VERSION 5.7 ;
  NOWIREEXTENSIONATPIN ON ;
  DIVIDERCHAR "/" ;
  BUSBITCHARS "[]" ;
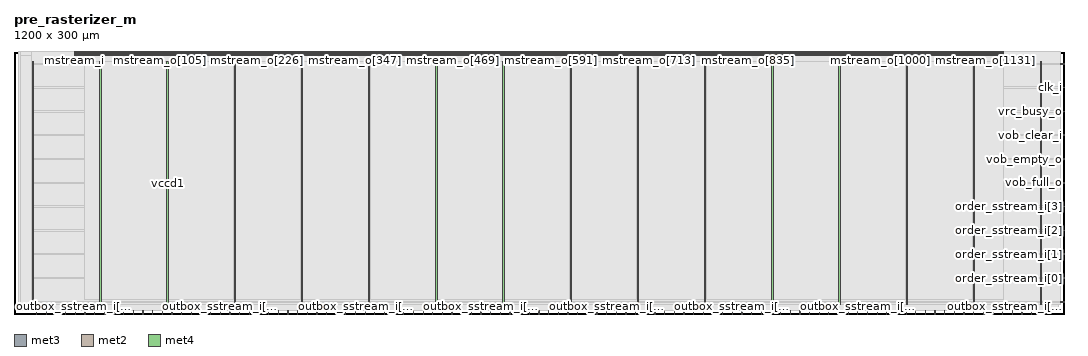
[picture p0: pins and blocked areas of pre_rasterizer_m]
MACRO pre_rasterizer_m
  CLASS BLOCK ;
  FOREIGN pre_rasterizer_m ;
  ORIGIN 0.000 0.000 ;
  SIZE 1200.000 BY 300.000 ;
  PIN clk_i
    DIRECTION INPUT ;
    USE SIGNAL ;
    ANTENNAGATEAREA 0.852000 ;
    ANTENNADIFFAREA 0.434700 ;
    PORT
      LAYER met3 ;
        RECT 1196.000 258.440 1200.000 259.040 ;
    END
  END clk_i
  PIN mstream_i
    DIRECTION INPUT ;
    USE SIGNAL ;
    ANTENNAGATEAREA 0.426000 ;
    PORT
      LAYER met2 ;
        RECT 69.090 296.000 69.370 300.000 ;
    END
  END mstream_i
  PIN mstream_o[0]
    DIRECTION OUTPUT TRISTATE ;
    USE SIGNAL ;
    ANTENNADIFFAREA 0.795200 ;
    PORT
      LAYER met2 ;
        RECT 70.010 296.000 70.290 300.000 ;
    END
  END mstream_o[0]
  PIN mstream_o[1000]
    DIRECTION OUTPUT TRISTATE ;
    USE SIGNAL ;
    ANTENNADIFFAREA 0.795200 ;
    PORT
      LAYER met2 ;
        RECT 990.010 296.000 990.290 300.000 ;
    END
  END mstream_o[1000]
  PIN mstream_o[1001]
    DIRECTION OUTPUT TRISTATE ;
    USE SIGNAL ;
    ANTENNADIFFAREA 0.795200 ;
    PORT
      LAYER met2 ;
        RECT 990.930 296.000 991.210 300.000 ;
    END
  END mstream_o[1001]
  PIN mstream_o[1002]
    DIRECTION OUTPUT TRISTATE ;
    USE SIGNAL ;
    ANTENNADIFFAREA 0.795200 ;
    PORT
      LAYER met2 ;
        RECT 991.850 296.000 992.130 300.000 ;
    END
  END mstream_o[1002]
  PIN mstream_o[1003]
    DIRECTION OUTPUT TRISTATE ;
    USE SIGNAL ;
    ANTENNADIFFAREA 0.795200 ;
    PORT
      LAYER met2 ;
        RECT 992.770 296.000 993.050 300.000 ;
    END
  END mstream_o[1003]
  PIN mstream_o[1004]
    DIRECTION OUTPUT TRISTATE ;
    USE SIGNAL ;
    ANTENNADIFFAREA 0.795200 ;
    PORT
      LAYER met2 ;
        RECT 993.690 296.000 993.970 300.000 ;
    END
  END mstream_o[1004]
  PIN mstream_o[1005]
    DIRECTION OUTPUT TRISTATE ;
    USE SIGNAL ;
    ANTENNADIFFAREA 0.795200 ;
    PORT
      LAYER met2 ;
        RECT 994.610 296.000 994.890 300.000 ;
    END
  END mstream_o[1005]
  PIN mstream_o[1006]
    DIRECTION OUTPUT TRISTATE ;
    USE SIGNAL ;
    ANTENNADIFFAREA 0.795200 ;
    PORT
      LAYER met2 ;
        RECT 995.530 296.000 995.810 300.000 ;
    END
  END mstream_o[1006]
  PIN mstream_o[1007]
    DIRECTION OUTPUT TRISTATE ;
    USE SIGNAL ;
    ANTENNADIFFAREA 0.795200 ;
    PORT
      LAYER met2 ;
        RECT 996.450 296.000 996.730 300.000 ;
    END
  END mstream_o[1007]
  PIN mstream_o[1008]
    DIRECTION OUTPUT TRISTATE ;
    USE SIGNAL ;
    ANTENNADIFFAREA 0.795200 ;
    PORT
      LAYER met2 ;
        RECT 997.370 296.000 997.650 300.000 ;
    END
  END mstream_o[1008]
  PIN mstream_o[1009]
    DIRECTION OUTPUT TRISTATE ;
    USE SIGNAL ;
    ANTENNADIFFAREA 0.795200 ;
    PORT
      LAYER met2 ;
        RECT 998.290 296.000 998.570 300.000 ;
    END
  END mstream_o[1009]
  PIN mstream_o[100]
    DIRECTION OUTPUT TRISTATE ;
    USE SIGNAL ;
    ANTENNADIFFAREA 0.795200 ;
    PORT
      LAYER met2 ;
        RECT 162.010 296.000 162.290 300.000 ;
    END
  END mstream_o[100]
  PIN mstream_o[1010]
    DIRECTION OUTPUT TRISTATE ;
    USE SIGNAL ;
    ANTENNADIFFAREA 0.795200 ;
    PORT
      LAYER met2 ;
        RECT 999.210 296.000 999.490 300.000 ;
    END
  END mstream_o[1010]
  PIN mstream_o[1011]
    DIRECTION OUTPUT TRISTATE ;
    USE SIGNAL ;
    ANTENNADIFFAREA 0.795200 ;
    PORT
      LAYER met2 ;
        RECT 1000.130 296.000 1000.410 300.000 ;
    END
  END mstream_o[1011]
  PIN mstream_o[1012]
    DIRECTION OUTPUT TRISTATE ;
    USE SIGNAL ;
    ANTENNADIFFAREA 0.795200 ;
    PORT
      LAYER met2 ;
        RECT 1001.050 296.000 1001.330 300.000 ;
    END
  END mstream_o[1012]
  PIN mstream_o[1013]
    DIRECTION OUTPUT TRISTATE ;
    USE SIGNAL ;
    ANTENNADIFFAREA 0.795200 ;
    PORT
      LAYER met2 ;
        RECT 1001.970 296.000 1002.250 300.000 ;
    END
  END mstream_o[1013]
  PIN mstream_o[1014]
    DIRECTION OUTPUT TRISTATE ;
    USE SIGNAL ;
    ANTENNADIFFAREA 0.795200 ;
    PORT
      LAYER met2 ;
        RECT 1002.890 296.000 1003.170 300.000 ;
    END
  END mstream_o[1014]
  PIN mstream_o[1015]
    DIRECTION OUTPUT TRISTATE ;
    USE SIGNAL ;
    ANTENNADIFFAREA 0.795200 ;
    PORT
      LAYER met2 ;
        RECT 1003.810 296.000 1004.090 300.000 ;
    END
  END mstream_o[1015]
  PIN mstream_o[1016]
    DIRECTION OUTPUT TRISTATE ;
    USE SIGNAL ;
    ANTENNADIFFAREA 0.795200 ;
    PORT
      LAYER met2 ;
        RECT 1004.730 296.000 1005.010 300.000 ;
    END
  END mstream_o[1016]
  PIN mstream_o[1017]
    DIRECTION OUTPUT TRISTATE ;
    USE SIGNAL ;
    ANTENNADIFFAREA 0.795200 ;
    PORT
      LAYER met2 ;
        RECT 1005.650 296.000 1005.930 300.000 ;
    END
  END mstream_o[1017]
  PIN mstream_o[1018]
    DIRECTION OUTPUT TRISTATE ;
    USE SIGNAL ;
    ANTENNADIFFAREA 0.795200 ;
    PORT
      LAYER met2 ;
        RECT 1006.570 296.000 1006.850 300.000 ;
    END
  END mstream_o[1018]
  PIN mstream_o[1019]
    DIRECTION OUTPUT TRISTATE ;
    USE SIGNAL ;
    ANTENNADIFFAREA 0.795200 ;
    PORT
      LAYER met2 ;
        RECT 1007.490 296.000 1007.770 300.000 ;
    END
  END mstream_o[1019]
  PIN mstream_o[101]
    DIRECTION OUTPUT TRISTATE ;
    USE SIGNAL ;
    ANTENNADIFFAREA 0.795200 ;
    PORT
      LAYER met2 ;
        RECT 162.930 296.000 163.210 300.000 ;
    END
  END mstream_o[101]
  PIN mstream_o[1020]
    DIRECTION OUTPUT TRISTATE ;
    USE SIGNAL ;
    ANTENNADIFFAREA 0.795200 ;
    PORT
      LAYER met2 ;
        RECT 1008.410 296.000 1008.690 300.000 ;
    END
  END mstream_o[1020]
  PIN mstream_o[1021]
    DIRECTION OUTPUT TRISTATE ;
    USE SIGNAL ;
    ANTENNADIFFAREA 0.795200 ;
    PORT
      LAYER met2 ;
        RECT 1009.330 296.000 1009.610 300.000 ;
    END
  END mstream_o[1021]
  PIN mstream_o[1022]
    DIRECTION OUTPUT TRISTATE ;
    USE SIGNAL ;
    ANTENNADIFFAREA 0.795200 ;
    PORT
      LAYER met2 ;
        RECT 1010.250 296.000 1010.530 300.000 ;
    END
  END mstream_o[1022]
  PIN mstream_o[1023]
    DIRECTION OUTPUT TRISTATE ;
    USE SIGNAL ;
    ANTENNADIFFAREA 0.795200 ;
    PORT
      LAYER met2 ;
        RECT 1011.170 296.000 1011.450 300.000 ;
    END
  END mstream_o[1023]
  PIN mstream_o[1024]
    DIRECTION OUTPUT TRISTATE ;
    USE SIGNAL ;
    ANTENNADIFFAREA 0.795200 ;
    PORT
      LAYER met2 ;
        RECT 1012.090 296.000 1012.370 300.000 ;
    END
  END mstream_o[1024]
  PIN mstream_o[1025]
    DIRECTION OUTPUT TRISTATE ;
    USE SIGNAL ;
    ANTENNADIFFAREA 0.795200 ;
    PORT
      LAYER met2 ;
        RECT 1013.010 296.000 1013.290 300.000 ;
    END
  END mstream_o[1025]
  PIN mstream_o[1026]
    DIRECTION OUTPUT TRISTATE ;
    USE SIGNAL ;
    ANTENNADIFFAREA 0.795200 ;
    PORT
      LAYER met2 ;
        RECT 1013.930 296.000 1014.210 300.000 ;
    END
  END mstream_o[1026]
  PIN mstream_o[1027]
    DIRECTION OUTPUT TRISTATE ;
    USE SIGNAL ;
    ANTENNADIFFAREA 0.795200 ;
    PORT
      LAYER met2 ;
        RECT 1014.850 296.000 1015.130 300.000 ;
    END
  END mstream_o[1027]
  PIN mstream_o[1028]
    DIRECTION OUTPUT TRISTATE ;
    USE SIGNAL ;
    ANTENNADIFFAREA 0.795200 ;
    PORT
      LAYER met2 ;
        RECT 1015.770 296.000 1016.050 300.000 ;
    END
  END mstream_o[1028]
  PIN mstream_o[1029]
    DIRECTION OUTPUT TRISTATE ;
    USE SIGNAL ;
    ANTENNADIFFAREA 0.795200 ;
    PORT
      LAYER met2 ;
        RECT 1016.690 296.000 1016.970 300.000 ;
    END
  END mstream_o[1029]
  PIN mstream_o[102]
    DIRECTION OUTPUT TRISTATE ;
    USE SIGNAL ;
    ANTENNADIFFAREA 0.795200 ;
    PORT
      LAYER met2 ;
        RECT 163.850 296.000 164.130 300.000 ;
    END
  END mstream_o[102]
  PIN mstream_o[1030]
    DIRECTION OUTPUT TRISTATE ;
    USE SIGNAL ;
    ANTENNADIFFAREA 0.795200 ;
    PORT
      LAYER met2 ;
        RECT 1017.610 296.000 1017.890 300.000 ;
    END
  END mstream_o[1030]
  PIN mstream_o[1031]
    DIRECTION OUTPUT TRISTATE ;
    USE SIGNAL ;
    ANTENNADIFFAREA 0.795200 ;
    PORT
      LAYER met2 ;
        RECT 1018.530 296.000 1018.810 300.000 ;
    END
  END mstream_o[1031]
  PIN mstream_o[1032]
    DIRECTION OUTPUT TRISTATE ;
    USE SIGNAL ;
    ANTENNADIFFAREA 0.795200 ;
    PORT
      LAYER met2 ;
        RECT 1019.450 296.000 1019.730 300.000 ;
    END
  END mstream_o[1032]
  PIN mstream_o[1033]
    DIRECTION OUTPUT TRISTATE ;
    USE SIGNAL ;
    ANTENNADIFFAREA 0.795200 ;
    PORT
      LAYER met2 ;
        RECT 1020.370 296.000 1020.650 300.000 ;
    END
  END mstream_o[1033]
  PIN mstream_o[1034]
    DIRECTION OUTPUT TRISTATE ;
    USE SIGNAL ;
    ANTENNADIFFAREA 0.795200 ;
    PORT
      LAYER met2 ;
        RECT 1021.290 296.000 1021.570 300.000 ;
    END
  END mstream_o[1034]
  PIN mstream_o[1035]
    DIRECTION OUTPUT TRISTATE ;
    USE SIGNAL ;
    ANTENNADIFFAREA 0.795200 ;
    PORT
      LAYER met2 ;
        RECT 1022.210 296.000 1022.490 300.000 ;
    END
  END mstream_o[1035]
  PIN mstream_o[1036]
    DIRECTION OUTPUT TRISTATE ;
    USE SIGNAL ;
    ANTENNADIFFAREA 0.795200 ;
    PORT
      LAYER met2 ;
        RECT 1023.130 296.000 1023.410 300.000 ;
    END
  END mstream_o[1036]
  PIN mstream_o[1037]
    DIRECTION OUTPUT TRISTATE ;
    USE SIGNAL ;
    ANTENNADIFFAREA 0.795200 ;
    PORT
      LAYER met2 ;
        RECT 1024.050 296.000 1024.330 300.000 ;
    END
  END mstream_o[1037]
  PIN mstream_o[1038]
    DIRECTION OUTPUT TRISTATE ;
    USE SIGNAL ;
    ANTENNADIFFAREA 0.795200 ;
    PORT
      LAYER met2 ;
        RECT 1024.970 296.000 1025.250 300.000 ;
    END
  END mstream_o[1038]
  PIN mstream_o[1039]
    DIRECTION OUTPUT TRISTATE ;
    USE SIGNAL ;
    ANTENNADIFFAREA 0.795200 ;
    PORT
      LAYER met2 ;
        RECT 1025.890 296.000 1026.170 300.000 ;
    END
  END mstream_o[1039]
  PIN mstream_o[103]
    DIRECTION OUTPUT TRISTATE ;
    USE SIGNAL ;
    ANTENNADIFFAREA 0.795200 ;
    PORT
      LAYER met2 ;
        RECT 164.770 296.000 165.050 300.000 ;
    END
  END mstream_o[103]
  PIN mstream_o[1040]
    DIRECTION OUTPUT TRISTATE ;
    USE SIGNAL ;
    ANTENNADIFFAREA 0.795200 ;
    PORT
      LAYER met2 ;
        RECT 1026.810 296.000 1027.090 300.000 ;
    END
  END mstream_o[1040]
  PIN mstream_o[1041]
    DIRECTION OUTPUT TRISTATE ;
    USE SIGNAL ;
    ANTENNADIFFAREA 0.795200 ;
    PORT
      LAYER met2 ;
        RECT 1027.730 296.000 1028.010 300.000 ;
    END
  END mstream_o[1041]
  PIN mstream_o[1042]
    DIRECTION OUTPUT TRISTATE ;
    USE SIGNAL ;
    ANTENNADIFFAREA 0.795200 ;
    PORT
      LAYER met2 ;
        RECT 1028.650 296.000 1028.930 300.000 ;
    END
  END mstream_o[1042]
  PIN mstream_o[1043]
    DIRECTION OUTPUT TRISTATE ;
    USE SIGNAL ;
    ANTENNADIFFAREA 0.795200 ;
    PORT
      LAYER met2 ;
        RECT 1029.570 296.000 1029.850 300.000 ;
    END
  END mstream_o[1043]
  PIN mstream_o[1044]
    DIRECTION OUTPUT TRISTATE ;
    USE SIGNAL ;
    ANTENNADIFFAREA 0.795200 ;
    PORT
      LAYER met2 ;
        RECT 1030.490 296.000 1030.770 300.000 ;
    END
  END mstream_o[1044]
  PIN mstream_o[1045]
    DIRECTION OUTPUT TRISTATE ;
    USE SIGNAL ;
    ANTENNADIFFAREA 0.795200 ;
    PORT
      LAYER met2 ;
        RECT 1031.410 296.000 1031.690 300.000 ;
    END
  END mstream_o[1045]
  PIN mstream_o[1046]
    DIRECTION OUTPUT TRISTATE ;
    USE SIGNAL ;
    ANTENNADIFFAREA 0.795200 ;
    PORT
      LAYER met2 ;
        RECT 1032.330 296.000 1032.610 300.000 ;
    END
  END mstream_o[1046]
  PIN mstream_o[1047]
    DIRECTION OUTPUT TRISTATE ;
    USE SIGNAL ;
    ANTENNADIFFAREA 0.795200 ;
    PORT
      LAYER met2 ;
        RECT 1033.250 296.000 1033.530 300.000 ;
    END
  END mstream_o[1047]
  PIN mstream_o[1048]
    DIRECTION OUTPUT TRISTATE ;
    USE SIGNAL ;
    ANTENNADIFFAREA 0.795200 ;
    PORT
      LAYER met2 ;
        RECT 1034.170 296.000 1034.450 300.000 ;
    END
  END mstream_o[1048]
  PIN mstream_o[1049]
    DIRECTION OUTPUT TRISTATE ;
    USE SIGNAL ;
    ANTENNADIFFAREA 0.795200 ;
    PORT
      LAYER met2 ;
        RECT 1035.090 296.000 1035.370 300.000 ;
    END
  END mstream_o[1049]
  PIN mstream_o[104]
    DIRECTION OUTPUT TRISTATE ;
    USE SIGNAL ;
    ANTENNADIFFAREA 0.795200 ;
    PORT
      LAYER met2 ;
        RECT 165.690 296.000 165.970 300.000 ;
    END
  END mstream_o[104]
  PIN mstream_o[1050]
    DIRECTION OUTPUT TRISTATE ;
    USE SIGNAL ;
    ANTENNADIFFAREA 0.795200 ;
    PORT
      LAYER met2 ;
        RECT 1036.010 296.000 1036.290 300.000 ;
    END
  END mstream_o[1050]
  PIN mstream_o[1051]
    DIRECTION OUTPUT TRISTATE ;
    USE SIGNAL ;
    ANTENNADIFFAREA 0.795200 ;
    PORT
      LAYER met2 ;
        RECT 1036.930 296.000 1037.210 300.000 ;
    END
  END mstream_o[1051]
  PIN mstream_o[1052]
    DIRECTION OUTPUT TRISTATE ;
    USE SIGNAL ;
    ANTENNADIFFAREA 0.795200 ;
    PORT
      LAYER met2 ;
        RECT 1037.850 296.000 1038.130 300.000 ;
    END
  END mstream_o[1052]
  PIN mstream_o[1053]
    DIRECTION OUTPUT TRISTATE ;
    USE SIGNAL ;
    ANTENNADIFFAREA 0.795200 ;
    PORT
      LAYER met2 ;
        RECT 1038.770 296.000 1039.050 300.000 ;
    END
  END mstream_o[1053]
  PIN mstream_o[1054]
    DIRECTION OUTPUT TRISTATE ;
    USE SIGNAL ;
    ANTENNADIFFAREA 0.795200 ;
    PORT
      LAYER met2 ;
        RECT 1039.690 296.000 1039.970 300.000 ;
    END
  END mstream_o[1054]
  PIN mstream_o[1055]
    DIRECTION OUTPUT TRISTATE ;
    USE SIGNAL ;
    ANTENNADIFFAREA 0.795200 ;
    PORT
      LAYER met2 ;
        RECT 1040.610 296.000 1040.890 300.000 ;
    END
  END mstream_o[1055]
  PIN mstream_o[1056]
    DIRECTION OUTPUT TRISTATE ;
    USE SIGNAL ;
    ANTENNADIFFAREA 0.795200 ;
    PORT
      LAYER met2 ;
        RECT 1041.530 296.000 1041.810 300.000 ;
    END
  END mstream_o[1056]
  PIN mstream_o[1057]
    DIRECTION OUTPUT TRISTATE ;
    USE SIGNAL ;
    ANTENNADIFFAREA 0.795200 ;
    PORT
      LAYER met2 ;
        RECT 1042.450 296.000 1042.730 300.000 ;
    END
  END mstream_o[1057]
  PIN mstream_o[1058]
    DIRECTION OUTPUT TRISTATE ;
    USE SIGNAL ;
    ANTENNADIFFAREA 0.795200 ;
    PORT
      LAYER met2 ;
        RECT 1043.370 296.000 1043.650 300.000 ;
    END
  END mstream_o[1058]
  PIN mstream_o[1059]
    DIRECTION OUTPUT TRISTATE ;
    USE SIGNAL ;
    ANTENNADIFFAREA 0.795200 ;
    PORT
      LAYER met2 ;
        RECT 1044.290 296.000 1044.570 300.000 ;
    END
  END mstream_o[1059]
  PIN mstream_o[105]
    DIRECTION OUTPUT TRISTATE ;
    USE SIGNAL ;
    ANTENNADIFFAREA 0.795200 ;
    PORT
      LAYER met2 ;
        RECT 166.610 296.000 166.890 300.000 ;
    END
  END mstream_o[105]
  PIN mstream_o[1060]
    DIRECTION OUTPUT TRISTATE ;
    USE SIGNAL ;
    ANTENNADIFFAREA 0.795200 ;
    PORT
      LAYER met2 ;
        RECT 1045.210 296.000 1045.490 300.000 ;
    END
  END mstream_o[1060]
  PIN mstream_o[1061]
    DIRECTION OUTPUT TRISTATE ;
    USE SIGNAL ;
    ANTENNADIFFAREA 0.795200 ;
    PORT
      LAYER met2 ;
        RECT 1046.130 296.000 1046.410 300.000 ;
    END
  END mstream_o[1061]
  PIN mstream_o[1062]
    DIRECTION OUTPUT TRISTATE ;
    USE SIGNAL ;
    ANTENNADIFFAREA 0.795200 ;
    PORT
      LAYER met2 ;
        RECT 1047.050 296.000 1047.330 300.000 ;
    END
  END mstream_o[1062]
  PIN mstream_o[1063]
    DIRECTION OUTPUT TRISTATE ;
    USE SIGNAL ;
    ANTENNADIFFAREA 0.795200 ;
    PORT
      LAYER met2 ;
        RECT 1047.970 296.000 1048.250 300.000 ;
    END
  END mstream_o[1063]
  PIN mstream_o[1064]
    DIRECTION OUTPUT TRISTATE ;
    USE SIGNAL ;
    ANTENNADIFFAREA 0.795200 ;
    PORT
      LAYER met2 ;
        RECT 1048.890 296.000 1049.170 300.000 ;
    END
  END mstream_o[1064]
  PIN mstream_o[1065]
    DIRECTION OUTPUT TRISTATE ;
    USE SIGNAL ;
    ANTENNADIFFAREA 0.795200 ;
    PORT
      LAYER met2 ;
        RECT 1049.810 296.000 1050.090 300.000 ;
    END
  END mstream_o[1065]
  PIN mstream_o[1066]
    DIRECTION OUTPUT TRISTATE ;
    USE SIGNAL ;
    ANTENNADIFFAREA 0.795200 ;
    PORT
      LAYER met2 ;
        RECT 1050.730 296.000 1051.010 300.000 ;
    END
  END mstream_o[1066]
  PIN mstream_o[1067]
    DIRECTION OUTPUT TRISTATE ;
    USE SIGNAL ;
    ANTENNADIFFAREA 0.795200 ;
    PORT
      LAYER met2 ;
        RECT 1051.650 296.000 1051.930 300.000 ;
    END
  END mstream_o[1067]
  PIN mstream_o[1068]
    DIRECTION OUTPUT TRISTATE ;
    USE SIGNAL ;
    ANTENNADIFFAREA 0.795200 ;
    PORT
      LAYER met2 ;
        RECT 1052.570 296.000 1052.850 300.000 ;
    END
  END mstream_o[1068]
  PIN mstream_o[1069]
    DIRECTION OUTPUT TRISTATE ;
    USE SIGNAL ;
    ANTENNADIFFAREA 0.795200 ;
    PORT
      LAYER met2 ;
        RECT 1053.490 296.000 1053.770 300.000 ;
    END
  END mstream_o[1069]
  PIN mstream_o[106]
    DIRECTION OUTPUT TRISTATE ;
    USE SIGNAL ;
    ANTENNADIFFAREA 0.795200 ;
    PORT
      LAYER met2 ;
        RECT 167.530 296.000 167.810 300.000 ;
    END
  END mstream_o[106]
  PIN mstream_o[1070]
    DIRECTION OUTPUT TRISTATE ;
    USE SIGNAL ;
    ANTENNADIFFAREA 0.795200 ;
    PORT
      LAYER met2 ;
        RECT 1054.410 296.000 1054.690 300.000 ;
    END
  END mstream_o[1070]
  PIN mstream_o[1071]
    DIRECTION OUTPUT TRISTATE ;
    USE SIGNAL ;
    ANTENNADIFFAREA 0.795200 ;
    PORT
      LAYER met2 ;
        RECT 1055.330 296.000 1055.610 300.000 ;
    END
  END mstream_o[1071]
  PIN mstream_o[1072]
    DIRECTION OUTPUT TRISTATE ;
    USE SIGNAL ;
    ANTENNADIFFAREA 0.795200 ;
    PORT
      LAYER met2 ;
        RECT 1056.250 296.000 1056.530 300.000 ;
    END
  END mstream_o[1072]
  PIN mstream_o[1073]
    DIRECTION OUTPUT TRISTATE ;
    USE SIGNAL ;
    ANTENNADIFFAREA 0.795200 ;
    PORT
      LAYER met2 ;
        RECT 1057.170 296.000 1057.450 300.000 ;
    END
  END mstream_o[1073]
  PIN mstream_o[1074]
    DIRECTION OUTPUT TRISTATE ;
    USE SIGNAL ;
    ANTENNADIFFAREA 0.795200 ;
    PORT
      LAYER met2 ;
        RECT 1058.090 296.000 1058.370 300.000 ;
    END
  END mstream_o[1074]
  PIN mstream_o[1075]
    DIRECTION OUTPUT TRISTATE ;
    USE SIGNAL ;
    ANTENNADIFFAREA 0.795200 ;
    PORT
      LAYER met2 ;
        RECT 1059.010 296.000 1059.290 300.000 ;
    END
  END mstream_o[1075]
  PIN mstream_o[1076]
    DIRECTION OUTPUT TRISTATE ;
    USE SIGNAL ;
    ANTENNADIFFAREA 0.795200 ;
    PORT
      LAYER met2 ;
        RECT 1059.930 296.000 1060.210 300.000 ;
    END
  END mstream_o[1076]
  PIN mstream_o[1077]
    DIRECTION OUTPUT TRISTATE ;
    USE SIGNAL ;
    ANTENNADIFFAREA 0.795200 ;
    PORT
      LAYER met2 ;
        RECT 1060.850 296.000 1061.130 300.000 ;
    END
  END mstream_o[1077]
  PIN mstream_o[1078]
    DIRECTION OUTPUT TRISTATE ;
    USE SIGNAL ;
    ANTENNADIFFAREA 0.795200 ;
    PORT
      LAYER met2 ;
        RECT 1061.770 296.000 1062.050 300.000 ;
    END
  END mstream_o[1078]
  PIN mstream_o[1079]
    DIRECTION OUTPUT TRISTATE ;
    USE SIGNAL ;
    ANTENNADIFFAREA 0.795200 ;
    PORT
      LAYER met2 ;
        RECT 1062.690 296.000 1062.970 300.000 ;
    END
  END mstream_o[1079]
  PIN mstream_o[107]
    DIRECTION OUTPUT TRISTATE ;
    USE SIGNAL ;
    ANTENNADIFFAREA 0.795200 ;
    PORT
      LAYER met2 ;
        RECT 168.450 296.000 168.730 300.000 ;
    END
  END mstream_o[107]
  PIN mstream_o[1080]
    DIRECTION OUTPUT TRISTATE ;
    USE SIGNAL ;
    ANTENNADIFFAREA 0.795200 ;
    PORT
      LAYER met2 ;
        RECT 1063.610 296.000 1063.890 300.000 ;
    END
  END mstream_o[1080]
  PIN mstream_o[1081]
    DIRECTION OUTPUT TRISTATE ;
    USE SIGNAL ;
    ANTENNADIFFAREA 0.795200 ;
    PORT
      LAYER met2 ;
        RECT 1064.530 296.000 1064.810 300.000 ;
    END
  END mstream_o[1081]
  PIN mstream_o[1082]
    DIRECTION OUTPUT TRISTATE ;
    USE SIGNAL ;
    ANTENNADIFFAREA 0.795200 ;
    PORT
      LAYER met2 ;
        RECT 1065.450 296.000 1065.730 300.000 ;
    END
  END mstream_o[1082]
  PIN mstream_o[1083]
    DIRECTION OUTPUT TRISTATE ;
    USE SIGNAL ;
    ANTENNADIFFAREA 0.795200 ;
    PORT
      LAYER met2 ;
        RECT 1066.370 296.000 1066.650 300.000 ;
    END
  END mstream_o[1083]
  PIN mstream_o[1084]
    DIRECTION OUTPUT TRISTATE ;
    USE SIGNAL ;
    ANTENNADIFFAREA 0.795200 ;
    PORT
      LAYER met2 ;
        RECT 1067.290 296.000 1067.570 300.000 ;
    END
  END mstream_o[1084]
  PIN mstream_o[1085]
    DIRECTION OUTPUT TRISTATE ;
    USE SIGNAL ;
    ANTENNADIFFAREA 0.795200 ;
    PORT
      LAYER met2 ;
        RECT 1068.210 296.000 1068.490 300.000 ;
    END
  END mstream_o[1085]
  PIN mstream_o[1086]
    DIRECTION OUTPUT TRISTATE ;
    USE SIGNAL ;
    ANTENNADIFFAREA 0.795200 ;
    PORT
      LAYER met2 ;
        RECT 1069.130 296.000 1069.410 300.000 ;
    END
  END mstream_o[1086]
  PIN mstream_o[1087]
    DIRECTION OUTPUT TRISTATE ;
    USE SIGNAL ;
    ANTENNADIFFAREA 0.795200 ;
    PORT
      LAYER met2 ;
        RECT 1070.050 296.000 1070.330 300.000 ;
    END
  END mstream_o[1087]
  PIN mstream_o[1088]
    DIRECTION OUTPUT TRISTATE ;
    USE SIGNAL ;
    ANTENNADIFFAREA 0.795200 ;
    PORT
      LAYER met2 ;
        RECT 1070.970 296.000 1071.250 300.000 ;
    END
  END mstream_o[1088]
  PIN mstream_o[1089]
    DIRECTION OUTPUT TRISTATE ;
    USE SIGNAL ;
    ANTENNADIFFAREA 0.795200 ;
    PORT
      LAYER met2 ;
        RECT 1071.890 296.000 1072.170 300.000 ;
    END
  END mstream_o[1089]
  PIN mstream_o[108]
    DIRECTION OUTPUT TRISTATE ;
    USE SIGNAL ;
    ANTENNADIFFAREA 0.795200 ;
    PORT
      LAYER met2 ;
        RECT 169.370 296.000 169.650 300.000 ;
    END
  END mstream_o[108]
  PIN mstream_o[1090]
    DIRECTION OUTPUT TRISTATE ;
    USE SIGNAL ;
    ANTENNADIFFAREA 0.795200 ;
    PORT
      LAYER met2 ;
        RECT 1072.810 296.000 1073.090 300.000 ;
    END
  END mstream_o[1090]
  PIN mstream_o[1091]
    DIRECTION OUTPUT TRISTATE ;
    USE SIGNAL ;
    ANTENNADIFFAREA 0.795200 ;
    PORT
      LAYER met2 ;
        RECT 1073.730 296.000 1074.010 300.000 ;
    END
  END mstream_o[1091]
  PIN mstream_o[1092]
    DIRECTION OUTPUT TRISTATE ;
    USE SIGNAL ;
    ANTENNADIFFAREA 0.795200 ;
    PORT
      LAYER met2 ;
        RECT 1074.650 296.000 1074.930 300.000 ;
    END
  END mstream_o[1092]
  PIN mstream_o[1093]
    DIRECTION OUTPUT TRISTATE ;
    USE SIGNAL ;
    ANTENNADIFFAREA 0.795200 ;
    PORT
      LAYER met2 ;
        RECT 1075.570 296.000 1075.850 300.000 ;
    END
  END mstream_o[1093]
  PIN mstream_o[1094]
    DIRECTION OUTPUT TRISTATE ;
    USE SIGNAL ;
    ANTENNADIFFAREA 0.795200 ;
    PORT
      LAYER met2 ;
        RECT 1076.490 296.000 1076.770 300.000 ;
    END
  END mstream_o[1094]
  PIN mstream_o[1095]
    DIRECTION OUTPUT TRISTATE ;
    USE SIGNAL ;
    ANTENNADIFFAREA 0.795200 ;
    PORT
      LAYER met2 ;
        RECT 1077.410 296.000 1077.690 300.000 ;
    END
  END mstream_o[1095]
  PIN mstream_o[1096]
    DIRECTION OUTPUT TRISTATE ;
    USE SIGNAL ;
    ANTENNADIFFAREA 0.795200 ;
    PORT
      LAYER met2 ;
        RECT 1078.330 296.000 1078.610 300.000 ;
    END
  END mstream_o[1096]
  PIN mstream_o[1097]
    DIRECTION OUTPUT TRISTATE ;
    USE SIGNAL ;
    ANTENNADIFFAREA 0.795200 ;
    PORT
      LAYER met2 ;
        RECT 1079.250 296.000 1079.530 300.000 ;
    END
  END mstream_o[1097]
  PIN mstream_o[1098]
    DIRECTION OUTPUT TRISTATE ;
    USE SIGNAL ;
    ANTENNADIFFAREA 0.795200 ;
    PORT
      LAYER met2 ;
        RECT 1080.170 296.000 1080.450 300.000 ;
    END
  END mstream_o[1098]
  PIN mstream_o[1099]
    DIRECTION OUTPUT TRISTATE ;
    USE SIGNAL ;
    ANTENNADIFFAREA 0.795200 ;
    PORT
      LAYER met2 ;
        RECT 1081.090 296.000 1081.370 300.000 ;
    END
  END mstream_o[1099]
  PIN mstream_o[109]
    DIRECTION OUTPUT TRISTATE ;
    USE SIGNAL ;
    ANTENNADIFFAREA 0.795200 ;
    PORT
      LAYER met2 ;
        RECT 170.290 296.000 170.570 300.000 ;
    END
  END mstream_o[109]
  PIN mstream_o[10]
    DIRECTION OUTPUT TRISTATE ;
    USE SIGNAL ;
    ANTENNADIFFAREA 0.795200 ;
    PORT
      LAYER met2 ;
        RECT 79.210 296.000 79.490 300.000 ;
    END
  END mstream_o[10]
  PIN mstream_o[1100]
    DIRECTION OUTPUT TRISTATE ;
    USE SIGNAL ;
    ANTENNADIFFAREA 0.795200 ;
    PORT
      LAYER met2 ;
        RECT 1082.010 296.000 1082.290 300.000 ;
    END
  END mstream_o[1100]
  PIN mstream_o[1101]
    DIRECTION OUTPUT TRISTATE ;
    USE SIGNAL ;
    ANTENNADIFFAREA 0.795200 ;
    PORT
      LAYER met2 ;
        RECT 1082.930 296.000 1083.210 300.000 ;
    END
  END mstream_o[1101]
  PIN mstream_o[1102]
    DIRECTION OUTPUT TRISTATE ;
    USE SIGNAL ;
    ANTENNADIFFAREA 0.795200 ;
    PORT
      LAYER met2 ;
        RECT 1083.850 296.000 1084.130 300.000 ;
    END
  END mstream_o[1102]
  PIN mstream_o[1103]
    DIRECTION OUTPUT TRISTATE ;
    USE SIGNAL ;
    ANTENNADIFFAREA 0.795200 ;
    PORT
      LAYER met2 ;
        RECT 1084.770 296.000 1085.050 300.000 ;
    END
  END mstream_o[1103]
  PIN mstream_o[1104]
    DIRECTION OUTPUT TRISTATE ;
    USE SIGNAL ;
    ANTENNADIFFAREA 0.795200 ;
    PORT
      LAYER met2 ;
        RECT 1085.690 296.000 1085.970 300.000 ;
    END
  END mstream_o[1104]
  PIN mstream_o[1105]
    DIRECTION OUTPUT TRISTATE ;
    USE SIGNAL ;
    ANTENNADIFFAREA 0.795200 ;
    PORT
      LAYER met2 ;
        RECT 1086.610 296.000 1086.890 300.000 ;
    END
  END mstream_o[1105]
  PIN mstream_o[1106]
    DIRECTION OUTPUT TRISTATE ;
    USE SIGNAL ;
    ANTENNADIFFAREA 0.795200 ;
    PORT
      LAYER met2 ;
        RECT 1087.530 296.000 1087.810 300.000 ;
    END
  END mstream_o[1106]
  PIN mstream_o[1107]
    DIRECTION OUTPUT TRISTATE ;
    USE SIGNAL ;
    ANTENNADIFFAREA 0.795200 ;
    PORT
      LAYER met2 ;
        RECT 1088.450 296.000 1088.730 300.000 ;
    END
  END mstream_o[1107]
  PIN mstream_o[1108]
    DIRECTION OUTPUT TRISTATE ;
    USE SIGNAL ;
    ANTENNADIFFAREA 0.795200 ;
    PORT
      LAYER met2 ;
        RECT 1089.370 296.000 1089.650 300.000 ;
    END
  END mstream_o[1108]
  PIN mstream_o[1109]
    DIRECTION OUTPUT TRISTATE ;
    USE SIGNAL ;
    ANTENNADIFFAREA 0.795200 ;
    PORT
      LAYER met2 ;
        RECT 1090.290 296.000 1090.570 300.000 ;
    END
  END mstream_o[1109]
  PIN mstream_o[110]
    DIRECTION OUTPUT TRISTATE ;
    USE SIGNAL ;
    ANTENNADIFFAREA 0.795200 ;
    PORT
      LAYER met2 ;
        RECT 171.210 296.000 171.490 300.000 ;
    END
  END mstream_o[110]
  PIN mstream_o[1110]
    DIRECTION OUTPUT TRISTATE ;
    USE SIGNAL ;
    ANTENNADIFFAREA 0.795200 ;
    PORT
      LAYER met2 ;
        RECT 1091.210 296.000 1091.490 300.000 ;
    END
  END mstream_o[1110]
  PIN mstream_o[1111]
    DIRECTION OUTPUT TRISTATE ;
    USE SIGNAL ;
    ANTENNADIFFAREA 0.795200 ;
    PORT
      LAYER met2 ;
        RECT 1092.130 296.000 1092.410 300.000 ;
    END
  END mstream_o[1111]
  PIN mstream_o[1112]
    DIRECTION OUTPUT TRISTATE ;
    USE SIGNAL ;
    ANTENNADIFFAREA 0.795200 ;
    PORT
      LAYER met2 ;
        RECT 1093.050 296.000 1093.330 300.000 ;
    END
  END mstream_o[1112]
  PIN mstream_o[1113]
    DIRECTION OUTPUT TRISTATE ;
    USE SIGNAL ;
    ANTENNADIFFAREA 0.795200 ;
    PORT
      LAYER met2 ;
        RECT 1093.970 296.000 1094.250 300.000 ;
    END
  END mstream_o[1113]
  PIN mstream_o[1114]
    DIRECTION OUTPUT TRISTATE ;
    USE SIGNAL ;
    ANTENNADIFFAREA 0.795200 ;
    PORT
      LAYER met2 ;
        RECT 1094.890 296.000 1095.170 300.000 ;
    END
  END mstream_o[1114]
  PIN mstream_o[1115]
    DIRECTION OUTPUT TRISTATE ;
    USE SIGNAL ;
    ANTENNADIFFAREA 0.795200 ;
    PORT
      LAYER met2 ;
        RECT 1095.810 296.000 1096.090 300.000 ;
    END
  END mstream_o[1115]
  PIN mstream_o[1116]
    DIRECTION OUTPUT TRISTATE ;
    USE SIGNAL ;
    ANTENNADIFFAREA 0.795200 ;
    PORT
      LAYER met2 ;
        RECT 1096.730 296.000 1097.010 300.000 ;
    END
  END mstream_o[1116]
  PIN mstream_o[1117]
    DIRECTION OUTPUT TRISTATE ;
    USE SIGNAL ;
    ANTENNADIFFAREA 0.795200 ;
    PORT
      LAYER met2 ;
        RECT 1097.650 296.000 1097.930 300.000 ;
    END
  END mstream_o[1117]
  PIN mstream_o[1118]
    DIRECTION OUTPUT TRISTATE ;
    USE SIGNAL ;
    ANTENNADIFFAREA 0.795200 ;
    PORT
      LAYER met2 ;
        RECT 1098.570 296.000 1098.850 300.000 ;
    END
  END mstream_o[1118]
  PIN mstream_o[1119]
    DIRECTION OUTPUT TRISTATE ;
    USE SIGNAL ;
    ANTENNADIFFAREA 0.795200 ;
    PORT
      LAYER met2 ;
        RECT 1099.490 296.000 1099.770 300.000 ;
    END
  END mstream_o[1119]
  PIN mstream_o[111]
    DIRECTION OUTPUT TRISTATE ;
    USE SIGNAL ;
    ANTENNADIFFAREA 0.795200 ;
    PORT
      LAYER met2 ;
        RECT 172.130 296.000 172.410 300.000 ;
    END
  END mstream_o[111]
  PIN mstream_o[1120]
    DIRECTION OUTPUT TRISTATE ;
    USE SIGNAL ;
    ANTENNADIFFAREA 0.795200 ;
    PORT
      LAYER met2 ;
        RECT 1100.410 296.000 1100.690 300.000 ;
    END
  END mstream_o[1120]
  PIN mstream_o[1121]
    DIRECTION OUTPUT TRISTATE ;
    USE SIGNAL ;
    ANTENNADIFFAREA 0.795200 ;
    PORT
      LAYER met2 ;
        RECT 1101.330 296.000 1101.610 300.000 ;
    END
  END mstream_o[1121]
  PIN mstream_o[1122]
    DIRECTION OUTPUT TRISTATE ;
    USE SIGNAL ;
    ANTENNADIFFAREA 0.795200 ;
    PORT
      LAYER met2 ;
        RECT 1102.250 296.000 1102.530 300.000 ;
    END
  END mstream_o[1122]
  PIN mstream_o[1123]
    DIRECTION OUTPUT TRISTATE ;
    USE SIGNAL ;
    ANTENNADIFFAREA 0.795200 ;
    PORT
      LAYER met2 ;
        RECT 1103.170 296.000 1103.450 300.000 ;
    END
  END mstream_o[1123]
  PIN mstream_o[1124]
    DIRECTION OUTPUT TRISTATE ;
    USE SIGNAL ;
    ANTENNADIFFAREA 0.795200 ;
    PORT
      LAYER met2 ;
        RECT 1104.090 296.000 1104.370 300.000 ;
    END
  END mstream_o[1124]
  PIN mstream_o[1125]
    DIRECTION OUTPUT TRISTATE ;
    USE SIGNAL ;
    ANTENNADIFFAREA 0.795200 ;
    PORT
      LAYER met2 ;
        RECT 1105.010 296.000 1105.290 300.000 ;
    END
  END mstream_o[1125]
  PIN mstream_o[1126]
    DIRECTION OUTPUT TRISTATE ;
    USE SIGNAL ;
    ANTENNADIFFAREA 0.795200 ;
    PORT
      LAYER met2 ;
        RECT 1105.930 296.000 1106.210 300.000 ;
    END
  END mstream_o[1126]
  PIN mstream_o[1127]
    DIRECTION OUTPUT TRISTATE ;
    USE SIGNAL ;
    ANTENNADIFFAREA 0.795200 ;
    PORT
      LAYER met2 ;
        RECT 1106.850 296.000 1107.130 300.000 ;
    END
  END mstream_o[1127]
  PIN mstream_o[1128]
    DIRECTION OUTPUT TRISTATE ;
    USE SIGNAL ;
    ANTENNADIFFAREA 0.795200 ;
    PORT
      LAYER met2 ;
        RECT 1107.770 296.000 1108.050 300.000 ;
    END
  END mstream_o[1128]
  PIN mstream_o[1129]
    DIRECTION OUTPUT TRISTATE ;
    USE SIGNAL ;
    ANTENNADIFFAREA 0.795200 ;
    PORT
      LAYER met2 ;
        RECT 1108.690 296.000 1108.970 300.000 ;
    END
  END mstream_o[1129]
  PIN mstream_o[112]
    DIRECTION OUTPUT TRISTATE ;
    USE SIGNAL ;
    ANTENNADIFFAREA 0.795200 ;
    PORT
      LAYER met2 ;
        RECT 173.050 296.000 173.330 300.000 ;
    END
  END mstream_o[112]
  PIN mstream_o[1130]
    DIRECTION OUTPUT TRISTATE ;
    USE SIGNAL ;
    ANTENNADIFFAREA 0.795200 ;
    PORT
      LAYER met2 ;
        RECT 1109.610 296.000 1109.890 300.000 ;
    END
  END mstream_o[1130]
  PIN mstream_o[1131]
    DIRECTION OUTPUT TRISTATE ;
    USE SIGNAL ;
    ANTENNADIFFAREA 0.795200 ;
    PORT
      LAYER met2 ;
        RECT 1110.530 296.000 1110.810 300.000 ;
    END
  END mstream_o[1131]
  PIN mstream_o[1132]
    DIRECTION OUTPUT TRISTATE ;
    USE SIGNAL ;
    ANTENNADIFFAREA 0.795200 ;
    PORT
      LAYER met2 ;
        RECT 1111.450 296.000 1111.730 300.000 ;
    END
  END mstream_o[1132]
  PIN mstream_o[1133]
    DIRECTION OUTPUT TRISTATE ;
    USE SIGNAL ;
    ANTENNADIFFAREA 0.795200 ;
    PORT
      LAYER met2 ;
        RECT 1112.370 296.000 1112.650 300.000 ;
    END
  END mstream_o[1133]
  PIN mstream_o[1134]
    DIRECTION OUTPUT TRISTATE ;
    USE SIGNAL ;
    ANTENNADIFFAREA 0.795200 ;
    PORT
      LAYER met2 ;
        RECT 1113.290 296.000 1113.570 300.000 ;
    END
  END mstream_o[1134]
  PIN mstream_o[1135]
    DIRECTION OUTPUT TRISTATE ;
    USE SIGNAL ;
    ANTENNADIFFAREA 0.795200 ;
    PORT
      LAYER met2 ;
        RECT 1114.210 296.000 1114.490 300.000 ;
    END
  END mstream_o[1135]
  PIN mstream_o[1136]
    DIRECTION OUTPUT TRISTATE ;
    USE SIGNAL ;
    ANTENNADIFFAREA 0.795200 ;
    PORT
      LAYER met2 ;
        RECT 1115.130 296.000 1115.410 300.000 ;
    END
  END mstream_o[1136]
  PIN mstream_o[1137]
    DIRECTION OUTPUT TRISTATE ;
    USE SIGNAL ;
    ANTENNADIFFAREA 0.795200 ;
    PORT
      LAYER met2 ;
        RECT 1116.050 296.000 1116.330 300.000 ;
    END
  END mstream_o[1137]
  PIN mstream_o[1138]
    DIRECTION OUTPUT TRISTATE ;
    USE SIGNAL ;
    ANTENNADIFFAREA 0.795200 ;
    PORT
      LAYER met2 ;
        RECT 1116.970 296.000 1117.250 300.000 ;
    END
  END mstream_o[1138]
  PIN mstream_o[1139]
    DIRECTION OUTPUT TRISTATE ;
    USE SIGNAL ;
    ANTENNADIFFAREA 0.795200 ;
    PORT
      LAYER met2 ;
        RECT 1117.890 296.000 1118.170 300.000 ;
    END
  END mstream_o[1139]
  PIN mstream_o[113]
    DIRECTION OUTPUT TRISTATE ;
    USE SIGNAL ;
    ANTENNADIFFAREA 0.795200 ;
    PORT
      LAYER met2 ;
        RECT 173.970 296.000 174.250 300.000 ;
    END
  END mstream_o[113]
  PIN mstream_o[1140]
    DIRECTION OUTPUT TRISTATE ;
    USE SIGNAL ;
    ANTENNADIFFAREA 0.795200 ;
    PORT
      LAYER met2 ;
        RECT 1118.810 296.000 1119.090 300.000 ;
    END
  END mstream_o[1140]
  PIN mstream_o[1141]
    DIRECTION OUTPUT TRISTATE ;
    USE SIGNAL ;
    ANTENNADIFFAREA 0.795200 ;
    PORT
      LAYER met2 ;
        RECT 1119.730 296.000 1120.010 300.000 ;
    END
  END mstream_o[1141]
  PIN mstream_o[1142]
    DIRECTION OUTPUT TRISTATE ;
    USE SIGNAL ;
    ANTENNADIFFAREA 0.795200 ;
    PORT
      LAYER met2 ;
        RECT 1120.650 296.000 1120.930 300.000 ;
    END
  END mstream_o[1142]
  PIN mstream_o[1143]
    DIRECTION OUTPUT TRISTATE ;
    USE SIGNAL ;
    ANTENNADIFFAREA 0.795200 ;
    PORT
      LAYER met2 ;
        RECT 1121.570 296.000 1121.850 300.000 ;
    END
  END mstream_o[1143]
  PIN mstream_o[1144]
    DIRECTION OUTPUT TRISTATE ;
    USE SIGNAL ;
    ANTENNADIFFAREA 0.795200 ;
    PORT
      LAYER met2 ;
        RECT 1122.490 296.000 1122.770 300.000 ;
    END
  END mstream_o[1144]
  PIN mstream_o[1145]
    DIRECTION OUTPUT TRISTATE ;
    USE SIGNAL ;
    ANTENNADIFFAREA 0.795200 ;
    PORT
      LAYER met2 ;
        RECT 1123.410 296.000 1123.690 300.000 ;
    END
  END mstream_o[1145]
  PIN mstream_o[1146]
    DIRECTION OUTPUT TRISTATE ;
    USE SIGNAL ;
    ANTENNADIFFAREA 0.795200 ;
    PORT
      LAYER met2 ;
        RECT 1124.330 296.000 1124.610 300.000 ;
    END
  END mstream_o[1146]
  PIN mstream_o[1147]
    DIRECTION OUTPUT TRISTATE ;
    USE SIGNAL ;
    ANTENNADIFFAREA 0.795200 ;
    PORT
      LAYER met2 ;
        RECT 1125.250 296.000 1125.530 300.000 ;
    END
  END mstream_o[1147]
  PIN mstream_o[1148]
    DIRECTION OUTPUT TRISTATE ;
    USE SIGNAL ;
    ANTENNADIFFAREA 0.795200 ;
    PORT
      LAYER met2 ;
        RECT 1126.170 296.000 1126.450 300.000 ;
    END
  END mstream_o[1148]
  PIN mstream_o[1149]
    DIRECTION OUTPUT TRISTATE ;
    USE SIGNAL ;
    ANTENNADIFFAREA 0.795200 ;
    PORT
      LAYER met2 ;
        RECT 1127.090 296.000 1127.370 300.000 ;
    END
  END mstream_o[1149]
  PIN mstream_o[114]
    DIRECTION OUTPUT TRISTATE ;
    USE SIGNAL ;
    ANTENNADIFFAREA 0.795200 ;
    PORT
      LAYER met2 ;
        RECT 174.890 296.000 175.170 300.000 ;
    END
  END mstream_o[114]
  PIN mstream_o[1150]
    DIRECTION OUTPUT TRISTATE ;
    USE SIGNAL ;
    ANTENNADIFFAREA 0.795200 ;
    PORT
      LAYER met2 ;
        RECT 1128.010 296.000 1128.290 300.000 ;
    END
  END mstream_o[1150]
  PIN mstream_o[1151]
    DIRECTION OUTPUT TRISTATE ;
    USE SIGNAL ;
    ANTENNADIFFAREA 0.795200 ;
    PORT
      LAYER met2 ;
        RECT 1128.930 296.000 1129.210 300.000 ;
    END
  END mstream_o[1151]
  PIN mstream_o[1152]
    DIRECTION OUTPUT TRISTATE ;
    USE SIGNAL ;
    ANTENNADIFFAREA 0.795200 ;
    PORT
      LAYER met2 ;
        RECT 1129.850 296.000 1130.130 300.000 ;
    END
  END mstream_o[1152]
  PIN mstream_o[1153]
    DIRECTION OUTPUT TRISTATE ;
    USE SIGNAL ;
    PORT
      LAYER met2 ;
        RECT 1130.770 296.000 1131.050 300.000 ;
    END
  END mstream_o[1153]
  PIN mstream_o[115]
    DIRECTION OUTPUT TRISTATE ;
    USE SIGNAL ;
    ANTENNADIFFAREA 0.795200 ;
    PORT
      LAYER met2 ;
        RECT 175.810 296.000 176.090 300.000 ;
    END
  END mstream_o[115]
  PIN mstream_o[116]
    DIRECTION OUTPUT TRISTATE ;
    USE SIGNAL ;
    ANTENNADIFFAREA 0.795200 ;
    PORT
      LAYER met2 ;
        RECT 176.730 296.000 177.010 300.000 ;
    END
  END mstream_o[116]
  PIN mstream_o[117]
    DIRECTION OUTPUT TRISTATE ;
    USE SIGNAL ;
    ANTENNADIFFAREA 0.795200 ;
    PORT
      LAYER met2 ;
        RECT 177.650 296.000 177.930 300.000 ;
    END
  END mstream_o[117]
  PIN mstream_o[118]
    DIRECTION OUTPUT TRISTATE ;
    USE SIGNAL ;
    ANTENNADIFFAREA 0.795200 ;
    PORT
      LAYER met2 ;
        RECT 178.570 296.000 178.850 300.000 ;
    END
  END mstream_o[118]
  PIN mstream_o[119]
    DIRECTION OUTPUT TRISTATE ;
    USE SIGNAL ;
    ANTENNADIFFAREA 0.795200 ;
    PORT
      LAYER met2 ;
        RECT 179.490 296.000 179.770 300.000 ;
    END
  END mstream_o[119]
  PIN mstream_o[11]
    DIRECTION OUTPUT TRISTATE ;
    USE SIGNAL ;
    ANTENNADIFFAREA 0.795200 ;
    PORT
      LAYER met2 ;
        RECT 80.130 296.000 80.410 300.000 ;
    END
  END mstream_o[11]
  PIN mstream_o[120]
    DIRECTION OUTPUT TRISTATE ;
    USE SIGNAL ;
    ANTENNADIFFAREA 0.795200 ;
    PORT
      LAYER met2 ;
        RECT 180.410 296.000 180.690 300.000 ;
    END
  END mstream_o[120]
  PIN mstream_o[121]
    DIRECTION OUTPUT TRISTATE ;
    USE SIGNAL ;
    ANTENNADIFFAREA 0.795200 ;
    PORT
      LAYER met2 ;
        RECT 181.330 296.000 181.610 300.000 ;
    END
  END mstream_o[121]
  PIN mstream_o[122]
    DIRECTION OUTPUT TRISTATE ;
    USE SIGNAL ;
    ANTENNADIFFAREA 0.795200 ;
    PORT
      LAYER met2 ;
        RECT 182.250 296.000 182.530 300.000 ;
    END
  END mstream_o[122]
  PIN mstream_o[123]
    DIRECTION OUTPUT TRISTATE ;
    USE SIGNAL ;
    ANTENNADIFFAREA 0.795200 ;
    PORT
      LAYER met2 ;
        RECT 183.170 296.000 183.450 300.000 ;
    END
  END mstream_o[123]
  PIN mstream_o[124]
    DIRECTION OUTPUT TRISTATE ;
    USE SIGNAL ;
    ANTENNADIFFAREA 0.795200 ;
    PORT
      LAYER met2 ;
        RECT 184.090 296.000 184.370 300.000 ;
    END
  END mstream_o[124]
  PIN mstream_o[125]
    DIRECTION OUTPUT TRISTATE ;
    USE SIGNAL ;
    ANTENNADIFFAREA 0.795200 ;
    PORT
      LAYER met2 ;
        RECT 185.010 296.000 185.290 300.000 ;
    END
  END mstream_o[125]
  PIN mstream_o[126]
    DIRECTION OUTPUT TRISTATE ;
    USE SIGNAL ;
    ANTENNADIFFAREA 0.795200 ;
    PORT
      LAYER met2 ;
        RECT 185.930 296.000 186.210 300.000 ;
    END
  END mstream_o[126]
  PIN mstream_o[127]
    DIRECTION OUTPUT TRISTATE ;
    USE SIGNAL ;
    ANTENNADIFFAREA 0.795200 ;
    PORT
      LAYER met2 ;
        RECT 186.850 296.000 187.130 300.000 ;
    END
  END mstream_o[127]
  PIN mstream_o[128]
    DIRECTION OUTPUT TRISTATE ;
    USE SIGNAL ;
    ANTENNADIFFAREA 0.795200 ;
    PORT
      LAYER met2 ;
        RECT 187.770 296.000 188.050 300.000 ;
    END
  END mstream_o[128]
  PIN mstream_o[129]
    DIRECTION OUTPUT TRISTATE ;
    USE SIGNAL ;
    ANTENNADIFFAREA 0.795200 ;
    PORT
      LAYER met2 ;
        RECT 188.690 296.000 188.970 300.000 ;
    END
  END mstream_o[129]
  PIN mstream_o[12]
    DIRECTION OUTPUT TRISTATE ;
    USE SIGNAL ;
    ANTENNADIFFAREA 0.795200 ;
    PORT
      LAYER met2 ;
        RECT 81.050 296.000 81.330 300.000 ;
    END
  END mstream_o[12]
  PIN mstream_o[130]
    DIRECTION OUTPUT TRISTATE ;
    USE SIGNAL ;
    ANTENNADIFFAREA 0.795200 ;
    PORT
      LAYER met2 ;
        RECT 189.610 296.000 189.890 300.000 ;
    END
  END mstream_o[130]
  PIN mstream_o[131]
    DIRECTION OUTPUT TRISTATE ;
    USE SIGNAL ;
    ANTENNADIFFAREA 0.795200 ;
    PORT
      LAYER met2 ;
        RECT 190.530 296.000 190.810 300.000 ;
    END
  END mstream_o[131]
  PIN mstream_o[132]
    DIRECTION OUTPUT TRISTATE ;
    USE SIGNAL ;
    ANTENNADIFFAREA 0.795200 ;
    PORT
      LAYER met2 ;
        RECT 191.450 296.000 191.730 300.000 ;
    END
  END mstream_o[132]
  PIN mstream_o[133]
    DIRECTION OUTPUT TRISTATE ;
    USE SIGNAL ;
    ANTENNADIFFAREA 0.795200 ;
    PORT
      LAYER met2 ;
        RECT 192.370 296.000 192.650 300.000 ;
    END
  END mstream_o[133]
  PIN mstream_o[134]
    DIRECTION OUTPUT TRISTATE ;
    USE SIGNAL ;
    ANTENNADIFFAREA 0.795200 ;
    PORT
      LAYER met2 ;
        RECT 193.290 296.000 193.570 300.000 ;
    END
  END mstream_o[134]
  PIN mstream_o[135]
    DIRECTION OUTPUT TRISTATE ;
    USE SIGNAL ;
    ANTENNADIFFAREA 0.795200 ;
    PORT
      LAYER met2 ;
        RECT 194.210 296.000 194.490 300.000 ;
    END
  END mstream_o[135]
  PIN mstream_o[136]
    DIRECTION OUTPUT TRISTATE ;
    USE SIGNAL ;
    ANTENNADIFFAREA 0.795200 ;
    PORT
      LAYER met2 ;
        RECT 195.130 296.000 195.410 300.000 ;
    END
  END mstream_o[136]
  PIN mstream_o[137]
    DIRECTION OUTPUT TRISTATE ;
    USE SIGNAL ;
    ANTENNADIFFAREA 0.795200 ;
    PORT
      LAYER met2 ;
        RECT 196.050 296.000 196.330 300.000 ;
    END
  END mstream_o[137]
  PIN mstream_o[138]
    DIRECTION OUTPUT TRISTATE ;
    USE SIGNAL ;
    ANTENNADIFFAREA 0.795200 ;
    PORT
      LAYER met2 ;
        RECT 196.970 296.000 197.250 300.000 ;
    END
  END mstream_o[138]
  PIN mstream_o[139]
    DIRECTION OUTPUT TRISTATE ;
    USE SIGNAL ;
    ANTENNADIFFAREA 0.795200 ;
    PORT
      LAYER met2 ;
        RECT 197.890 296.000 198.170 300.000 ;
    END
  END mstream_o[139]
  PIN mstream_o[13]
    DIRECTION OUTPUT TRISTATE ;
    USE SIGNAL ;
    ANTENNADIFFAREA 0.795200 ;
    PORT
      LAYER met2 ;
        RECT 81.970 296.000 82.250 300.000 ;
    END
  END mstream_o[13]
  PIN mstream_o[140]
    DIRECTION OUTPUT TRISTATE ;
    USE SIGNAL ;
    ANTENNADIFFAREA 0.795200 ;
    PORT
      LAYER met2 ;
        RECT 198.810 296.000 199.090 300.000 ;
    END
  END mstream_o[140]
  PIN mstream_o[141]
    DIRECTION OUTPUT TRISTATE ;
    USE SIGNAL ;
    ANTENNADIFFAREA 0.795200 ;
    PORT
      LAYER met2 ;
        RECT 199.730 296.000 200.010 300.000 ;
    END
  END mstream_o[141]
  PIN mstream_o[142]
    DIRECTION OUTPUT TRISTATE ;
    USE SIGNAL ;
    ANTENNADIFFAREA 0.795200 ;
    PORT
      LAYER met2 ;
        RECT 200.650 296.000 200.930 300.000 ;
    END
  END mstream_o[142]
  PIN mstream_o[143]
    DIRECTION OUTPUT TRISTATE ;
    USE SIGNAL ;
    ANTENNADIFFAREA 0.795200 ;
    PORT
      LAYER met2 ;
        RECT 201.570 296.000 201.850 300.000 ;
    END
  END mstream_o[143]
  PIN mstream_o[144]
    DIRECTION OUTPUT TRISTATE ;
    USE SIGNAL ;
    ANTENNADIFFAREA 0.795200 ;
    PORT
      LAYER met2 ;
        RECT 202.490 296.000 202.770 300.000 ;
    END
  END mstream_o[144]
  PIN mstream_o[145]
    DIRECTION OUTPUT TRISTATE ;
    USE SIGNAL ;
    ANTENNADIFFAREA 0.795200 ;
    PORT
      LAYER met2 ;
        RECT 203.410 296.000 203.690 300.000 ;
    END
  END mstream_o[145]
  PIN mstream_o[146]
    DIRECTION OUTPUT TRISTATE ;
    USE SIGNAL ;
    ANTENNADIFFAREA 0.795200 ;
    PORT
      LAYER met2 ;
        RECT 204.330 296.000 204.610 300.000 ;
    END
  END mstream_o[146]
  PIN mstream_o[147]
    DIRECTION OUTPUT TRISTATE ;
    USE SIGNAL ;
    ANTENNADIFFAREA 0.795200 ;
    PORT
      LAYER met2 ;
        RECT 205.250 296.000 205.530 300.000 ;
    END
  END mstream_o[147]
  PIN mstream_o[148]
    DIRECTION OUTPUT TRISTATE ;
    USE SIGNAL ;
    ANTENNADIFFAREA 0.795200 ;
    PORT
      LAYER met2 ;
        RECT 206.170 296.000 206.450 300.000 ;
    END
  END mstream_o[148]
  PIN mstream_o[149]
    DIRECTION OUTPUT TRISTATE ;
    USE SIGNAL ;
    ANTENNADIFFAREA 0.795200 ;
    PORT
      LAYER met2 ;
        RECT 207.090 296.000 207.370 300.000 ;
    END
  END mstream_o[149]
  PIN mstream_o[14]
    DIRECTION OUTPUT TRISTATE ;
    USE SIGNAL ;
    ANTENNADIFFAREA 0.795200 ;
    PORT
      LAYER met2 ;
        RECT 82.890 296.000 83.170 300.000 ;
    END
  END mstream_o[14]
  PIN mstream_o[150]
    DIRECTION OUTPUT TRISTATE ;
    USE SIGNAL ;
    ANTENNADIFFAREA 0.795200 ;
    PORT
      LAYER met2 ;
        RECT 208.010 296.000 208.290 300.000 ;
    END
  END mstream_o[150]
  PIN mstream_o[151]
    DIRECTION OUTPUT TRISTATE ;
    USE SIGNAL ;
    ANTENNADIFFAREA 0.795200 ;
    PORT
      LAYER met2 ;
        RECT 208.930 296.000 209.210 300.000 ;
    END
  END mstream_o[151]
  PIN mstream_o[152]
    DIRECTION OUTPUT TRISTATE ;
    USE SIGNAL ;
    ANTENNADIFFAREA 0.795200 ;
    PORT
      LAYER met2 ;
        RECT 209.850 296.000 210.130 300.000 ;
    END
  END mstream_o[152]
  PIN mstream_o[153]
    DIRECTION OUTPUT TRISTATE ;
    USE SIGNAL ;
    ANTENNADIFFAREA 0.795200 ;
    PORT
      LAYER met2 ;
        RECT 210.770 296.000 211.050 300.000 ;
    END
  END mstream_o[153]
  PIN mstream_o[154]
    DIRECTION OUTPUT TRISTATE ;
    USE SIGNAL ;
    ANTENNADIFFAREA 0.795200 ;
    PORT
      LAYER met2 ;
        RECT 211.690 296.000 211.970 300.000 ;
    END
  END mstream_o[154]
  PIN mstream_o[155]
    DIRECTION OUTPUT TRISTATE ;
    USE SIGNAL ;
    ANTENNADIFFAREA 0.795200 ;
    PORT
      LAYER met2 ;
        RECT 212.610 296.000 212.890 300.000 ;
    END
  END mstream_o[155]
  PIN mstream_o[156]
    DIRECTION OUTPUT TRISTATE ;
    USE SIGNAL ;
    ANTENNADIFFAREA 0.795200 ;
    PORT
      LAYER met2 ;
        RECT 213.530 296.000 213.810 300.000 ;
    END
  END mstream_o[156]
  PIN mstream_o[157]
    DIRECTION OUTPUT TRISTATE ;
    USE SIGNAL ;
    ANTENNADIFFAREA 0.795200 ;
    PORT
      LAYER met2 ;
        RECT 214.450 296.000 214.730 300.000 ;
    END
  END mstream_o[157]
  PIN mstream_o[158]
    DIRECTION OUTPUT TRISTATE ;
    USE SIGNAL ;
    ANTENNADIFFAREA 0.795200 ;
    PORT
      LAYER met2 ;
        RECT 215.370 296.000 215.650 300.000 ;
    END
  END mstream_o[158]
  PIN mstream_o[159]
    DIRECTION OUTPUT TRISTATE ;
    USE SIGNAL ;
    ANTENNADIFFAREA 0.795200 ;
    PORT
      LAYER met2 ;
        RECT 216.290 296.000 216.570 300.000 ;
    END
  END mstream_o[159]
  PIN mstream_o[15]
    DIRECTION OUTPUT TRISTATE ;
    USE SIGNAL ;
    ANTENNADIFFAREA 0.795200 ;
    PORT
      LAYER met2 ;
        RECT 83.810 296.000 84.090 300.000 ;
    END
  END mstream_o[15]
  PIN mstream_o[160]
    DIRECTION OUTPUT TRISTATE ;
    USE SIGNAL ;
    ANTENNADIFFAREA 0.795200 ;
    PORT
      LAYER met2 ;
        RECT 217.210 296.000 217.490 300.000 ;
    END
  END mstream_o[160]
  PIN mstream_o[161]
    DIRECTION OUTPUT TRISTATE ;
    USE SIGNAL ;
    ANTENNADIFFAREA 0.795200 ;
    PORT
      LAYER met2 ;
        RECT 218.130 296.000 218.410 300.000 ;
    END
  END mstream_o[161]
  PIN mstream_o[162]
    DIRECTION OUTPUT TRISTATE ;
    USE SIGNAL ;
    ANTENNADIFFAREA 0.795200 ;
    PORT
      LAYER met2 ;
        RECT 219.050 296.000 219.330 300.000 ;
    END
  END mstream_o[162]
  PIN mstream_o[163]
    DIRECTION OUTPUT TRISTATE ;
    USE SIGNAL ;
    ANTENNADIFFAREA 0.795200 ;
    PORT
      LAYER met2 ;
        RECT 219.970 296.000 220.250 300.000 ;
    END
  END mstream_o[163]
  PIN mstream_o[164]
    DIRECTION OUTPUT TRISTATE ;
    USE SIGNAL ;
    ANTENNADIFFAREA 0.795200 ;
    PORT
      LAYER met2 ;
        RECT 220.890 296.000 221.170 300.000 ;
    END
  END mstream_o[164]
  PIN mstream_o[165]
    DIRECTION OUTPUT TRISTATE ;
    USE SIGNAL ;
    ANTENNADIFFAREA 0.795200 ;
    PORT
      LAYER met2 ;
        RECT 221.810 296.000 222.090 300.000 ;
    END
  END mstream_o[165]
  PIN mstream_o[166]
    DIRECTION OUTPUT TRISTATE ;
    USE SIGNAL ;
    ANTENNADIFFAREA 0.795200 ;
    PORT
      LAYER met2 ;
        RECT 222.730 296.000 223.010 300.000 ;
    END
  END mstream_o[166]
  PIN mstream_o[167]
    DIRECTION OUTPUT TRISTATE ;
    USE SIGNAL ;
    ANTENNADIFFAREA 0.795200 ;
    PORT
      LAYER met2 ;
        RECT 223.650 296.000 223.930 300.000 ;
    END
  END mstream_o[167]
  PIN mstream_o[168]
    DIRECTION OUTPUT TRISTATE ;
    USE SIGNAL ;
    ANTENNADIFFAREA 0.795200 ;
    PORT
      LAYER met2 ;
        RECT 224.570 296.000 224.850 300.000 ;
    END
  END mstream_o[168]
  PIN mstream_o[169]
    DIRECTION OUTPUT TRISTATE ;
    USE SIGNAL ;
    ANTENNADIFFAREA 0.795200 ;
    PORT
      LAYER met2 ;
        RECT 225.490 296.000 225.770 300.000 ;
    END
  END mstream_o[169]
  PIN mstream_o[16]
    DIRECTION OUTPUT TRISTATE ;
    USE SIGNAL ;
    ANTENNADIFFAREA 0.795200 ;
    PORT
      LAYER met2 ;
        RECT 84.730 296.000 85.010 300.000 ;
    END
  END mstream_o[16]
  PIN mstream_o[170]
    DIRECTION OUTPUT TRISTATE ;
    USE SIGNAL ;
    ANTENNADIFFAREA 0.795200 ;
    PORT
      LAYER met2 ;
        RECT 226.410 296.000 226.690 300.000 ;
    END
  END mstream_o[170]
  PIN mstream_o[171]
    DIRECTION OUTPUT TRISTATE ;
    USE SIGNAL ;
    ANTENNADIFFAREA 0.795200 ;
    PORT
      LAYER met2 ;
        RECT 227.330 296.000 227.610 300.000 ;
    END
  END mstream_o[171]
  PIN mstream_o[172]
    DIRECTION OUTPUT TRISTATE ;
    USE SIGNAL ;
    ANTENNADIFFAREA 0.795200 ;
    PORT
      LAYER met2 ;
        RECT 228.250 296.000 228.530 300.000 ;
    END
  END mstream_o[172]
  PIN mstream_o[173]
    DIRECTION OUTPUT TRISTATE ;
    USE SIGNAL ;
    ANTENNADIFFAREA 0.795200 ;
    PORT
      LAYER met2 ;
        RECT 229.170 296.000 229.450 300.000 ;
    END
  END mstream_o[173]
  PIN mstream_o[174]
    DIRECTION OUTPUT TRISTATE ;
    USE SIGNAL ;
    ANTENNADIFFAREA 0.795200 ;
    PORT
      LAYER met2 ;
        RECT 230.090 296.000 230.370 300.000 ;
    END
  END mstream_o[174]
  PIN mstream_o[175]
    DIRECTION OUTPUT TRISTATE ;
    USE SIGNAL ;
    ANTENNADIFFAREA 0.795200 ;
    PORT
      LAYER met2 ;
        RECT 231.010 296.000 231.290 300.000 ;
    END
  END mstream_o[175]
  PIN mstream_o[176]
    DIRECTION OUTPUT TRISTATE ;
    USE SIGNAL ;
    ANTENNADIFFAREA 0.795200 ;
    PORT
      LAYER met2 ;
        RECT 231.930 296.000 232.210 300.000 ;
    END
  END mstream_o[176]
  PIN mstream_o[177]
    DIRECTION OUTPUT TRISTATE ;
    USE SIGNAL ;
    ANTENNADIFFAREA 0.795200 ;
    PORT
      LAYER met2 ;
        RECT 232.850 296.000 233.130 300.000 ;
    END
  END mstream_o[177]
  PIN mstream_o[178]
    DIRECTION OUTPUT TRISTATE ;
    USE SIGNAL ;
    ANTENNADIFFAREA 0.795200 ;
    PORT
      LAYER met2 ;
        RECT 233.770 296.000 234.050 300.000 ;
    END
  END mstream_o[178]
  PIN mstream_o[179]
    DIRECTION OUTPUT TRISTATE ;
    USE SIGNAL ;
    ANTENNADIFFAREA 0.795200 ;
    PORT
      LAYER met2 ;
        RECT 234.690 296.000 234.970 300.000 ;
    END
  END mstream_o[179]
  PIN mstream_o[17]
    DIRECTION OUTPUT TRISTATE ;
    USE SIGNAL ;
    ANTENNADIFFAREA 0.795200 ;
    PORT
      LAYER met2 ;
        RECT 85.650 296.000 85.930 300.000 ;
    END
  END mstream_o[17]
  PIN mstream_o[180]
    DIRECTION OUTPUT TRISTATE ;
    USE SIGNAL ;
    ANTENNADIFFAREA 0.795200 ;
    PORT
      LAYER met2 ;
        RECT 235.610 296.000 235.890 300.000 ;
    END
  END mstream_o[180]
  PIN mstream_o[181]
    DIRECTION OUTPUT TRISTATE ;
    USE SIGNAL ;
    ANTENNADIFFAREA 0.795200 ;
    PORT
      LAYER met2 ;
        RECT 236.530 296.000 236.810 300.000 ;
    END
  END mstream_o[181]
  PIN mstream_o[182]
    DIRECTION OUTPUT TRISTATE ;
    USE SIGNAL ;
    ANTENNADIFFAREA 0.795200 ;
    PORT
      LAYER met2 ;
        RECT 237.450 296.000 237.730 300.000 ;
    END
  END mstream_o[182]
  PIN mstream_o[183]
    DIRECTION OUTPUT TRISTATE ;
    USE SIGNAL ;
    ANTENNADIFFAREA 0.795200 ;
    PORT
      LAYER met2 ;
        RECT 238.370 296.000 238.650 300.000 ;
    END
  END mstream_o[183]
  PIN mstream_o[184]
    DIRECTION OUTPUT TRISTATE ;
    USE SIGNAL ;
    ANTENNADIFFAREA 0.795200 ;
    PORT
      LAYER met2 ;
        RECT 239.290 296.000 239.570 300.000 ;
    END
  END mstream_o[184]
  PIN mstream_o[185]
    DIRECTION OUTPUT TRISTATE ;
    USE SIGNAL ;
    ANTENNADIFFAREA 0.795200 ;
    PORT
      LAYER met2 ;
        RECT 240.210 296.000 240.490 300.000 ;
    END
  END mstream_o[185]
  PIN mstream_o[186]
    DIRECTION OUTPUT TRISTATE ;
    USE SIGNAL ;
    ANTENNADIFFAREA 0.795200 ;
    PORT
      LAYER met2 ;
        RECT 241.130 296.000 241.410 300.000 ;
    END
  END mstream_o[186]
  PIN mstream_o[187]
    DIRECTION OUTPUT TRISTATE ;
    USE SIGNAL ;
    ANTENNADIFFAREA 0.795200 ;
    PORT
      LAYER met2 ;
        RECT 242.050 296.000 242.330 300.000 ;
    END
  END mstream_o[187]
  PIN mstream_o[188]
    DIRECTION OUTPUT TRISTATE ;
    USE SIGNAL ;
    ANTENNADIFFAREA 0.795200 ;
    PORT
      LAYER met2 ;
        RECT 242.970 296.000 243.250 300.000 ;
    END
  END mstream_o[188]
  PIN mstream_o[189]
    DIRECTION OUTPUT TRISTATE ;
    USE SIGNAL ;
    ANTENNADIFFAREA 0.795200 ;
    PORT
      LAYER met2 ;
        RECT 243.890 296.000 244.170 300.000 ;
    END
  END mstream_o[189]
  PIN mstream_o[18]
    DIRECTION OUTPUT TRISTATE ;
    USE SIGNAL ;
    ANTENNADIFFAREA 0.795200 ;
    PORT
      LAYER met2 ;
        RECT 86.570 296.000 86.850 300.000 ;
    END
  END mstream_o[18]
  PIN mstream_o[190]
    DIRECTION OUTPUT TRISTATE ;
    USE SIGNAL ;
    ANTENNADIFFAREA 0.795200 ;
    PORT
      LAYER met2 ;
        RECT 244.810 296.000 245.090 300.000 ;
    END
  END mstream_o[190]
  PIN mstream_o[191]
    DIRECTION OUTPUT TRISTATE ;
    USE SIGNAL ;
    ANTENNADIFFAREA 0.795200 ;
    PORT
      LAYER met2 ;
        RECT 245.730 296.000 246.010 300.000 ;
    END
  END mstream_o[191]
  PIN mstream_o[192]
    DIRECTION OUTPUT TRISTATE ;
    USE SIGNAL ;
    ANTENNADIFFAREA 0.795200 ;
    PORT
      LAYER met2 ;
        RECT 246.650 296.000 246.930 300.000 ;
    END
  END mstream_o[192]
  PIN mstream_o[193]
    DIRECTION OUTPUT TRISTATE ;
    USE SIGNAL ;
    ANTENNADIFFAREA 0.795200 ;
    PORT
      LAYER met2 ;
        RECT 247.570 296.000 247.850 300.000 ;
    END
  END mstream_o[193]
  PIN mstream_o[194]
    DIRECTION OUTPUT TRISTATE ;
    USE SIGNAL ;
    ANTENNADIFFAREA 0.795200 ;
    PORT
      LAYER met2 ;
        RECT 248.490 296.000 248.770 300.000 ;
    END
  END mstream_o[194]
  PIN mstream_o[195]
    DIRECTION OUTPUT TRISTATE ;
    USE SIGNAL ;
    ANTENNADIFFAREA 0.795200 ;
    PORT
      LAYER met2 ;
        RECT 249.410 296.000 249.690 300.000 ;
    END
  END mstream_o[195]
  PIN mstream_o[196]
    DIRECTION OUTPUT TRISTATE ;
    USE SIGNAL ;
    ANTENNADIFFAREA 0.795200 ;
    PORT
      LAYER met2 ;
        RECT 250.330 296.000 250.610 300.000 ;
    END
  END mstream_o[196]
  PIN mstream_o[197]
    DIRECTION OUTPUT TRISTATE ;
    USE SIGNAL ;
    ANTENNADIFFAREA 0.795200 ;
    PORT
      LAYER met2 ;
        RECT 251.250 296.000 251.530 300.000 ;
    END
  END mstream_o[197]
  PIN mstream_o[198]
    DIRECTION OUTPUT TRISTATE ;
    USE SIGNAL ;
    ANTENNADIFFAREA 0.795200 ;
    PORT
      LAYER met2 ;
        RECT 252.170 296.000 252.450 300.000 ;
    END
  END mstream_o[198]
  PIN mstream_o[199]
    DIRECTION OUTPUT TRISTATE ;
    USE SIGNAL ;
    ANTENNADIFFAREA 0.795200 ;
    PORT
      LAYER met2 ;
        RECT 253.090 296.000 253.370 300.000 ;
    END
  END mstream_o[199]
  PIN mstream_o[19]
    DIRECTION OUTPUT TRISTATE ;
    USE SIGNAL ;
    ANTENNADIFFAREA 0.795200 ;
    PORT
      LAYER met2 ;
        RECT 87.490 296.000 87.770 300.000 ;
    END
  END mstream_o[19]
  PIN mstream_o[1]
    DIRECTION OUTPUT TRISTATE ;
    USE SIGNAL ;
    ANTENNADIFFAREA 0.795200 ;
    PORT
      LAYER met2 ;
        RECT 70.930 296.000 71.210 300.000 ;
    END
  END mstream_o[1]
  PIN mstream_o[200]
    DIRECTION OUTPUT TRISTATE ;
    USE SIGNAL ;
    ANTENNADIFFAREA 0.795200 ;
    PORT
      LAYER met2 ;
        RECT 254.010 296.000 254.290 300.000 ;
    END
  END mstream_o[200]
  PIN mstream_o[201]
    DIRECTION OUTPUT TRISTATE ;
    USE SIGNAL ;
    ANTENNADIFFAREA 0.795200 ;
    PORT
      LAYER met2 ;
        RECT 254.930 296.000 255.210 300.000 ;
    END
  END mstream_o[201]
  PIN mstream_o[202]
    DIRECTION OUTPUT TRISTATE ;
    USE SIGNAL ;
    ANTENNADIFFAREA 0.795200 ;
    PORT
      LAYER met2 ;
        RECT 255.850 296.000 256.130 300.000 ;
    END
  END mstream_o[202]
  PIN mstream_o[203]
    DIRECTION OUTPUT TRISTATE ;
    USE SIGNAL ;
    ANTENNADIFFAREA 0.795200 ;
    PORT
      LAYER met2 ;
        RECT 256.770 296.000 257.050 300.000 ;
    END
  END mstream_o[203]
  PIN mstream_o[204]
    DIRECTION OUTPUT TRISTATE ;
    USE SIGNAL ;
    ANTENNADIFFAREA 0.795200 ;
    PORT
      LAYER met2 ;
        RECT 257.690 296.000 257.970 300.000 ;
    END
  END mstream_o[204]
  PIN mstream_o[205]
    DIRECTION OUTPUT TRISTATE ;
    USE SIGNAL ;
    ANTENNADIFFAREA 0.795200 ;
    PORT
      LAYER met2 ;
        RECT 258.610 296.000 258.890 300.000 ;
    END
  END mstream_o[205]
  PIN mstream_o[206]
    DIRECTION OUTPUT TRISTATE ;
    USE SIGNAL ;
    ANTENNADIFFAREA 0.795200 ;
    PORT
      LAYER met2 ;
        RECT 259.530 296.000 259.810 300.000 ;
    END
  END mstream_o[206]
  PIN mstream_o[207]
    DIRECTION OUTPUT TRISTATE ;
    USE SIGNAL ;
    ANTENNADIFFAREA 0.795200 ;
    PORT
      LAYER met2 ;
        RECT 260.450 296.000 260.730 300.000 ;
    END
  END mstream_o[207]
  PIN mstream_o[208]
    DIRECTION OUTPUT TRISTATE ;
    USE SIGNAL ;
    ANTENNADIFFAREA 0.795200 ;
    PORT
      LAYER met2 ;
        RECT 261.370 296.000 261.650 300.000 ;
    END
  END mstream_o[208]
  PIN mstream_o[209]
    DIRECTION OUTPUT TRISTATE ;
    USE SIGNAL ;
    ANTENNADIFFAREA 0.795200 ;
    PORT
      LAYER met2 ;
        RECT 262.290 296.000 262.570 300.000 ;
    END
  END mstream_o[209]
  PIN mstream_o[20]
    DIRECTION OUTPUT TRISTATE ;
    USE SIGNAL ;
    ANTENNADIFFAREA 0.795200 ;
    PORT
      LAYER met2 ;
        RECT 88.410 296.000 88.690 300.000 ;
    END
  END mstream_o[20]
  PIN mstream_o[210]
    DIRECTION OUTPUT TRISTATE ;
    USE SIGNAL ;
    ANTENNADIFFAREA 0.795200 ;
    PORT
      LAYER met2 ;
        RECT 263.210 296.000 263.490 300.000 ;
    END
  END mstream_o[210]
  PIN mstream_o[211]
    DIRECTION OUTPUT TRISTATE ;
    USE SIGNAL ;
    ANTENNADIFFAREA 0.795200 ;
    PORT
      LAYER met2 ;
        RECT 264.130 296.000 264.410 300.000 ;
    END
  END mstream_o[211]
  PIN mstream_o[212]
    DIRECTION OUTPUT TRISTATE ;
    USE SIGNAL ;
    ANTENNADIFFAREA 0.795200 ;
    PORT
      LAYER met2 ;
        RECT 265.050 296.000 265.330 300.000 ;
    END
  END mstream_o[212]
  PIN mstream_o[213]
    DIRECTION OUTPUT TRISTATE ;
    USE SIGNAL ;
    ANTENNADIFFAREA 0.795200 ;
    PORT
      LAYER met2 ;
        RECT 265.970 296.000 266.250 300.000 ;
    END
  END mstream_o[213]
  PIN mstream_o[214]
    DIRECTION OUTPUT TRISTATE ;
    USE SIGNAL ;
    ANTENNADIFFAREA 0.795200 ;
    PORT
      LAYER met2 ;
        RECT 266.890 296.000 267.170 300.000 ;
    END
  END mstream_o[214]
  PIN mstream_o[215]
    DIRECTION OUTPUT TRISTATE ;
    USE SIGNAL ;
    ANTENNADIFFAREA 0.795200 ;
    PORT
      LAYER met2 ;
        RECT 267.810 296.000 268.090 300.000 ;
    END
  END mstream_o[215]
  PIN mstream_o[216]
    DIRECTION OUTPUT TRISTATE ;
    USE SIGNAL ;
    ANTENNADIFFAREA 0.795200 ;
    PORT
      LAYER met2 ;
        RECT 268.730 296.000 269.010 300.000 ;
    END
  END mstream_o[216]
  PIN mstream_o[217]
    DIRECTION OUTPUT TRISTATE ;
    USE SIGNAL ;
    ANTENNADIFFAREA 0.795200 ;
    PORT
      LAYER met2 ;
        RECT 269.650 296.000 269.930 300.000 ;
    END
  END mstream_o[217]
  PIN mstream_o[218]
    DIRECTION OUTPUT TRISTATE ;
    USE SIGNAL ;
    ANTENNADIFFAREA 0.795200 ;
    PORT
      LAYER met2 ;
        RECT 270.570 296.000 270.850 300.000 ;
    END
  END mstream_o[218]
  PIN mstream_o[219]
    DIRECTION OUTPUT TRISTATE ;
    USE SIGNAL ;
    ANTENNADIFFAREA 0.795200 ;
    PORT
      LAYER met2 ;
        RECT 271.490 296.000 271.770 300.000 ;
    END
  END mstream_o[219]
  PIN mstream_o[21]
    DIRECTION OUTPUT TRISTATE ;
    USE SIGNAL ;
    ANTENNADIFFAREA 0.795200 ;
    PORT
      LAYER met2 ;
        RECT 89.330 296.000 89.610 300.000 ;
    END
  END mstream_o[21]
  PIN mstream_o[220]
    DIRECTION OUTPUT TRISTATE ;
    USE SIGNAL ;
    ANTENNADIFFAREA 0.795200 ;
    PORT
      LAYER met2 ;
        RECT 272.410 296.000 272.690 300.000 ;
    END
  END mstream_o[220]
  PIN mstream_o[221]
    DIRECTION OUTPUT TRISTATE ;
    USE SIGNAL ;
    ANTENNADIFFAREA 0.795200 ;
    PORT
      LAYER met2 ;
        RECT 273.330 296.000 273.610 300.000 ;
    END
  END mstream_o[221]
  PIN mstream_o[222]
    DIRECTION OUTPUT TRISTATE ;
    USE SIGNAL ;
    ANTENNADIFFAREA 0.795200 ;
    PORT
      LAYER met2 ;
        RECT 274.250 296.000 274.530 300.000 ;
    END
  END mstream_o[222]
  PIN mstream_o[223]
    DIRECTION OUTPUT TRISTATE ;
    USE SIGNAL ;
    ANTENNADIFFAREA 0.795200 ;
    PORT
      LAYER met2 ;
        RECT 275.170 296.000 275.450 300.000 ;
    END
  END mstream_o[223]
  PIN mstream_o[224]
    DIRECTION OUTPUT TRISTATE ;
    USE SIGNAL ;
    ANTENNADIFFAREA 0.795200 ;
    PORT
      LAYER met2 ;
        RECT 276.090 296.000 276.370 300.000 ;
    END
  END mstream_o[224]
  PIN mstream_o[225]
    DIRECTION OUTPUT TRISTATE ;
    USE SIGNAL ;
    ANTENNADIFFAREA 0.795200 ;
    PORT
      LAYER met2 ;
        RECT 277.010 296.000 277.290 300.000 ;
    END
  END mstream_o[225]
  PIN mstream_o[226]
    DIRECTION OUTPUT TRISTATE ;
    USE SIGNAL ;
    ANTENNADIFFAREA 0.795200 ;
    PORT
      LAYER met2 ;
        RECT 277.930 296.000 278.210 300.000 ;
    END
  END mstream_o[226]
  PIN mstream_o[227]
    DIRECTION OUTPUT TRISTATE ;
    USE SIGNAL ;
    ANTENNADIFFAREA 0.795200 ;
    PORT
      LAYER met2 ;
        RECT 278.850 296.000 279.130 300.000 ;
    END
  END mstream_o[227]
  PIN mstream_o[228]
    DIRECTION OUTPUT TRISTATE ;
    USE SIGNAL ;
    ANTENNADIFFAREA 0.795200 ;
    PORT
      LAYER met2 ;
        RECT 279.770 296.000 280.050 300.000 ;
    END
  END mstream_o[228]
  PIN mstream_o[229]
    DIRECTION OUTPUT TRISTATE ;
    USE SIGNAL ;
    ANTENNADIFFAREA 0.795200 ;
    PORT
      LAYER met2 ;
        RECT 280.690 296.000 280.970 300.000 ;
    END
  END mstream_o[229]
  PIN mstream_o[22]
    DIRECTION OUTPUT TRISTATE ;
    USE SIGNAL ;
    ANTENNADIFFAREA 0.795200 ;
    PORT
      LAYER met2 ;
        RECT 90.250 296.000 90.530 300.000 ;
    END
  END mstream_o[22]
  PIN mstream_o[230]
    DIRECTION OUTPUT TRISTATE ;
    USE SIGNAL ;
    ANTENNADIFFAREA 0.795200 ;
    PORT
      LAYER met2 ;
        RECT 281.610 296.000 281.890 300.000 ;
    END
  END mstream_o[230]
  PIN mstream_o[231]
    DIRECTION OUTPUT TRISTATE ;
    USE SIGNAL ;
    ANTENNADIFFAREA 0.795200 ;
    PORT
      LAYER met2 ;
        RECT 282.530 296.000 282.810 300.000 ;
    END
  END mstream_o[231]
  PIN mstream_o[232]
    DIRECTION OUTPUT TRISTATE ;
    USE SIGNAL ;
    ANTENNADIFFAREA 0.795200 ;
    PORT
      LAYER met2 ;
        RECT 283.450 296.000 283.730 300.000 ;
    END
  END mstream_o[232]
  PIN mstream_o[233]
    DIRECTION OUTPUT TRISTATE ;
    USE SIGNAL ;
    ANTENNADIFFAREA 0.795200 ;
    PORT
      LAYER met2 ;
        RECT 284.370 296.000 284.650 300.000 ;
    END
  END mstream_o[233]
  PIN mstream_o[234]
    DIRECTION OUTPUT TRISTATE ;
    USE SIGNAL ;
    ANTENNADIFFAREA 0.795200 ;
    PORT
      LAYER met2 ;
        RECT 285.290 296.000 285.570 300.000 ;
    END
  END mstream_o[234]
  PIN mstream_o[235]
    DIRECTION OUTPUT TRISTATE ;
    USE SIGNAL ;
    ANTENNADIFFAREA 0.795200 ;
    PORT
      LAYER met2 ;
        RECT 286.210 296.000 286.490 300.000 ;
    END
  END mstream_o[235]
  PIN mstream_o[236]
    DIRECTION OUTPUT TRISTATE ;
    USE SIGNAL ;
    ANTENNADIFFAREA 0.795200 ;
    PORT
      LAYER met2 ;
        RECT 287.130 296.000 287.410 300.000 ;
    END
  END mstream_o[236]
  PIN mstream_o[237]
    DIRECTION OUTPUT TRISTATE ;
    USE SIGNAL ;
    ANTENNADIFFAREA 0.795200 ;
    PORT
      LAYER met2 ;
        RECT 288.050 296.000 288.330 300.000 ;
    END
  END mstream_o[237]
  PIN mstream_o[238]
    DIRECTION OUTPUT TRISTATE ;
    USE SIGNAL ;
    ANTENNADIFFAREA 0.795200 ;
    PORT
      LAYER met2 ;
        RECT 288.970 296.000 289.250 300.000 ;
    END
  END mstream_o[238]
  PIN mstream_o[239]
    DIRECTION OUTPUT TRISTATE ;
    USE SIGNAL ;
    ANTENNADIFFAREA 0.795200 ;
    PORT
      LAYER met2 ;
        RECT 289.890 296.000 290.170 300.000 ;
    END
  END mstream_o[239]
  PIN mstream_o[23]
    DIRECTION OUTPUT TRISTATE ;
    USE SIGNAL ;
    ANTENNADIFFAREA 0.795200 ;
    PORT
      LAYER met2 ;
        RECT 91.170 296.000 91.450 300.000 ;
    END
  END mstream_o[23]
  PIN mstream_o[240]
    DIRECTION OUTPUT TRISTATE ;
    USE SIGNAL ;
    ANTENNADIFFAREA 0.795200 ;
    PORT
      LAYER met2 ;
        RECT 290.810 296.000 291.090 300.000 ;
    END
  END mstream_o[240]
  PIN mstream_o[241]
    DIRECTION OUTPUT TRISTATE ;
    USE SIGNAL ;
    ANTENNADIFFAREA 0.795200 ;
    PORT
      LAYER met2 ;
        RECT 291.730 296.000 292.010 300.000 ;
    END
  END mstream_o[241]
  PIN mstream_o[242]
    DIRECTION OUTPUT TRISTATE ;
    USE SIGNAL ;
    ANTENNADIFFAREA 0.795200 ;
    PORT
      LAYER met2 ;
        RECT 292.650 296.000 292.930 300.000 ;
    END
  END mstream_o[242]
  PIN mstream_o[243]
    DIRECTION OUTPUT TRISTATE ;
    USE SIGNAL ;
    ANTENNADIFFAREA 0.795200 ;
    PORT
      LAYER met2 ;
        RECT 293.570 296.000 293.850 300.000 ;
    END
  END mstream_o[243]
  PIN mstream_o[244]
    DIRECTION OUTPUT TRISTATE ;
    USE SIGNAL ;
    ANTENNADIFFAREA 0.795200 ;
    PORT
      LAYER met2 ;
        RECT 294.490 296.000 294.770 300.000 ;
    END
  END mstream_o[244]
  PIN mstream_o[245]
    DIRECTION OUTPUT TRISTATE ;
    USE SIGNAL ;
    ANTENNADIFFAREA 0.795200 ;
    PORT
      LAYER met2 ;
        RECT 295.410 296.000 295.690 300.000 ;
    END
  END mstream_o[245]
  PIN mstream_o[246]
    DIRECTION OUTPUT TRISTATE ;
    USE SIGNAL ;
    ANTENNADIFFAREA 0.795200 ;
    PORT
      LAYER met2 ;
        RECT 296.330 296.000 296.610 300.000 ;
    END
  END mstream_o[246]
  PIN mstream_o[247]
    DIRECTION OUTPUT TRISTATE ;
    USE SIGNAL ;
    ANTENNADIFFAREA 0.795200 ;
    PORT
      LAYER met2 ;
        RECT 297.250 296.000 297.530 300.000 ;
    END
  END mstream_o[247]
  PIN mstream_o[248]
    DIRECTION OUTPUT TRISTATE ;
    USE SIGNAL ;
    ANTENNADIFFAREA 0.795200 ;
    PORT
      LAYER met2 ;
        RECT 298.170 296.000 298.450 300.000 ;
    END
  END mstream_o[248]
  PIN mstream_o[249]
    DIRECTION OUTPUT TRISTATE ;
    USE SIGNAL ;
    ANTENNADIFFAREA 0.795200 ;
    PORT
      LAYER met2 ;
        RECT 299.090 296.000 299.370 300.000 ;
    END
  END mstream_o[249]
  PIN mstream_o[24]
    DIRECTION OUTPUT TRISTATE ;
    USE SIGNAL ;
    ANTENNADIFFAREA 0.795200 ;
    PORT
      LAYER met2 ;
        RECT 92.090 296.000 92.370 300.000 ;
    END
  END mstream_o[24]
  PIN mstream_o[250]
    DIRECTION OUTPUT TRISTATE ;
    USE SIGNAL ;
    ANTENNADIFFAREA 0.795200 ;
    PORT
      LAYER met2 ;
        RECT 300.010 296.000 300.290 300.000 ;
    END
  END mstream_o[250]
  PIN mstream_o[251]
    DIRECTION OUTPUT TRISTATE ;
    USE SIGNAL ;
    ANTENNADIFFAREA 0.795200 ;
    PORT
      LAYER met2 ;
        RECT 300.930 296.000 301.210 300.000 ;
    END
  END mstream_o[251]
  PIN mstream_o[252]
    DIRECTION OUTPUT TRISTATE ;
    USE SIGNAL ;
    ANTENNADIFFAREA 0.795200 ;
    PORT
      LAYER met2 ;
        RECT 301.850 296.000 302.130 300.000 ;
    END
  END mstream_o[252]
  PIN mstream_o[253]
    DIRECTION OUTPUT TRISTATE ;
    USE SIGNAL ;
    ANTENNADIFFAREA 0.795200 ;
    PORT
      LAYER met2 ;
        RECT 302.770 296.000 303.050 300.000 ;
    END
  END mstream_o[253]
  PIN mstream_o[254]
    DIRECTION OUTPUT TRISTATE ;
    USE SIGNAL ;
    ANTENNADIFFAREA 0.795200 ;
    PORT
      LAYER met2 ;
        RECT 303.690 296.000 303.970 300.000 ;
    END
  END mstream_o[254]
  PIN mstream_o[255]
    DIRECTION OUTPUT TRISTATE ;
    USE SIGNAL ;
    ANTENNADIFFAREA 0.795200 ;
    PORT
      LAYER met2 ;
        RECT 304.610 296.000 304.890 300.000 ;
    END
  END mstream_o[255]
  PIN mstream_o[256]
    DIRECTION OUTPUT TRISTATE ;
    USE SIGNAL ;
    ANTENNADIFFAREA 0.795200 ;
    PORT
      LAYER met2 ;
        RECT 305.530 296.000 305.810 300.000 ;
    END
  END mstream_o[256]
  PIN mstream_o[257]
    DIRECTION OUTPUT TRISTATE ;
    USE SIGNAL ;
    ANTENNADIFFAREA 0.795200 ;
    PORT
      LAYER met2 ;
        RECT 306.450 296.000 306.730 300.000 ;
    END
  END mstream_o[257]
  PIN mstream_o[258]
    DIRECTION OUTPUT TRISTATE ;
    USE SIGNAL ;
    ANTENNADIFFAREA 0.795200 ;
    PORT
      LAYER met2 ;
        RECT 307.370 296.000 307.650 300.000 ;
    END
  END mstream_o[258]
  PIN mstream_o[259]
    DIRECTION OUTPUT TRISTATE ;
    USE SIGNAL ;
    ANTENNADIFFAREA 0.795200 ;
    PORT
      LAYER met2 ;
        RECT 308.290 296.000 308.570 300.000 ;
    END
  END mstream_o[259]
  PIN mstream_o[25]
    DIRECTION OUTPUT TRISTATE ;
    USE SIGNAL ;
    ANTENNADIFFAREA 0.795200 ;
    PORT
      LAYER met2 ;
        RECT 93.010 296.000 93.290 300.000 ;
    END
  END mstream_o[25]
  PIN mstream_o[260]
    DIRECTION OUTPUT TRISTATE ;
    USE SIGNAL ;
    ANTENNADIFFAREA 0.795200 ;
    PORT
      LAYER met2 ;
        RECT 309.210 296.000 309.490 300.000 ;
    END
  END mstream_o[260]
  PIN mstream_o[261]
    DIRECTION OUTPUT TRISTATE ;
    USE SIGNAL ;
    ANTENNADIFFAREA 0.795200 ;
    PORT
      LAYER met2 ;
        RECT 310.130 296.000 310.410 300.000 ;
    END
  END mstream_o[261]
  PIN mstream_o[262]
    DIRECTION OUTPUT TRISTATE ;
    USE SIGNAL ;
    ANTENNADIFFAREA 0.795200 ;
    PORT
      LAYER met2 ;
        RECT 311.050 296.000 311.330 300.000 ;
    END
  END mstream_o[262]
  PIN mstream_o[263]
    DIRECTION OUTPUT TRISTATE ;
    USE SIGNAL ;
    ANTENNADIFFAREA 0.795200 ;
    PORT
      LAYER met2 ;
        RECT 311.970 296.000 312.250 300.000 ;
    END
  END mstream_o[263]
  PIN mstream_o[264]
    DIRECTION OUTPUT TRISTATE ;
    USE SIGNAL ;
    ANTENNADIFFAREA 0.795200 ;
    PORT
      LAYER met2 ;
        RECT 312.890 296.000 313.170 300.000 ;
    END
  END mstream_o[264]
  PIN mstream_o[265]
    DIRECTION OUTPUT TRISTATE ;
    USE SIGNAL ;
    ANTENNADIFFAREA 0.795200 ;
    PORT
      LAYER met2 ;
        RECT 313.810 296.000 314.090 300.000 ;
    END
  END mstream_o[265]
  PIN mstream_o[266]
    DIRECTION OUTPUT TRISTATE ;
    USE SIGNAL ;
    ANTENNADIFFAREA 0.795200 ;
    PORT
      LAYER met2 ;
        RECT 314.730 296.000 315.010 300.000 ;
    END
  END mstream_o[266]
  PIN mstream_o[267]
    DIRECTION OUTPUT TRISTATE ;
    USE SIGNAL ;
    ANTENNADIFFAREA 0.795200 ;
    PORT
      LAYER met2 ;
        RECT 315.650 296.000 315.930 300.000 ;
    END
  END mstream_o[267]
  PIN mstream_o[268]
    DIRECTION OUTPUT TRISTATE ;
    USE SIGNAL ;
    ANTENNADIFFAREA 0.795200 ;
    PORT
      LAYER met2 ;
        RECT 316.570 296.000 316.850 300.000 ;
    END
  END mstream_o[268]
  PIN mstream_o[269]
    DIRECTION OUTPUT TRISTATE ;
    USE SIGNAL ;
    ANTENNADIFFAREA 0.795200 ;
    PORT
      LAYER met2 ;
        RECT 317.490 296.000 317.770 300.000 ;
    END
  END mstream_o[269]
  PIN mstream_o[26]
    DIRECTION OUTPUT TRISTATE ;
    USE SIGNAL ;
    ANTENNADIFFAREA 0.795200 ;
    PORT
      LAYER met2 ;
        RECT 93.930 296.000 94.210 300.000 ;
    END
  END mstream_o[26]
  PIN mstream_o[270]
    DIRECTION OUTPUT TRISTATE ;
    USE SIGNAL ;
    ANTENNADIFFAREA 0.795200 ;
    PORT
      LAYER met2 ;
        RECT 318.410 296.000 318.690 300.000 ;
    END
  END mstream_o[270]
  PIN mstream_o[271]
    DIRECTION OUTPUT TRISTATE ;
    USE SIGNAL ;
    ANTENNADIFFAREA 0.795200 ;
    PORT
      LAYER met2 ;
        RECT 319.330 296.000 319.610 300.000 ;
    END
  END mstream_o[271]
  PIN mstream_o[272]
    DIRECTION OUTPUT TRISTATE ;
    USE SIGNAL ;
    ANTENNADIFFAREA 0.795200 ;
    PORT
      LAYER met2 ;
        RECT 320.250 296.000 320.530 300.000 ;
    END
  END mstream_o[272]
  PIN mstream_o[273]
    DIRECTION OUTPUT TRISTATE ;
    USE SIGNAL ;
    ANTENNADIFFAREA 0.795200 ;
    PORT
      LAYER met2 ;
        RECT 321.170 296.000 321.450 300.000 ;
    END
  END mstream_o[273]
  PIN mstream_o[274]
    DIRECTION OUTPUT TRISTATE ;
    USE SIGNAL ;
    ANTENNADIFFAREA 0.795200 ;
    PORT
      LAYER met2 ;
        RECT 322.090 296.000 322.370 300.000 ;
    END
  END mstream_o[274]
  PIN mstream_o[275]
    DIRECTION OUTPUT TRISTATE ;
    USE SIGNAL ;
    ANTENNADIFFAREA 0.795200 ;
    PORT
      LAYER met2 ;
        RECT 323.010 296.000 323.290 300.000 ;
    END
  END mstream_o[275]
  PIN mstream_o[276]
    DIRECTION OUTPUT TRISTATE ;
    USE SIGNAL ;
    ANTENNADIFFAREA 0.795200 ;
    PORT
      LAYER met2 ;
        RECT 323.930 296.000 324.210 300.000 ;
    END
  END mstream_o[276]
  PIN mstream_o[277]
    DIRECTION OUTPUT TRISTATE ;
    USE SIGNAL ;
    ANTENNADIFFAREA 0.795200 ;
    PORT
      LAYER met2 ;
        RECT 324.850 296.000 325.130 300.000 ;
    END
  END mstream_o[277]
  PIN mstream_o[278]
    DIRECTION OUTPUT TRISTATE ;
    USE SIGNAL ;
    ANTENNADIFFAREA 0.795200 ;
    PORT
      LAYER met2 ;
        RECT 325.770 296.000 326.050 300.000 ;
    END
  END mstream_o[278]
  PIN mstream_o[279]
    DIRECTION OUTPUT TRISTATE ;
    USE SIGNAL ;
    ANTENNADIFFAREA 0.795200 ;
    PORT
      LAYER met2 ;
        RECT 326.690 296.000 326.970 300.000 ;
    END
  END mstream_o[279]
  PIN mstream_o[27]
    DIRECTION OUTPUT TRISTATE ;
    USE SIGNAL ;
    ANTENNADIFFAREA 0.795200 ;
    PORT
      LAYER met2 ;
        RECT 94.850 296.000 95.130 300.000 ;
    END
  END mstream_o[27]
  PIN mstream_o[280]
    DIRECTION OUTPUT TRISTATE ;
    USE SIGNAL ;
    ANTENNADIFFAREA 0.795200 ;
    PORT
      LAYER met2 ;
        RECT 327.610 296.000 327.890 300.000 ;
    END
  END mstream_o[280]
  PIN mstream_o[281]
    DIRECTION OUTPUT TRISTATE ;
    USE SIGNAL ;
    ANTENNADIFFAREA 0.795200 ;
    PORT
      LAYER met2 ;
        RECT 328.530 296.000 328.810 300.000 ;
    END
  END mstream_o[281]
  PIN mstream_o[282]
    DIRECTION OUTPUT TRISTATE ;
    USE SIGNAL ;
    ANTENNADIFFAREA 0.795200 ;
    PORT
      LAYER met2 ;
        RECT 329.450 296.000 329.730 300.000 ;
    END
  END mstream_o[282]
  PIN mstream_o[283]
    DIRECTION OUTPUT TRISTATE ;
    USE SIGNAL ;
    ANTENNADIFFAREA 0.795200 ;
    PORT
      LAYER met2 ;
        RECT 330.370 296.000 330.650 300.000 ;
    END
  END mstream_o[283]
  PIN mstream_o[284]
    DIRECTION OUTPUT TRISTATE ;
    USE SIGNAL ;
    ANTENNADIFFAREA 0.795200 ;
    PORT
      LAYER met2 ;
        RECT 331.290 296.000 331.570 300.000 ;
    END
  END mstream_o[284]
  PIN mstream_o[285]
    DIRECTION OUTPUT TRISTATE ;
    USE SIGNAL ;
    ANTENNADIFFAREA 0.795200 ;
    PORT
      LAYER met2 ;
        RECT 332.210 296.000 332.490 300.000 ;
    END
  END mstream_o[285]
  PIN mstream_o[286]
    DIRECTION OUTPUT TRISTATE ;
    USE SIGNAL ;
    ANTENNADIFFAREA 0.795200 ;
    PORT
      LAYER met2 ;
        RECT 333.130 296.000 333.410 300.000 ;
    END
  END mstream_o[286]
  PIN mstream_o[287]
    DIRECTION OUTPUT TRISTATE ;
    USE SIGNAL ;
    ANTENNADIFFAREA 0.795200 ;
    PORT
      LAYER met2 ;
        RECT 334.050 296.000 334.330 300.000 ;
    END
  END mstream_o[287]
  PIN mstream_o[288]
    DIRECTION OUTPUT TRISTATE ;
    USE SIGNAL ;
    ANTENNADIFFAREA 0.795200 ;
    PORT
      LAYER met2 ;
        RECT 334.970 296.000 335.250 300.000 ;
    END
  END mstream_o[288]
  PIN mstream_o[289]
    DIRECTION OUTPUT TRISTATE ;
    USE SIGNAL ;
    ANTENNADIFFAREA 0.795200 ;
    PORT
      LAYER met2 ;
        RECT 335.890 296.000 336.170 300.000 ;
    END
  END mstream_o[289]
  PIN mstream_o[28]
    DIRECTION OUTPUT TRISTATE ;
    USE SIGNAL ;
    ANTENNADIFFAREA 0.795200 ;
    PORT
      LAYER met2 ;
        RECT 95.770 296.000 96.050 300.000 ;
    END
  END mstream_o[28]
  PIN mstream_o[290]
    DIRECTION OUTPUT TRISTATE ;
    USE SIGNAL ;
    ANTENNADIFFAREA 0.795200 ;
    PORT
      LAYER met2 ;
        RECT 336.810 296.000 337.090 300.000 ;
    END
  END mstream_o[290]
  PIN mstream_o[291]
    DIRECTION OUTPUT TRISTATE ;
    USE SIGNAL ;
    ANTENNADIFFAREA 0.795200 ;
    PORT
      LAYER met2 ;
        RECT 337.730 296.000 338.010 300.000 ;
    END
  END mstream_o[291]
  PIN mstream_o[292]
    DIRECTION OUTPUT TRISTATE ;
    USE SIGNAL ;
    ANTENNADIFFAREA 0.795200 ;
    PORT
      LAYER met2 ;
        RECT 338.650 296.000 338.930 300.000 ;
    END
  END mstream_o[292]
  PIN mstream_o[293]
    DIRECTION OUTPUT TRISTATE ;
    USE SIGNAL ;
    ANTENNADIFFAREA 0.795200 ;
    PORT
      LAYER met2 ;
        RECT 339.570 296.000 339.850 300.000 ;
    END
  END mstream_o[293]
  PIN mstream_o[294]
    DIRECTION OUTPUT TRISTATE ;
    USE SIGNAL ;
    ANTENNADIFFAREA 0.795200 ;
    PORT
      LAYER met2 ;
        RECT 340.490 296.000 340.770 300.000 ;
    END
  END mstream_o[294]
  PIN mstream_o[295]
    DIRECTION OUTPUT TRISTATE ;
    USE SIGNAL ;
    ANTENNADIFFAREA 0.795200 ;
    PORT
      LAYER met2 ;
        RECT 341.410 296.000 341.690 300.000 ;
    END
  END mstream_o[295]
  PIN mstream_o[296]
    DIRECTION OUTPUT TRISTATE ;
    USE SIGNAL ;
    ANTENNADIFFAREA 0.795200 ;
    PORT
      LAYER met2 ;
        RECT 342.330 296.000 342.610 300.000 ;
    END
  END mstream_o[296]
  PIN mstream_o[297]
    DIRECTION OUTPUT TRISTATE ;
    USE SIGNAL ;
    ANTENNADIFFAREA 0.795200 ;
    PORT
      LAYER met2 ;
        RECT 343.250 296.000 343.530 300.000 ;
    END
  END mstream_o[297]
  PIN mstream_o[298]
    DIRECTION OUTPUT TRISTATE ;
    USE SIGNAL ;
    ANTENNADIFFAREA 0.795200 ;
    PORT
      LAYER met2 ;
        RECT 344.170 296.000 344.450 300.000 ;
    END
  END mstream_o[298]
  PIN mstream_o[299]
    DIRECTION OUTPUT TRISTATE ;
    USE SIGNAL ;
    ANTENNADIFFAREA 0.795200 ;
    PORT
      LAYER met2 ;
        RECT 345.090 296.000 345.370 300.000 ;
    END
  END mstream_o[299]
  PIN mstream_o[29]
    DIRECTION OUTPUT TRISTATE ;
    USE SIGNAL ;
    ANTENNADIFFAREA 0.795200 ;
    PORT
      LAYER met2 ;
        RECT 96.690 296.000 96.970 300.000 ;
    END
  END mstream_o[29]
  PIN mstream_o[2]
    DIRECTION OUTPUT TRISTATE ;
    USE SIGNAL ;
    ANTENNADIFFAREA 0.795200 ;
    PORT
      LAYER met2 ;
        RECT 71.850 296.000 72.130 300.000 ;
    END
  END mstream_o[2]
  PIN mstream_o[300]
    DIRECTION OUTPUT TRISTATE ;
    USE SIGNAL ;
    ANTENNADIFFAREA 0.795200 ;
    PORT
      LAYER met2 ;
        RECT 346.010 296.000 346.290 300.000 ;
    END
  END mstream_o[300]
  PIN mstream_o[301]
    DIRECTION OUTPUT TRISTATE ;
    USE SIGNAL ;
    ANTENNADIFFAREA 0.795200 ;
    PORT
      LAYER met2 ;
        RECT 346.930 296.000 347.210 300.000 ;
    END
  END mstream_o[301]
  PIN mstream_o[302]
    DIRECTION OUTPUT TRISTATE ;
    USE SIGNAL ;
    ANTENNADIFFAREA 0.795200 ;
    PORT
      LAYER met2 ;
        RECT 347.850 296.000 348.130 300.000 ;
    END
  END mstream_o[302]
  PIN mstream_o[303]
    DIRECTION OUTPUT TRISTATE ;
    USE SIGNAL ;
    ANTENNADIFFAREA 0.795200 ;
    PORT
      LAYER met2 ;
        RECT 348.770 296.000 349.050 300.000 ;
    END
  END mstream_o[303]
  PIN mstream_o[304]
    DIRECTION OUTPUT TRISTATE ;
    USE SIGNAL ;
    ANTENNADIFFAREA 0.795200 ;
    PORT
      LAYER met2 ;
        RECT 349.690 296.000 349.970 300.000 ;
    END
  END mstream_o[304]
  PIN mstream_o[305]
    DIRECTION OUTPUT TRISTATE ;
    USE SIGNAL ;
    ANTENNADIFFAREA 0.795200 ;
    PORT
      LAYER met2 ;
        RECT 350.610 296.000 350.890 300.000 ;
    END
  END mstream_o[305]
  PIN mstream_o[306]
    DIRECTION OUTPUT TRISTATE ;
    USE SIGNAL ;
    ANTENNADIFFAREA 0.795200 ;
    PORT
      LAYER met2 ;
        RECT 351.530 296.000 351.810 300.000 ;
    END
  END mstream_o[306]
  PIN mstream_o[307]
    DIRECTION OUTPUT TRISTATE ;
    USE SIGNAL ;
    ANTENNADIFFAREA 0.795200 ;
    PORT
      LAYER met2 ;
        RECT 352.450 296.000 352.730 300.000 ;
    END
  END mstream_o[307]
  PIN mstream_o[308]
    DIRECTION OUTPUT TRISTATE ;
    USE SIGNAL ;
    ANTENNADIFFAREA 0.795200 ;
    PORT
      LAYER met2 ;
        RECT 353.370 296.000 353.650 300.000 ;
    END
  END mstream_o[308]
  PIN mstream_o[309]
    DIRECTION OUTPUT TRISTATE ;
    USE SIGNAL ;
    ANTENNADIFFAREA 0.795200 ;
    PORT
      LAYER met2 ;
        RECT 354.290 296.000 354.570 300.000 ;
    END
  END mstream_o[309]
  PIN mstream_o[30]
    DIRECTION OUTPUT TRISTATE ;
    USE SIGNAL ;
    ANTENNADIFFAREA 0.795200 ;
    PORT
      LAYER met2 ;
        RECT 97.610 296.000 97.890 300.000 ;
    END
  END mstream_o[30]
  PIN mstream_o[310]
    DIRECTION OUTPUT TRISTATE ;
    USE SIGNAL ;
    ANTENNADIFFAREA 0.795200 ;
    PORT
      LAYER met2 ;
        RECT 355.210 296.000 355.490 300.000 ;
    END
  END mstream_o[310]
  PIN mstream_o[311]
    DIRECTION OUTPUT TRISTATE ;
    USE SIGNAL ;
    ANTENNADIFFAREA 0.795200 ;
    PORT
      LAYER met2 ;
        RECT 356.130 296.000 356.410 300.000 ;
    END
  END mstream_o[311]
  PIN mstream_o[312]
    DIRECTION OUTPUT TRISTATE ;
    USE SIGNAL ;
    ANTENNADIFFAREA 0.795200 ;
    PORT
      LAYER met2 ;
        RECT 357.050 296.000 357.330 300.000 ;
    END
  END mstream_o[312]
  PIN mstream_o[313]
    DIRECTION OUTPUT TRISTATE ;
    USE SIGNAL ;
    ANTENNADIFFAREA 0.795200 ;
    PORT
      LAYER met2 ;
        RECT 357.970 296.000 358.250 300.000 ;
    END
  END mstream_o[313]
  PIN mstream_o[314]
    DIRECTION OUTPUT TRISTATE ;
    USE SIGNAL ;
    ANTENNADIFFAREA 0.795200 ;
    PORT
      LAYER met2 ;
        RECT 358.890 296.000 359.170 300.000 ;
    END
  END mstream_o[314]
  PIN mstream_o[315]
    DIRECTION OUTPUT TRISTATE ;
    USE SIGNAL ;
    ANTENNADIFFAREA 0.795200 ;
    PORT
      LAYER met2 ;
        RECT 359.810 296.000 360.090 300.000 ;
    END
  END mstream_o[315]
  PIN mstream_o[316]
    DIRECTION OUTPUT TRISTATE ;
    USE SIGNAL ;
    ANTENNADIFFAREA 0.795200 ;
    PORT
      LAYER met2 ;
        RECT 360.730 296.000 361.010 300.000 ;
    END
  END mstream_o[316]
  PIN mstream_o[317]
    DIRECTION OUTPUT TRISTATE ;
    USE SIGNAL ;
    ANTENNADIFFAREA 0.795200 ;
    PORT
      LAYER met2 ;
        RECT 361.650 296.000 361.930 300.000 ;
    END
  END mstream_o[317]
  PIN mstream_o[318]
    DIRECTION OUTPUT TRISTATE ;
    USE SIGNAL ;
    ANTENNADIFFAREA 0.795200 ;
    PORT
      LAYER met2 ;
        RECT 362.570 296.000 362.850 300.000 ;
    END
  END mstream_o[318]
  PIN mstream_o[319]
    DIRECTION OUTPUT TRISTATE ;
    USE SIGNAL ;
    ANTENNADIFFAREA 0.795200 ;
    PORT
      LAYER met2 ;
        RECT 363.490 296.000 363.770 300.000 ;
    END
  END mstream_o[319]
  PIN mstream_o[31]
    DIRECTION OUTPUT TRISTATE ;
    USE SIGNAL ;
    ANTENNADIFFAREA 0.795200 ;
    PORT
      LAYER met2 ;
        RECT 98.530 296.000 98.810 300.000 ;
    END
  END mstream_o[31]
  PIN mstream_o[320]
    DIRECTION OUTPUT TRISTATE ;
    USE SIGNAL ;
    ANTENNADIFFAREA 0.795200 ;
    PORT
      LAYER met2 ;
        RECT 364.410 296.000 364.690 300.000 ;
    END
  END mstream_o[320]
  PIN mstream_o[321]
    DIRECTION OUTPUT TRISTATE ;
    USE SIGNAL ;
    ANTENNADIFFAREA 0.795200 ;
    PORT
      LAYER met2 ;
        RECT 365.330 296.000 365.610 300.000 ;
    END
  END mstream_o[321]
  PIN mstream_o[322]
    DIRECTION OUTPUT TRISTATE ;
    USE SIGNAL ;
    ANTENNADIFFAREA 0.795200 ;
    PORT
      LAYER met2 ;
        RECT 366.250 296.000 366.530 300.000 ;
    END
  END mstream_o[322]
  PIN mstream_o[323]
    DIRECTION OUTPUT TRISTATE ;
    USE SIGNAL ;
    ANTENNADIFFAREA 0.795200 ;
    PORT
      LAYER met2 ;
        RECT 367.170 296.000 367.450 300.000 ;
    END
  END mstream_o[323]
  PIN mstream_o[324]
    DIRECTION OUTPUT TRISTATE ;
    USE SIGNAL ;
    ANTENNADIFFAREA 0.795200 ;
    PORT
      LAYER met2 ;
        RECT 368.090 296.000 368.370 300.000 ;
    END
  END mstream_o[324]
  PIN mstream_o[325]
    DIRECTION OUTPUT TRISTATE ;
    USE SIGNAL ;
    ANTENNADIFFAREA 0.795200 ;
    PORT
      LAYER met2 ;
        RECT 369.010 296.000 369.290 300.000 ;
    END
  END mstream_o[325]
  PIN mstream_o[326]
    DIRECTION OUTPUT TRISTATE ;
    USE SIGNAL ;
    ANTENNADIFFAREA 0.795200 ;
    PORT
      LAYER met2 ;
        RECT 369.930 296.000 370.210 300.000 ;
    END
  END mstream_o[326]
  PIN mstream_o[327]
    DIRECTION OUTPUT TRISTATE ;
    USE SIGNAL ;
    ANTENNADIFFAREA 0.795200 ;
    PORT
      LAYER met2 ;
        RECT 370.850 296.000 371.130 300.000 ;
    END
  END mstream_o[327]
  PIN mstream_o[328]
    DIRECTION OUTPUT TRISTATE ;
    USE SIGNAL ;
    ANTENNADIFFAREA 0.795200 ;
    PORT
      LAYER met2 ;
        RECT 371.770 296.000 372.050 300.000 ;
    END
  END mstream_o[328]
  PIN mstream_o[329]
    DIRECTION OUTPUT TRISTATE ;
    USE SIGNAL ;
    ANTENNADIFFAREA 0.795200 ;
    PORT
      LAYER met2 ;
        RECT 372.690 296.000 372.970 300.000 ;
    END
  END mstream_o[329]
  PIN mstream_o[32]
    DIRECTION OUTPUT TRISTATE ;
    USE SIGNAL ;
    ANTENNADIFFAREA 0.795200 ;
    PORT
      LAYER met2 ;
        RECT 99.450 296.000 99.730 300.000 ;
    END
  END mstream_o[32]
  PIN mstream_o[330]
    DIRECTION OUTPUT TRISTATE ;
    USE SIGNAL ;
    ANTENNADIFFAREA 0.795200 ;
    PORT
      LAYER met2 ;
        RECT 373.610 296.000 373.890 300.000 ;
    END
  END mstream_o[330]
  PIN mstream_o[331]
    DIRECTION OUTPUT TRISTATE ;
    USE SIGNAL ;
    ANTENNADIFFAREA 0.795200 ;
    PORT
      LAYER met2 ;
        RECT 374.530 296.000 374.810 300.000 ;
    END
  END mstream_o[331]
  PIN mstream_o[332]
    DIRECTION OUTPUT TRISTATE ;
    USE SIGNAL ;
    ANTENNADIFFAREA 0.795200 ;
    PORT
      LAYER met2 ;
        RECT 375.450 296.000 375.730 300.000 ;
    END
  END mstream_o[332]
  PIN mstream_o[333]
    DIRECTION OUTPUT TRISTATE ;
    USE SIGNAL ;
    ANTENNADIFFAREA 0.795200 ;
    PORT
      LAYER met2 ;
        RECT 376.370 296.000 376.650 300.000 ;
    END
  END mstream_o[333]
  PIN mstream_o[334]
    DIRECTION OUTPUT TRISTATE ;
    USE SIGNAL ;
    ANTENNADIFFAREA 0.795200 ;
    PORT
      LAYER met2 ;
        RECT 377.290 296.000 377.570 300.000 ;
    END
  END mstream_o[334]
  PIN mstream_o[335]
    DIRECTION OUTPUT TRISTATE ;
    USE SIGNAL ;
    ANTENNADIFFAREA 0.795200 ;
    PORT
      LAYER met2 ;
        RECT 378.210 296.000 378.490 300.000 ;
    END
  END mstream_o[335]
  PIN mstream_o[336]
    DIRECTION OUTPUT TRISTATE ;
    USE SIGNAL ;
    ANTENNADIFFAREA 0.795200 ;
    PORT
      LAYER met2 ;
        RECT 379.130 296.000 379.410 300.000 ;
    END
  END mstream_o[336]
  PIN mstream_o[337]
    DIRECTION OUTPUT TRISTATE ;
    USE SIGNAL ;
    ANTENNADIFFAREA 0.795200 ;
    PORT
      LAYER met2 ;
        RECT 380.050 296.000 380.330 300.000 ;
    END
  END mstream_o[337]
  PIN mstream_o[338]
    DIRECTION OUTPUT TRISTATE ;
    USE SIGNAL ;
    ANTENNADIFFAREA 0.795200 ;
    PORT
      LAYER met2 ;
        RECT 380.970 296.000 381.250 300.000 ;
    END
  END mstream_o[338]
  PIN mstream_o[339]
    DIRECTION OUTPUT TRISTATE ;
    USE SIGNAL ;
    ANTENNADIFFAREA 0.795200 ;
    PORT
      LAYER met2 ;
        RECT 381.890 296.000 382.170 300.000 ;
    END
  END mstream_o[339]
  PIN mstream_o[33]
    DIRECTION OUTPUT TRISTATE ;
    USE SIGNAL ;
    ANTENNADIFFAREA 0.795200 ;
    PORT
      LAYER met2 ;
        RECT 100.370 296.000 100.650 300.000 ;
    END
  END mstream_o[33]
  PIN mstream_o[340]
    DIRECTION OUTPUT TRISTATE ;
    USE SIGNAL ;
    ANTENNADIFFAREA 0.795200 ;
    PORT
      LAYER met2 ;
        RECT 382.810 296.000 383.090 300.000 ;
    END
  END mstream_o[340]
  PIN mstream_o[341]
    DIRECTION OUTPUT TRISTATE ;
    USE SIGNAL ;
    ANTENNADIFFAREA 0.795200 ;
    PORT
      LAYER met2 ;
        RECT 383.730 296.000 384.010 300.000 ;
    END
  END mstream_o[341]
  PIN mstream_o[342]
    DIRECTION OUTPUT TRISTATE ;
    USE SIGNAL ;
    ANTENNADIFFAREA 0.795200 ;
    PORT
      LAYER met2 ;
        RECT 384.650 296.000 384.930 300.000 ;
    END
  END mstream_o[342]
  PIN mstream_o[343]
    DIRECTION OUTPUT TRISTATE ;
    USE SIGNAL ;
    ANTENNADIFFAREA 0.795200 ;
    PORT
      LAYER met2 ;
        RECT 385.570 296.000 385.850 300.000 ;
    END
  END mstream_o[343]
  PIN mstream_o[344]
    DIRECTION OUTPUT TRISTATE ;
    USE SIGNAL ;
    ANTENNADIFFAREA 0.795200 ;
    PORT
      LAYER met2 ;
        RECT 386.490 296.000 386.770 300.000 ;
    END
  END mstream_o[344]
  PIN mstream_o[345]
    DIRECTION OUTPUT TRISTATE ;
    USE SIGNAL ;
    ANTENNADIFFAREA 0.795200 ;
    PORT
      LAYER met2 ;
        RECT 387.410 296.000 387.690 300.000 ;
    END
  END mstream_o[345]
  PIN mstream_o[346]
    DIRECTION OUTPUT TRISTATE ;
    USE SIGNAL ;
    ANTENNADIFFAREA 0.795200 ;
    PORT
      LAYER met2 ;
        RECT 388.330 296.000 388.610 300.000 ;
    END
  END mstream_o[346]
  PIN mstream_o[347]
    DIRECTION OUTPUT TRISTATE ;
    USE SIGNAL ;
    ANTENNADIFFAREA 0.795200 ;
    PORT
      LAYER met2 ;
        RECT 389.250 296.000 389.530 300.000 ;
    END
  END mstream_o[347]
  PIN mstream_o[348]
    DIRECTION OUTPUT TRISTATE ;
    USE SIGNAL ;
    ANTENNADIFFAREA 0.795200 ;
    PORT
      LAYER met2 ;
        RECT 390.170 296.000 390.450 300.000 ;
    END
  END mstream_o[348]
  PIN mstream_o[349]
    DIRECTION OUTPUT TRISTATE ;
    USE SIGNAL ;
    ANTENNADIFFAREA 0.795200 ;
    PORT
      LAYER met2 ;
        RECT 391.090 296.000 391.370 300.000 ;
    END
  END mstream_o[349]
  PIN mstream_o[34]
    DIRECTION OUTPUT TRISTATE ;
    USE SIGNAL ;
    ANTENNADIFFAREA 0.795200 ;
    PORT
      LAYER met2 ;
        RECT 101.290 296.000 101.570 300.000 ;
    END
  END mstream_o[34]
  PIN mstream_o[350]
    DIRECTION OUTPUT TRISTATE ;
    USE SIGNAL ;
    ANTENNADIFFAREA 0.795200 ;
    PORT
      LAYER met2 ;
        RECT 392.010 296.000 392.290 300.000 ;
    END
  END mstream_o[350]
  PIN mstream_o[351]
    DIRECTION OUTPUT TRISTATE ;
    USE SIGNAL ;
    ANTENNADIFFAREA 0.795200 ;
    PORT
      LAYER met2 ;
        RECT 392.930 296.000 393.210 300.000 ;
    END
  END mstream_o[351]
  PIN mstream_o[352]
    DIRECTION OUTPUT TRISTATE ;
    USE SIGNAL ;
    ANTENNADIFFAREA 0.795200 ;
    PORT
      LAYER met2 ;
        RECT 393.850 296.000 394.130 300.000 ;
    END
  END mstream_o[352]
  PIN mstream_o[353]
    DIRECTION OUTPUT TRISTATE ;
    USE SIGNAL ;
    ANTENNADIFFAREA 0.795200 ;
    PORT
      LAYER met2 ;
        RECT 394.770 296.000 395.050 300.000 ;
    END
  END mstream_o[353]
  PIN mstream_o[354]
    DIRECTION OUTPUT TRISTATE ;
    USE SIGNAL ;
    ANTENNADIFFAREA 0.795200 ;
    PORT
      LAYER met2 ;
        RECT 395.690 296.000 395.970 300.000 ;
    END
  END mstream_o[354]
  PIN mstream_o[355]
    DIRECTION OUTPUT TRISTATE ;
    USE SIGNAL ;
    ANTENNADIFFAREA 0.795200 ;
    PORT
      LAYER met2 ;
        RECT 396.610 296.000 396.890 300.000 ;
    END
  END mstream_o[355]
  PIN mstream_o[356]
    DIRECTION OUTPUT TRISTATE ;
    USE SIGNAL ;
    ANTENNADIFFAREA 0.795200 ;
    PORT
      LAYER met2 ;
        RECT 397.530 296.000 397.810 300.000 ;
    END
  END mstream_o[356]
  PIN mstream_o[357]
    DIRECTION OUTPUT TRISTATE ;
    USE SIGNAL ;
    ANTENNADIFFAREA 0.795200 ;
    PORT
      LAYER met2 ;
        RECT 398.450 296.000 398.730 300.000 ;
    END
  END mstream_o[357]
  PIN mstream_o[358]
    DIRECTION OUTPUT TRISTATE ;
    USE SIGNAL ;
    ANTENNADIFFAREA 0.795200 ;
    PORT
      LAYER met2 ;
        RECT 399.370 296.000 399.650 300.000 ;
    END
  END mstream_o[358]
  PIN mstream_o[359]
    DIRECTION OUTPUT TRISTATE ;
    USE SIGNAL ;
    ANTENNADIFFAREA 0.795200 ;
    PORT
      LAYER met2 ;
        RECT 400.290 296.000 400.570 300.000 ;
    END
  END mstream_o[359]
  PIN mstream_o[35]
    DIRECTION OUTPUT TRISTATE ;
    USE SIGNAL ;
    ANTENNADIFFAREA 0.795200 ;
    PORT
      LAYER met2 ;
        RECT 102.210 296.000 102.490 300.000 ;
    END
  END mstream_o[35]
  PIN mstream_o[360]
    DIRECTION OUTPUT TRISTATE ;
    USE SIGNAL ;
    ANTENNADIFFAREA 0.795200 ;
    PORT
      LAYER met2 ;
        RECT 401.210 296.000 401.490 300.000 ;
    END
  END mstream_o[360]
  PIN mstream_o[361]
    DIRECTION OUTPUT TRISTATE ;
    USE SIGNAL ;
    ANTENNADIFFAREA 0.795200 ;
    PORT
      LAYER met2 ;
        RECT 402.130 296.000 402.410 300.000 ;
    END
  END mstream_o[361]
  PIN mstream_o[362]
    DIRECTION OUTPUT TRISTATE ;
    USE SIGNAL ;
    ANTENNADIFFAREA 0.795200 ;
    PORT
      LAYER met2 ;
        RECT 403.050 296.000 403.330 300.000 ;
    END
  END mstream_o[362]
  PIN mstream_o[363]
    DIRECTION OUTPUT TRISTATE ;
    USE SIGNAL ;
    ANTENNADIFFAREA 0.795200 ;
    PORT
      LAYER met2 ;
        RECT 403.970 296.000 404.250 300.000 ;
    END
  END mstream_o[363]
  PIN mstream_o[364]
    DIRECTION OUTPUT TRISTATE ;
    USE SIGNAL ;
    ANTENNADIFFAREA 0.795200 ;
    PORT
      LAYER met2 ;
        RECT 404.890 296.000 405.170 300.000 ;
    END
  END mstream_o[364]
  PIN mstream_o[365]
    DIRECTION OUTPUT TRISTATE ;
    USE SIGNAL ;
    ANTENNADIFFAREA 0.795200 ;
    PORT
      LAYER met2 ;
        RECT 405.810 296.000 406.090 300.000 ;
    END
  END mstream_o[365]
  PIN mstream_o[366]
    DIRECTION OUTPUT TRISTATE ;
    USE SIGNAL ;
    ANTENNADIFFAREA 0.795200 ;
    PORT
      LAYER met2 ;
        RECT 406.730 296.000 407.010 300.000 ;
    END
  END mstream_o[366]
  PIN mstream_o[367]
    DIRECTION OUTPUT TRISTATE ;
    USE SIGNAL ;
    ANTENNADIFFAREA 0.795200 ;
    PORT
      LAYER met2 ;
        RECT 407.650 296.000 407.930 300.000 ;
    END
  END mstream_o[367]
  PIN mstream_o[368]
    DIRECTION OUTPUT TRISTATE ;
    USE SIGNAL ;
    ANTENNADIFFAREA 0.795200 ;
    PORT
      LAYER met2 ;
        RECT 408.570 296.000 408.850 300.000 ;
    END
  END mstream_o[368]
  PIN mstream_o[369]
    DIRECTION OUTPUT TRISTATE ;
    USE SIGNAL ;
    ANTENNADIFFAREA 0.795200 ;
    PORT
      LAYER met2 ;
        RECT 409.490 296.000 409.770 300.000 ;
    END
  END mstream_o[369]
  PIN mstream_o[36]
    DIRECTION OUTPUT TRISTATE ;
    USE SIGNAL ;
    ANTENNADIFFAREA 0.795200 ;
    PORT
      LAYER met2 ;
        RECT 103.130 296.000 103.410 300.000 ;
    END
  END mstream_o[36]
  PIN mstream_o[370]
    DIRECTION OUTPUT TRISTATE ;
    USE SIGNAL ;
    ANTENNADIFFAREA 0.795200 ;
    PORT
      LAYER met2 ;
        RECT 410.410 296.000 410.690 300.000 ;
    END
  END mstream_o[370]
  PIN mstream_o[371]
    DIRECTION OUTPUT TRISTATE ;
    USE SIGNAL ;
    ANTENNADIFFAREA 0.795200 ;
    PORT
      LAYER met2 ;
        RECT 411.330 296.000 411.610 300.000 ;
    END
  END mstream_o[371]
  PIN mstream_o[372]
    DIRECTION OUTPUT TRISTATE ;
    USE SIGNAL ;
    ANTENNADIFFAREA 0.795200 ;
    PORT
      LAYER met2 ;
        RECT 412.250 296.000 412.530 300.000 ;
    END
  END mstream_o[372]
  PIN mstream_o[373]
    DIRECTION OUTPUT TRISTATE ;
    USE SIGNAL ;
    ANTENNADIFFAREA 0.795200 ;
    PORT
      LAYER met2 ;
        RECT 413.170 296.000 413.450 300.000 ;
    END
  END mstream_o[373]
  PIN mstream_o[374]
    DIRECTION OUTPUT TRISTATE ;
    USE SIGNAL ;
    ANTENNADIFFAREA 0.795200 ;
    PORT
      LAYER met2 ;
        RECT 414.090 296.000 414.370 300.000 ;
    END
  END mstream_o[374]
  PIN mstream_o[375]
    DIRECTION OUTPUT TRISTATE ;
    USE SIGNAL ;
    ANTENNADIFFAREA 0.795200 ;
    PORT
      LAYER met2 ;
        RECT 415.010 296.000 415.290 300.000 ;
    END
  END mstream_o[375]
  PIN mstream_o[376]
    DIRECTION OUTPUT TRISTATE ;
    USE SIGNAL ;
    ANTENNADIFFAREA 0.795200 ;
    PORT
      LAYER met2 ;
        RECT 415.930 296.000 416.210 300.000 ;
    END
  END mstream_o[376]
  PIN mstream_o[377]
    DIRECTION OUTPUT TRISTATE ;
    USE SIGNAL ;
    ANTENNADIFFAREA 0.795200 ;
    PORT
      LAYER met2 ;
        RECT 416.850 296.000 417.130 300.000 ;
    END
  END mstream_o[377]
  PIN mstream_o[378]
    DIRECTION OUTPUT TRISTATE ;
    USE SIGNAL ;
    ANTENNADIFFAREA 0.795200 ;
    PORT
      LAYER met2 ;
        RECT 417.770 296.000 418.050 300.000 ;
    END
  END mstream_o[378]
  PIN mstream_o[379]
    DIRECTION OUTPUT TRISTATE ;
    USE SIGNAL ;
    ANTENNADIFFAREA 0.795200 ;
    PORT
      LAYER met2 ;
        RECT 418.690 296.000 418.970 300.000 ;
    END
  END mstream_o[379]
  PIN mstream_o[37]
    DIRECTION OUTPUT TRISTATE ;
    USE SIGNAL ;
    ANTENNADIFFAREA 0.795200 ;
    PORT
      LAYER met2 ;
        RECT 104.050 296.000 104.330 300.000 ;
    END
  END mstream_o[37]
  PIN mstream_o[380]
    DIRECTION OUTPUT TRISTATE ;
    USE SIGNAL ;
    ANTENNADIFFAREA 0.795200 ;
    PORT
      LAYER met2 ;
        RECT 419.610 296.000 419.890 300.000 ;
    END
  END mstream_o[380]
  PIN mstream_o[381]
    DIRECTION OUTPUT TRISTATE ;
    USE SIGNAL ;
    ANTENNADIFFAREA 0.795200 ;
    PORT
      LAYER met2 ;
        RECT 420.530 296.000 420.810 300.000 ;
    END
  END mstream_o[381]
  PIN mstream_o[382]
    DIRECTION OUTPUT TRISTATE ;
    USE SIGNAL ;
    ANTENNADIFFAREA 0.795200 ;
    PORT
      LAYER met2 ;
        RECT 421.450 296.000 421.730 300.000 ;
    END
  END mstream_o[382]
  PIN mstream_o[383]
    DIRECTION OUTPUT TRISTATE ;
    USE SIGNAL ;
    ANTENNADIFFAREA 0.795200 ;
    PORT
      LAYER met2 ;
        RECT 422.370 296.000 422.650 300.000 ;
    END
  END mstream_o[383]
  PIN mstream_o[384]
    DIRECTION OUTPUT TRISTATE ;
    USE SIGNAL ;
    ANTENNADIFFAREA 0.795200 ;
    PORT
      LAYER met2 ;
        RECT 423.290 296.000 423.570 300.000 ;
    END
  END mstream_o[384]
  PIN mstream_o[385]
    DIRECTION OUTPUT TRISTATE ;
    USE SIGNAL ;
    ANTENNADIFFAREA 0.795200 ;
    PORT
      LAYER met2 ;
        RECT 424.210 296.000 424.490 300.000 ;
    END
  END mstream_o[385]
  PIN mstream_o[386]
    DIRECTION OUTPUT TRISTATE ;
    USE SIGNAL ;
    ANTENNADIFFAREA 0.795200 ;
    PORT
      LAYER met2 ;
        RECT 425.130 296.000 425.410 300.000 ;
    END
  END mstream_o[386]
  PIN mstream_o[387]
    DIRECTION OUTPUT TRISTATE ;
    USE SIGNAL ;
    ANTENNADIFFAREA 0.795200 ;
    PORT
      LAYER met2 ;
        RECT 426.050 296.000 426.330 300.000 ;
    END
  END mstream_o[387]
  PIN mstream_o[388]
    DIRECTION OUTPUT TRISTATE ;
    USE SIGNAL ;
    ANTENNADIFFAREA 0.795200 ;
    PORT
      LAYER met2 ;
        RECT 426.970 296.000 427.250 300.000 ;
    END
  END mstream_o[388]
  PIN mstream_o[389]
    DIRECTION OUTPUT TRISTATE ;
    USE SIGNAL ;
    ANTENNADIFFAREA 0.795200 ;
    PORT
      LAYER met2 ;
        RECT 427.890 296.000 428.170 300.000 ;
    END
  END mstream_o[389]
  PIN mstream_o[38]
    DIRECTION OUTPUT TRISTATE ;
    USE SIGNAL ;
    ANTENNADIFFAREA 0.795200 ;
    PORT
      LAYER met2 ;
        RECT 104.970 296.000 105.250 300.000 ;
    END
  END mstream_o[38]
  PIN mstream_o[390]
    DIRECTION OUTPUT TRISTATE ;
    USE SIGNAL ;
    ANTENNADIFFAREA 0.795200 ;
    PORT
      LAYER met2 ;
        RECT 428.810 296.000 429.090 300.000 ;
    END
  END mstream_o[390]
  PIN mstream_o[391]
    DIRECTION OUTPUT TRISTATE ;
    USE SIGNAL ;
    ANTENNADIFFAREA 0.795200 ;
    PORT
      LAYER met2 ;
        RECT 429.730 296.000 430.010 300.000 ;
    END
  END mstream_o[391]
  PIN mstream_o[392]
    DIRECTION OUTPUT TRISTATE ;
    USE SIGNAL ;
    ANTENNADIFFAREA 0.795200 ;
    PORT
      LAYER met2 ;
        RECT 430.650 296.000 430.930 300.000 ;
    END
  END mstream_o[392]
  PIN mstream_o[393]
    DIRECTION OUTPUT TRISTATE ;
    USE SIGNAL ;
    ANTENNADIFFAREA 0.795200 ;
    PORT
      LAYER met2 ;
        RECT 431.570 296.000 431.850 300.000 ;
    END
  END mstream_o[393]
  PIN mstream_o[394]
    DIRECTION OUTPUT TRISTATE ;
    USE SIGNAL ;
    ANTENNADIFFAREA 0.795200 ;
    PORT
      LAYER met2 ;
        RECT 432.490 296.000 432.770 300.000 ;
    END
  END mstream_o[394]
  PIN mstream_o[395]
    DIRECTION OUTPUT TRISTATE ;
    USE SIGNAL ;
    ANTENNADIFFAREA 0.795200 ;
    PORT
      LAYER met2 ;
        RECT 433.410 296.000 433.690 300.000 ;
    END
  END mstream_o[395]
  PIN mstream_o[396]
    DIRECTION OUTPUT TRISTATE ;
    USE SIGNAL ;
    ANTENNADIFFAREA 0.795200 ;
    PORT
      LAYER met2 ;
        RECT 434.330 296.000 434.610 300.000 ;
    END
  END mstream_o[396]
  PIN mstream_o[397]
    DIRECTION OUTPUT TRISTATE ;
    USE SIGNAL ;
    ANTENNADIFFAREA 0.795200 ;
    PORT
      LAYER met2 ;
        RECT 435.250 296.000 435.530 300.000 ;
    END
  END mstream_o[397]
  PIN mstream_o[398]
    DIRECTION OUTPUT TRISTATE ;
    USE SIGNAL ;
    ANTENNADIFFAREA 0.795200 ;
    PORT
      LAYER met2 ;
        RECT 436.170 296.000 436.450 300.000 ;
    END
  END mstream_o[398]
  PIN mstream_o[399]
    DIRECTION OUTPUT TRISTATE ;
    USE SIGNAL ;
    ANTENNADIFFAREA 0.795200 ;
    PORT
      LAYER met2 ;
        RECT 437.090 296.000 437.370 300.000 ;
    END
  END mstream_o[399]
  PIN mstream_o[39]
    DIRECTION OUTPUT TRISTATE ;
    USE SIGNAL ;
    ANTENNADIFFAREA 0.795200 ;
    PORT
      LAYER met2 ;
        RECT 105.890 296.000 106.170 300.000 ;
    END
  END mstream_o[39]
  PIN mstream_o[3]
    DIRECTION OUTPUT TRISTATE ;
    USE SIGNAL ;
    ANTENNADIFFAREA 0.795200 ;
    PORT
      LAYER met2 ;
        RECT 72.770 296.000 73.050 300.000 ;
    END
  END mstream_o[3]
  PIN mstream_o[400]
    DIRECTION OUTPUT TRISTATE ;
    USE SIGNAL ;
    ANTENNADIFFAREA 0.795200 ;
    PORT
      LAYER met2 ;
        RECT 438.010 296.000 438.290 300.000 ;
    END
  END mstream_o[400]
  PIN mstream_o[401]
    DIRECTION OUTPUT TRISTATE ;
    USE SIGNAL ;
    ANTENNADIFFAREA 0.795200 ;
    PORT
      LAYER met2 ;
        RECT 438.930 296.000 439.210 300.000 ;
    END
  END mstream_o[401]
  PIN mstream_o[402]
    DIRECTION OUTPUT TRISTATE ;
    USE SIGNAL ;
    ANTENNADIFFAREA 0.795200 ;
    PORT
      LAYER met2 ;
        RECT 439.850 296.000 440.130 300.000 ;
    END
  END mstream_o[402]
  PIN mstream_o[403]
    DIRECTION OUTPUT TRISTATE ;
    USE SIGNAL ;
    ANTENNADIFFAREA 0.795200 ;
    PORT
      LAYER met2 ;
        RECT 440.770 296.000 441.050 300.000 ;
    END
  END mstream_o[403]
  PIN mstream_o[404]
    DIRECTION OUTPUT TRISTATE ;
    USE SIGNAL ;
    ANTENNADIFFAREA 0.795200 ;
    PORT
      LAYER met2 ;
        RECT 441.690 296.000 441.970 300.000 ;
    END
  END mstream_o[404]
  PIN mstream_o[405]
    DIRECTION OUTPUT TRISTATE ;
    USE SIGNAL ;
    ANTENNADIFFAREA 0.795200 ;
    PORT
      LAYER met2 ;
        RECT 442.610 296.000 442.890 300.000 ;
    END
  END mstream_o[405]
  PIN mstream_o[406]
    DIRECTION OUTPUT TRISTATE ;
    USE SIGNAL ;
    ANTENNADIFFAREA 0.795200 ;
    PORT
      LAYER met2 ;
        RECT 443.530 296.000 443.810 300.000 ;
    END
  END mstream_o[406]
  PIN mstream_o[407]
    DIRECTION OUTPUT TRISTATE ;
    USE SIGNAL ;
    ANTENNADIFFAREA 0.795200 ;
    PORT
      LAYER met2 ;
        RECT 444.450 296.000 444.730 300.000 ;
    END
  END mstream_o[407]
  PIN mstream_o[408]
    DIRECTION OUTPUT TRISTATE ;
    USE SIGNAL ;
    ANTENNADIFFAREA 0.795200 ;
    PORT
      LAYER met2 ;
        RECT 445.370 296.000 445.650 300.000 ;
    END
  END mstream_o[408]
  PIN mstream_o[409]
    DIRECTION OUTPUT TRISTATE ;
    USE SIGNAL ;
    ANTENNADIFFAREA 0.795200 ;
    PORT
      LAYER met2 ;
        RECT 446.290 296.000 446.570 300.000 ;
    END
  END mstream_o[409]
  PIN mstream_o[40]
    DIRECTION OUTPUT TRISTATE ;
    USE SIGNAL ;
    ANTENNADIFFAREA 0.795200 ;
    PORT
      LAYER met2 ;
        RECT 106.810 296.000 107.090 300.000 ;
    END
  END mstream_o[40]
  PIN mstream_o[410]
    DIRECTION OUTPUT TRISTATE ;
    USE SIGNAL ;
    ANTENNADIFFAREA 0.795200 ;
    PORT
      LAYER met2 ;
        RECT 447.210 296.000 447.490 300.000 ;
    END
  END mstream_o[410]
  PIN mstream_o[411]
    DIRECTION OUTPUT TRISTATE ;
    USE SIGNAL ;
    ANTENNADIFFAREA 0.795200 ;
    PORT
      LAYER met2 ;
        RECT 448.130 296.000 448.410 300.000 ;
    END
  END mstream_o[411]
  PIN mstream_o[412]
    DIRECTION OUTPUT TRISTATE ;
    USE SIGNAL ;
    ANTENNADIFFAREA 0.795200 ;
    PORT
      LAYER met2 ;
        RECT 449.050 296.000 449.330 300.000 ;
    END
  END mstream_o[412]
  PIN mstream_o[413]
    DIRECTION OUTPUT TRISTATE ;
    USE SIGNAL ;
    ANTENNADIFFAREA 0.795200 ;
    PORT
      LAYER met2 ;
        RECT 449.970 296.000 450.250 300.000 ;
    END
  END mstream_o[413]
  PIN mstream_o[414]
    DIRECTION OUTPUT TRISTATE ;
    USE SIGNAL ;
    ANTENNADIFFAREA 0.795200 ;
    PORT
      LAYER met2 ;
        RECT 450.890 296.000 451.170 300.000 ;
    END
  END mstream_o[414]
  PIN mstream_o[415]
    DIRECTION OUTPUT TRISTATE ;
    USE SIGNAL ;
    ANTENNADIFFAREA 0.795200 ;
    PORT
      LAYER met2 ;
        RECT 451.810 296.000 452.090 300.000 ;
    END
  END mstream_o[415]
  PIN mstream_o[416]
    DIRECTION OUTPUT TRISTATE ;
    USE SIGNAL ;
    ANTENNADIFFAREA 0.795200 ;
    PORT
      LAYER met2 ;
        RECT 452.730 296.000 453.010 300.000 ;
    END
  END mstream_o[416]
  PIN mstream_o[417]
    DIRECTION OUTPUT TRISTATE ;
    USE SIGNAL ;
    ANTENNADIFFAREA 0.795200 ;
    PORT
      LAYER met2 ;
        RECT 453.650 296.000 453.930 300.000 ;
    END
  END mstream_o[417]
  PIN mstream_o[418]
    DIRECTION OUTPUT TRISTATE ;
    USE SIGNAL ;
    ANTENNADIFFAREA 0.795200 ;
    PORT
      LAYER met2 ;
        RECT 454.570 296.000 454.850 300.000 ;
    END
  END mstream_o[418]
  PIN mstream_o[419]
    DIRECTION OUTPUT TRISTATE ;
    USE SIGNAL ;
    ANTENNADIFFAREA 0.795200 ;
    PORT
      LAYER met2 ;
        RECT 455.490 296.000 455.770 300.000 ;
    END
  END mstream_o[419]
  PIN mstream_o[41]
    DIRECTION OUTPUT TRISTATE ;
    USE SIGNAL ;
    ANTENNADIFFAREA 0.795200 ;
    PORT
      LAYER met2 ;
        RECT 107.730 296.000 108.010 300.000 ;
    END
  END mstream_o[41]
  PIN mstream_o[420]
    DIRECTION OUTPUT TRISTATE ;
    USE SIGNAL ;
    ANTENNADIFFAREA 0.795200 ;
    PORT
      LAYER met2 ;
        RECT 456.410 296.000 456.690 300.000 ;
    END
  END mstream_o[420]
  PIN mstream_o[421]
    DIRECTION OUTPUT TRISTATE ;
    USE SIGNAL ;
    ANTENNADIFFAREA 0.795200 ;
    PORT
      LAYER met2 ;
        RECT 457.330 296.000 457.610 300.000 ;
    END
  END mstream_o[421]
  PIN mstream_o[422]
    DIRECTION OUTPUT TRISTATE ;
    USE SIGNAL ;
    ANTENNADIFFAREA 0.795200 ;
    PORT
      LAYER met2 ;
        RECT 458.250 296.000 458.530 300.000 ;
    END
  END mstream_o[422]
  PIN mstream_o[423]
    DIRECTION OUTPUT TRISTATE ;
    USE SIGNAL ;
    ANTENNADIFFAREA 0.795200 ;
    PORT
      LAYER met2 ;
        RECT 459.170 296.000 459.450 300.000 ;
    END
  END mstream_o[423]
  PIN mstream_o[424]
    DIRECTION OUTPUT TRISTATE ;
    USE SIGNAL ;
    ANTENNADIFFAREA 0.795200 ;
    PORT
      LAYER met2 ;
        RECT 460.090 296.000 460.370 300.000 ;
    END
  END mstream_o[424]
  PIN mstream_o[425]
    DIRECTION OUTPUT TRISTATE ;
    USE SIGNAL ;
    ANTENNADIFFAREA 0.795200 ;
    PORT
      LAYER met2 ;
        RECT 461.010 296.000 461.290 300.000 ;
    END
  END mstream_o[425]
  PIN mstream_o[426]
    DIRECTION OUTPUT TRISTATE ;
    USE SIGNAL ;
    ANTENNADIFFAREA 0.795200 ;
    PORT
      LAYER met2 ;
        RECT 461.930 296.000 462.210 300.000 ;
    END
  END mstream_o[426]
  PIN mstream_o[427]
    DIRECTION OUTPUT TRISTATE ;
    USE SIGNAL ;
    ANTENNADIFFAREA 0.795200 ;
    PORT
      LAYER met2 ;
        RECT 462.850 296.000 463.130 300.000 ;
    END
  END mstream_o[427]
  PIN mstream_o[428]
    DIRECTION OUTPUT TRISTATE ;
    USE SIGNAL ;
    ANTENNADIFFAREA 0.795200 ;
    PORT
      LAYER met2 ;
        RECT 463.770 296.000 464.050 300.000 ;
    END
  END mstream_o[428]
  PIN mstream_o[429]
    DIRECTION OUTPUT TRISTATE ;
    USE SIGNAL ;
    ANTENNADIFFAREA 0.795200 ;
    PORT
      LAYER met2 ;
        RECT 464.690 296.000 464.970 300.000 ;
    END
  END mstream_o[429]
  PIN mstream_o[42]
    DIRECTION OUTPUT TRISTATE ;
    USE SIGNAL ;
    ANTENNADIFFAREA 0.795200 ;
    PORT
      LAYER met2 ;
        RECT 108.650 296.000 108.930 300.000 ;
    END
  END mstream_o[42]
  PIN mstream_o[430]
    DIRECTION OUTPUT TRISTATE ;
    USE SIGNAL ;
    ANTENNADIFFAREA 0.795200 ;
    PORT
      LAYER met2 ;
        RECT 465.610 296.000 465.890 300.000 ;
    END
  END mstream_o[430]
  PIN mstream_o[431]
    DIRECTION OUTPUT TRISTATE ;
    USE SIGNAL ;
    ANTENNADIFFAREA 0.795200 ;
    PORT
      LAYER met2 ;
        RECT 466.530 296.000 466.810 300.000 ;
    END
  END mstream_o[431]
  PIN mstream_o[432]
    DIRECTION OUTPUT TRISTATE ;
    USE SIGNAL ;
    ANTENNADIFFAREA 0.795200 ;
    PORT
      LAYER met2 ;
        RECT 467.450 296.000 467.730 300.000 ;
    END
  END mstream_o[432]
  PIN mstream_o[433]
    DIRECTION OUTPUT TRISTATE ;
    USE SIGNAL ;
    ANTENNADIFFAREA 0.795200 ;
    PORT
      LAYER met2 ;
        RECT 468.370 296.000 468.650 300.000 ;
    END
  END mstream_o[433]
  PIN mstream_o[434]
    DIRECTION OUTPUT TRISTATE ;
    USE SIGNAL ;
    ANTENNADIFFAREA 0.795200 ;
    PORT
      LAYER met2 ;
        RECT 469.290 296.000 469.570 300.000 ;
    END
  END mstream_o[434]
  PIN mstream_o[435]
    DIRECTION OUTPUT TRISTATE ;
    USE SIGNAL ;
    ANTENNADIFFAREA 0.795200 ;
    PORT
      LAYER met2 ;
        RECT 470.210 296.000 470.490 300.000 ;
    END
  END mstream_o[435]
  PIN mstream_o[436]
    DIRECTION OUTPUT TRISTATE ;
    USE SIGNAL ;
    ANTENNADIFFAREA 0.795200 ;
    PORT
      LAYER met2 ;
        RECT 471.130 296.000 471.410 300.000 ;
    END
  END mstream_o[436]
  PIN mstream_o[437]
    DIRECTION OUTPUT TRISTATE ;
    USE SIGNAL ;
    ANTENNADIFFAREA 0.795200 ;
    PORT
      LAYER met2 ;
        RECT 472.050 296.000 472.330 300.000 ;
    END
  END mstream_o[437]
  PIN mstream_o[438]
    DIRECTION OUTPUT TRISTATE ;
    USE SIGNAL ;
    ANTENNADIFFAREA 0.795200 ;
    PORT
      LAYER met2 ;
        RECT 472.970 296.000 473.250 300.000 ;
    END
  END mstream_o[438]
  PIN mstream_o[439]
    DIRECTION OUTPUT TRISTATE ;
    USE SIGNAL ;
    ANTENNADIFFAREA 0.795200 ;
    PORT
      LAYER met2 ;
        RECT 473.890 296.000 474.170 300.000 ;
    END
  END mstream_o[439]
  PIN mstream_o[43]
    DIRECTION OUTPUT TRISTATE ;
    USE SIGNAL ;
    ANTENNADIFFAREA 0.795200 ;
    PORT
      LAYER met2 ;
        RECT 109.570 296.000 109.850 300.000 ;
    END
  END mstream_o[43]
  PIN mstream_o[440]
    DIRECTION OUTPUT TRISTATE ;
    USE SIGNAL ;
    ANTENNADIFFAREA 0.795200 ;
    PORT
      LAYER met2 ;
        RECT 474.810 296.000 475.090 300.000 ;
    END
  END mstream_o[440]
  PIN mstream_o[441]
    DIRECTION OUTPUT TRISTATE ;
    USE SIGNAL ;
    ANTENNADIFFAREA 0.795200 ;
    PORT
      LAYER met2 ;
        RECT 475.730 296.000 476.010 300.000 ;
    END
  END mstream_o[441]
  PIN mstream_o[442]
    DIRECTION OUTPUT TRISTATE ;
    USE SIGNAL ;
    ANTENNADIFFAREA 0.795200 ;
    PORT
      LAYER met2 ;
        RECT 476.650 296.000 476.930 300.000 ;
    END
  END mstream_o[442]
  PIN mstream_o[443]
    DIRECTION OUTPUT TRISTATE ;
    USE SIGNAL ;
    ANTENNADIFFAREA 0.795200 ;
    PORT
      LAYER met2 ;
        RECT 477.570 296.000 477.850 300.000 ;
    END
  END mstream_o[443]
  PIN mstream_o[444]
    DIRECTION OUTPUT TRISTATE ;
    USE SIGNAL ;
    ANTENNADIFFAREA 0.795200 ;
    PORT
      LAYER met2 ;
        RECT 478.490 296.000 478.770 300.000 ;
    END
  END mstream_o[444]
  PIN mstream_o[445]
    DIRECTION OUTPUT TRISTATE ;
    USE SIGNAL ;
    ANTENNADIFFAREA 0.795200 ;
    PORT
      LAYER met2 ;
        RECT 479.410 296.000 479.690 300.000 ;
    END
  END mstream_o[445]
  PIN mstream_o[446]
    DIRECTION OUTPUT TRISTATE ;
    USE SIGNAL ;
    ANTENNADIFFAREA 0.795200 ;
    PORT
      LAYER met2 ;
        RECT 480.330 296.000 480.610 300.000 ;
    END
  END mstream_o[446]
  PIN mstream_o[447]
    DIRECTION OUTPUT TRISTATE ;
    USE SIGNAL ;
    ANTENNADIFFAREA 0.795200 ;
    PORT
      LAYER met2 ;
        RECT 481.250 296.000 481.530 300.000 ;
    END
  END mstream_o[447]
  PIN mstream_o[448]
    DIRECTION OUTPUT TRISTATE ;
    USE SIGNAL ;
    ANTENNADIFFAREA 0.795200 ;
    PORT
      LAYER met2 ;
        RECT 482.170 296.000 482.450 300.000 ;
    END
  END mstream_o[448]
  PIN mstream_o[449]
    DIRECTION OUTPUT TRISTATE ;
    USE SIGNAL ;
    ANTENNADIFFAREA 0.795200 ;
    PORT
      LAYER met2 ;
        RECT 483.090 296.000 483.370 300.000 ;
    END
  END mstream_o[449]
  PIN mstream_o[44]
    DIRECTION OUTPUT TRISTATE ;
    USE SIGNAL ;
    ANTENNADIFFAREA 0.795200 ;
    PORT
      LAYER met2 ;
        RECT 110.490 296.000 110.770 300.000 ;
    END
  END mstream_o[44]
  PIN mstream_o[450]
    DIRECTION OUTPUT TRISTATE ;
    USE SIGNAL ;
    ANTENNADIFFAREA 0.795200 ;
    PORT
      LAYER met2 ;
        RECT 484.010 296.000 484.290 300.000 ;
    END
  END mstream_o[450]
  PIN mstream_o[451]
    DIRECTION OUTPUT TRISTATE ;
    USE SIGNAL ;
    ANTENNADIFFAREA 0.795200 ;
    PORT
      LAYER met2 ;
        RECT 484.930 296.000 485.210 300.000 ;
    END
  END mstream_o[451]
  PIN mstream_o[452]
    DIRECTION OUTPUT TRISTATE ;
    USE SIGNAL ;
    ANTENNADIFFAREA 0.795200 ;
    PORT
      LAYER met2 ;
        RECT 485.850 296.000 486.130 300.000 ;
    END
  END mstream_o[452]
  PIN mstream_o[453]
    DIRECTION OUTPUT TRISTATE ;
    USE SIGNAL ;
    ANTENNADIFFAREA 0.795200 ;
    PORT
      LAYER met2 ;
        RECT 486.770 296.000 487.050 300.000 ;
    END
  END mstream_o[453]
  PIN mstream_o[454]
    DIRECTION OUTPUT TRISTATE ;
    USE SIGNAL ;
    ANTENNADIFFAREA 0.795200 ;
    PORT
      LAYER met2 ;
        RECT 487.690 296.000 487.970 300.000 ;
    END
  END mstream_o[454]
  PIN mstream_o[455]
    DIRECTION OUTPUT TRISTATE ;
    USE SIGNAL ;
    ANTENNADIFFAREA 0.795200 ;
    PORT
      LAYER met2 ;
        RECT 488.610 296.000 488.890 300.000 ;
    END
  END mstream_o[455]
  PIN mstream_o[456]
    DIRECTION OUTPUT TRISTATE ;
    USE SIGNAL ;
    ANTENNADIFFAREA 0.795200 ;
    PORT
      LAYER met2 ;
        RECT 489.530 296.000 489.810 300.000 ;
    END
  END mstream_o[456]
  PIN mstream_o[457]
    DIRECTION OUTPUT TRISTATE ;
    USE SIGNAL ;
    ANTENNADIFFAREA 0.795200 ;
    PORT
      LAYER met2 ;
        RECT 490.450 296.000 490.730 300.000 ;
    END
  END mstream_o[457]
  PIN mstream_o[458]
    DIRECTION OUTPUT TRISTATE ;
    USE SIGNAL ;
    ANTENNADIFFAREA 0.795200 ;
    PORT
      LAYER met2 ;
        RECT 491.370 296.000 491.650 300.000 ;
    END
  END mstream_o[458]
  PIN mstream_o[459]
    DIRECTION OUTPUT TRISTATE ;
    USE SIGNAL ;
    ANTENNADIFFAREA 0.795200 ;
    PORT
      LAYER met2 ;
        RECT 492.290 296.000 492.570 300.000 ;
    END
  END mstream_o[459]
  PIN mstream_o[45]
    DIRECTION OUTPUT TRISTATE ;
    USE SIGNAL ;
    ANTENNADIFFAREA 0.795200 ;
    PORT
      LAYER met2 ;
        RECT 111.410 296.000 111.690 300.000 ;
    END
  END mstream_o[45]
  PIN mstream_o[460]
    DIRECTION OUTPUT TRISTATE ;
    USE SIGNAL ;
    ANTENNADIFFAREA 0.795200 ;
    PORT
      LAYER met2 ;
        RECT 493.210 296.000 493.490 300.000 ;
    END
  END mstream_o[460]
  PIN mstream_o[461]
    DIRECTION OUTPUT TRISTATE ;
    USE SIGNAL ;
    ANTENNADIFFAREA 0.795200 ;
    PORT
      LAYER met2 ;
        RECT 494.130 296.000 494.410 300.000 ;
    END
  END mstream_o[461]
  PIN mstream_o[462]
    DIRECTION OUTPUT TRISTATE ;
    USE SIGNAL ;
    ANTENNADIFFAREA 0.795200 ;
    PORT
      LAYER met2 ;
        RECT 495.050 296.000 495.330 300.000 ;
    END
  END mstream_o[462]
  PIN mstream_o[463]
    DIRECTION OUTPUT TRISTATE ;
    USE SIGNAL ;
    ANTENNADIFFAREA 0.795200 ;
    PORT
      LAYER met2 ;
        RECT 495.970 296.000 496.250 300.000 ;
    END
  END mstream_o[463]
  PIN mstream_o[464]
    DIRECTION OUTPUT TRISTATE ;
    USE SIGNAL ;
    ANTENNADIFFAREA 0.795200 ;
    PORT
      LAYER met2 ;
        RECT 496.890 296.000 497.170 300.000 ;
    END
  END mstream_o[464]
  PIN mstream_o[465]
    DIRECTION OUTPUT TRISTATE ;
    USE SIGNAL ;
    ANTENNADIFFAREA 0.795200 ;
    PORT
      LAYER met2 ;
        RECT 497.810 296.000 498.090 300.000 ;
    END
  END mstream_o[465]
  PIN mstream_o[466]
    DIRECTION OUTPUT TRISTATE ;
    USE SIGNAL ;
    ANTENNADIFFAREA 0.795200 ;
    PORT
      LAYER met2 ;
        RECT 498.730 296.000 499.010 300.000 ;
    END
  END mstream_o[466]
  PIN mstream_o[467]
    DIRECTION OUTPUT TRISTATE ;
    USE SIGNAL ;
    ANTENNADIFFAREA 0.795200 ;
    PORT
      LAYER met2 ;
        RECT 499.650 296.000 499.930 300.000 ;
    END
  END mstream_o[467]
  PIN mstream_o[468]
    DIRECTION OUTPUT TRISTATE ;
    USE SIGNAL ;
    ANTENNADIFFAREA 0.795200 ;
    PORT
      LAYER met2 ;
        RECT 500.570 296.000 500.850 300.000 ;
    END
  END mstream_o[468]
  PIN mstream_o[469]
    DIRECTION OUTPUT TRISTATE ;
    USE SIGNAL ;
    ANTENNADIFFAREA 0.795200 ;
    PORT
      LAYER met2 ;
        RECT 501.490 296.000 501.770 300.000 ;
    END
  END mstream_o[469]
  PIN mstream_o[46]
    DIRECTION OUTPUT TRISTATE ;
    USE SIGNAL ;
    ANTENNADIFFAREA 0.795200 ;
    PORT
      LAYER met2 ;
        RECT 112.330 296.000 112.610 300.000 ;
    END
  END mstream_o[46]
  PIN mstream_o[470]
    DIRECTION OUTPUT TRISTATE ;
    USE SIGNAL ;
    ANTENNADIFFAREA 0.795200 ;
    PORT
      LAYER met2 ;
        RECT 502.410 296.000 502.690 300.000 ;
    END
  END mstream_o[470]
  PIN mstream_o[471]
    DIRECTION OUTPUT TRISTATE ;
    USE SIGNAL ;
    ANTENNADIFFAREA 0.795200 ;
    PORT
      LAYER met2 ;
        RECT 503.330 296.000 503.610 300.000 ;
    END
  END mstream_o[471]
  PIN mstream_o[472]
    DIRECTION OUTPUT TRISTATE ;
    USE SIGNAL ;
    ANTENNADIFFAREA 0.795200 ;
    PORT
      LAYER met2 ;
        RECT 504.250 296.000 504.530 300.000 ;
    END
  END mstream_o[472]
  PIN mstream_o[473]
    DIRECTION OUTPUT TRISTATE ;
    USE SIGNAL ;
    ANTENNADIFFAREA 0.795200 ;
    PORT
      LAYER met2 ;
        RECT 505.170 296.000 505.450 300.000 ;
    END
  END mstream_o[473]
  PIN mstream_o[474]
    DIRECTION OUTPUT TRISTATE ;
    USE SIGNAL ;
    ANTENNADIFFAREA 0.795200 ;
    PORT
      LAYER met2 ;
        RECT 506.090 296.000 506.370 300.000 ;
    END
  END mstream_o[474]
  PIN mstream_o[475]
    DIRECTION OUTPUT TRISTATE ;
    USE SIGNAL ;
    ANTENNADIFFAREA 0.795200 ;
    PORT
      LAYER met2 ;
        RECT 507.010 296.000 507.290 300.000 ;
    END
  END mstream_o[475]
  PIN mstream_o[476]
    DIRECTION OUTPUT TRISTATE ;
    USE SIGNAL ;
    ANTENNADIFFAREA 0.795200 ;
    PORT
      LAYER met2 ;
        RECT 507.930 296.000 508.210 300.000 ;
    END
  END mstream_o[476]
  PIN mstream_o[477]
    DIRECTION OUTPUT TRISTATE ;
    USE SIGNAL ;
    ANTENNADIFFAREA 0.795200 ;
    PORT
      LAYER met2 ;
        RECT 508.850 296.000 509.130 300.000 ;
    END
  END mstream_o[477]
  PIN mstream_o[478]
    DIRECTION OUTPUT TRISTATE ;
    USE SIGNAL ;
    ANTENNADIFFAREA 0.795200 ;
    PORT
      LAYER met2 ;
        RECT 509.770 296.000 510.050 300.000 ;
    END
  END mstream_o[478]
  PIN mstream_o[479]
    DIRECTION OUTPUT TRISTATE ;
    USE SIGNAL ;
    ANTENNADIFFAREA 0.795200 ;
    PORT
      LAYER met2 ;
        RECT 510.690 296.000 510.970 300.000 ;
    END
  END mstream_o[479]
  PIN mstream_o[47]
    DIRECTION OUTPUT TRISTATE ;
    USE SIGNAL ;
    ANTENNADIFFAREA 0.795200 ;
    PORT
      LAYER met2 ;
        RECT 113.250 296.000 113.530 300.000 ;
    END
  END mstream_o[47]
  PIN mstream_o[480]
    DIRECTION OUTPUT TRISTATE ;
    USE SIGNAL ;
    ANTENNADIFFAREA 0.795200 ;
    PORT
      LAYER met2 ;
        RECT 511.610 296.000 511.890 300.000 ;
    END
  END mstream_o[480]
  PIN mstream_o[481]
    DIRECTION OUTPUT TRISTATE ;
    USE SIGNAL ;
    ANTENNADIFFAREA 0.795200 ;
    PORT
      LAYER met2 ;
        RECT 512.530 296.000 512.810 300.000 ;
    END
  END mstream_o[481]
  PIN mstream_o[482]
    DIRECTION OUTPUT TRISTATE ;
    USE SIGNAL ;
    ANTENNADIFFAREA 0.795200 ;
    PORT
      LAYER met2 ;
        RECT 513.450 296.000 513.730 300.000 ;
    END
  END mstream_o[482]
  PIN mstream_o[483]
    DIRECTION OUTPUT TRISTATE ;
    USE SIGNAL ;
    ANTENNADIFFAREA 0.795200 ;
    PORT
      LAYER met2 ;
        RECT 514.370 296.000 514.650 300.000 ;
    END
  END mstream_o[483]
  PIN mstream_o[484]
    DIRECTION OUTPUT TRISTATE ;
    USE SIGNAL ;
    ANTENNADIFFAREA 0.795200 ;
    PORT
      LAYER met2 ;
        RECT 515.290 296.000 515.570 300.000 ;
    END
  END mstream_o[484]
  PIN mstream_o[485]
    DIRECTION OUTPUT TRISTATE ;
    USE SIGNAL ;
    ANTENNADIFFAREA 0.795200 ;
    PORT
      LAYER met2 ;
        RECT 516.210 296.000 516.490 300.000 ;
    END
  END mstream_o[485]
  PIN mstream_o[486]
    DIRECTION OUTPUT TRISTATE ;
    USE SIGNAL ;
    ANTENNADIFFAREA 0.795200 ;
    PORT
      LAYER met2 ;
        RECT 517.130 296.000 517.410 300.000 ;
    END
  END mstream_o[486]
  PIN mstream_o[487]
    DIRECTION OUTPUT TRISTATE ;
    USE SIGNAL ;
    ANTENNADIFFAREA 0.795200 ;
    PORT
      LAYER met2 ;
        RECT 518.050 296.000 518.330 300.000 ;
    END
  END mstream_o[487]
  PIN mstream_o[488]
    DIRECTION OUTPUT TRISTATE ;
    USE SIGNAL ;
    ANTENNADIFFAREA 0.795200 ;
    PORT
      LAYER met2 ;
        RECT 518.970 296.000 519.250 300.000 ;
    END
  END mstream_o[488]
  PIN mstream_o[489]
    DIRECTION OUTPUT TRISTATE ;
    USE SIGNAL ;
    ANTENNADIFFAREA 0.795200 ;
    PORT
      LAYER met2 ;
        RECT 519.890 296.000 520.170 300.000 ;
    END
  END mstream_o[489]
  PIN mstream_o[48]
    DIRECTION OUTPUT TRISTATE ;
    USE SIGNAL ;
    ANTENNADIFFAREA 0.795200 ;
    PORT
      LAYER met2 ;
        RECT 114.170 296.000 114.450 300.000 ;
    END
  END mstream_o[48]
  PIN mstream_o[490]
    DIRECTION OUTPUT TRISTATE ;
    USE SIGNAL ;
    ANTENNADIFFAREA 0.795200 ;
    PORT
      LAYER met2 ;
        RECT 520.810 296.000 521.090 300.000 ;
    END
  END mstream_o[490]
  PIN mstream_o[491]
    DIRECTION OUTPUT TRISTATE ;
    USE SIGNAL ;
    ANTENNADIFFAREA 0.795200 ;
    PORT
      LAYER met2 ;
        RECT 521.730 296.000 522.010 300.000 ;
    END
  END mstream_o[491]
  PIN mstream_o[492]
    DIRECTION OUTPUT TRISTATE ;
    USE SIGNAL ;
    ANTENNADIFFAREA 0.795200 ;
    PORT
      LAYER met2 ;
        RECT 522.650 296.000 522.930 300.000 ;
    END
  END mstream_o[492]
  PIN mstream_o[493]
    DIRECTION OUTPUT TRISTATE ;
    USE SIGNAL ;
    ANTENNADIFFAREA 0.795200 ;
    PORT
      LAYER met2 ;
        RECT 523.570 296.000 523.850 300.000 ;
    END
  END mstream_o[493]
  PIN mstream_o[494]
    DIRECTION OUTPUT TRISTATE ;
    USE SIGNAL ;
    ANTENNADIFFAREA 0.795200 ;
    PORT
      LAYER met2 ;
        RECT 524.490 296.000 524.770 300.000 ;
    END
  END mstream_o[494]
  PIN mstream_o[495]
    DIRECTION OUTPUT TRISTATE ;
    USE SIGNAL ;
    ANTENNADIFFAREA 0.795200 ;
    PORT
      LAYER met2 ;
        RECT 525.410 296.000 525.690 300.000 ;
    END
  END mstream_o[495]
  PIN mstream_o[496]
    DIRECTION OUTPUT TRISTATE ;
    USE SIGNAL ;
    ANTENNADIFFAREA 0.795200 ;
    PORT
      LAYER met2 ;
        RECT 526.330 296.000 526.610 300.000 ;
    END
  END mstream_o[496]
  PIN mstream_o[497]
    DIRECTION OUTPUT TRISTATE ;
    USE SIGNAL ;
    ANTENNADIFFAREA 0.795200 ;
    PORT
      LAYER met2 ;
        RECT 527.250 296.000 527.530 300.000 ;
    END
  END mstream_o[497]
  PIN mstream_o[498]
    DIRECTION OUTPUT TRISTATE ;
    USE SIGNAL ;
    ANTENNADIFFAREA 0.795200 ;
    PORT
      LAYER met2 ;
        RECT 528.170 296.000 528.450 300.000 ;
    END
  END mstream_o[498]
  PIN mstream_o[499]
    DIRECTION OUTPUT TRISTATE ;
    USE SIGNAL ;
    ANTENNADIFFAREA 0.795200 ;
    PORT
      LAYER met2 ;
        RECT 529.090 296.000 529.370 300.000 ;
    END
  END mstream_o[499]
  PIN mstream_o[49]
    DIRECTION OUTPUT TRISTATE ;
    USE SIGNAL ;
    ANTENNADIFFAREA 0.795200 ;
    PORT
      LAYER met2 ;
        RECT 115.090 296.000 115.370 300.000 ;
    END
  END mstream_o[49]
  PIN mstream_o[4]
    DIRECTION OUTPUT TRISTATE ;
    USE SIGNAL ;
    ANTENNADIFFAREA 0.795200 ;
    PORT
      LAYER met2 ;
        RECT 73.690 296.000 73.970 300.000 ;
    END
  END mstream_o[4]
  PIN mstream_o[500]
    DIRECTION OUTPUT TRISTATE ;
    USE SIGNAL ;
    ANTENNADIFFAREA 0.795200 ;
    PORT
      LAYER met2 ;
        RECT 530.010 296.000 530.290 300.000 ;
    END
  END mstream_o[500]
  PIN mstream_o[501]
    DIRECTION OUTPUT TRISTATE ;
    USE SIGNAL ;
    ANTENNADIFFAREA 0.795200 ;
    PORT
      LAYER met2 ;
        RECT 530.930 296.000 531.210 300.000 ;
    END
  END mstream_o[501]
  PIN mstream_o[502]
    DIRECTION OUTPUT TRISTATE ;
    USE SIGNAL ;
    ANTENNADIFFAREA 0.795200 ;
    PORT
      LAYER met2 ;
        RECT 531.850 296.000 532.130 300.000 ;
    END
  END mstream_o[502]
  PIN mstream_o[503]
    DIRECTION OUTPUT TRISTATE ;
    USE SIGNAL ;
    ANTENNADIFFAREA 0.795200 ;
    PORT
      LAYER met2 ;
        RECT 532.770 296.000 533.050 300.000 ;
    END
  END mstream_o[503]
  PIN mstream_o[504]
    DIRECTION OUTPUT TRISTATE ;
    USE SIGNAL ;
    ANTENNADIFFAREA 0.795200 ;
    PORT
      LAYER met2 ;
        RECT 533.690 296.000 533.970 300.000 ;
    END
  END mstream_o[504]
  PIN mstream_o[505]
    DIRECTION OUTPUT TRISTATE ;
    USE SIGNAL ;
    ANTENNADIFFAREA 0.795200 ;
    PORT
      LAYER met2 ;
        RECT 534.610 296.000 534.890 300.000 ;
    END
  END mstream_o[505]
  PIN mstream_o[506]
    DIRECTION OUTPUT TRISTATE ;
    USE SIGNAL ;
    ANTENNADIFFAREA 0.795200 ;
    PORT
      LAYER met2 ;
        RECT 535.530 296.000 535.810 300.000 ;
    END
  END mstream_o[506]
  PIN mstream_o[507]
    DIRECTION OUTPUT TRISTATE ;
    USE SIGNAL ;
    ANTENNADIFFAREA 0.795200 ;
    PORT
      LAYER met2 ;
        RECT 536.450 296.000 536.730 300.000 ;
    END
  END mstream_o[507]
  PIN mstream_o[508]
    DIRECTION OUTPUT TRISTATE ;
    USE SIGNAL ;
    ANTENNADIFFAREA 0.795200 ;
    PORT
      LAYER met2 ;
        RECT 537.370 296.000 537.650 300.000 ;
    END
  END mstream_o[508]
  PIN mstream_o[509]
    DIRECTION OUTPUT TRISTATE ;
    USE SIGNAL ;
    ANTENNADIFFAREA 0.795200 ;
    PORT
      LAYER met2 ;
        RECT 538.290 296.000 538.570 300.000 ;
    END
  END mstream_o[509]
  PIN mstream_o[50]
    DIRECTION OUTPUT TRISTATE ;
    USE SIGNAL ;
    ANTENNADIFFAREA 0.795200 ;
    PORT
      LAYER met2 ;
        RECT 116.010 296.000 116.290 300.000 ;
    END
  END mstream_o[50]
  PIN mstream_o[510]
    DIRECTION OUTPUT TRISTATE ;
    USE SIGNAL ;
    ANTENNADIFFAREA 0.795200 ;
    PORT
      LAYER met2 ;
        RECT 539.210 296.000 539.490 300.000 ;
    END
  END mstream_o[510]
  PIN mstream_o[511]
    DIRECTION OUTPUT TRISTATE ;
    USE SIGNAL ;
    ANTENNADIFFAREA 0.795200 ;
    PORT
      LAYER met2 ;
        RECT 540.130 296.000 540.410 300.000 ;
    END
  END mstream_o[511]
  PIN mstream_o[512]
    DIRECTION OUTPUT TRISTATE ;
    USE SIGNAL ;
    ANTENNADIFFAREA 0.795200 ;
    PORT
      LAYER met2 ;
        RECT 541.050 296.000 541.330 300.000 ;
    END
  END mstream_o[512]
  PIN mstream_o[513]
    DIRECTION OUTPUT TRISTATE ;
    USE SIGNAL ;
    ANTENNADIFFAREA 0.795200 ;
    PORT
      LAYER met2 ;
        RECT 541.970 296.000 542.250 300.000 ;
    END
  END mstream_o[513]
  PIN mstream_o[514]
    DIRECTION OUTPUT TRISTATE ;
    USE SIGNAL ;
    ANTENNADIFFAREA 0.795200 ;
    PORT
      LAYER met2 ;
        RECT 542.890 296.000 543.170 300.000 ;
    END
  END mstream_o[514]
  PIN mstream_o[515]
    DIRECTION OUTPUT TRISTATE ;
    USE SIGNAL ;
    ANTENNADIFFAREA 0.795200 ;
    PORT
      LAYER met2 ;
        RECT 543.810 296.000 544.090 300.000 ;
    END
  END mstream_o[515]
  PIN mstream_o[516]
    DIRECTION OUTPUT TRISTATE ;
    USE SIGNAL ;
    ANTENNADIFFAREA 0.795200 ;
    PORT
      LAYER met2 ;
        RECT 544.730 296.000 545.010 300.000 ;
    END
  END mstream_o[516]
  PIN mstream_o[517]
    DIRECTION OUTPUT TRISTATE ;
    USE SIGNAL ;
    ANTENNADIFFAREA 0.795200 ;
    PORT
      LAYER met2 ;
        RECT 545.650 296.000 545.930 300.000 ;
    END
  END mstream_o[517]
  PIN mstream_o[518]
    DIRECTION OUTPUT TRISTATE ;
    USE SIGNAL ;
    ANTENNADIFFAREA 0.795200 ;
    PORT
      LAYER met2 ;
        RECT 546.570 296.000 546.850 300.000 ;
    END
  END mstream_o[518]
  PIN mstream_o[519]
    DIRECTION OUTPUT TRISTATE ;
    USE SIGNAL ;
    ANTENNADIFFAREA 0.795200 ;
    PORT
      LAYER met2 ;
        RECT 547.490 296.000 547.770 300.000 ;
    END
  END mstream_o[519]
  PIN mstream_o[51]
    DIRECTION OUTPUT TRISTATE ;
    USE SIGNAL ;
    ANTENNADIFFAREA 0.795200 ;
    PORT
      LAYER met2 ;
        RECT 116.930 296.000 117.210 300.000 ;
    END
  END mstream_o[51]
  PIN mstream_o[520]
    DIRECTION OUTPUT TRISTATE ;
    USE SIGNAL ;
    ANTENNADIFFAREA 0.795200 ;
    PORT
      LAYER met2 ;
        RECT 548.410 296.000 548.690 300.000 ;
    END
  END mstream_o[520]
  PIN mstream_o[521]
    DIRECTION OUTPUT TRISTATE ;
    USE SIGNAL ;
    ANTENNADIFFAREA 0.795200 ;
    PORT
      LAYER met2 ;
        RECT 549.330 296.000 549.610 300.000 ;
    END
  END mstream_o[521]
  PIN mstream_o[522]
    DIRECTION OUTPUT TRISTATE ;
    USE SIGNAL ;
    ANTENNADIFFAREA 0.795200 ;
    PORT
      LAYER met2 ;
        RECT 550.250 296.000 550.530 300.000 ;
    END
  END mstream_o[522]
  PIN mstream_o[523]
    DIRECTION OUTPUT TRISTATE ;
    USE SIGNAL ;
    ANTENNADIFFAREA 0.795200 ;
    PORT
      LAYER met2 ;
        RECT 551.170 296.000 551.450 300.000 ;
    END
  END mstream_o[523]
  PIN mstream_o[524]
    DIRECTION OUTPUT TRISTATE ;
    USE SIGNAL ;
    ANTENNADIFFAREA 0.795200 ;
    PORT
      LAYER met2 ;
        RECT 552.090 296.000 552.370 300.000 ;
    END
  END mstream_o[524]
  PIN mstream_o[525]
    DIRECTION OUTPUT TRISTATE ;
    USE SIGNAL ;
    ANTENNADIFFAREA 0.795200 ;
    PORT
      LAYER met2 ;
        RECT 553.010 296.000 553.290 300.000 ;
    END
  END mstream_o[525]
  PIN mstream_o[526]
    DIRECTION OUTPUT TRISTATE ;
    USE SIGNAL ;
    ANTENNADIFFAREA 0.795200 ;
    PORT
      LAYER met2 ;
        RECT 553.930 296.000 554.210 300.000 ;
    END
  END mstream_o[526]
  PIN mstream_o[527]
    DIRECTION OUTPUT TRISTATE ;
    USE SIGNAL ;
    ANTENNADIFFAREA 0.795200 ;
    PORT
      LAYER met2 ;
        RECT 554.850 296.000 555.130 300.000 ;
    END
  END mstream_o[527]
  PIN mstream_o[528]
    DIRECTION OUTPUT TRISTATE ;
    USE SIGNAL ;
    ANTENNADIFFAREA 0.795200 ;
    PORT
      LAYER met2 ;
        RECT 555.770 296.000 556.050 300.000 ;
    END
  END mstream_o[528]
  PIN mstream_o[529]
    DIRECTION OUTPUT TRISTATE ;
    USE SIGNAL ;
    ANTENNADIFFAREA 0.795200 ;
    PORT
      LAYER met2 ;
        RECT 556.690 296.000 556.970 300.000 ;
    END
  END mstream_o[529]
  PIN mstream_o[52]
    DIRECTION OUTPUT TRISTATE ;
    USE SIGNAL ;
    ANTENNADIFFAREA 0.795200 ;
    PORT
      LAYER met2 ;
        RECT 117.850 296.000 118.130 300.000 ;
    END
  END mstream_o[52]
  PIN mstream_o[530]
    DIRECTION OUTPUT TRISTATE ;
    USE SIGNAL ;
    ANTENNADIFFAREA 0.795200 ;
    PORT
      LAYER met2 ;
        RECT 557.610 296.000 557.890 300.000 ;
    END
  END mstream_o[530]
  PIN mstream_o[531]
    DIRECTION OUTPUT TRISTATE ;
    USE SIGNAL ;
    ANTENNADIFFAREA 0.795200 ;
    PORT
      LAYER met2 ;
        RECT 558.530 296.000 558.810 300.000 ;
    END
  END mstream_o[531]
  PIN mstream_o[532]
    DIRECTION OUTPUT TRISTATE ;
    USE SIGNAL ;
    ANTENNADIFFAREA 0.795200 ;
    PORT
      LAYER met2 ;
        RECT 559.450 296.000 559.730 300.000 ;
    END
  END mstream_o[532]
  PIN mstream_o[533]
    DIRECTION OUTPUT TRISTATE ;
    USE SIGNAL ;
    ANTENNADIFFAREA 0.795200 ;
    PORT
      LAYER met2 ;
        RECT 560.370 296.000 560.650 300.000 ;
    END
  END mstream_o[533]
  PIN mstream_o[534]
    DIRECTION OUTPUT TRISTATE ;
    USE SIGNAL ;
    ANTENNADIFFAREA 0.795200 ;
    PORT
      LAYER met2 ;
        RECT 561.290 296.000 561.570 300.000 ;
    END
  END mstream_o[534]
  PIN mstream_o[535]
    DIRECTION OUTPUT TRISTATE ;
    USE SIGNAL ;
    ANTENNADIFFAREA 0.795200 ;
    PORT
      LAYER met2 ;
        RECT 562.210 296.000 562.490 300.000 ;
    END
  END mstream_o[535]
  PIN mstream_o[536]
    DIRECTION OUTPUT TRISTATE ;
    USE SIGNAL ;
    ANTENNADIFFAREA 0.795200 ;
    PORT
      LAYER met2 ;
        RECT 563.130 296.000 563.410 300.000 ;
    END
  END mstream_o[536]
  PIN mstream_o[537]
    DIRECTION OUTPUT TRISTATE ;
    USE SIGNAL ;
    ANTENNADIFFAREA 0.795200 ;
    PORT
      LAYER met2 ;
        RECT 564.050 296.000 564.330 300.000 ;
    END
  END mstream_o[537]
  PIN mstream_o[538]
    DIRECTION OUTPUT TRISTATE ;
    USE SIGNAL ;
    ANTENNADIFFAREA 0.795200 ;
    PORT
      LAYER met2 ;
        RECT 564.970 296.000 565.250 300.000 ;
    END
  END mstream_o[538]
  PIN mstream_o[539]
    DIRECTION OUTPUT TRISTATE ;
    USE SIGNAL ;
    ANTENNADIFFAREA 0.795200 ;
    PORT
      LAYER met2 ;
        RECT 565.890 296.000 566.170 300.000 ;
    END
  END mstream_o[539]
  PIN mstream_o[53]
    DIRECTION OUTPUT TRISTATE ;
    USE SIGNAL ;
    ANTENNADIFFAREA 0.795200 ;
    PORT
      LAYER met2 ;
        RECT 118.770 296.000 119.050 300.000 ;
    END
  END mstream_o[53]
  PIN mstream_o[540]
    DIRECTION OUTPUT TRISTATE ;
    USE SIGNAL ;
    ANTENNADIFFAREA 0.795200 ;
    PORT
      LAYER met2 ;
        RECT 566.810 296.000 567.090 300.000 ;
    END
  END mstream_o[540]
  PIN mstream_o[541]
    DIRECTION OUTPUT TRISTATE ;
    USE SIGNAL ;
    ANTENNADIFFAREA 0.795200 ;
    PORT
      LAYER met2 ;
        RECT 567.730 296.000 568.010 300.000 ;
    END
  END mstream_o[541]
  PIN mstream_o[542]
    DIRECTION OUTPUT TRISTATE ;
    USE SIGNAL ;
    ANTENNADIFFAREA 0.795200 ;
    PORT
      LAYER met2 ;
        RECT 568.650 296.000 568.930 300.000 ;
    END
  END mstream_o[542]
  PIN mstream_o[543]
    DIRECTION OUTPUT TRISTATE ;
    USE SIGNAL ;
    ANTENNADIFFAREA 0.795200 ;
    PORT
      LAYER met2 ;
        RECT 569.570 296.000 569.850 300.000 ;
    END
  END mstream_o[543]
  PIN mstream_o[544]
    DIRECTION OUTPUT TRISTATE ;
    USE SIGNAL ;
    ANTENNADIFFAREA 0.795200 ;
    PORT
      LAYER met2 ;
        RECT 570.490 296.000 570.770 300.000 ;
    END
  END mstream_o[544]
  PIN mstream_o[545]
    DIRECTION OUTPUT TRISTATE ;
    USE SIGNAL ;
    ANTENNADIFFAREA 0.795200 ;
    PORT
      LAYER met2 ;
        RECT 571.410 296.000 571.690 300.000 ;
    END
  END mstream_o[545]
  PIN mstream_o[546]
    DIRECTION OUTPUT TRISTATE ;
    USE SIGNAL ;
    ANTENNADIFFAREA 0.795200 ;
    PORT
      LAYER met2 ;
        RECT 572.330 296.000 572.610 300.000 ;
    END
  END mstream_o[546]
  PIN mstream_o[547]
    DIRECTION OUTPUT TRISTATE ;
    USE SIGNAL ;
    ANTENNADIFFAREA 0.795200 ;
    PORT
      LAYER met2 ;
        RECT 573.250 296.000 573.530 300.000 ;
    END
  END mstream_o[547]
  PIN mstream_o[548]
    DIRECTION OUTPUT TRISTATE ;
    USE SIGNAL ;
    ANTENNADIFFAREA 0.795200 ;
    PORT
      LAYER met2 ;
        RECT 574.170 296.000 574.450 300.000 ;
    END
  END mstream_o[548]
  PIN mstream_o[549]
    DIRECTION OUTPUT TRISTATE ;
    USE SIGNAL ;
    ANTENNADIFFAREA 0.795200 ;
    PORT
      LAYER met2 ;
        RECT 575.090 296.000 575.370 300.000 ;
    END
  END mstream_o[549]
  PIN mstream_o[54]
    DIRECTION OUTPUT TRISTATE ;
    USE SIGNAL ;
    ANTENNADIFFAREA 0.795200 ;
    PORT
      LAYER met2 ;
        RECT 119.690 296.000 119.970 300.000 ;
    END
  END mstream_o[54]
  PIN mstream_o[550]
    DIRECTION OUTPUT TRISTATE ;
    USE SIGNAL ;
    ANTENNADIFFAREA 0.795200 ;
    PORT
      LAYER met2 ;
        RECT 576.010 296.000 576.290 300.000 ;
    END
  END mstream_o[550]
  PIN mstream_o[551]
    DIRECTION OUTPUT TRISTATE ;
    USE SIGNAL ;
    ANTENNADIFFAREA 0.795200 ;
    PORT
      LAYER met2 ;
        RECT 576.930 296.000 577.210 300.000 ;
    END
  END mstream_o[551]
  PIN mstream_o[552]
    DIRECTION OUTPUT TRISTATE ;
    USE SIGNAL ;
    ANTENNADIFFAREA 0.795200 ;
    PORT
      LAYER met2 ;
        RECT 577.850 296.000 578.130 300.000 ;
    END
  END mstream_o[552]
  PIN mstream_o[553]
    DIRECTION OUTPUT TRISTATE ;
    USE SIGNAL ;
    ANTENNADIFFAREA 0.795200 ;
    PORT
      LAYER met2 ;
        RECT 578.770 296.000 579.050 300.000 ;
    END
  END mstream_o[553]
  PIN mstream_o[554]
    DIRECTION OUTPUT TRISTATE ;
    USE SIGNAL ;
    ANTENNADIFFAREA 0.795200 ;
    PORT
      LAYER met2 ;
        RECT 579.690 296.000 579.970 300.000 ;
    END
  END mstream_o[554]
  PIN mstream_o[555]
    DIRECTION OUTPUT TRISTATE ;
    USE SIGNAL ;
    ANTENNADIFFAREA 0.795200 ;
    PORT
      LAYER met2 ;
        RECT 580.610 296.000 580.890 300.000 ;
    END
  END mstream_o[555]
  PIN mstream_o[556]
    DIRECTION OUTPUT TRISTATE ;
    USE SIGNAL ;
    ANTENNADIFFAREA 0.795200 ;
    PORT
      LAYER met2 ;
        RECT 581.530 296.000 581.810 300.000 ;
    END
  END mstream_o[556]
  PIN mstream_o[557]
    DIRECTION OUTPUT TRISTATE ;
    USE SIGNAL ;
    ANTENNADIFFAREA 0.795200 ;
    PORT
      LAYER met2 ;
        RECT 582.450 296.000 582.730 300.000 ;
    END
  END mstream_o[557]
  PIN mstream_o[558]
    DIRECTION OUTPUT TRISTATE ;
    USE SIGNAL ;
    ANTENNADIFFAREA 0.795200 ;
    PORT
      LAYER met2 ;
        RECT 583.370 296.000 583.650 300.000 ;
    END
  END mstream_o[558]
  PIN mstream_o[559]
    DIRECTION OUTPUT TRISTATE ;
    USE SIGNAL ;
    ANTENNADIFFAREA 0.795200 ;
    PORT
      LAYER met2 ;
        RECT 584.290 296.000 584.570 300.000 ;
    END
  END mstream_o[559]
  PIN mstream_o[55]
    DIRECTION OUTPUT TRISTATE ;
    USE SIGNAL ;
    ANTENNADIFFAREA 0.795200 ;
    PORT
      LAYER met2 ;
        RECT 120.610 296.000 120.890 300.000 ;
    END
  END mstream_o[55]
  PIN mstream_o[560]
    DIRECTION OUTPUT TRISTATE ;
    USE SIGNAL ;
    ANTENNADIFFAREA 0.795200 ;
    PORT
      LAYER met2 ;
        RECT 585.210 296.000 585.490 300.000 ;
    END
  END mstream_o[560]
  PIN mstream_o[561]
    DIRECTION OUTPUT TRISTATE ;
    USE SIGNAL ;
    ANTENNADIFFAREA 0.795200 ;
    PORT
      LAYER met2 ;
        RECT 586.130 296.000 586.410 300.000 ;
    END
  END mstream_o[561]
  PIN mstream_o[562]
    DIRECTION OUTPUT TRISTATE ;
    USE SIGNAL ;
    ANTENNADIFFAREA 0.795200 ;
    PORT
      LAYER met2 ;
        RECT 587.050 296.000 587.330 300.000 ;
    END
  END mstream_o[562]
  PIN mstream_o[563]
    DIRECTION OUTPUT TRISTATE ;
    USE SIGNAL ;
    ANTENNADIFFAREA 0.795200 ;
    PORT
      LAYER met2 ;
        RECT 587.970 296.000 588.250 300.000 ;
    END
  END mstream_o[563]
  PIN mstream_o[564]
    DIRECTION OUTPUT TRISTATE ;
    USE SIGNAL ;
    ANTENNADIFFAREA 0.795200 ;
    PORT
      LAYER met2 ;
        RECT 588.890 296.000 589.170 300.000 ;
    END
  END mstream_o[564]
  PIN mstream_o[565]
    DIRECTION OUTPUT TRISTATE ;
    USE SIGNAL ;
    ANTENNADIFFAREA 0.795200 ;
    PORT
      LAYER met2 ;
        RECT 589.810 296.000 590.090 300.000 ;
    END
  END mstream_o[565]
  PIN mstream_o[566]
    DIRECTION OUTPUT TRISTATE ;
    USE SIGNAL ;
    ANTENNADIFFAREA 0.795200 ;
    PORT
      LAYER met2 ;
        RECT 590.730 296.000 591.010 300.000 ;
    END
  END mstream_o[566]
  PIN mstream_o[567]
    DIRECTION OUTPUT TRISTATE ;
    USE SIGNAL ;
    ANTENNADIFFAREA 0.795200 ;
    PORT
      LAYER met2 ;
        RECT 591.650 296.000 591.930 300.000 ;
    END
  END mstream_o[567]
  PIN mstream_o[568]
    DIRECTION OUTPUT TRISTATE ;
    USE SIGNAL ;
    ANTENNADIFFAREA 0.795200 ;
    PORT
      LAYER met2 ;
        RECT 592.570 296.000 592.850 300.000 ;
    END
  END mstream_o[568]
  PIN mstream_o[569]
    DIRECTION OUTPUT TRISTATE ;
    USE SIGNAL ;
    ANTENNADIFFAREA 0.795200 ;
    PORT
      LAYER met2 ;
        RECT 593.490 296.000 593.770 300.000 ;
    END
  END mstream_o[569]
  PIN mstream_o[56]
    DIRECTION OUTPUT TRISTATE ;
    USE SIGNAL ;
    ANTENNADIFFAREA 0.795200 ;
    PORT
      LAYER met2 ;
        RECT 121.530 296.000 121.810 300.000 ;
    END
  END mstream_o[56]
  PIN mstream_o[570]
    DIRECTION OUTPUT TRISTATE ;
    USE SIGNAL ;
    ANTENNADIFFAREA 0.795200 ;
    PORT
      LAYER met2 ;
        RECT 594.410 296.000 594.690 300.000 ;
    END
  END mstream_o[570]
  PIN mstream_o[571]
    DIRECTION OUTPUT TRISTATE ;
    USE SIGNAL ;
    ANTENNADIFFAREA 0.795200 ;
    PORT
      LAYER met2 ;
        RECT 595.330 296.000 595.610 300.000 ;
    END
  END mstream_o[571]
  PIN mstream_o[572]
    DIRECTION OUTPUT TRISTATE ;
    USE SIGNAL ;
    ANTENNADIFFAREA 0.795200 ;
    PORT
      LAYER met2 ;
        RECT 596.250 296.000 596.530 300.000 ;
    END
  END mstream_o[572]
  PIN mstream_o[573]
    DIRECTION OUTPUT TRISTATE ;
    USE SIGNAL ;
    ANTENNADIFFAREA 0.795200 ;
    PORT
      LAYER met2 ;
        RECT 597.170 296.000 597.450 300.000 ;
    END
  END mstream_o[573]
  PIN mstream_o[574]
    DIRECTION OUTPUT TRISTATE ;
    USE SIGNAL ;
    ANTENNADIFFAREA 0.795200 ;
    PORT
      LAYER met2 ;
        RECT 598.090 296.000 598.370 300.000 ;
    END
  END mstream_o[574]
  PIN mstream_o[575]
    DIRECTION OUTPUT TRISTATE ;
    USE SIGNAL ;
    ANTENNADIFFAREA 0.795200 ;
    PORT
      LAYER met2 ;
        RECT 599.010 296.000 599.290 300.000 ;
    END
  END mstream_o[575]
  PIN mstream_o[576]
    DIRECTION OUTPUT TRISTATE ;
    USE SIGNAL ;
    ANTENNADIFFAREA 0.795200 ;
    PORT
      LAYER met2 ;
        RECT 599.930 296.000 600.210 300.000 ;
    END
  END mstream_o[576]
  PIN mstream_o[577]
    DIRECTION OUTPUT TRISTATE ;
    USE SIGNAL ;
    ANTENNADIFFAREA 0.795200 ;
    PORT
      LAYER met2 ;
        RECT 600.850 296.000 601.130 300.000 ;
    END
  END mstream_o[577]
  PIN mstream_o[578]
    DIRECTION OUTPUT TRISTATE ;
    USE SIGNAL ;
    ANTENNADIFFAREA 0.795200 ;
    PORT
      LAYER met2 ;
        RECT 601.770 296.000 602.050 300.000 ;
    END
  END mstream_o[578]
  PIN mstream_o[579]
    DIRECTION OUTPUT TRISTATE ;
    USE SIGNAL ;
    ANTENNADIFFAREA 0.795200 ;
    PORT
      LAYER met2 ;
        RECT 602.690 296.000 602.970 300.000 ;
    END
  END mstream_o[579]
  PIN mstream_o[57]
    DIRECTION OUTPUT TRISTATE ;
    USE SIGNAL ;
    ANTENNADIFFAREA 0.795200 ;
    PORT
      LAYER met2 ;
        RECT 122.450 296.000 122.730 300.000 ;
    END
  END mstream_o[57]
  PIN mstream_o[580]
    DIRECTION OUTPUT TRISTATE ;
    USE SIGNAL ;
    ANTENNADIFFAREA 0.795200 ;
    PORT
      LAYER met2 ;
        RECT 603.610 296.000 603.890 300.000 ;
    END
  END mstream_o[580]
  PIN mstream_o[581]
    DIRECTION OUTPUT TRISTATE ;
    USE SIGNAL ;
    ANTENNADIFFAREA 0.795200 ;
    PORT
      LAYER met2 ;
        RECT 604.530 296.000 604.810 300.000 ;
    END
  END mstream_o[581]
  PIN mstream_o[582]
    DIRECTION OUTPUT TRISTATE ;
    USE SIGNAL ;
    ANTENNADIFFAREA 0.795200 ;
    PORT
      LAYER met2 ;
        RECT 605.450 296.000 605.730 300.000 ;
    END
  END mstream_o[582]
  PIN mstream_o[583]
    DIRECTION OUTPUT TRISTATE ;
    USE SIGNAL ;
    ANTENNADIFFAREA 0.795200 ;
    PORT
      LAYER met2 ;
        RECT 606.370 296.000 606.650 300.000 ;
    END
  END mstream_o[583]
  PIN mstream_o[584]
    DIRECTION OUTPUT TRISTATE ;
    USE SIGNAL ;
    ANTENNADIFFAREA 0.795200 ;
    PORT
      LAYER met2 ;
        RECT 607.290 296.000 607.570 300.000 ;
    END
  END mstream_o[584]
  PIN mstream_o[585]
    DIRECTION OUTPUT TRISTATE ;
    USE SIGNAL ;
    ANTENNADIFFAREA 0.795200 ;
    PORT
      LAYER met2 ;
        RECT 608.210 296.000 608.490 300.000 ;
    END
  END mstream_o[585]
  PIN mstream_o[586]
    DIRECTION OUTPUT TRISTATE ;
    USE SIGNAL ;
    ANTENNADIFFAREA 0.795200 ;
    PORT
      LAYER met2 ;
        RECT 609.130 296.000 609.410 300.000 ;
    END
  END mstream_o[586]
  PIN mstream_o[587]
    DIRECTION OUTPUT TRISTATE ;
    USE SIGNAL ;
    ANTENNADIFFAREA 0.795200 ;
    PORT
      LAYER met2 ;
        RECT 610.050 296.000 610.330 300.000 ;
    END
  END mstream_o[587]
  PIN mstream_o[588]
    DIRECTION OUTPUT TRISTATE ;
    USE SIGNAL ;
    ANTENNADIFFAREA 0.795200 ;
    PORT
      LAYER met2 ;
        RECT 610.970 296.000 611.250 300.000 ;
    END
  END mstream_o[588]
  PIN mstream_o[589]
    DIRECTION OUTPUT TRISTATE ;
    USE SIGNAL ;
    ANTENNADIFFAREA 0.795200 ;
    PORT
      LAYER met2 ;
        RECT 611.890 296.000 612.170 300.000 ;
    END
  END mstream_o[589]
  PIN mstream_o[58]
    DIRECTION OUTPUT TRISTATE ;
    USE SIGNAL ;
    ANTENNADIFFAREA 0.795200 ;
    PORT
      LAYER met2 ;
        RECT 123.370 296.000 123.650 300.000 ;
    END
  END mstream_o[58]
  PIN mstream_o[590]
    DIRECTION OUTPUT TRISTATE ;
    USE SIGNAL ;
    ANTENNADIFFAREA 0.795200 ;
    PORT
      LAYER met2 ;
        RECT 612.810 296.000 613.090 300.000 ;
    END
  END mstream_o[590]
  PIN mstream_o[591]
    DIRECTION OUTPUT TRISTATE ;
    USE SIGNAL ;
    ANTENNADIFFAREA 0.795200 ;
    PORT
      LAYER met2 ;
        RECT 613.730 296.000 614.010 300.000 ;
    END
  END mstream_o[591]
  PIN mstream_o[592]
    DIRECTION OUTPUT TRISTATE ;
    USE SIGNAL ;
    ANTENNADIFFAREA 0.795200 ;
    PORT
      LAYER met2 ;
        RECT 614.650 296.000 614.930 300.000 ;
    END
  END mstream_o[592]
  PIN mstream_o[593]
    DIRECTION OUTPUT TRISTATE ;
    USE SIGNAL ;
    ANTENNADIFFAREA 0.795200 ;
    PORT
      LAYER met2 ;
        RECT 615.570 296.000 615.850 300.000 ;
    END
  END mstream_o[593]
  PIN mstream_o[594]
    DIRECTION OUTPUT TRISTATE ;
    USE SIGNAL ;
    ANTENNADIFFAREA 0.795200 ;
    PORT
      LAYER met2 ;
        RECT 616.490 296.000 616.770 300.000 ;
    END
  END mstream_o[594]
  PIN mstream_o[595]
    DIRECTION OUTPUT TRISTATE ;
    USE SIGNAL ;
    ANTENNADIFFAREA 0.795200 ;
    PORT
      LAYER met2 ;
        RECT 617.410 296.000 617.690 300.000 ;
    END
  END mstream_o[595]
  PIN mstream_o[596]
    DIRECTION OUTPUT TRISTATE ;
    USE SIGNAL ;
    ANTENNADIFFAREA 0.795200 ;
    PORT
      LAYER met2 ;
        RECT 618.330 296.000 618.610 300.000 ;
    END
  END mstream_o[596]
  PIN mstream_o[597]
    DIRECTION OUTPUT TRISTATE ;
    USE SIGNAL ;
    ANTENNADIFFAREA 0.795200 ;
    PORT
      LAYER met2 ;
        RECT 619.250 296.000 619.530 300.000 ;
    END
  END mstream_o[597]
  PIN mstream_o[598]
    DIRECTION OUTPUT TRISTATE ;
    USE SIGNAL ;
    ANTENNADIFFAREA 0.795200 ;
    PORT
      LAYER met2 ;
        RECT 620.170 296.000 620.450 300.000 ;
    END
  END mstream_o[598]
  PIN mstream_o[599]
    DIRECTION OUTPUT TRISTATE ;
    USE SIGNAL ;
    ANTENNADIFFAREA 0.795200 ;
    PORT
      LAYER met2 ;
        RECT 621.090 296.000 621.370 300.000 ;
    END
  END mstream_o[599]
  PIN mstream_o[59]
    DIRECTION OUTPUT TRISTATE ;
    USE SIGNAL ;
    ANTENNADIFFAREA 0.795200 ;
    PORT
      LAYER met2 ;
        RECT 124.290 296.000 124.570 300.000 ;
    END
  END mstream_o[59]
  PIN mstream_o[5]
    DIRECTION OUTPUT TRISTATE ;
    USE SIGNAL ;
    ANTENNADIFFAREA 0.795200 ;
    PORT
      LAYER met2 ;
        RECT 74.610 296.000 74.890 300.000 ;
    END
  END mstream_o[5]
  PIN mstream_o[600]
    DIRECTION OUTPUT TRISTATE ;
    USE SIGNAL ;
    ANTENNADIFFAREA 0.795200 ;
    PORT
      LAYER met2 ;
        RECT 622.010 296.000 622.290 300.000 ;
    END
  END mstream_o[600]
  PIN mstream_o[601]
    DIRECTION OUTPUT TRISTATE ;
    USE SIGNAL ;
    ANTENNADIFFAREA 0.795200 ;
    PORT
      LAYER met2 ;
        RECT 622.930 296.000 623.210 300.000 ;
    END
  END mstream_o[601]
  PIN mstream_o[602]
    DIRECTION OUTPUT TRISTATE ;
    USE SIGNAL ;
    ANTENNADIFFAREA 0.795200 ;
    PORT
      LAYER met2 ;
        RECT 623.850 296.000 624.130 300.000 ;
    END
  END mstream_o[602]
  PIN mstream_o[603]
    DIRECTION OUTPUT TRISTATE ;
    USE SIGNAL ;
    ANTENNADIFFAREA 0.795200 ;
    PORT
      LAYER met2 ;
        RECT 624.770 296.000 625.050 300.000 ;
    END
  END mstream_o[603]
  PIN mstream_o[604]
    DIRECTION OUTPUT TRISTATE ;
    USE SIGNAL ;
    ANTENNADIFFAREA 0.795200 ;
    PORT
      LAYER met2 ;
        RECT 625.690 296.000 625.970 300.000 ;
    END
  END mstream_o[604]
  PIN mstream_o[605]
    DIRECTION OUTPUT TRISTATE ;
    USE SIGNAL ;
    ANTENNADIFFAREA 0.795200 ;
    PORT
      LAYER met2 ;
        RECT 626.610 296.000 626.890 300.000 ;
    END
  END mstream_o[605]
  PIN mstream_o[606]
    DIRECTION OUTPUT TRISTATE ;
    USE SIGNAL ;
    ANTENNADIFFAREA 0.795200 ;
    PORT
      LAYER met2 ;
        RECT 627.530 296.000 627.810 300.000 ;
    END
  END mstream_o[606]
  PIN mstream_o[607]
    DIRECTION OUTPUT TRISTATE ;
    USE SIGNAL ;
    ANTENNADIFFAREA 0.795200 ;
    PORT
      LAYER met2 ;
        RECT 628.450 296.000 628.730 300.000 ;
    END
  END mstream_o[607]
  PIN mstream_o[608]
    DIRECTION OUTPUT TRISTATE ;
    USE SIGNAL ;
    ANTENNADIFFAREA 0.795200 ;
    PORT
      LAYER met2 ;
        RECT 629.370 296.000 629.650 300.000 ;
    END
  END mstream_o[608]
  PIN mstream_o[609]
    DIRECTION OUTPUT TRISTATE ;
    USE SIGNAL ;
    ANTENNADIFFAREA 0.795200 ;
    PORT
      LAYER met2 ;
        RECT 630.290 296.000 630.570 300.000 ;
    END
  END mstream_o[609]
  PIN mstream_o[60]
    DIRECTION OUTPUT TRISTATE ;
    USE SIGNAL ;
    ANTENNADIFFAREA 0.795200 ;
    PORT
      LAYER met2 ;
        RECT 125.210 296.000 125.490 300.000 ;
    END
  END mstream_o[60]
  PIN mstream_o[610]
    DIRECTION OUTPUT TRISTATE ;
    USE SIGNAL ;
    ANTENNADIFFAREA 0.795200 ;
    PORT
      LAYER met2 ;
        RECT 631.210 296.000 631.490 300.000 ;
    END
  END mstream_o[610]
  PIN mstream_o[611]
    DIRECTION OUTPUT TRISTATE ;
    USE SIGNAL ;
    ANTENNADIFFAREA 0.795200 ;
    PORT
      LAYER met2 ;
        RECT 632.130 296.000 632.410 300.000 ;
    END
  END mstream_o[611]
  PIN mstream_o[612]
    DIRECTION OUTPUT TRISTATE ;
    USE SIGNAL ;
    ANTENNADIFFAREA 0.795200 ;
    PORT
      LAYER met2 ;
        RECT 633.050 296.000 633.330 300.000 ;
    END
  END mstream_o[612]
  PIN mstream_o[613]
    DIRECTION OUTPUT TRISTATE ;
    USE SIGNAL ;
    ANTENNADIFFAREA 0.795200 ;
    PORT
      LAYER met2 ;
        RECT 633.970 296.000 634.250 300.000 ;
    END
  END mstream_o[613]
  PIN mstream_o[614]
    DIRECTION OUTPUT TRISTATE ;
    USE SIGNAL ;
    ANTENNADIFFAREA 0.795200 ;
    PORT
      LAYER met2 ;
        RECT 634.890 296.000 635.170 300.000 ;
    END
  END mstream_o[614]
  PIN mstream_o[615]
    DIRECTION OUTPUT TRISTATE ;
    USE SIGNAL ;
    ANTENNADIFFAREA 0.795200 ;
    PORT
      LAYER met2 ;
        RECT 635.810 296.000 636.090 300.000 ;
    END
  END mstream_o[615]
  PIN mstream_o[616]
    DIRECTION OUTPUT TRISTATE ;
    USE SIGNAL ;
    ANTENNADIFFAREA 0.795200 ;
    PORT
      LAYER met2 ;
        RECT 636.730 296.000 637.010 300.000 ;
    END
  END mstream_o[616]
  PIN mstream_o[617]
    DIRECTION OUTPUT TRISTATE ;
    USE SIGNAL ;
    ANTENNADIFFAREA 0.795200 ;
    PORT
      LAYER met2 ;
        RECT 637.650 296.000 637.930 300.000 ;
    END
  END mstream_o[617]
  PIN mstream_o[618]
    DIRECTION OUTPUT TRISTATE ;
    USE SIGNAL ;
    ANTENNADIFFAREA 0.795200 ;
    PORT
      LAYER met2 ;
        RECT 638.570 296.000 638.850 300.000 ;
    END
  END mstream_o[618]
  PIN mstream_o[619]
    DIRECTION OUTPUT TRISTATE ;
    USE SIGNAL ;
    ANTENNADIFFAREA 0.795200 ;
    PORT
      LAYER met2 ;
        RECT 639.490 296.000 639.770 300.000 ;
    END
  END mstream_o[619]
  PIN mstream_o[61]
    DIRECTION OUTPUT TRISTATE ;
    USE SIGNAL ;
    ANTENNADIFFAREA 0.795200 ;
    PORT
      LAYER met2 ;
        RECT 126.130 296.000 126.410 300.000 ;
    END
  END mstream_o[61]
  PIN mstream_o[620]
    DIRECTION OUTPUT TRISTATE ;
    USE SIGNAL ;
    ANTENNADIFFAREA 0.795200 ;
    PORT
      LAYER met2 ;
        RECT 640.410 296.000 640.690 300.000 ;
    END
  END mstream_o[620]
  PIN mstream_o[621]
    DIRECTION OUTPUT TRISTATE ;
    USE SIGNAL ;
    ANTENNADIFFAREA 0.795200 ;
    PORT
      LAYER met2 ;
        RECT 641.330 296.000 641.610 300.000 ;
    END
  END mstream_o[621]
  PIN mstream_o[622]
    DIRECTION OUTPUT TRISTATE ;
    USE SIGNAL ;
    ANTENNADIFFAREA 0.795200 ;
    PORT
      LAYER met2 ;
        RECT 642.250 296.000 642.530 300.000 ;
    END
  END mstream_o[622]
  PIN mstream_o[623]
    DIRECTION OUTPUT TRISTATE ;
    USE SIGNAL ;
    ANTENNADIFFAREA 0.795200 ;
    PORT
      LAYER met2 ;
        RECT 643.170 296.000 643.450 300.000 ;
    END
  END mstream_o[623]
  PIN mstream_o[624]
    DIRECTION OUTPUT TRISTATE ;
    USE SIGNAL ;
    ANTENNADIFFAREA 0.795200 ;
    PORT
      LAYER met2 ;
        RECT 644.090 296.000 644.370 300.000 ;
    END
  END mstream_o[624]
  PIN mstream_o[625]
    DIRECTION OUTPUT TRISTATE ;
    USE SIGNAL ;
    ANTENNADIFFAREA 0.795200 ;
    PORT
      LAYER met2 ;
        RECT 645.010 296.000 645.290 300.000 ;
    END
  END mstream_o[625]
  PIN mstream_o[626]
    DIRECTION OUTPUT TRISTATE ;
    USE SIGNAL ;
    ANTENNADIFFAREA 0.795200 ;
    PORT
      LAYER met2 ;
        RECT 645.930 296.000 646.210 300.000 ;
    END
  END mstream_o[626]
  PIN mstream_o[627]
    DIRECTION OUTPUT TRISTATE ;
    USE SIGNAL ;
    ANTENNADIFFAREA 0.795200 ;
    PORT
      LAYER met2 ;
        RECT 646.850 296.000 647.130 300.000 ;
    END
  END mstream_o[627]
  PIN mstream_o[628]
    DIRECTION OUTPUT TRISTATE ;
    USE SIGNAL ;
    ANTENNADIFFAREA 0.795200 ;
    PORT
      LAYER met2 ;
        RECT 647.770 296.000 648.050 300.000 ;
    END
  END mstream_o[628]
  PIN mstream_o[629]
    DIRECTION OUTPUT TRISTATE ;
    USE SIGNAL ;
    ANTENNADIFFAREA 0.795200 ;
    PORT
      LAYER met2 ;
        RECT 648.690 296.000 648.970 300.000 ;
    END
  END mstream_o[629]
  PIN mstream_o[62]
    DIRECTION OUTPUT TRISTATE ;
    USE SIGNAL ;
    ANTENNADIFFAREA 0.795200 ;
    PORT
      LAYER met2 ;
        RECT 127.050 296.000 127.330 300.000 ;
    END
  END mstream_o[62]
  PIN mstream_o[630]
    DIRECTION OUTPUT TRISTATE ;
    USE SIGNAL ;
    ANTENNADIFFAREA 0.795200 ;
    PORT
      LAYER met2 ;
        RECT 649.610 296.000 649.890 300.000 ;
    END
  END mstream_o[630]
  PIN mstream_o[631]
    DIRECTION OUTPUT TRISTATE ;
    USE SIGNAL ;
    ANTENNADIFFAREA 0.795200 ;
    PORT
      LAYER met2 ;
        RECT 650.530 296.000 650.810 300.000 ;
    END
  END mstream_o[631]
  PIN mstream_o[632]
    DIRECTION OUTPUT TRISTATE ;
    USE SIGNAL ;
    ANTENNADIFFAREA 0.795200 ;
    PORT
      LAYER met2 ;
        RECT 651.450 296.000 651.730 300.000 ;
    END
  END mstream_o[632]
  PIN mstream_o[633]
    DIRECTION OUTPUT TRISTATE ;
    USE SIGNAL ;
    ANTENNADIFFAREA 0.795200 ;
    PORT
      LAYER met2 ;
        RECT 652.370 296.000 652.650 300.000 ;
    END
  END mstream_o[633]
  PIN mstream_o[634]
    DIRECTION OUTPUT TRISTATE ;
    USE SIGNAL ;
    ANTENNADIFFAREA 0.795200 ;
    PORT
      LAYER met2 ;
        RECT 653.290 296.000 653.570 300.000 ;
    END
  END mstream_o[634]
  PIN mstream_o[635]
    DIRECTION OUTPUT TRISTATE ;
    USE SIGNAL ;
    ANTENNADIFFAREA 0.795200 ;
    PORT
      LAYER met2 ;
        RECT 654.210 296.000 654.490 300.000 ;
    END
  END mstream_o[635]
  PIN mstream_o[636]
    DIRECTION OUTPUT TRISTATE ;
    USE SIGNAL ;
    ANTENNADIFFAREA 0.795200 ;
    PORT
      LAYER met2 ;
        RECT 655.130 296.000 655.410 300.000 ;
    END
  END mstream_o[636]
  PIN mstream_o[637]
    DIRECTION OUTPUT TRISTATE ;
    USE SIGNAL ;
    ANTENNADIFFAREA 0.795200 ;
    PORT
      LAYER met2 ;
        RECT 656.050 296.000 656.330 300.000 ;
    END
  END mstream_o[637]
  PIN mstream_o[638]
    DIRECTION OUTPUT TRISTATE ;
    USE SIGNAL ;
    ANTENNADIFFAREA 0.795200 ;
    PORT
      LAYER met2 ;
        RECT 656.970 296.000 657.250 300.000 ;
    END
  END mstream_o[638]
  PIN mstream_o[639]
    DIRECTION OUTPUT TRISTATE ;
    USE SIGNAL ;
    ANTENNADIFFAREA 0.795200 ;
    PORT
      LAYER met2 ;
        RECT 657.890 296.000 658.170 300.000 ;
    END
  END mstream_o[639]
  PIN mstream_o[63]
    DIRECTION OUTPUT TRISTATE ;
    USE SIGNAL ;
    ANTENNADIFFAREA 0.795200 ;
    PORT
      LAYER met2 ;
        RECT 127.970 296.000 128.250 300.000 ;
    END
  END mstream_o[63]
  PIN mstream_o[640]
    DIRECTION OUTPUT TRISTATE ;
    USE SIGNAL ;
    ANTENNADIFFAREA 0.795200 ;
    PORT
      LAYER met2 ;
        RECT 658.810 296.000 659.090 300.000 ;
    END
  END mstream_o[640]
  PIN mstream_o[641]
    DIRECTION OUTPUT TRISTATE ;
    USE SIGNAL ;
    ANTENNADIFFAREA 0.795200 ;
    PORT
      LAYER met2 ;
        RECT 659.730 296.000 660.010 300.000 ;
    END
  END mstream_o[641]
  PIN mstream_o[642]
    DIRECTION OUTPUT TRISTATE ;
    USE SIGNAL ;
    ANTENNADIFFAREA 0.795200 ;
    PORT
      LAYER met2 ;
        RECT 660.650 296.000 660.930 300.000 ;
    END
  END mstream_o[642]
  PIN mstream_o[643]
    DIRECTION OUTPUT TRISTATE ;
    USE SIGNAL ;
    ANTENNADIFFAREA 0.795200 ;
    PORT
      LAYER met2 ;
        RECT 661.570 296.000 661.850 300.000 ;
    END
  END mstream_o[643]
  PIN mstream_o[644]
    DIRECTION OUTPUT TRISTATE ;
    USE SIGNAL ;
    ANTENNADIFFAREA 0.795200 ;
    PORT
      LAYER met2 ;
        RECT 662.490 296.000 662.770 300.000 ;
    END
  END mstream_o[644]
  PIN mstream_o[645]
    DIRECTION OUTPUT TRISTATE ;
    USE SIGNAL ;
    ANTENNADIFFAREA 0.795200 ;
    PORT
      LAYER met2 ;
        RECT 663.410 296.000 663.690 300.000 ;
    END
  END mstream_o[645]
  PIN mstream_o[646]
    DIRECTION OUTPUT TRISTATE ;
    USE SIGNAL ;
    ANTENNADIFFAREA 0.795200 ;
    PORT
      LAYER met2 ;
        RECT 664.330 296.000 664.610 300.000 ;
    END
  END mstream_o[646]
  PIN mstream_o[647]
    DIRECTION OUTPUT TRISTATE ;
    USE SIGNAL ;
    ANTENNADIFFAREA 0.795200 ;
    PORT
      LAYER met2 ;
        RECT 665.250 296.000 665.530 300.000 ;
    END
  END mstream_o[647]
  PIN mstream_o[648]
    DIRECTION OUTPUT TRISTATE ;
    USE SIGNAL ;
    ANTENNADIFFAREA 0.795200 ;
    PORT
      LAYER met2 ;
        RECT 666.170 296.000 666.450 300.000 ;
    END
  END mstream_o[648]
  PIN mstream_o[649]
    DIRECTION OUTPUT TRISTATE ;
    USE SIGNAL ;
    ANTENNADIFFAREA 0.795200 ;
    PORT
      LAYER met2 ;
        RECT 667.090 296.000 667.370 300.000 ;
    END
  END mstream_o[649]
  PIN mstream_o[64]
    DIRECTION OUTPUT TRISTATE ;
    USE SIGNAL ;
    ANTENNADIFFAREA 0.795200 ;
    PORT
      LAYER met2 ;
        RECT 128.890 296.000 129.170 300.000 ;
    END
  END mstream_o[64]
  PIN mstream_o[650]
    DIRECTION OUTPUT TRISTATE ;
    USE SIGNAL ;
    ANTENNADIFFAREA 0.795200 ;
    PORT
      LAYER met2 ;
        RECT 668.010 296.000 668.290 300.000 ;
    END
  END mstream_o[650]
  PIN mstream_o[651]
    DIRECTION OUTPUT TRISTATE ;
    USE SIGNAL ;
    ANTENNADIFFAREA 0.795200 ;
    PORT
      LAYER met2 ;
        RECT 668.930 296.000 669.210 300.000 ;
    END
  END mstream_o[651]
  PIN mstream_o[652]
    DIRECTION OUTPUT TRISTATE ;
    USE SIGNAL ;
    ANTENNADIFFAREA 0.795200 ;
    PORT
      LAYER met2 ;
        RECT 669.850 296.000 670.130 300.000 ;
    END
  END mstream_o[652]
  PIN mstream_o[653]
    DIRECTION OUTPUT TRISTATE ;
    USE SIGNAL ;
    ANTENNADIFFAREA 0.795200 ;
    PORT
      LAYER met2 ;
        RECT 670.770 296.000 671.050 300.000 ;
    END
  END mstream_o[653]
  PIN mstream_o[654]
    DIRECTION OUTPUT TRISTATE ;
    USE SIGNAL ;
    ANTENNADIFFAREA 0.795200 ;
    PORT
      LAYER met2 ;
        RECT 671.690 296.000 671.970 300.000 ;
    END
  END mstream_o[654]
  PIN mstream_o[655]
    DIRECTION OUTPUT TRISTATE ;
    USE SIGNAL ;
    ANTENNADIFFAREA 0.795200 ;
    PORT
      LAYER met2 ;
        RECT 672.610 296.000 672.890 300.000 ;
    END
  END mstream_o[655]
  PIN mstream_o[656]
    DIRECTION OUTPUT TRISTATE ;
    USE SIGNAL ;
    ANTENNADIFFAREA 0.795200 ;
    PORT
      LAYER met2 ;
        RECT 673.530 296.000 673.810 300.000 ;
    END
  END mstream_o[656]
  PIN mstream_o[657]
    DIRECTION OUTPUT TRISTATE ;
    USE SIGNAL ;
    ANTENNADIFFAREA 0.795200 ;
    PORT
      LAYER met2 ;
        RECT 674.450 296.000 674.730 300.000 ;
    END
  END mstream_o[657]
  PIN mstream_o[658]
    DIRECTION OUTPUT TRISTATE ;
    USE SIGNAL ;
    ANTENNADIFFAREA 0.795200 ;
    PORT
      LAYER met2 ;
        RECT 675.370 296.000 675.650 300.000 ;
    END
  END mstream_o[658]
  PIN mstream_o[659]
    DIRECTION OUTPUT TRISTATE ;
    USE SIGNAL ;
    ANTENNADIFFAREA 0.795200 ;
    PORT
      LAYER met2 ;
        RECT 676.290 296.000 676.570 300.000 ;
    END
  END mstream_o[659]
  PIN mstream_o[65]
    DIRECTION OUTPUT TRISTATE ;
    USE SIGNAL ;
    ANTENNADIFFAREA 0.795200 ;
    PORT
      LAYER met2 ;
        RECT 129.810 296.000 130.090 300.000 ;
    END
  END mstream_o[65]
  PIN mstream_o[660]
    DIRECTION OUTPUT TRISTATE ;
    USE SIGNAL ;
    ANTENNADIFFAREA 0.795200 ;
    PORT
      LAYER met2 ;
        RECT 677.210 296.000 677.490 300.000 ;
    END
  END mstream_o[660]
  PIN mstream_o[661]
    DIRECTION OUTPUT TRISTATE ;
    USE SIGNAL ;
    ANTENNADIFFAREA 0.795200 ;
    PORT
      LAYER met2 ;
        RECT 678.130 296.000 678.410 300.000 ;
    END
  END mstream_o[661]
  PIN mstream_o[662]
    DIRECTION OUTPUT TRISTATE ;
    USE SIGNAL ;
    ANTENNADIFFAREA 0.795200 ;
    PORT
      LAYER met2 ;
        RECT 679.050 296.000 679.330 300.000 ;
    END
  END mstream_o[662]
  PIN mstream_o[663]
    DIRECTION OUTPUT TRISTATE ;
    USE SIGNAL ;
    ANTENNADIFFAREA 0.795200 ;
    PORT
      LAYER met2 ;
        RECT 679.970 296.000 680.250 300.000 ;
    END
  END mstream_o[663]
  PIN mstream_o[664]
    DIRECTION OUTPUT TRISTATE ;
    USE SIGNAL ;
    ANTENNADIFFAREA 0.795200 ;
    PORT
      LAYER met2 ;
        RECT 680.890 296.000 681.170 300.000 ;
    END
  END mstream_o[664]
  PIN mstream_o[665]
    DIRECTION OUTPUT TRISTATE ;
    USE SIGNAL ;
    ANTENNADIFFAREA 0.795200 ;
    PORT
      LAYER met2 ;
        RECT 681.810 296.000 682.090 300.000 ;
    END
  END mstream_o[665]
  PIN mstream_o[666]
    DIRECTION OUTPUT TRISTATE ;
    USE SIGNAL ;
    ANTENNADIFFAREA 0.795200 ;
    PORT
      LAYER met2 ;
        RECT 682.730 296.000 683.010 300.000 ;
    END
  END mstream_o[666]
  PIN mstream_o[667]
    DIRECTION OUTPUT TRISTATE ;
    USE SIGNAL ;
    ANTENNADIFFAREA 0.795200 ;
    PORT
      LAYER met2 ;
        RECT 683.650 296.000 683.930 300.000 ;
    END
  END mstream_o[667]
  PIN mstream_o[668]
    DIRECTION OUTPUT TRISTATE ;
    USE SIGNAL ;
    ANTENNADIFFAREA 0.795200 ;
    PORT
      LAYER met2 ;
        RECT 684.570 296.000 684.850 300.000 ;
    END
  END mstream_o[668]
  PIN mstream_o[669]
    DIRECTION OUTPUT TRISTATE ;
    USE SIGNAL ;
    ANTENNADIFFAREA 0.795200 ;
    PORT
      LAYER met2 ;
        RECT 685.490 296.000 685.770 300.000 ;
    END
  END mstream_o[669]
  PIN mstream_o[66]
    DIRECTION OUTPUT TRISTATE ;
    USE SIGNAL ;
    ANTENNADIFFAREA 0.795200 ;
    PORT
      LAYER met2 ;
        RECT 130.730 296.000 131.010 300.000 ;
    END
  END mstream_o[66]
  PIN mstream_o[670]
    DIRECTION OUTPUT TRISTATE ;
    USE SIGNAL ;
    ANTENNADIFFAREA 0.795200 ;
    PORT
      LAYER met2 ;
        RECT 686.410 296.000 686.690 300.000 ;
    END
  END mstream_o[670]
  PIN mstream_o[671]
    DIRECTION OUTPUT TRISTATE ;
    USE SIGNAL ;
    ANTENNADIFFAREA 0.795200 ;
    PORT
      LAYER met2 ;
        RECT 687.330 296.000 687.610 300.000 ;
    END
  END mstream_o[671]
  PIN mstream_o[672]
    DIRECTION OUTPUT TRISTATE ;
    USE SIGNAL ;
    ANTENNADIFFAREA 0.795200 ;
    PORT
      LAYER met2 ;
        RECT 688.250 296.000 688.530 300.000 ;
    END
  END mstream_o[672]
  PIN mstream_o[673]
    DIRECTION OUTPUT TRISTATE ;
    USE SIGNAL ;
    ANTENNADIFFAREA 0.795200 ;
    PORT
      LAYER met2 ;
        RECT 689.170 296.000 689.450 300.000 ;
    END
  END mstream_o[673]
  PIN mstream_o[674]
    DIRECTION OUTPUT TRISTATE ;
    USE SIGNAL ;
    ANTENNADIFFAREA 0.795200 ;
    PORT
      LAYER met2 ;
        RECT 690.090 296.000 690.370 300.000 ;
    END
  END mstream_o[674]
  PIN mstream_o[675]
    DIRECTION OUTPUT TRISTATE ;
    USE SIGNAL ;
    ANTENNADIFFAREA 0.795200 ;
    PORT
      LAYER met2 ;
        RECT 691.010 296.000 691.290 300.000 ;
    END
  END mstream_o[675]
  PIN mstream_o[676]
    DIRECTION OUTPUT TRISTATE ;
    USE SIGNAL ;
    ANTENNADIFFAREA 0.795200 ;
    PORT
      LAYER met2 ;
        RECT 691.930 296.000 692.210 300.000 ;
    END
  END mstream_o[676]
  PIN mstream_o[677]
    DIRECTION OUTPUT TRISTATE ;
    USE SIGNAL ;
    ANTENNADIFFAREA 0.795200 ;
    PORT
      LAYER met2 ;
        RECT 692.850 296.000 693.130 300.000 ;
    END
  END mstream_o[677]
  PIN mstream_o[678]
    DIRECTION OUTPUT TRISTATE ;
    USE SIGNAL ;
    ANTENNADIFFAREA 0.795200 ;
    PORT
      LAYER met2 ;
        RECT 693.770 296.000 694.050 300.000 ;
    END
  END mstream_o[678]
  PIN mstream_o[679]
    DIRECTION OUTPUT TRISTATE ;
    USE SIGNAL ;
    ANTENNADIFFAREA 0.795200 ;
    PORT
      LAYER met2 ;
        RECT 694.690 296.000 694.970 300.000 ;
    END
  END mstream_o[679]
  PIN mstream_o[67]
    DIRECTION OUTPUT TRISTATE ;
    USE SIGNAL ;
    ANTENNADIFFAREA 0.795200 ;
    PORT
      LAYER met2 ;
        RECT 131.650 296.000 131.930 300.000 ;
    END
  END mstream_o[67]
  PIN mstream_o[680]
    DIRECTION OUTPUT TRISTATE ;
    USE SIGNAL ;
    ANTENNADIFFAREA 0.795200 ;
    PORT
      LAYER met2 ;
        RECT 695.610 296.000 695.890 300.000 ;
    END
  END mstream_o[680]
  PIN mstream_o[681]
    DIRECTION OUTPUT TRISTATE ;
    USE SIGNAL ;
    ANTENNADIFFAREA 0.795200 ;
    PORT
      LAYER met2 ;
        RECT 696.530 296.000 696.810 300.000 ;
    END
  END mstream_o[681]
  PIN mstream_o[682]
    DIRECTION OUTPUT TRISTATE ;
    USE SIGNAL ;
    ANTENNADIFFAREA 0.795200 ;
    PORT
      LAYER met2 ;
        RECT 697.450 296.000 697.730 300.000 ;
    END
  END mstream_o[682]
  PIN mstream_o[683]
    DIRECTION OUTPUT TRISTATE ;
    USE SIGNAL ;
    ANTENNADIFFAREA 0.795200 ;
    PORT
      LAYER met2 ;
        RECT 698.370 296.000 698.650 300.000 ;
    END
  END mstream_o[683]
  PIN mstream_o[684]
    DIRECTION OUTPUT TRISTATE ;
    USE SIGNAL ;
    ANTENNADIFFAREA 0.795200 ;
    PORT
      LAYER met2 ;
        RECT 699.290 296.000 699.570 300.000 ;
    END
  END mstream_o[684]
  PIN mstream_o[685]
    DIRECTION OUTPUT TRISTATE ;
    USE SIGNAL ;
    ANTENNADIFFAREA 0.795200 ;
    PORT
      LAYER met2 ;
        RECT 700.210 296.000 700.490 300.000 ;
    END
  END mstream_o[685]
  PIN mstream_o[686]
    DIRECTION OUTPUT TRISTATE ;
    USE SIGNAL ;
    ANTENNADIFFAREA 0.795200 ;
    PORT
      LAYER met2 ;
        RECT 701.130 296.000 701.410 300.000 ;
    END
  END mstream_o[686]
  PIN mstream_o[687]
    DIRECTION OUTPUT TRISTATE ;
    USE SIGNAL ;
    ANTENNADIFFAREA 0.795200 ;
    PORT
      LAYER met2 ;
        RECT 702.050 296.000 702.330 300.000 ;
    END
  END mstream_o[687]
  PIN mstream_o[688]
    DIRECTION OUTPUT TRISTATE ;
    USE SIGNAL ;
    ANTENNADIFFAREA 0.795200 ;
    PORT
      LAYER met2 ;
        RECT 702.970 296.000 703.250 300.000 ;
    END
  END mstream_o[688]
  PIN mstream_o[689]
    DIRECTION OUTPUT TRISTATE ;
    USE SIGNAL ;
    ANTENNADIFFAREA 0.795200 ;
    PORT
      LAYER met2 ;
        RECT 703.890 296.000 704.170 300.000 ;
    END
  END mstream_o[689]
  PIN mstream_o[68]
    DIRECTION OUTPUT TRISTATE ;
    USE SIGNAL ;
    ANTENNADIFFAREA 0.795200 ;
    PORT
      LAYER met2 ;
        RECT 132.570 296.000 132.850 300.000 ;
    END
  END mstream_o[68]
  PIN mstream_o[690]
    DIRECTION OUTPUT TRISTATE ;
    USE SIGNAL ;
    ANTENNADIFFAREA 0.795200 ;
    PORT
      LAYER met2 ;
        RECT 704.810 296.000 705.090 300.000 ;
    END
  END mstream_o[690]
  PIN mstream_o[691]
    DIRECTION OUTPUT TRISTATE ;
    USE SIGNAL ;
    ANTENNADIFFAREA 0.795200 ;
    PORT
      LAYER met2 ;
        RECT 705.730 296.000 706.010 300.000 ;
    END
  END mstream_o[691]
  PIN mstream_o[692]
    DIRECTION OUTPUT TRISTATE ;
    USE SIGNAL ;
    ANTENNADIFFAREA 0.795200 ;
    PORT
      LAYER met2 ;
        RECT 706.650 296.000 706.930 300.000 ;
    END
  END mstream_o[692]
  PIN mstream_o[693]
    DIRECTION OUTPUT TRISTATE ;
    USE SIGNAL ;
    ANTENNADIFFAREA 0.795200 ;
    PORT
      LAYER met2 ;
        RECT 707.570 296.000 707.850 300.000 ;
    END
  END mstream_o[693]
  PIN mstream_o[694]
    DIRECTION OUTPUT TRISTATE ;
    USE SIGNAL ;
    ANTENNADIFFAREA 0.795200 ;
    PORT
      LAYER met2 ;
        RECT 708.490 296.000 708.770 300.000 ;
    END
  END mstream_o[694]
  PIN mstream_o[695]
    DIRECTION OUTPUT TRISTATE ;
    USE SIGNAL ;
    ANTENNADIFFAREA 0.795200 ;
    PORT
      LAYER met2 ;
        RECT 709.410 296.000 709.690 300.000 ;
    END
  END mstream_o[695]
  PIN mstream_o[696]
    DIRECTION OUTPUT TRISTATE ;
    USE SIGNAL ;
    ANTENNADIFFAREA 0.795200 ;
    PORT
      LAYER met2 ;
        RECT 710.330 296.000 710.610 300.000 ;
    END
  END mstream_o[696]
  PIN mstream_o[697]
    DIRECTION OUTPUT TRISTATE ;
    USE SIGNAL ;
    ANTENNADIFFAREA 0.795200 ;
    PORT
      LAYER met2 ;
        RECT 711.250 296.000 711.530 300.000 ;
    END
  END mstream_o[697]
  PIN mstream_o[698]
    DIRECTION OUTPUT TRISTATE ;
    USE SIGNAL ;
    ANTENNADIFFAREA 0.795200 ;
    PORT
      LAYER met2 ;
        RECT 712.170 296.000 712.450 300.000 ;
    END
  END mstream_o[698]
  PIN mstream_o[699]
    DIRECTION OUTPUT TRISTATE ;
    USE SIGNAL ;
    ANTENNADIFFAREA 0.795200 ;
    PORT
      LAYER met2 ;
        RECT 713.090 296.000 713.370 300.000 ;
    END
  END mstream_o[699]
  PIN mstream_o[69]
    DIRECTION OUTPUT TRISTATE ;
    USE SIGNAL ;
    ANTENNADIFFAREA 0.795200 ;
    PORT
      LAYER met2 ;
        RECT 133.490 296.000 133.770 300.000 ;
    END
  END mstream_o[69]
  PIN mstream_o[6]
    DIRECTION OUTPUT TRISTATE ;
    USE SIGNAL ;
    ANTENNADIFFAREA 0.795200 ;
    PORT
      LAYER met2 ;
        RECT 75.530 296.000 75.810 300.000 ;
    END
  END mstream_o[6]
  PIN mstream_o[700]
    DIRECTION OUTPUT TRISTATE ;
    USE SIGNAL ;
    ANTENNADIFFAREA 0.795200 ;
    PORT
      LAYER met2 ;
        RECT 714.010 296.000 714.290 300.000 ;
    END
  END mstream_o[700]
  PIN mstream_o[701]
    DIRECTION OUTPUT TRISTATE ;
    USE SIGNAL ;
    ANTENNADIFFAREA 0.795200 ;
    PORT
      LAYER met2 ;
        RECT 714.930 296.000 715.210 300.000 ;
    END
  END mstream_o[701]
  PIN mstream_o[702]
    DIRECTION OUTPUT TRISTATE ;
    USE SIGNAL ;
    ANTENNADIFFAREA 0.795200 ;
    PORT
      LAYER met2 ;
        RECT 715.850 296.000 716.130 300.000 ;
    END
  END mstream_o[702]
  PIN mstream_o[703]
    DIRECTION OUTPUT TRISTATE ;
    USE SIGNAL ;
    ANTENNADIFFAREA 0.795200 ;
    PORT
      LAYER met2 ;
        RECT 716.770 296.000 717.050 300.000 ;
    END
  END mstream_o[703]
  PIN mstream_o[704]
    DIRECTION OUTPUT TRISTATE ;
    USE SIGNAL ;
    ANTENNADIFFAREA 0.795200 ;
    PORT
      LAYER met2 ;
        RECT 717.690 296.000 717.970 300.000 ;
    END
  END mstream_o[704]
  PIN mstream_o[705]
    DIRECTION OUTPUT TRISTATE ;
    USE SIGNAL ;
    ANTENNADIFFAREA 0.795200 ;
    PORT
      LAYER met2 ;
        RECT 718.610 296.000 718.890 300.000 ;
    END
  END mstream_o[705]
  PIN mstream_o[706]
    DIRECTION OUTPUT TRISTATE ;
    USE SIGNAL ;
    ANTENNADIFFAREA 0.795200 ;
    PORT
      LAYER met2 ;
        RECT 719.530 296.000 719.810 300.000 ;
    END
  END mstream_o[706]
  PIN mstream_o[707]
    DIRECTION OUTPUT TRISTATE ;
    USE SIGNAL ;
    ANTENNADIFFAREA 0.795200 ;
    PORT
      LAYER met2 ;
        RECT 720.450 296.000 720.730 300.000 ;
    END
  END mstream_o[707]
  PIN mstream_o[708]
    DIRECTION OUTPUT TRISTATE ;
    USE SIGNAL ;
    ANTENNADIFFAREA 0.795200 ;
    PORT
      LAYER met2 ;
        RECT 721.370 296.000 721.650 300.000 ;
    END
  END mstream_o[708]
  PIN mstream_o[709]
    DIRECTION OUTPUT TRISTATE ;
    USE SIGNAL ;
    ANTENNADIFFAREA 0.795200 ;
    PORT
      LAYER met2 ;
        RECT 722.290 296.000 722.570 300.000 ;
    END
  END mstream_o[709]
  PIN mstream_o[70]
    DIRECTION OUTPUT TRISTATE ;
    USE SIGNAL ;
    ANTENNADIFFAREA 0.795200 ;
    PORT
      LAYER met2 ;
        RECT 134.410 296.000 134.690 300.000 ;
    END
  END mstream_o[70]
  PIN mstream_o[710]
    DIRECTION OUTPUT TRISTATE ;
    USE SIGNAL ;
    ANTENNADIFFAREA 0.795200 ;
    PORT
      LAYER met2 ;
        RECT 723.210 296.000 723.490 300.000 ;
    END
  END mstream_o[710]
  PIN mstream_o[711]
    DIRECTION OUTPUT TRISTATE ;
    USE SIGNAL ;
    ANTENNADIFFAREA 0.795200 ;
    PORT
      LAYER met2 ;
        RECT 724.130 296.000 724.410 300.000 ;
    END
  END mstream_o[711]
  PIN mstream_o[712]
    DIRECTION OUTPUT TRISTATE ;
    USE SIGNAL ;
    ANTENNADIFFAREA 0.795200 ;
    PORT
      LAYER met2 ;
        RECT 725.050 296.000 725.330 300.000 ;
    END
  END mstream_o[712]
  PIN mstream_o[713]
    DIRECTION OUTPUT TRISTATE ;
    USE SIGNAL ;
    ANTENNADIFFAREA 0.795200 ;
    PORT
      LAYER met2 ;
        RECT 725.970 296.000 726.250 300.000 ;
    END
  END mstream_o[713]
  PIN mstream_o[714]
    DIRECTION OUTPUT TRISTATE ;
    USE SIGNAL ;
    ANTENNADIFFAREA 0.795200 ;
    PORT
      LAYER met2 ;
        RECT 726.890 296.000 727.170 300.000 ;
    END
  END mstream_o[714]
  PIN mstream_o[715]
    DIRECTION OUTPUT TRISTATE ;
    USE SIGNAL ;
    ANTENNADIFFAREA 0.795200 ;
    PORT
      LAYER met2 ;
        RECT 727.810 296.000 728.090 300.000 ;
    END
  END mstream_o[715]
  PIN mstream_o[716]
    DIRECTION OUTPUT TRISTATE ;
    USE SIGNAL ;
    ANTENNADIFFAREA 0.795200 ;
    PORT
      LAYER met2 ;
        RECT 728.730 296.000 729.010 300.000 ;
    END
  END mstream_o[716]
  PIN mstream_o[717]
    DIRECTION OUTPUT TRISTATE ;
    USE SIGNAL ;
    ANTENNADIFFAREA 0.795200 ;
    PORT
      LAYER met2 ;
        RECT 729.650 296.000 729.930 300.000 ;
    END
  END mstream_o[717]
  PIN mstream_o[718]
    DIRECTION OUTPUT TRISTATE ;
    USE SIGNAL ;
    ANTENNADIFFAREA 0.795200 ;
    PORT
      LAYER met2 ;
        RECT 730.570 296.000 730.850 300.000 ;
    END
  END mstream_o[718]
  PIN mstream_o[719]
    DIRECTION OUTPUT TRISTATE ;
    USE SIGNAL ;
    ANTENNADIFFAREA 0.795200 ;
    PORT
      LAYER met2 ;
        RECT 731.490 296.000 731.770 300.000 ;
    END
  END mstream_o[719]
  PIN mstream_o[71]
    DIRECTION OUTPUT TRISTATE ;
    USE SIGNAL ;
    ANTENNADIFFAREA 0.795200 ;
    PORT
      LAYER met2 ;
        RECT 135.330 296.000 135.610 300.000 ;
    END
  END mstream_o[71]
  PIN mstream_o[720]
    DIRECTION OUTPUT TRISTATE ;
    USE SIGNAL ;
    ANTENNADIFFAREA 0.795200 ;
    PORT
      LAYER met2 ;
        RECT 732.410 296.000 732.690 300.000 ;
    END
  END mstream_o[720]
  PIN mstream_o[721]
    DIRECTION OUTPUT TRISTATE ;
    USE SIGNAL ;
    ANTENNADIFFAREA 0.795200 ;
    PORT
      LAYER met2 ;
        RECT 733.330 296.000 733.610 300.000 ;
    END
  END mstream_o[721]
  PIN mstream_o[722]
    DIRECTION OUTPUT TRISTATE ;
    USE SIGNAL ;
    ANTENNADIFFAREA 0.795200 ;
    PORT
      LAYER met2 ;
        RECT 734.250 296.000 734.530 300.000 ;
    END
  END mstream_o[722]
  PIN mstream_o[723]
    DIRECTION OUTPUT TRISTATE ;
    USE SIGNAL ;
    ANTENNADIFFAREA 0.795200 ;
    PORT
      LAYER met2 ;
        RECT 735.170 296.000 735.450 300.000 ;
    END
  END mstream_o[723]
  PIN mstream_o[724]
    DIRECTION OUTPUT TRISTATE ;
    USE SIGNAL ;
    ANTENNADIFFAREA 0.795200 ;
    PORT
      LAYER met2 ;
        RECT 736.090 296.000 736.370 300.000 ;
    END
  END mstream_o[724]
  PIN mstream_o[725]
    DIRECTION OUTPUT TRISTATE ;
    USE SIGNAL ;
    ANTENNADIFFAREA 0.795200 ;
    PORT
      LAYER met2 ;
        RECT 737.010 296.000 737.290 300.000 ;
    END
  END mstream_o[725]
  PIN mstream_o[726]
    DIRECTION OUTPUT TRISTATE ;
    USE SIGNAL ;
    ANTENNADIFFAREA 0.795200 ;
    PORT
      LAYER met2 ;
        RECT 737.930 296.000 738.210 300.000 ;
    END
  END mstream_o[726]
  PIN mstream_o[727]
    DIRECTION OUTPUT TRISTATE ;
    USE SIGNAL ;
    ANTENNADIFFAREA 0.795200 ;
    PORT
      LAYER met2 ;
        RECT 738.850 296.000 739.130 300.000 ;
    END
  END mstream_o[727]
  PIN mstream_o[728]
    DIRECTION OUTPUT TRISTATE ;
    USE SIGNAL ;
    ANTENNADIFFAREA 0.795200 ;
    PORT
      LAYER met2 ;
        RECT 739.770 296.000 740.050 300.000 ;
    END
  END mstream_o[728]
  PIN mstream_o[729]
    DIRECTION OUTPUT TRISTATE ;
    USE SIGNAL ;
    ANTENNADIFFAREA 0.795200 ;
    PORT
      LAYER met2 ;
        RECT 740.690 296.000 740.970 300.000 ;
    END
  END mstream_o[729]
  PIN mstream_o[72]
    DIRECTION OUTPUT TRISTATE ;
    USE SIGNAL ;
    ANTENNADIFFAREA 0.795200 ;
    PORT
      LAYER met2 ;
        RECT 136.250 296.000 136.530 300.000 ;
    END
  END mstream_o[72]
  PIN mstream_o[730]
    DIRECTION OUTPUT TRISTATE ;
    USE SIGNAL ;
    ANTENNADIFFAREA 0.795200 ;
    PORT
      LAYER met2 ;
        RECT 741.610 296.000 741.890 300.000 ;
    END
  END mstream_o[730]
  PIN mstream_o[731]
    DIRECTION OUTPUT TRISTATE ;
    USE SIGNAL ;
    ANTENNADIFFAREA 0.795200 ;
    PORT
      LAYER met2 ;
        RECT 742.530 296.000 742.810 300.000 ;
    END
  END mstream_o[731]
  PIN mstream_o[732]
    DIRECTION OUTPUT TRISTATE ;
    USE SIGNAL ;
    ANTENNADIFFAREA 0.795200 ;
    PORT
      LAYER met2 ;
        RECT 743.450 296.000 743.730 300.000 ;
    END
  END mstream_o[732]
  PIN mstream_o[733]
    DIRECTION OUTPUT TRISTATE ;
    USE SIGNAL ;
    ANTENNADIFFAREA 0.795200 ;
    PORT
      LAYER met2 ;
        RECT 744.370 296.000 744.650 300.000 ;
    END
  END mstream_o[733]
  PIN mstream_o[734]
    DIRECTION OUTPUT TRISTATE ;
    USE SIGNAL ;
    ANTENNADIFFAREA 0.795200 ;
    PORT
      LAYER met2 ;
        RECT 745.290 296.000 745.570 300.000 ;
    END
  END mstream_o[734]
  PIN mstream_o[735]
    DIRECTION OUTPUT TRISTATE ;
    USE SIGNAL ;
    ANTENNADIFFAREA 0.795200 ;
    PORT
      LAYER met2 ;
        RECT 746.210 296.000 746.490 300.000 ;
    END
  END mstream_o[735]
  PIN mstream_o[736]
    DIRECTION OUTPUT TRISTATE ;
    USE SIGNAL ;
    ANTENNADIFFAREA 0.795200 ;
    PORT
      LAYER met2 ;
        RECT 747.130 296.000 747.410 300.000 ;
    END
  END mstream_o[736]
  PIN mstream_o[737]
    DIRECTION OUTPUT TRISTATE ;
    USE SIGNAL ;
    ANTENNADIFFAREA 0.795200 ;
    PORT
      LAYER met2 ;
        RECT 748.050 296.000 748.330 300.000 ;
    END
  END mstream_o[737]
  PIN mstream_o[738]
    DIRECTION OUTPUT TRISTATE ;
    USE SIGNAL ;
    ANTENNADIFFAREA 0.795200 ;
    PORT
      LAYER met2 ;
        RECT 748.970 296.000 749.250 300.000 ;
    END
  END mstream_o[738]
  PIN mstream_o[739]
    DIRECTION OUTPUT TRISTATE ;
    USE SIGNAL ;
    ANTENNADIFFAREA 0.795200 ;
    PORT
      LAYER met2 ;
        RECT 749.890 296.000 750.170 300.000 ;
    END
  END mstream_o[739]
  PIN mstream_o[73]
    DIRECTION OUTPUT TRISTATE ;
    USE SIGNAL ;
    ANTENNADIFFAREA 0.795200 ;
    PORT
      LAYER met2 ;
        RECT 137.170 296.000 137.450 300.000 ;
    END
  END mstream_o[73]
  PIN mstream_o[740]
    DIRECTION OUTPUT TRISTATE ;
    USE SIGNAL ;
    ANTENNADIFFAREA 0.795200 ;
    PORT
      LAYER met2 ;
        RECT 750.810 296.000 751.090 300.000 ;
    END
  END mstream_o[740]
  PIN mstream_o[741]
    DIRECTION OUTPUT TRISTATE ;
    USE SIGNAL ;
    ANTENNADIFFAREA 0.795200 ;
    PORT
      LAYER met2 ;
        RECT 751.730 296.000 752.010 300.000 ;
    END
  END mstream_o[741]
  PIN mstream_o[742]
    DIRECTION OUTPUT TRISTATE ;
    USE SIGNAL ;
    ANTENNADIFFAREA 0.795200 ;
    PORT
      LAYER met2 ;
        RECT 752.650 296.000 752.930 300.000 ;
    END
  END mstream_o[742]
  PIN mstream_o[743]
    DIRECTION OUTPUT TRISTATE ;
    USE SIGNAL ;
    ANTENNADIFFAREA 0.795200 ;
    PORT
      LAYER met2 ;
        RECT 753.570 296.000 753.850 300.000 ;
    END
  END mstream_o[743]
  PIN mstream_o[744]
    DIRECTION OUTPUT TRISTATE ;
    USE SIGNAL ;
    ANTENNADIFFAREA 0.795200 ;
    PORT
      LAYER met2 ;
        RECT 754.490 296.000 754.770 300.000 ;
    END
  END mstream_o[744]
  PIN mstream_o[745]
    DIRECTION OUTPUT TRISTATE ;
    USE SIGNAL ;
    ANTENNADIFFAREA 0.795200 ;
    PORT
      LAYER met2 ;
        RECT 755.410 296.000 755.690 300.000 ;
    END
  END mstream_o[745]
  PIN mstream_o[746]
    DIRECTION OUTPUT TRISTATE ;
    USE SIGNAL ;
    ANTENNADIFFAREA 0.795200 ;
    PORT
      LAYER met2 ;
        RECT 756.330 296.000 756.610 300.000 ;
    END
  END mstream_o[746]
  PIN mstream_o[747]
    DIRECTION OUTPUT TRISTATE ;
    USE SIGNAL ;
    ANTENNADIFFAREA 0.795200 ;
    PORT
      LAYER met2 ;
        RECT 757.250 296.000 757.530 300.000 ;
    END
  END mstream_o[747]
  PIN mstream_o[748]
    DIRECTION OUTPUT TRISTATE ;
    USE SIGNAL ;
    ANTENNADIFFAREA 0.795200 ;
    PORT
      LAYER met2 ;
        RECT 758.170 296.000 758.450 300.000 ;
    END
  END mstream_o[748]
  PIN mstream_o[749]
    DIRECTION OUTPUT TRISTATE ;
    USE SIGNAL ;
    ANTENNADIFFAREA 0.795200 ;
    PORT
      LAYER met2 ;
        RECT 759.090 296.000 759.370 300.000 ;
    END
  END mstream_o[749]
  PIN mstream_o[74]
    DIRECTION OUTPUT TRISTATE ;
    USE SIGNAL ;
    ANTENNADIFFAREA 0.795200 ;
    PORT
      LAYER met2 ;
        RECT 138.090 296.000 138.370 300.000 ;
    END
  END mstream_o[74]
  PIN mstream_o[750]
    DIRECTION OUTPUT TRISTATE ;
    USE SIGNAL ;
    ANTENNADIFFAREA 0.795200 ;
    PORT
      LAYER met2 ;
        RECT 760.010 296.000 760.290 300.000 ;
    END
  END mstream_o[750]
  PIN mstream_o[751]
    DIRECTION OUTPUT TRISTATE ;
    USE SIGNAL ;
    ANTENNADIFFAREA 0.795200 ;
    PORT
      LAYER met2 ;
        RECT 760.930 296.000 761.210 300.000 ;
    END
  END mstream_o[751]
  PIN mstream_o[752]
    DIRECTION OUTPUT TRISTATE ;
    USE SIGNAL ;
    ANTENNADIFFAREA 0.795200 ;
    PORT
      LAYER met2 ;
        RECT 761.850 296.000 762.130 300.000 ;
    END
  END mstream_o[752]
  PIN mstream_o[753]
    DIRECTION OUTPUT TRISTATE ;
    USE SIGNAL ;
    ANTENNADIFFAREA 0.795200 ;
    PORT
      LAYER met2 ;
        RECT 762.770 296.000 763.050 300.000 ;
    END
  END mstream_o[753]
  PIN mstream_o[754]
    DIRECTION OUTPUT TRISTATE ;
    USE SIGNAL ;
    ANTENNADIFFAREA 0.795200 ;
    PORT
      LAYER met2 ;
        RECT 763.690 296.000 763.970 300.000 ;
    END
  END mstream_o[754]
  PIN mstream_o[755]
    DIRECTION OUTPUT TRISTATE ;
    USE SIGNAL ;
    ANTENNADIFFAREA 0.795200 ;
    PORT
      LAYER met2 ;
        RECT 764.610 296.000 764.890 300.000 ;
    END
  END mstream_o[755]
  PIN mstream_o[756]
    DIRECTION OUTPUT TRISTATE ;
    USE SIGNAL ;
    ANTENNADIFFAREA 0.795200 ;
    PORT
      LAYER met2 ;
        RECT 765.530 296.000 765.810 300.000 ;
    END
  END mstream_o[756]
  PIN mstream_o[757]
    DIRECTION OUTPUT TRISTATE ;
    USE SIGNAL ;
    ANTENNADIFFAREA 0.795200 ;
    PORT
      LAYER met2 ;
        RECT 766.450 296.000 766.730 300.000 ;
    END
  END mstream_o[757]
  PIN mstream_o[758]
    DIRECTION OUTPUT TRISTATE ;
    USE SIGNAL ;
    ANTENNADIFFAREA 0.795200 ;
    PORT
      LAYER met2 ;
        RECT 767.370 296.000 767.650 300.000 ;
    END
  END mstream_o[758]
  PIN mstream_o[759]
    DIRECTION OUTPUT TRISTATE ;
    USE SIGNAL ;
    ANTENNADIFFAREA 0.795200 ;
    PORT
      LAYER met2 ;
        RECT 768.290 296.000 768.570 300.000 ;
    END
  END mstream_o[759]
  PIN mstream_o[75]
    DIRECTION OUTPUT TRISTATE ;
    USE SIGNAL ;
    ANTENNADIFFAREA 0.795200 ;
    PORT
      LAYER met2 ;
        RECT 139.010 296.000 139.290 300.000 ;
    END
  END mstream_o[75]
  PIN mstream_o[760]
    DIRECTION OUTPUT TRISTATE ;
    USE SIGNAL ;
    ANTENNADIFFAREA 0.795200 ;
    PORT
      LAYER met2 ;
        RECT 769.210 296.000 769.490 300.000 ;
    END
  END mstream_o[760]
  PIN mstream_o[761]
    DIRECTION OUTPUT TRISTATE ;
    USE SIGNAL ;
    ANTENNADIFFAREA 0.795200 ;
    PORT
      LAYER met2 ;
        RECT 770.130 296.000 770.410 300.000 ;
    END
  END mstream_o[761]
  PIN mstream_o[762]
    DIRECTION OUTPUT TRISTATE ;
    USE SIGNAL ;
    ANTENNADIFFAREA 0.795200 ;
    PORT
      LAYER met2 ;
        RECT 771.050 296.000 771.330 300.000 ;
    END
  END mstream_o[762]
  PIN mstream_o[763]
    DIRECTION OUTPUT TRISTATE ;
    USE SIGNAL ;
    ANTENNADIFFAREA 0.795200 ;
    PORT
      LAYER met2 ;
        RECT 771.970 296.000 772.250 300.000 ;
    END
  END mstream_o[763]
  PIN mstream_o[764]
    DIRECTION OUTPUT TRISTATE ;
    USE SIGNAL ;
    ANTENNADIFFAREA 0.795200 ;
    PORT
      LAYER met2 ;
        RECT 772.890 296.000 773.170 300.000 ;
    END
  END mstream_o[764]
  PIN mstream_o[765]
    DIRECTION OUTPUT TRISTATE ;
    USE SIGNAL ;
    ANTENNADIFFAREA 0.795200 ;
    PORT
      LAYER met2 ;
        RECT 773.810 296.000 774.090 300.000 ;
    END
  END mstream_o[765]
  PIN mstream_o[766]
    DIRECTION OUTPUT TRISTATE ;
    USE SIGNAL ;
    ANTENNADIFFAREA 0.795200 ;
    PORT
      LAYER met2 ;
        RECT 774.730 296.000 775.010 300.000 ;
    END
  END mstream_o[766]
  PIN mstream_o[767]
    DIRECTION OUTPUT TRISTATE ;
    USE SIGNAL ;
    ANTENNADIFFAREA 0.795200 ;
    PORT
      LAYER met2 ;
        RECT 775.650 296.000 775.930 300.000 ;
    END
  END mstream_o[767]
  PIN mstream_o[768]
    DIRECTION OUTPUT TRISTATE ;
    USE SIGNAL ;
    ANTENNADIFFAREA 0.795200 ;
    PORT
      LAYER met2 ;
        RECT 776.570 296.000 776.850 300.000 ;
    END
  END mstream_o[768]
  PIN mstream_o[769]
    DIRECTION OUTPUT TRISTATE ;
    USE SIGNAL ;
    ANTENNADIFFAREA 0.795200 ;
    PORT
      LAYER met2 ;
        RECT 777.490 296.000 777.770 300.000 ;
    END
  END mstream_o[769]
  PIN mstream_o[76]
    DIRECTION OUTPUT TRISTATE ;
    USE SIGNAL ;
    ANTENNADIFFAREA 0.795200 ;
    PORT
      LAYER met2 ;
        RECT 139.930 296.000 140.210 300.000 ;
    END
  END mstream_o[76]
  PIN mstream_o[770]
    DIRECTION OUTPUT TRISTATE ;
    USE SIGNAL ;
    ANTENNADIFFAREA 0.795200 ;
    PORT
      LAYER met2 ;
        RECT 778.410 296.000 778.690 300.000 ;
    END
  END mstream_o[770]
  PIN mstream_o[771]
    DIRECTION OUTPUT TRISTATE ;
    USE SIGNAL ;
    ANTENNADIFFAREA 0.795200 ;
    PORT
      LAYER met2 ;
        RECT 779.330 296.000 779.610 300.000 ;
    END
  END mstream_o[771]
  PIN mstream_o[772]
    DIRECTION OUTPUT TRISTATE ;
    USE SIGNAL ;
    ANTENNADIFFAREA 0.795200 ;
    PORT
      LAYER met2 ;
        RECT 780.250 296.000 780.530 300.000 ;
    END
  END mstream_o[772]
  PIN mstream_o[773]
    DIRECTION OUTPUT TRISTATE ;
    USE SIGNAL ;
    ANTENNADIFFAREA 0.795200 ;
    PORT
      LAYER met2 ;
        RECT 781.170 296.000 781.450 300.000 ;
    END
  END mstream_o[773]
  PIN mstream_o[774]
    DIRECTION OUTPUT TRISTATE ;
    USE SIGNAL ;
    ANTENNADIFFAREA 0.795200 ;
    PORT
      LAYER met2 ;
        RECT 782.090 296.000 782.370 300.000 ;
    END
  END mstream_o[774]
  PIN mstream_o[775]
    DIRECTION OUTPUT TRISTATE ;
    USE SIGNAL ;
    ANTENNADIFFAREA 0.795200 ;
    PORT
      LAYER met2 ;
        RECT 783.010 296.000 783.290 300.000 ;
    END
  END mstream_o[775]
  PIN mstream_o[776]
    DIRECTION OUTPUT TRISTATE ;
    USE SIGNAL ;
    ANTENNADIFFAREA 0.795200 ;
    PORT
      LAYER met2 ;
        RECT 783.930 296.000 784.210 300.000 ;
    END
  END mstream_o[776]
  PIN mstream_o[777]
    DIRECTION OUTPUT TRISTATE ;
    USE SIGNAL ;
    ANTENNADIFFAREA 0.795200 ;
    PORT
      LAYER met2 ;
        RECT 784.850 296.000 785.130 300.000 ;
    END
  END mstream_o[777]
  PIN mstream_o[778]
    DIRECTION OUTPUT TRISTATE ;
    USE SIGNAL ;
    ANTENNADIFFAREA 0.795200 ;
    PORT
      LAYER met2 ;
        RECT 785.770 296.000 786.050 300.000 ;
    END
  END mstream_o[778]
  PIN mstream_o[779]
    DIRECTION OUTPUT TRISTATE ;
    USE SIGNAL ;
    ANTENNADIFFAREA 0.795200 ;
    PORT
      LAYER met2 ;
        RECT 786.690 296.000 786.970 300.000 ;
    END
  END mstream_o[779]
  PIN mstream_o[77]
    DIRECTION OUTPUT TRISTATE ;
    USE SIGNAL ;
    ANTENNADIFFAREA 0.795200 ;
    PORT
      LAYER met2 ;
        RECT 140.850 296.000 141.130 300.000 ;
    END
  END mstream_o[77]
  PIN mstream_o[780]
    DIRECTION OUTPUT TRISTATE ;
    USE SIGNAL ;
    ANTENNADIFFAREA 0.795200 ;
    PORT
      LAYER met2 ;
        RECT 787.610 296.000 787.890 300.000 ;
    END
  END mstream_o[780]
  PIN mstream_o[781]
    DIRECTION OUTPUT TRISTATE ;
    USE SIGNAL ;
    ANTENNADIFFAREA 0.795200 ;
    PORT
      LAYER met2 ;
        RECT 788.530 296.000 788.810 300.000 ;
    END
  END mstream_o[781]
  PIN mstream_o[782]
    DIRECTION OUTPUT TRISTATE ;
    USE SIGNAL ;
    ANTENNADIFFAREA 0.795200 ;
    PORT
      LAYER met2 ;
        RECT 789.450 296.000 789.730 300.000 ;
    END
  END mstream_o[782]
  PIN mstream_o[783]
    DIRECTION OUTPUT TRISTATE ;
    USE SIGNAL ;
    ANTENNADIFFAREA 0.795200 ;
    PORT
      LAYER met2 ;
        RECT 790.370 296.000 790.650 300.000 ;
    END
  END mstream_o[783]
  PIN mstream_o[784]
    DIRECTION OUTPUT TRISTATE ;
    USE SIGNAL ;
    ANTENNADIFFAREA 0.795200 ;
    PORT
      LAYER met2 ;
        RECT 791.290 296.000 791.570 300.000 ;
    END
  END mstream_o[784]
  PIN mstream_o[785]
    DIRECTION OUTPUT TRISTATE ;
    USE SIGNAL ;
    ANTENNADIFFAREA 0.795200 ;
    PORT
      LAYER met2 ;
        RECT 792.210 296.000 792.490 300.000 ;
    END
  END mstream_o[785]
  PIN mstream_o[786]
    DIRECTION OUTPUT TRISTATE ;
    USE SIGNAL ;
    ANTENNADIFFAREA 0.795200 ;
    PORT
      LAYER met2 ;
        RECT 793.130 296.000 793.410 300.000 ;
    END
  END mstream_o[786]
  PIN mstream_o[787]
    DIRECTION OUTPUT TRISTATE ;
    USE SIGNAL ;
    ANTENNADIFFAREA 0.795200 ;
    PORT
      LAYER met2 ;
        RECT 794.050 296.000 794.330 300.000 ;
    END
  END mstream_o[787]
  PIN mstream_o[788]
    DIRECTION OUTPUT TRISTATE ;
    USE SIGNAL ;
    ANTENNADIFFAREA 0.795200 ;
    PORT
      LAYER met2 ;
        RECT 794.970 296.000 795.250 300.000 ;
    END
  END mstream_o[788]
  PIN mstream_o[789]
    DIRECTION OUTPUT TRISTATE ;
    USE SIGNAL ;
    ANTENNADIFFAREA 0.795200 ;
    PORT
      LAYER met2 ;
        RECT 795.890 296.000 796.170 300.000 ;
    END
  END mstream_o[789]
  PIN mstream_o[78]
    DIRECTION OUTPUT TRISTATE ;
    USE SIGNAL ;
    ANTENNADIFFAREA 0.795200 ;
    PORT
      LAYER met2 ;
        RECT 141.770 296.000 142.050 300.000 ;
    END
  END mstream_o[78]
  PIN mstream_o[790]
    DIRECTION OUTPUT TRISTATE ;
    USE SIGNAL ;
    ANTENNADIFFAREA 0.795200 ;
    PORT
      LAYER met2 ;
        RECT 796.810 296.000 797.090 300.000 ;
    END
  END mstream_o[790]
  PIN mstream_o[791]
    DIRECTION OUTPUT TRISTATE ;
    USE SIGNAL ;
    ANTENNADIFFAREA 0.795200 ;
    PORT
      LAYER met2 ;
        RECT 797.730 296.000 798.010 300.000 ;
    END
  END mstream_o[791]
  PIN mstream_o[792]
    DIRECTION OUTPUT TRISTATE ;
    USE SIGNAL ;
    ANTENNADIFFAREA 0.795200 ;
    PORT
      LAYER met2 ;
        RECT 798.650 296.000 798.930 300.000 ;
    END
  END mstream_o[792]
  PIN mstream_o[793]
    DIRECTION OUTPUT TRISTATE ;
    USE SIGNAL ;
    ANTENNADIFFAREA 0.795200 ;
    PORT
      LAYER met2 ;
        RECT 799.570 296.000 799.850 300.000 ;
    END
  END mstream_o[793]
  PIN mstream_o[794]
    DIRECTION OUTPUT TRISTATE ;
    USE SIGNAL ;
    ANTENNADIFFAREA 0.795200 ;
    PORT
      LAYER met2 ;
        RECT 800.490 296.000 800.770 300.000 ;
    END
  END mstream_o[794]
  PIN mstream_o[795]
    DIRECTION OUTPUT TRISTATE ;
    USE SIGNAL ;
    ANTENNADIFFAREA 0.795200 ;
    PORT
      LAYER met2 ;
        RECT 801.410 296.000 801.690 300.000 ;
    END
  END mstream_o[795]
  PIN mstream_o[796]
    DIRECTION OUTPUT TRISTATE ;
    USE SIGNAL ;
    ANTENNADIFFAREA 0.795200 ;
    PORT
      LAYER met2 ;
        RECT 802.330 296.000 802.610 300.000 ;
    END
  END mstream_o[796]
  PIN mstream_o[797]
    DIRECTION OUTPUT TRISTATE ;
    USE SIGNAL ;
    ANTENNADIFFAREA 0.795200 ;
    PORT
      LAYER met2 ;
        RECT 803.250 296.000 803.530 300.000 ;
    END
  END mstream_o[797]
  PIN mstream_o[798]
    DIRECTION OUTPUT TRISTATE ;
    USE SIGNAL ;
    ANTENNADIFFAREA 0.795200 ;
    PORT
      LAYER met2 ;
        RECT 804.170 296.000 804.450 300.000 ;
    END
  END mstream_o[798]
  PIN mstream_o[799]
    DIRECTION OUTPUT TRISTATE ;
    USE SIGNAL ;
    ANTENNADIFFAREA 0.795200 ;
    PORT
      LAYER met2 ;
        RECT 805.090 296.000 805.370 300.000 ;
    END
  END mstream_o[799]
  PIN mstream_o[79]
    DIRECTION OUTPUT TRISTATE ;
    USE SIGNAL ;
    ANTENNADIFFAREA 0.795200 ;
    PORT
      LAYER met2 ;
        RECT 142.690 296.000 142.970 300.000 ;
    END
  END mstream_o[79]
  PIN mstream_o[7]
    DIRECTION OUTPUT TRISTATE ;
    USE SIGNAL ;
    ANTENNADIFFAREA 0.795200 ;
    PORT
      LAYER met2 ;
        RECT 76.450 296.000 76.730 300.000 ;
    END
  END mstream_o[7]
  PIN mstream_o[800]
    DIRECTION OUTPUT TRISTATE ;
    USE SIGNAL ;
    ANTENNADIFFAREA 0.795200 ;
    PORT
      LAYER met2 ;
        RECT 806.010 296.000 806.290 300.000 ;
    END
  END mstream_o[800]
  PIN mstream_o[801]
    DIRECTION OUTPUT TRISTATE ;
    USE SIGNAL ;
    ANTENNADIFFAREA 0.795200 ;
    PORT
      LAYER met2 ;
        RECT 806.930 296.000 807.210 300.000 ;
    END
  END mstream_o[801]
  PIN mstream_o[802]
    DIRECTION OUTPUT TRISTATE ;
    USE SIGNAL ;
    ANTENNADIFFAREA 0.795200 ;
    PORT
      LAYER met2 ;
        RECT 807.850 296.000 808.130 300.000 ;
    END
  END mstream_o[802]
  PIN mstream_o[803]
    DIRECTION OUTPUT TRISTATE ;
    USE SIGNAL ;
    ANTENNADIFFAREA 0.795200 ;
    PORT
      LAYER met2 ;
        RECT 808.770 296.000 809.050 300.000 ;
    END
  END mstream_o[803]
  PIN mstream_o[804]
    DIRECTION OUTPUT TRISTATE ;
    USE SIGNAL ;
    ANTENNADIFFAREA 0.795200 ;
    PORT
      LAYER met2 ;
        RECT 809.690 296.000 809.970 300.000 ;
    END
  END mstream_o[804]
  PIN mstream_o[805]
    DIRECTION OUTPUT TRISTATE ;
    USE SIGNAL ;
    ANTENNADIFFAREA 0.795200 ;
    PORT
      LAYER met2 ;
        RECT 810.610 296.000 810.890 300.000 ;
    END
  END mstream_o[805]
  PIN mstream_o[806]
    DIRECTION OUTPUT TRISTATE ;
    USE SIGNAL ;
    ANTENNADIFFAREA 0.795200 ;
    PORT
      LAYER met2 ;
        RECT 811.530 296.000 811.810 300.000 ;
    END
  END mstream_o[806]
  PIN mstream_o[807]
    DIRECTION OUTPUT TRISTATE ;
    USE SIGNAL ;
    ANTENNADIFFAREA 0.795200 ;
    PORT
      LAYER met2 ;
        RECT 812.450 296.000 812.730 300.000 ;
    END
  END mstream_o[807]
  PIN mstream_o[808]
    DIRECTION OUTPUT TRISTATE ;
    USE SIGNAL ;
    ANTENNADIFFAREA 0.795200 ;
    PORT
      LAYER met2 ;
        RECT 813.370 296.000 813.650 300.000 ;
    END
  END mstream_o[808]
  PIN mstream_o[809]
    DIRECTION OUTPUT TRISTATE ;
    USE SIGNAL ;
    ANTENNADIFFAREA 0.795200 ;
    PORT
      LAYER met2 ;
        RECT 814.290 296.000 814.570 300.000 ;
    END
  END mstream_o[809]
  PIN mstream_o[80]
    DIRECTION OUTPUT TRISTATE ;
    USE SIGNAL ;
    ANTENNADIFFAREA 0.795200 ;
    PORT
      LAYER met2 ;
        RECT 143.610 296.000 143.890 300.000 ;
    END
  END mstream_o[80]
  PIN mstream_o[810]
    DIRECTION OUTPUT TRISTATE ;
    USE SIGNAL ;
    ANTENNADIFFAREA 0.795200 ;
    PORT
      LAYER met2 ;
        RECT 815.210 296.000 815.490 300.000 ;
    END
  END mstream_o[810]
  PIN mstream_o[811]
    DIRECTION OUTPUT TRISTATE ;
    USE SIGNAL ;
    ANTENNADIFFAREA 0.795200 ;
    PORT
      LAYER met2 ;
        RECT 816.130 296.000 816.410 300.000 ;
    END
  END mstream_o[811]
  PIN mstream_o[812]
    DIRECTION OUTPUT TRISTATE ;
    USE SIGNAL ;
    ANTENNADIFFAREA 0.795200 ;
    PORT
      LAYER met2 ;
        RECT 817.050 296.000 817.330 300.000 ;
    END
  END mstream_o[812]
  PIN mstream_o[813]
    DIRECTION OUTPUT TRISTATE ;
    USE SIGNAL ;
    ANTENNADIFFAREA 0.795200 ;
    PORT
      LAYER met2 ;
        RECT 817.970 296.000 818.250 300.000 ;
    END
  END mstream_o[813]
  PIN mstream_o[814]
    DIRECTION OUTPUT TRISTATE ;
    USE SIGNAL ;
    ANTENNADIFFAREA 0.795200 ;
    PORT
      LAYER met2 ;
        RECT 818.890 296.000 819.170 300.000 ;
    END
  END mstream_o[814]
  PIN mstream_o[815]
    DIRECTION OUTPUT TRISTATE ;
    USE SIGNAL ;
    ANTENNADIFFAREA 0.795200 ;
    PORT
      LAYER met2 ;
        RECT 819.810 296.000 820.090 300.000 ;
    END
  END mstream_o[815]
  PIN mstream_o[816]
    DIRECTION OUTPUT TRISTATE ;
    USE SIGNAL ;
    ANTENNADIFFAREA 0.795200 ;
    PORT
      LAYER met2 ;
        RECT 820.730 296.000 821.010 300.000 ;
    END
  END mstream_o[816]
  PIN mstream_o[817]
    DIRECTION OUTPUT TRISTATE ;
    USE SIGNAL ;
    ANTENNADIFFAREA 0.795200 ;
    PORT
      LAYER met2 ;
        RECT 821.650 296.000 821.930 300.000 ;
    END
  END mstream_o[817]
  PIN mstream_o[818]
    DIRECTION OUTPUT TRISTATE ;
    USE SIGNAL ;
    ANTENNADIFFAREA 0.795200 ;
    PORT
      LAYER met2 ;
        RECT 822.570 296.000 822.850 300.000 ;
    END
  END mstream_o[818]
  PIN mstream_o[819]
    DIRECTION OUTPUT TRISTATE ;
    USE SIGNAL ;
    ANTENNADIFFAREA 0.795200 ;
    PORT
      LAYER met2 ;
        RECT 823.490 296.000 823.770 300.000 ;
    END
  END mstream_o[819]
  PIN mstream_o[81]
    DIRECTION OUTPUT TRISTATE ;
    USE SIGNAL ;
    ANTENNADIFFAREA 0.795200 ;
    PORT
      LAYER met2 ;
        RECT 144.530 296.000 144.810 300.000 ;
    END
  END mstream_o[81]
  PIN mstream_o[820]
    DIRECTION OUTPUT TRISTATE ;
    USE SIGNAL ;
    ANTENNADIFFAREA 0.795200 ;
    PORT
      LAYER met2 ;
        RECT 824.410 296.000 824.690 300.000 ;
    END
  END mstream_o[820]
  PIN mstream_o[821]
    DIRECTION OUTPUT TRISTATE ;
    USE SIGNAL ;
    ANTENNADIFFAREA 0.795200 ;
    PORT
      LAYER met2 ;
        RECT 825.330 296.000 825.610 300.000 ;
    END
  END mstream_o[821]
  PIN mstream_o[822]
    DIRECTION OUTPUT TRISTATE ;
    USE SIGNAL ;
    ANTENNADIFFAREA 0.795200 ;
    PORT
      LAYER met2 ;
        RECT 826.250 296.000 826.530 300.000 ;
    END
  END mstream_o[822]
  PIN mstream_o[823]
    DIRECTION OUTPUT TRISTATE ;
    USE SIGNAL ;
    ANTENNADIFFAREA 0.795200 ;
    PORT
      LAYER met2 ;
        RECT 827.170 296.000 827.450 300.000 ;
    END
  END mstream_o[823]
  PIN mstream_o[824]
    DIRECTION OUTPUT TRISTATE ;
    USE SIGNAL ;
    ANTENNADIFFAREA 0.795200 ;
    PORT
      LAYER met2 ;
        RECT 828.090 296.000 828.370 300.000 ;
    END
  END mstream_o[824]
  PIN mstream_o[825]
    DIRECTION OUTPUT TRISTATE ;
    USE SIGNAL ;
    ANTENNADIFFAREA 0.795200 ;
    PORT
      LAYER met2 ;
        RECT 829.010 296.000 829.290 300.000 ;
    END
  END mstream_o[825]
  PIN mstream_o[826]
    DIRECTION OUTPUT TRISTATE ;
    USE SIGNAL ;
    ANTENNADIFFAREA 0.795200 ;
    PORT
      LAYER met2 ;
        RECT 829.930 296.000 830.210 300.000 ;
    END
  END mstream_o[826]
  PIN mstream_o[827]
    DIRECTION OUTPUT TRISTATE ;
    USE SIGNAL ;
    ANTENNADIFFAREA 0.795200 ;
    PORT
      LAYER met2 ;
        RECT 830.850 296.000 831.130 300.000 ;
    END
  END mstream_o[827]
  PIN mstream_o[828]
    DIRECTION OUTPUT TRISTATE ;
    USE SIGNAL ;
    ANTENNADIFFAREA 0.795200 ;
    PORT
      LAYER met2 ;
        RECT 831.770 296.000 832.050 300.000 ;
    END
  END mstream_o[828]
  PIN mstream_o[829]
    DIRECTION OUTPUT TRISTATE ;
    USE SIGNAL ;
    ANTENNADIFFAREA 0.795200 ;
    PORT
      LAYER met2 ;
        RECT 832.690 296.000 832.970 300.000 ;
    END
  END mstream_o[829]
  PIN mstream_o[82]
    DIRECTION OUTPUT TRISTATE ;
    USE SIGNAL ;
    ANTENNADIFFAREA 0.795200 ;
    PORT
      LAYER met2 ;
        RECT 145.450 296.000 145.730 300.000 ;
    END
  END mstream_o[82]
  PIN mstream_o[830]
    DIRECTION OUTPUT TRISTATE ;
    USE SIGNAL ;
    ANTENNADIFFAREA 0.795200 ;
    PORT
      LAYER met2 ;
        RECT 833.610 296.000 833.890 300.000 ;
    END
  END mstream_o[830]
  PIN mstream_o[831]
    DIRECTION OUTPUT TRISTATE ;
    USE SIGNAL ;
    ANTENNADIFFAREA 0.795200 ;
    PORT
      LAYER met2 ;
        RECT 834.530 296.000 834.810 300.000 ;
    END
  END mstream_o[831]
  PIN mstream_o[832]
    DIRECTION OUTPUT TRISTATE ;
    USE SIGNAL ;
    ANTENNADIFFAREA 0.795200 ;
    PORT
      LAYER met2 ;
        RECT 835.450 296.000 835.730 300.000 ;
    END
  END mstream_o[832]
  PIN mstream_o[833]
    DIRECTION OUTPUT TRISTATE ;
    USE SIGNAL ;
    ANTENNADIFFAREA 0.795200 ;
    PORT
      LAYER met2 ;
        RECT 836.370 296.000 836.650 300.000 ;
    END
  END mstream_o[833]
  PIN mstream_o[834]
    DIRECTION OUTPUT TRISTATE ;
    USE SIGNAL ;
    ANTENNADIFFAREA 0.795200 ;
    PORT
      LAYER met2 ;
        RECT 837.290 296.000 837.570 300.000 ;
    END
  END mstream_o[834]
  PIN mstream_o[835]
    DIRECTION OUTPUT TRISTATE ;
    USE SIGNAL ;
    ANTENNADIFFAREA 0.795200 ;
    PORT
      LAYER met2 ;
        RECT 838.210 296.000 838.490 300.000 ;
    END
  END mstream_o[835]
  PIN mstream_o[836]
    DIRECTION OUTPUT TRISTATE ;
    USE SIGNAL ;
    ANTENNADIFFAREA 0.795200 ;
    PORT
      LAYER met2 ;
        RECT 839.130 296.000 839.410 300.000 ;
    END
  END mstream_o[836]
  PIN mstream_o[837]
    DIRECTION OUTPUT TRISTATE ;
    USE SIGNAL ;
    ANTENNADIFFAREA 0.795200 ;
    PORT
      LAYER met2 ;
        RECT 840.050 296.000 840.330 300.000 ;
    END
  END mstream_o[837]
  PIN mstream_o[838]
    DIRECTION OUTPUT TRISTATE ;
    USE SIGNAL ;
    ANTENNADIFFAREA 0.795200 ;
    PORT
      LAYER met2 ;
        RECT 840.970 296.000 841.250 300.000 ;
    END
  END mstream_o[838]
  PIN mstream_o[839]
    DIRECTION OUTPUT TRISTATE ;
    USE SIGNAL ;
    ANTENNADIFFAREA 0.795200 ;
    PORT
      LAYER met2 ;
        RECT 841.890 296.000 842.170 300.000 ;
    END
  END mstream_o[839]
  PIN mstream_o[83]
    DIRECTION OUTPUT TRISTATE ;
    USE SIGNAL ;
    ANTENNADIFFAREA 0.795200 ;
    PORT
      LAYER met2 ;
        RECT 146.370 296.000 146.650 300.000 ;
    END
  END mstream_o[83]
  PIN mstream_o[840]
    DIRECTION OUTPUT TRISTATE ;
    USE SIGNAL ;
    ANTENNADIFFAREA 0.795200 ;
    PORT
      LAYER met2 ;
        RECT 842.810 296.000 843.090 300.000 ;
    END
  END mstream_o[840]
  PIN mstream_o[841]
    DIRECTION OUTPUT TRISTATE ;
    USE SIGNAL ;
    ANTENNADIFFAREA 0.795200 ;
    PORT
      LAYER met2 ;
        RECT 843.730 296.000 844.010 300.000 ;
    END
  END mstream_o[841]
  PIN mstream_o[842]
    DIRECTION OUTPUT TRISTATE ;
    USE SIGNAL ;
    ANTENNADIFFAREA 0.795200 ;
    PORT
      LAYER met2 ;
        RECT 844.650 296.000 844.930 300.000 ;
    END
  END mstream_o[842]
  PIN mstream_o[843]
    DIRECTION OUTPUT TRISTATE ;
    USE SIGNAL ;
    ANTENNADIFFAREA 0.795200 ;
    PORT
      LAYER met2 ;
        RECT 845.570 296.000 845.850 300.000 ;
    END
  END mstream_o[843]
  PIN mstream_o[844]
    DIRECTION OUTPUT TRISTATE ;
    USE SIGNAL ;
    ANTENNADIFFAREA 0.795200 ;
    PORT
      LAYER met2 ;
        RECT 846.490 296.000 846.770 300.000 ;
    END
  END mstream_o[844]
  PIN mstream_o[845]
    DIRECTION OUTPUT TRISTATE ;
    USE SIGNAL ;
    ANTENNADIFFAREA 0.795200 ;
    PORT
      LAYER met2 ;
        RECT 847.410 296.000 847.690 300.000 ;
    END
  END mstream_o[845]
  PIN mstream_o[846]
    DIRECTION OUTPUT TRISTATE ;
    USE SIGNAL ;
    ANTENNADIFFAREA 0.795200 ;
    PORT
      LAYER met2 ;
        RECT 848.330 296.000 848.610 300.000 ;
    END
  END mstream_o[846]
  PIN mstream_o[847]
    DIRECTION OUTPUT TRISTATE ;
    USE SIGNAL ;
    ANTENNADIFFAREA 0.795200 ;
    PORT
      LAYER met2 ;
        RECT 849.250 296.000 849.530 300.000 ;
    END
  END mstream_o[847]
  PIN mstream_o[848]
    DIRECTION OUTPUT TRISTATE ;
    USE SIGNAL ;
    ANTENNADIFFAREA 0.795200 ;
    PORT
      LAYER met2 ;
        RECT 850.170 296.000 850.450 300.000 ;
    END
  END mstream_o[848]
  PIN mstream_o[849]
    DIRECTION OUTPUT TRISTATE ;
    USE SIGNAL ;
    ANTENNADIFFAREA 0.795200 ;
    PORT
      LAYER met2 ;
        RECT 851.090 296.000 851.370 300.000 ;
    END
  END mstream_o[849]
  PIN mstream_o[84]
    DIRECTION OUTPUT TRISTATE ;
    USE SIGNAL ;
    ANTENNADIFFAREA 0.795200 ;
    PORT
      LAYER met2 ;
        RECT 147.290 296.000 147.570 300.000 ;
    END
  END mstream_o[84]
  PIN mstream_o[850]
    DIRECTION OUTPUT TRISTATE ;
    USE SIGNAL ;
    ANTENNADIFFAREA 0.795200 ;
    PORT
      LAYER met2 ;
        RECT 852.010 296.000 852.290 300.000 ;
    END
  END mstream_o[850]
  PIN mstream_o[851]
    DIRECTION OUTPUT TRISTATE ;
    USE SIGNAL ;
    ANTENNADIFFAREA 0.795200 ;
    PORT
      LAYER met2 ;
        RECT 852.930 296.000 853.210 300.000 ;
    END
  END mstream_o[851]
  PIN mstream_o[852]
    DIRECTION OUTPUT TRISTATE ;
    USE SIGNAL ;
    ANTENNADIFFAREA 0.795200 ;
    PORT
      LAYER met2 ;
        RECT 853.850 296.000 854.130 300.000 ;
    END
  END mstream_o[852]
  PIN mstream_o[853]
    DIRECTION OUTPUT TRISTATE ;
    USE SIGNAL ;
    ANTENNADIFFAREA 0.795200 ;
    PORT
      LAYER met2 ;
        RECT 854.770 296.000 855.050 300.000 ;
    END
  END mstream_o[853]
  PIN mstream_o[854]
    DIRECTION OUTPUT TRISTATE ;
    USE SIGNAL ;
    ANTENNADIFFAREA 0.795200 ;
    PORT
      LAYER met2 ;
        RECT 855.690 296.000 855.970 300.000 ;
    END
  END mstream_o[854]
  PIN mstream_o[855]
    DIRECTION OUTPUT TRISTATE ;
    USE SIGNAL ;
    ANTENNADIFFAREA 0.795200 ;
    PORT
      LAYER met2 ;
        RECT 856.610 296.000 856.890 300.000 ;
    END
  END mstream_o[855]
  PIN mstream_o[856]
    DIRECTION OUTPUT TRISTATE ;
    USE SIGNAL ;
    ANTENNADIFFAREA 0.795200 ;
    PORT
      LAYER met2 ;
        RECT 857.530 296.000 857.810 300.000 ;
    END
  END mstream_o[856]
  PIN mstream_o[857]
    DIRECTION OUTPUT TRISTATE ;
    USE SIGNAL ;
    ANTENNADIFFAREA 0.795200 ;
    PORT
      LAYER met2 ;
        RECT 858.450 296.000 858.730 300.000 ;
    END
  END mstream_o[857]
  PIN mstream_o[858]
    DIRECTION OUTPUT TRISTATE ;
    USE SIGNAL ;
    ANTENNADIFFAREA 0.795200 ;
    PORT
      LAYER met2 ;
        RECT 859.370 296.000 859.650 300.000 ;
    END
  END mstream_o[858]
  PIN mstream_o[859]
    DIRECTION OUTPUT TRISTATE ;
    USE SIGNAL ;
    ANTENNADIFFAREA 0.795200 ;
    PORT
      LAYER met2 ;
        RECT 860.290 296.000 860.570 300.000 ;
    END
  END mstream_o[859]
  PIN mstream_o[85]
    DIRECTION OUTPUT TRISTATE ;
    USE SIGNAL ;
    ANTENNADIFFAREA 0.795200 ;
    PORT
      LAYER met2 ;
        RECT 148.210 296.000 148.490 300.000 ;
    END
  END mstream_o[85]
  PIN mstream_o[860]
    DIRECTION OUTPUT TRISTATE ;
    USE SIGNAL ;
    ANTENNADIFFAREA 0.795200 ;
    PORT
      LAYER met2 ;
        RECT 861.210 296.000 861.490 300.000 ;
    END
  END mstream_o[860]
  PIN mstream_o[861]
    DIRECTION OUTPUT TRISTATE ;
    USE SIGNAL ;
    ANTENNADIFFAREA 0.795200 ;
    PORT
      LAYER met2 ;
        RECT 862.130 296.000 862.410 300.000 ;
    END
  END mstream_o[861]
  PIN mstream_o[862]
    DIRECTION OUTPUT TRISTATE ;
    USE SIGNAL ;
    ANTENNADIFFAREA 0.795200 ;
    PORT
      LAYER met2 ;
        RECT 863.050 296.000 863.330 300.000 ;
    END
  END mstream_o[862]
  PIN mstream_o[863]
    DIRECTION OUTPUT TRISTATE ;
    USE SIGNAL ;
    ANTENNADIFFAREA 0.795200 ;
    PORT
      LAYER met2 ;
        RECT 863.970 296.000 864.250 300.000 ;
    END
  END mstream_o[863]
  PIN mstream_o[864]
    DIRECTION OUTPUT TRISTATE ;
    USE SIGNAL ;
    ANTENNADIFFAREA 0.795200 ;
    PORT
      LAYER met2 ;
        RECT 864.890 296.000 865.170 300.000 ;
    END
  END mstream_o[864]
  PIN mstream_o[865]
    DIRECTION OUTPUT TRISTATE ;
    USE SIGNAL ;
    ANTENNADIFFAREA 0.795200 ;
    PORT
      LAYER met2 ;
        RECT 865.810 296.000 866.090 300.000 ;
    END
  END mstream_o[865]
  PIN mstream_o[866]
    DIRECTION OUTPUT TRISTATE ;
    USE SIGNAL ;
    ANTENNADIFFAREA 0.795200 ;
    PORT
      LAYER met2 ;
        RECT 866.730 296.000 867.010 300.000 ;
    END
  END mstream_o[866]
  PIN mstream_o[867]
    DIRECTION OUTPUT TRISTATE ;
    USE SIGNAL ;
    ANTENNADIFFAREA 0.795200 ;
    PORT
      LAYER met2 ;
        RECT 867.650 296.000 867.930 300.000 ;
    END
  END mstream_o[867]
  PIN mstream_o[868]
    DIRECTION OUTPUT TRISTATE ;
    USE SIGNAL ;
    ANTENNADIFFAREA 0.795200 ;
    PORT
      LAYER met2 ;
        RECT 868.570 296.000 868.850 300.000 ;
    END
  END mstream_o[868]
  PIN mstream_o[869]
    DIRECTION OUTPUT TRISTATE ;
    USE SIGNAL ;
    ANTENNADIFFAREA 0.795200 ;
    PORT
      LAYER met2 ;
        RECT 869.490 296.000 869.770 300.000 ;
    END
  END mstream_o[869]
  PIN mstream_o[86]
    DIRECTION OUTPUT TRISTATE ;
    USE SIGNAL ;
    ANTENNADIFFAREA 0.795200 ;
    PORT
      LAYER met2 ;
        RECT 149.130 296.000 149.410 300.000 ;
    END
  END mstream_o[86]
  PIN mstream_o[870]
    DIRECTION OUTPUT TRISTATE ;
    USE SIGNAL ;
    ANTENNADIFFAREA 0.795200 ;
    PORT
      LAYER met2 ;
        RECT 870.410 296.000 870.690 300.000 ;
    END
  END mstream_o[870]
  PIN mstream_o[871]
    DIRECTION OUTPUT TRISTATE ;
    USE SIGNAL ;
    ANTENNADIFFAREA 0.795200 ;
    PORT
      LAYER met2 ;
        RECT 871.330 296.000 871.610 300.000 ;
    END
  END mstream_o[871]
  PIN mstream_o[872]
    DIRECTION OUTPUT TRISTATE ;
    USE SIGNAL ;
    ANTENNADIFFAREA 0.795200 ;
    PORT
      LAYER met2 ;
        RECT 872.250 296.000 872.530 300.000 ;
    END
  END mstream_o[872]
  PIN mstream_o[873]
    DIRECTION OUTPUT TRISTATE ;
    USE SIGNAL ;
    ANTENNADIFFAREA 0.795200 ;
    PORT
      LAYER met2 ;
        RECT 873.170 296.000 873.450 300.000 ;
    END
  END mstream_o[873]
  PIN mstream_o[874]
    DIRECTION OUTPUT TRISTATE ;
    USE SIGNAL ;
    ANTENNADIFFAREA 0.795200 ;
    PORT
      LAYER met2 ;
        RECT 874.090 296.000 874.370 300.000 ;
    END
  END mstream_o[874]
  PIN mstream_o[875]
    DIRECTION OUTPUT TRISTATE ;
    USE SIGNAL ;
    ANTENNADIFFAREA 0.795200 ;
    PORT
      LAYER met2 ;
        RECT 875.010 296.000 875.290 300.000 ;
    END
  END mstream_o[875]
  PIN mstream_o[876]
    DIRECTION OUTPUT TRISTATE ;
    USE SIGNAL ;
    ANTENNADIFFAREA 0.795200 ;
    PORT
      LAYER met2 ;
        RECT 875.930 296.000 876.210 300.000 ;
    END
  END mstream_o[876]
  PIN mstream_o[877]
    DIRECTION OUTPUT TRISTATE ;
    USE SIGNAL ;
    ANTENNADIFFAREA 0.795200 ;
    PORT
      LAYER met2 ;
        RECT 876.850 296.000 877.130 300.000 ;
    END
  END mstream_o[877]
  PIN mstream_o[878]
    DIRECTION OUTPUT TRISTATE ;
    USE SIGNAL ;
    ANTENNADIFFAREA 0.795200 ;
    PORT
      LAYER met2 ;
        RECT 877.770 296.000 878.050 300.000 ;
    END
  END mstream_o[878]
  PIN mstream_o[879]
    DIRECTION OUTPUT TRISTATE ;
    USE SIGNAL ;
    ANTENNADIFFAREA 0.795200 ;
    PORT
      LAYER met2 ;
        RECT 878.690 296.000 878.970 300.000 ;
    END
  END mstream_o[879]
  PIN mstream_o[87]
    DIRECTION OUTPUT TRISTATE ;
    USE SIGNAL ;
    ANTENNADIFFAREA 0.795200 ;
    PORT
      LAYER met2 ;
        RECT 150.050 296.000 150.330 300.000 ;
    END
  END mstream_o[87]
  PIN mstream_o[880]
    DIRECTION OUTPUT TRISTATE ;
    USE SIGNAL ;
    ANTENNADIFFAREA 0.795200 ;
    PORT
      LAYER met2 ;
        RECT 879.610 296.000 879.890 300.000 ;
    END
  END mstream_o[880]
  PIN mstream_o[881]
    DIRECTION OUTPUT TRISTATE ;
    USE SIGNAL ;
    ANTENNADIFFAREA 0.795200 ;
    PORT
      LAYER met2 ;
        RECT 880.530 296.000 880.810 300.000 ;
    END
  END mstream_o[881]
  PIN mstream_o[882]
    DIRECTION OUTPUT TRISTATE ;
    USE SIGNAL ;
    ANTENNADIFFAREA 0.795200 ;
    PORT
      LAYER met2 ;
        RECT 881.450 296.000 881.730 300.000 ;
    END
  END mstream_o[882]
  PIN mstream_o[883]
    DIRECTION OUTPUT TRISTATE ;
    USE SIGNAL ;
    ANTENNADIFFAREA 0.795200 ;
    PORT
      LAYER met2 ;
        RECT 882.370 296.000 882.650 300.000 ;
    END
  END mstream_o[883]
  PIN mstream_o[884]
    DIRECTION OUTPUT TRISTATE ;
    USE SIGNAL ;
    ANTENNADIFFAREA 0.795200 ;
    PORT
      LAYER met2 ;
        RECT 883.290 296.000 883.570 300.000 ;
    END
  END mstream_o[884]
  PIN mstream_o[885]
    DIRECTION OUTPUT TRISTATE ;
    USE SIGNAL ;
    ANTENNADIFFAREA 0.795200 ;
    PORT
      LAYER met2 ;
        RECT 884.210 296.000 884.490 300.000 ;
    END
  END mstream_o[885]
  PIN mstream_o[886]
    DIRECTION OUTPUT TRISTATE ;
    USE SIGNAL ;
    ANTENNADIFFAREA 0.795200 ;
    PORT
      LAYER met2 ;
        RECT 885.130 296.000 885.410 300.000 ;
    END
  END mstream_o[886]
  PIN mstream_o[887]
    DIRECTION OUTPUT TRISTATE ;
    USE SIGNAL ;
    ANTENNADIFFAREA 0.795200 ;
    PORT
      LAYER met2 ;
        RECT 886.050 296.000 886.330 300.000 ;
    END
  END mstream_o[887]
  PIN mstream_o[888]
    DIRECTION OUTPUT TRISTATE ;
    USE SIGNAL ;
    ANTENNADIFFAREA 0.795200 ;
    PORT
      LAYER met2 ;
        RECT 886.970 296.000 887.250 300.000 ;
    END
  END mstream_o[888]
  PIN mstream_o[889]
    DIRECTION OUTPUT TRISTATE ;
    USE SIGNAL ;
    ANTENNADIFFAREA 0.795200 ;
    PORT
      LAYER met2 ;
        RECT 887.890 296.000 888.170 300.000 ;
    END
  END mstream_o[889]
  PIN mstream_o[88]
    DIRECTION OUTPUT TRISTATE ;
    USE SIGNAL ;
    ANTENNADIFFAREA 0.795200 ;
    PORT
      LAYER met2 ;
        RECT 150.970 296.000 151.250 300.000 ;
    END
  END mstream_o[88]
  PIN mstream_o[890]
    DIRECTION OUTPUT TRISTATE ;
    USE SIGNAL ;
    ANTENNADIFFAREA 0.795200 ;
    PORT
      LAYER met2 ;
        RECT 888.810 296.000 889.090 300.000 ;
    END
  END mstream_o[890]
  PIN mstream_o[891]
    DIRECTION OUTPUT TRISTATE ;
    USE SIGNAL ;
    ANTENNADIFFAREA 0.795200 ;
    PORT
      LAYER met2 ;
        RECT 889.730 296.000 890.010 300.000 ;
    END
  END mstream_o[891]
  PIN mstream_o[892]
    DIRECTION OUTPUT TRISTATE ;
    USE SIGNAL ;
    ANTENNADIFFAREA 0.795200 ;
    PORT
      LAYER met2 ;
        RECT 890.650 296.000 890.930 300.000 ;
    END
  END mstream_o[892]
  PIN mstream_o[893]
    DIRECTION OUTPUT TRISTATE ;
    USE SIGNAL ;
    ANTENNADIFFAREA 0.795200 ;
    PORT
      LAYER met2 ;
        RECT 891.570 296.000 891.850 300.000 ;
    END
  END mstream_o[893]
  PIN mstream_o[894]
    DIRECTION OUTPUT TRISTATE ;
    USE SIGNAL ;
    ANTENNADIFFAREA 0.795200 ;
    PORT
      LAYER met2 ;
        RECT 892.490 296.000 892.770 300.000 ;
    END
  END mstream_o[894]
  PIN mstream_o[895]
    DIRECTION OUTPUT TRISTATE ;
    USE SIGNAL ;
    ANTENNADIFFAREA 0.795200 ;
    PORT
      LAYER met2 ;
        RECT 893.410 296.000 893.690 300.000 ;
    END
  END mstream_o[895]
  PIN mstream_o[896]
    DIRECTION OUTPUT TRISTATE ;
    USE SIGNAL ;
    ANTENNADIFFAREA 0.795200 ;
    PORT
      LAYER met2 ;
        RECT 894.330 296.000 894.610 300.000 ;
    END
  END mstream_o[896]
  PIN mstream_o[897]
    DIRECTION OUTPUT TRISTATE ;
    USE SIGNAL ;
    ANTENNADIFFAREA 0.795200 ;
    PORT
      LAYER met2 ;
        RECT 895.250 296.000 895.530 300.000 ;
    END
  END mstream_o[897]
  PIN mstream_o[898]
    DIRECTION OUTPUT TRISTATE ;
    USE SIGNAL ;
    ANTENNADIFFAREA 0.795200 ;
    PORT
      LAYER met2 ;
        RECT 896.170 296.000 896.450 300.000 ;
    END
  END mstream_o[898]
  PIN mstream_o[899]
    DIRECTION OUTPUT TRISTATE ;
    USE SIGNAL ;
    ANTENNADIFFAREA 0.795200 ;
    PORT
      LAYER met2 ;
        RECT 897.090 296.000 897.370 300.000 ;
    END
  END mstream_o[899]
  PIN mstream_o[89]
    DIRECTION OUTPUT TRISTATE ;
    USE SIGNAL ;
    ANTENNADIFFAREA 0.795200 ;
    PORT
      LAYER met2 ;
        RECT 151.890 296.000 152.170 300.000 ;
    END
  END mstream_o[89]
  PIN mstream_o[8]
    DIRECTION OUTPUT TRISTATE ;
    USE SIGNAL ;
    ANTENNADIFFAREA 0.795200 ;
    PORT
      LAYER met2 ;
        RECT 77.370 296.000 77.650 300.000 ;
    END
  END mstream_o[8]
  PIN mstream_o[900]
    DIRECTION OUTPUT TRISTATE ;
    USE SIGNAL ;
    ANTENNADIFFAREA 0.795200 ;
    PORT
      LAYER met2 ;
        RECT 898.010 296.000 898.290 300.000 ;
    END
  END mstream_o[900]
  PIN mstream_o[901]
    DIRECTION OUTPUT TRISTATE ;
    USE SIGNAL ;
    ANTENNADIFFAREA 0.795200 ;
    PORT
      LAYER met2 ;
        RECT 898.930 296.000 899.210 300.000 ;
    END
  END mstream_o[901]
  PIN mstream_o[902]
    DIRECTION OUTPUT TRISTATE ;
    USE SIGNAL ;
    ANTENNADIFFAREA 0.795200 ;
    PORT
      LAYER met2 ;
        RECT 899.850 296.000 900.130 300.000 ;
    END
  END mstream_o[902]
  PIN mstream_o[903]
    DIRECTION OUTPUT TRISTATE ;
    USE SIGNAL ;
    ANTENNADIFFAREA 0.795200 ;
    PORT
      LAYER met2 ;
        RECT 900.770 296.000 901.050 300.000 ;
    END
  END mstream_o[903]
  PIN mstream_o[904]
    DIRECTION OUTPUT TRISTATE ;
    USE SIGNAL ;
    ANTENNADIFFAREA 0.795200 ;
    PORT
      LAYER met2 ;
        RECT 901.690 296.000 901.970 300.000 ;
    END
  END mstream_o[904]
  PIN mstream_o[905]
    DIRECTION OUTPUT TRISTATE ;
    USE SIGNAL ;
    ANTENNADIFFAREA 0.795200 ;
    PORT
      LAYER met2 ;
        RECT 902.610 296.000 902.890 300.000 ;
    END
  END mstream_o[905]
  PIN mstream_o[906]
    DIRECTION OUTPUT TRISTATE ;
    USE SIGNAL ;
    ANTENNADIFFAREA 0.795200 ;
    PORT
      LAYER met2 ;
        RECT 903.530 296.000 903.810 300.000 ;
    END
  END mstream_o[906]
  PIN mstream_o[907]
    DIRECTION OUTPUT TRISTATE ;
    USE SIGNAL ;
    ANTENNADIFFAREA 0.795200 ;
    PORT
      LAYER met2 ;
        RECT 904.450 296.000 904.730 300.000 ;
    END
  END mstream_o[907]
  PIN mstream_o[908]
    DIRECTION OUTPUT TRISTATE ;
    USE SIGNAL ;
    ANTENNADIFFAREA 0.795200 ;
    PORT
      LAYER met2 ;
        RECT 905.370 296.000 905.650 300.000 ;
    END
  END mstream_o[908]
  PIN mstream_o[909]
    DIRECTION OUTPUT TRISTATE ;
    USE SIGNAL ;
    ANTENNADIFFAREA 0.795200 ;
    PORT
      LAYER met2 ;
        RECT 906.290 296.000 906.570 300.000 ;
    END
  END mstream_o[909]
  PIN mstream_o[90]
    DIRECTION OUTPUT TRISTATE ;
    USE SIGNAL ;
    ANTENNADIFFAREA 0.795200 ;
    PORT
      LAYER met2 ;
        RECT 152.810 296.000 153.090 300.000 ;
    END
  END mstream_o[90]
  PIN mstream_o[910]
    DIRECTION OUTPUT TRISTATE ;
    USE SIGNAL ;
    ANTENNADIFFAREA 0.795200 ;
    PORT
      LAYER met2 ;
        RECT 907.210 296.000 907.490 300.000 ;
    END
  END mstream_o[910]
  PIN mstream_o[911]
    DIRECTION OUTPUT TRISTATE ;
    USE SIGNAL ;
    ANTENNADIFFAREA 0.795200 ;
    PORT
      LAYER met2 ;
        RECT 908.130 296.000 908.410 300.000 ;
    END
  END mstream_o[911]
  PIN mstream_o[912]
    DIRECTION OUTPUT TRISTATE ;
    USE SIGNAL ;
    ANTENNADIFFAREA 0.795200 ;
    PORT
      LAYER met2 ;
        RECT 909.050 296.000 909.330 300.000 ;
    END
  END mstream_o[912]
  PIN mstream_o[913]
    DIRECTION OUTPUT TRISTATE ;
    USE SIGNAL ;
    ANTENNADIFFAREA 0.795200 ;
    PORT
      LAYER met2 ;
        RECT 909.970 296.000 910.250 300.000 ;
    END
  END mstream_o[913]
  PIN mstream_o[914]
    DIRECTION OUTPUT TRISTATE ;
    USE SIGNAL ;
    ANTENNADIFFAREA 0.795200 ;
    PORT
      LAYER met2 ;
        RECT 910.890 296.000 911.170 300.000 ;
    END
  END mstream_o[914]
  PIN mstream_o[915]
    DIRECTION OUTPUT TRISTATE ;
    USE SIGNAL ;
    ANTENNADIFFAREA 0.795200 ;
    PORT
      LAYER met2 ;
        RECT 911.810 296.000 912.090 300.000 ;
    END
  END mstream_o[915]
  PIN mstream_o[916]
    DIRECTION OUTPUT TRISTATE ;
    USE SIGNAL ;
    ANTENNADIFFAREA 0.795200 ;
    PORT
      LAYER met2 ;
        RECT 912.730 296.000 913.010 300.000 ;
    END
  END mstream_o[916]
  PIN mstream_o[917]
    DIRECTION OUTPUT TRISTATE ;
    USE SIGNAL ;
    ANTENNADIFFAREA 0.795200 ;
    PORT
      LAYER met2 ;
        RECT 913.650 296.000 913.930 300.000 ;
    END
  END mstream_o[917]
  PIN mstream_o[918]
    DIRECTION OUTPUT TRISTATE ;
    USE SIGNAL ;
    ANTENNADIFFAREA 0.795200 ;
    PORT
      LAYER met2 ;
        RECT 914.570 296.000 914.850 300.000 ;
    END
  END mstream_o[918]
  PIN mstream_o[919]
    DIRECTION OUTPUT TRISTATE ;
    USE SIGNAL ;
    ANTENNADIFFAREA 0.795200 ;
    PORT
      LAYER met2 ;
        RECT 915.490 296.000 915.770 300.000 ;
    END
  END mstream_o[919]
  PIN mstream_o[91]
    DIRECTION OUTPUT TRISTATE ;
    USE SIGNAL ;
    ANTENNADIFFAREA 0.795200 ;
    PORT
      LAYER met2 ;
        RECT 153.730 296.000 154.010 300.000 ;
    END
  END mstream_o[91]
  PIN mstream_o[920]
    DIRECTION OUTPUT TRISTATE ;
    USE SIGNAL ;
    ANTENNADIFFAREA 0.795200 ;
    PORT
      LAYER met2 ;
        RECT 916.410 296.000 916.690 300.000 ;
    END
  END mstream_o[920]
  PIN mstream_o[921]
    DIRECTION OUTPUT TRISTATE ;
    USE SIGNAL ;
    ANTENNADIFFAREA 0.795200 ;
    PORT
      LAYER met2 ;
        RECT 917.330 296.000 917.610 300.000 ;
    END
  END mstream_o[921]
  PIN mstream_o[922]
    DIRECTION OUTPUT TRISTATE ;
    USE SIGNAL ;
    ANTENNADIFFAREA 0.795200 ;
    PORT
      LAYER met2 ;
        RECT 918.250 296.000 918.530 300.000 ;
    END
  END mstream_o[922]
  PIN mstream_o[923]
    DIRECTION OUTPUT TRISTATE ;
    USE SIGNAL ;
    ANTENNADIFFAREA 0.795200 ;
    PORT
      LAYER met2 ;
        RECT 919.170 296.000 919.450 300.000 ;
    END
  END mstream_o[923]
  PIN mstream_o[924]
    DIRECTION OUTPUT TRISTATE ;
    USE SIGNAL ;
    ANTENNADIFFAREA 0.795200 ;
    PORT
      LAYER met2 ;
        RECT 920.090 296.000 920.370 300.000 ;
    END
  END mstream_o[924]
  PIN mstream_o[925]
    DIRECTION OUTPUT TRISTATE ;
    USE SIGNAL ;
    ANTENNADIFFAREA 0.795200 ;
    PORT
      LAYER met2 ;
        RECT 921.010 296.000 921.290 300.000 ;
    END
  END mstream_o[925]
  PIN mstream_o[926]
    DIRECTION OUTPUT TRISTATE ;
    USE SIGNAL ;
    ANTENNADIFFAREA 0.795200 ;
    PORT
      LAYER met2 ;
        RECT 921.930 296.000 922.210 300.000 ;
    END
  END mstream_o[926]
  PIN mstream_o[927]
    DIRECTION OUTPUT TRISTATE ;
    USE SIGNAL ;
    ANTENNADIFFAREA 0.795200 ;
    PORT
      LAYER met2 ;
        RECT 922.850 296.000 923.130 300.000 ;
    END
  END mstream_o[927]
  PIN mstream_o[928]
    DIRECTION OUTPUT TRISTATE ;
    USE SIGNAL ;
    ANTENNADIFFAREA 0.795200 ;
    PORT
      LAYER met2 ;
        RECT 923.770 296.000 924.050 300.000 ;
    END
  END mstream_o[928]
  PIN mstream_o[929]
    DIRECTION OUTPUT TRISTATE ;
    USE SIGNAL ;
    ANTENNADIFFAREA 0.795200 ;
    PORT
      LAYER met2 ;
        RECT 924.690 296.000 924.970 300.000 ;
    END
  END mstream_o[929]
  PIN mstream_o[92]
    DIRECTION OUTPUT TRISTATE ;
    USE SIGNAL ;
    ANTENNADIFFAREA 0.795200 ;
    PORT
      LAYER met2 ;
        RECT 154.650 296.000 154.930 300.000 ;
    END
  END mstream_o[92]
  PIN mstream_o[930]
    DIRECTION OUTPUT TRISTATE ;
    USE SIGNAL ;
    ANTENNADIFFAREA 0.795200 ;
    PORT
      LAYER met2 ;
        RECT 925.610 296.000 925.890 300.000 ;
    END
  END mstream_o[930]
  PIN mstream_o[931]
    DIRECTION OUTPUT TRISTATE ;
    USE SIGNAL ;
    ANTENNADIFFAREA 0.795200 ;
    PORT
      LAYER met2 ;
        RECT 926.530 296.000 926.810 300.000 ;
    END
  END mstream_o[931]
  PIN mstream_o[932]
    DIRECTION OUTPUT TRISTATE ;
    USE SIGNAL ;
    ANTENNADIFFAREA 0.795200 ;
    PORT
      LAYER met2 ;
        RECT 927.450 296.000 927.730 300.000 ;
    END
  END mstream_o[932]
  PIN mstream_o[933]
    DIRECTION OUTPUT TRISTATE ;
    USE SIGNAL ;
    ANTENNADIFFAREA 0.795200 ;
    PORT
      LAYER met2 ;
        RECT 928.370 296.000 928.650 300.000 ;
    END
  END mstream_o[933]
  PIN mstream_o[934]
    DIRECTION OUTPUT TRISTATE ;
    USE SIGNAL ;
    ANTENNADIFFAREA 0.795200 ;
    PORT
      LAYER met2 ;
        RECT 929.290 296.000 929.570 300.000 ;
    END
  END mstream_o[934]
  PIN mstream_o[935]
    DIRECTION OUTPUT TRISTATE ;
    USE SIGNAL ;
    ANTENNADIFFAREA 0.795200 ;
    PORT
      LAYER met2 ;
        RECT 930.210 296.000 930.490 300.000 ;
    END
  END mstream_o[935]
  PIN mstream_o[936]
    DIRECTION OUTPUT TRISTATE ;
    USE SIGNAL ;
    ANTENNADIFFAREA 0.795200 ;
    PORT
      LAYER met2 ;
        RECT 931.130 296.000 931.410 300.000 ;
    END
  END mstream_o[936]
  PIN mstream_o[937]
    DIRECTION OUTPUT TRISTATE ;
    USE SIGNAL ;
    ANTENNADIFFAREA 0.795200 ;
    PORT
      LAYER met2 ;
        RECT 932.050 296.000 932.330 300.000 ;
    END
  END mstream_o[937]
  PIN mstream_o[938]
    DIRECTION OUTPUT TRISTATE ;
    USE SIGNAL ;
    ANTENNADIFFAREA 0.795200 ;
    PORT
      LAYER met2 ;
        RECT 932.970 296.000 933.250 300.000 ;
    END
  END mstream_o[938]
  PIN mstream_o[939]
    DIRECTION OUTPUT TRISTATE ;
    USE SIGNAL ;
    ANTENNADIFFAREA 0.795200 ;
    PORT
      LAYER met2 ;
        RECT 933.890 296.000 934.170 300.000 ;
    END
  END mstream_o[939]
  PIN mstream_o[93]
    DIRECTION OUTPUT TRISTATE ;
    USE SIGNAL ;
    ANTENNADIFFAREA 0.795200 ;
    PORT
      LAYER met2 ;
        RECT 155.570 296.000 155.850 300.000 ;
    END
  END mstream_o[93]
  PIN mstream_o[940]
    DIRECTION OUTPUT TRISTATE ;
    USE SIGNAL ;
    ANTENNADIFFAREA 0.795200 ;
    PORT
      LAYER met2 ;
        RECT 934.810 296.000 935.090 300.000 ;
    END
  END mstream_o[940]
  PIN mstream_o[941]
    DIRECTION OUTPUT TRISTATE ;
    USE SIGNAL ;
    ANTENNADIFFAREA 0.795200 ;
    PORT
      LAYER met2 ;
        RECT 935.730 296.000 936.010 300.000 ;
    END
  END mstream_o[941]
  PIN mstream_o[942]
    DIRECTION OUTPUT TRISTATE ;
    USE SIGNAL ;
    ANTENNADIFFAREA 0.795200 ;
    PORT
      LAYER met2 ;
        RECT 936.650 296.000 936.930 300.000 ;
    END
  END mstream_o[942]
  PIN mstream_o[943]
    DIRECTION OUTPUT TRISTATE ;
    USE SIGNAL ;
    ANTENNADIFFAREA 0.795200 ;
    PORT
      LAYER met2 ;
        RECT 937.570 296.000 937.850 300.000 ;
    END
  END mstream_o[943]
  PIN mstream_o[944]
    DIRECTION OUTPUT TRISTATE ;
    USE SIGNAL ;
    ANTENNADIFFAREA 0.795200 ;
    PORT
      LAYER met2 ;
        RECT 938.490 296.000 938.770 300.000 ;
    END
  END mstream_o[944]
  PIN mstream_o[945]
    DIRECTION OUTPUT TRISTATE ;
    USE SIGNAL ;
    ANTENNADIFFAREA 0.795200 ;
    PORT
      LAYER met2 ;
        RECT 939.410 296.000 939.690 300.000 ;
    END
  END mstream_o[945]
  PIN mstream_o[946]
    DIRECTION OUTPUT TRISTATE ;
    USE SIGNAL ;
    ANTENNADIFFAREA 0.795200 ;
    PORT
      LAYER met2 ;
        RECT 940.330 296.000 940.610 300.000 ;
    END
  END mstream_o[946]
  PIN mstream_o[947]
    DIRECTION OUTPUT TRISTATE ;
    USE SIGNAL ;
    ANTENNADIFFAREA 0.795200 ;
    PORT
      LAYER met2 ;
        RECT 941.250 296.000 941.530 300.000 ;
    END
  END mstream_o[947]
  PIN mstream_o[948]
    DIRECTION OUTPUT TRISTATE ;
    USE SIGNAL ;
    ANTENNADIFFAREA 0.795200 ;
    PORT
      LAYER met2 ;
        RECT 942.170 296.000 942.450 300.000 ;
    END
  END mstream_o[948]
  PIN mstream_o[949]
    DIRECTION OUTPUT TRISTATE ;
    USE SIGNAL ;
    ANTENNADIFFAREA 0.795200 ;
    PORT
      LAYER met2 ;
        RECT 943.090 296.000 943.370 300.000 ;
    END
  END mstream_o[949]
  PIN mstream_o[94]
    DIRECTION OUTPUT TRISTATE ;
    USE SIGNAL ;
    ANTENNADIFFAREA 0.795200 ;
    PORT
      LAYER met2 ;
        RECT 156.490 296.000 156.770 300.000 ;
    END
  END mstream_o[94]
  PIN mstream_o[950]
    DIRECTION OUTPUT TRISTATE ;
    USE SIGNAL ;
    ANTENNADIFFAREA 0.795200 ;
    PORT
      LAYER met2 ;
        RECT 944.010 296.000 944.290 300.000 ;
    END
  END mstream_o[950]
  PIN mstream_o[951]
    DIRECTION OUTPUT TRISTATE ;
    USE SIGNAL ;
    ANTENNADIFFAREA 0.795200 ;
    PORT
      LAYER met2 ;
        RECT 944.930 296.000 945.210 300.000 ;
    END
  END mstream_o[951]
  PIN mstream_o[952]
    DIRECTION OUTPUT TRISTATE ;
    USE SIGNAL ;
    ANTENNADIFFAREA 0.795200 ;
    PORT
      LAYER met2 ;
        RECT 945.850 296.000 946.130 300.000 ;
    END
  END mstream_o[952]
  PIN mstream_o[953]
    DIRECTION OUTPUT TRISTATE ;
    USE SIGNAL ;
    ANTENNADIFFAREA 0.795200 ;
    PORT
      LAYER met2 ;
        RECT 946.770 296.000 947.050 300.000 ;
    END
  END mstream_o[953]
  PIN mstream_o[954]
    DIRECTION OUTPUT TRISTATE ;
    USE SIGNAL ;
    ANTENNADIFFAREA 0.795200 ;
    PORT
      LAYER met2 ;
        RECT 947.690 296.000 947.970 300.000 ;
    END
  END mstream_o[954]
  PIN mstream_o[955]
    DIRECTION OUTPUT TRISTATE ;
    USE SIGNAL ;
    ANTENNADIFFAREA 0.795200 ;
    PORT
      LAYER met2 ;
        RECT 948.610 296.000 948.890 300.000 ;
    END
  END mstream_o[955]
  PIN mstream_o[956]
    DIRECTION OUTPUT TRISTATE ;
    USE SIGNAL ;
    ANTENNADIFFAREA 0.795200 ;
    PORT
      LAYER met2 ;
        RECT 949.530 296.000 949.810 300.000 ;
    END
  END mstream_o[956]
  PIN mstream_o[957]
    DIRECTION OUTPUT TRISTATE ;
    USE SIGNAL ;
    ANTENNADIFFAREA 0.795200 ;
    PORT
      LAYER met2 ;
        RECT 950.450 296.000 950.730 300.000 ;
    END
  END mstream_o[957]
  PIN mstream_o[958]
    DIRECTION OUTPUT TRISTATE ;
    USE SIGNAL ;
    ANTENNADIFFAREA 0.795200 ;
    PORT
      LAYER met2 ;
        RECT 951.370 296.000 951.650 300.000 ;
    END
  END mstream_o[958]
  PIN mstream_o[959]
    DIRECTION OUTPUT TRISTATE ;
    USE SIGNAL ;
    ANTENNADIFFAREA 0.795200 ;
    PORT
      LAYER met2 ;
        RECT 952.290 296.000 952.570 300.000 ;
    END
  END mstream_o[959]
  PIN mstream_o[95]
    DIRECTION OUTPUT TRISTATE ;
    USE SIGNAL ;
    ANTENNADIFFAREA 0.795200 ;
    PORT
      LAYER met2 ;
        RECT 157.410 296.000 157.690 300.000 ;
    END
  END mstream_o[95]
  PIN mstream_o[960]
    DIRECTION OUTPUT TRISTATE ;
    USE SIGNAL ;
    ANTENNADIFFAREA 0.795200 ;
    PORT
      LAYER met2 ;
        RECT 953.210 296.000 953.490 300.000 ;
    END
  END mstream_o[960]
  PIN mstream_o[961]
    DIRECTION OUTPUT TRISTATE ;
    USE SIGNAL ;
    ANTENNADIFFAREA 0.795200 ;
    PORT
      LAYER met2 ;
        RECT 954.130 296.000 954.410 300.000 ;
    END
  END mstream_o[961]
  PIN mstream_o[962]
    DIRECTION OUTPUT TRISTATE ;
    USE SIGNAL ;
    ANTENNADIFFAREA 0.795200 ;
    PORT
      LAYER met2 ;
        RECT 955.050 296.000 955.330 300.000 ;
    END
  END mstream_o[962]
  PIN mstream_o[963]
    DIRECTION OUTPUT TRISTATE ;
    USE SIGNAL ;
    ANTENNADIFFAREA 0.795200 ;
    PORT
      LAYER met2 ;
        RECT 955.970 296.000 956.250 300.000 ;
    END
  END mstream_o[963]
  PIN mstream_o[964]
    DIRECTION OUTPUT TRISTATE ;
    USE SIGNAL ;
    ANTENNADIFFAREA 0.795200 ;
    PORT
      LAYER met2 ;
        RECT 956.890 296.000 957.170 300.000 ;
    END
  END mstream_o[964]
  PIN mstream_o[965]
    DIRECTION OUTPUT TRISTATE ;
    USE SIGNAL ;
    ANTENNADIFFAREA 0.795200 ;
    PORT
      LAYER met2 ;
        RECT 957.810 296.000 958.090 300.000 ;
    END
  END mstream_o[965]
  PIN mstream_o[966]
    DIRECTION OUTPUT TRISTATE ;
    USE SIGNAL ;
    ANTENNADIFFAREA 0.795200 ;
    PORT
      LAYER met2 ;
        RECT 958.730 296.000 959.010 300.000 ;
    END
  END mstream_o[966]
  PIN mstream_o[967]
    DIRECTION OUTPUT TRISTATE ;
    USE SIGNAL ;
    ANTENNADIFFAREA 0.795200 ;
    PORT
      LAYER met2 ;
        RECT 959.650 296.000 959.930 300.000 ;
    END
  END mstream_o[967]
  PIN mstream_o[968]
    DIRECTION OUTPUT TRISTATE ;
    USE SIGNAL ;
    ANTENNADIFFAREA 0.795200 ;
    PORT
      LAYER met2 ;
        RECT 960.570 296.000 960.850 300.000 ;
    END
  END mstream_o[968]
  PIN mstream_o[969]
    DIRECTION OUTPUT TRISTATE ;
    USE SIGNAL ;
    ANTENNADIFFAREA 0.795200 ;
    PORT
      LAYER met2 ;
        RECT 961.490 296.000 961.770 300.000 ;
    END
  END mstream_o[969]
  PIN mstream_o[96]
    DIRECTION OUTPUT TRISTATE ;
    USE SIGNAL ;
    ANTENNADIFFAREA 0.795200 ;
    PORT
      LAYER met2 ;
        RECT 158.330 296.000 158.610 300.000 ;
    END
  END mstream_o[96]
  PIN mstream_o[970]
    DIRECTION OUTPUT TRISTATE ;
    USE SIGNAL ;
    ANTENNADIFFAREA 0.795200 ;
    PORT
      LAYER met2 ;
        RECT 962.410 296.000 962.690 300.000 ;
    END
  END mstream_o[970]
  PIN mstream_o[971]
    DIRECTION OUTPUT TRISTATE ;
    USE SIGNAL ;
    ANTENNADIFFAREA 0.795200 ;
    PORT
      LAYER met2 ;
        RECT 963.330 296.000 963.610 300.000 ;
    END
  END mstream_o[971]
  PIN mstream_o[972]
    DIRECTION OUTPUT TRISTATE ;
    USE SIGNAL ;
    ANTENNADIFFAREA 0.795200 ;
    PORT
      LAYER met2 ;
        RECT 964.250 296.000 964.530 300.000 ;
    END
  END mstream_o[972]
  PIN mstream_o[973]
    DIRECTION OUTPUT TRISTATE ;
    USE SIGNAL ;
    ANTENNADIFFAREA 0.795200 ;
    PORT
      LAYER met2 ;
        RECT 965.170 296.000 965.450 300.000 ;
    END
  END mstream_o[973]
  PIN mstream_o[974]
    DIRECTION OUTPUT TRISTATE ;
    USE SIGNAL ;
    ANTENNADIFFAREA 0.795200 ;
    PORT
      LAYER met2 ;
        RECT 966.090 296.000 966.370 300.000 ;
    END
  END mstream_o[974]
  PIN mstream_o[975]
    DIRECTION OUTPUT TRISTATE ;
    USE SIGNAL ;
    ANTENNADIFFAREA 0.795200 ;
    PORT
      LAYER met2 ;
        RECT 967.010 296.000 967.290 300.000 ;
    END
  END mstream_o[975]
  PIN mstream_o[976]
    DIRECTION OUTPUT TRISTATE ;
    USE SIGNAL ;
    ANTENNADIFFAREA 0.795200 ;
    PORT
      LAYER met2 ;
        RECT 967.930 296.000 968.210 300.000 ;
    END
  END mstream_o[976]
  PIN mstream_o[977]
    DIRECTION OUTPUT TRISTATE ;
    USE SIGNAL ;
    ANTENNADIFFAREA 0.795200 ;
    PORT
      LAYER met2 ;
        RECT 968.850 296.000 969.130 300.000 ;
    END
  END mstream_o[977]
  PIN mstream_o[978]
    DIRECTION OUTPUT TRISTATE ;
    USE SIGNAL ;
    ANTENNADIFFAREA 0.795200 ;
    PORT
      LAYER met2 ;
        RECT 969.770 296.000 970.050 300.000 ;
    END
  END mstream_o[978]
  PIN mstream_o[979]
    DIRECTION OUTPUT TRISTATE ;
    USE SIGNAL ;
    ANTENNADIFFAREA 0.795200 ;
    PORT
      LAYER met2 ;
        RECT 970.690 296.000 970.970 300.000 ;
    END
  END mstream_o[979]
  PIN mstream_o[97]
    DIRECTION OUTPUT TRISTATE ;
    USE SIGNAL ;
    ANTENNADIFFAREA 0.795200 ;
    PORT
      LAYER met2 ;
        RECT 159.250 296.000 159.530 300.000 ;
    END
  END mstream_o[97]
  PIN mstream_o[980]
    DIRECTION OUTPUT TRISTATE ;
    USE SIGNAL ;
    ANTENNADIFFAREA 0.795200 ;
    PORT
      LAYER met2 ;
        RECT 971.610 296.000 971.890 300.000 ;
    END
  END mstream_o[980]
  PIN mstream_o[981]
    DIRECTION OUTPUT TRISTATE ;
    USE SIGNAL ;
    ANTENNADIFFAREA 0.795200 ;
    PORT
      LAYER met2 ;
        RECT 972.530 296.000 972.810 300.000 ;
    END
  END mstream_o[981]
  PIN mstream_o[982]
    DIRECTION OUTPUT TRISTATE ;
    USE SIGNAL ;
    ANTENNADIFFAREA 0.795200 ;
    PORT
      LAYER met2 ;
        RECT 973.450 296.000 973.730 300.000 ;
    END
  END mstream_o[982]
  PIN mstream_o[983]
    DIRECTION OUTPUT TRISTATE ;
    USE SIGNAL ;
    ANTENNADIFFAREA 0.795200 ;
    PORT
      LAYER met2 ;
        RECT 974.370 296.000 974.650 300.000 ;
    END
  END mstream_o[983]
  PIN mstream_o[984]
    DIRECTION OUTPUT TRISTATE ;
    USE SIGNAL ;
    ANTENNADIFFAREA 0.795200 ;
    PORT
      LAYER met2 ;
        RECT 975.290 296.000 975.570 300.000 ;
    END
  END mstream_o[984]
  PIN mstream_o[985]
    DIRECTION OUTPUT TRISTATE ;
    USE SIGNAL ;
    ANTENNADIFFAREA 0.795200 ;
    PORT
      LAYER met2 ;
        RECT 976.210 296.000 976.490 300.000 ;
    END
  END mstream_o[985]
  PIN mstream_o[986]
    DIRECTION OUTPUT TRISTATE ;
    USE SIGNAL ;
    ANTENNADIFFAREA 0.795200 ;
    PORT
      LAYER met2 ;
        RECT 977.130 296.000 977.410 300.000 ;
    END
  END mstream_o[986]
  PIN mstream_o[987]
    DIRECTION OUTPUT TRISTATE ;
    USE SIGNAL ;
    ANTENNADIFFAREA 0.795200 ;
    PORT
      LAYER met2 ;
        RECT 978.050 296.000 978.330 300.000 ;
    END
  END mstream_o[987]
  PIN mstream_o[988]
    DIRECTION OUTPUT TRISTATE ;
    USE SIGNAL ;
    ANTENNADIFFAREA 0.795200 ;
    PORT
      LAYER met2 ;
        RECT 978.970 296.000 979.250 300.000 ;
    END
  END mstream_o[988]
  PIN mstream_o[989]
    DIRECTION OUTPUT TRISTATE ;
    USE SIGNAL ;
    ANTENNADIFFAREA 0.795200 ;
    PORT
      LAYER met2 ;
        RECT 979.890 296.000 980.170 300.000 ;
    END
  END mstream_o[989]
  PIN mstream_o[98]
    DIRECTION OUTPUT TRISTATE ;
    USE SIGNAL ;
    ANTENNADIFFAREA 0.795200 ;
    PORT
      LAYER met2 ;
        RECT 160.170 296.000 160.450 300.000 ;
    END
  END mstream_o[98]
  PIN mstream_o[990]
    DIRECTION OUTPUT TRISTATE ;
    USE SIGNAL ;
    ANTENNADIFFAREA 0.795200 ;
    PORT
      LAYER met2 ;
        RECT 980.810 296.000 981.090 300.000 ;
    END
  END mstream_o[990]
  PIN mstream_o[991]
    DIRECTION OUTPUT TRISTATE ;
    USE SIGNAL ;
    ANTENNADIFFAREA 0.795200 ;
    PORT
      LAYER met2 ;
        RECT 981.730 296.000 982.010 300.000 ;
    END
  END mstream_o[991]
  PIN mstream_o[992]
    DIRECTION OUTPUT TRISTATE ;
    USE SIGNAL ;
    ANTENNADIFFAREA 0.795200 ;
    PORT
      LAYER met2 ;
        RECT 982.650 296.000 982.930 300.000 ;
    END
  END mstream_o[992]
  PIN mstream_o[993]
    DIRECTION OUTPUT TRISTATE ;
    USE SIGNAL ;
    ANTENNADIFFAREA 0.795200 ;
    PORT
      LAYER met2 ;
        RECT 983.570 296.000 983.850 300.000 ;
    END
  END mstream_o[993]
  PIN mstream_o[994]
    DIRECTION OUTPUT TRISTATE ;
    USE SIGNAL ;
    ANTENNADIFFAREA 0.795200 ;
    PORT
      LAYER met2 ;
        RECT 984.490 296.000 984.770 300.000 ;
    END
  END mstream_o[994]
  PIN mstream_o[995]
    DIRECTION OUTPUT TRISTATE ;
    USE SIGNAL ;
    ANTENNADIFFAREA 0.795200 ;
    PORT
      LAYER met2 ;
        RECT 985.410 296.000 985.690 300.000 ;
    END
  END mstream_o[995]
  PIN mstream_o[996]
    DIRECTION OUTPUT TRISTATE ;
    USE SIGNAL ;
    ANTENNADIFFAREA 0.795200 ;
    PORT
      LAYER met2 ;
        RECT 986.330 296.000 986.610 300.000 ;
    END
  END mstream_o[996]
  PIN mstream_o[997]
    DIRECTION OUTPUT TRISTATE ;
    USE SIGNAL ;
    ANTENNADIFFAREA 0.795200 ;
    PORT
      LAYER met2 ;
        RECT 987.250 296.000 987.530 300.000 ;
    END
  END mstream_o[997]
  PIN mstream_o[998]
    DIRECTION OUTPUT TRISTATE ;
    USE SIGNAL ;
    ANTENNADIFFAREA 0.795200 ;
    PORT
      LAYER met2 ;
        RECT 988.170 296.000 988.450 300.000 ;
    END
  END mstream_o[998]
  PIN mstream_o[999]
    DIRECTION OUTPUT TRISTATE ;
    USE SIGNAL ;
    ANTENNADIFFAREA 0.795200 ;
    PORT
      LAYER met2 ;
        RECT 989.090 296.000 989.370 300.000 ;
    END
  END mstream_o[999]
  PIN mstream_o[99]
    DIRECTION OUTPUT TRISTATE ;
    USE SIGNAL ;
    ANTENNADIFFAREA 0.795200 ;
    PORT
      LAYER met2 ;
        RECT 161.090 296.000 161.370 300.000 ;
    END
  END mstream_o[99]
  PIN mstream_o[9]
    DIRECTION OUTPUT TRISTATE ;
    USE SIGNAL ;
    ANTENNADIFFAREA 0.795200 ;
    PORT
      LAYER met2 ;
        RECT 78.290 296.000 78.570 300.000 ;
    END
  END mstream_o[9]
  PIN nrst_i
    DIRECTION INPUT ;
    USE SIGNAL ;
    ANTENNAGATEAREA 0.196500 ;
    PORT
      LAYER met3 ;
        RECT 1196.000 285.640 1200.000 286.240 ;
    END
  END nrst_i
  PIN order_sstream_i[0]
    DIRECTION INPUT ;
    USE SIGNAL ;
    ANTENNAGATEAREA 0.159000 ;
    PORT
      LAYER met3 ;
        RECT 1196.000 40.840 1200.000 41.440 ;
    END
  END order_sstream_i[0]
  PIN order_sstream_i[1]
    DIRECTION INPUT ;
    USE SIGNAL ;
    ANTENNAGATEAREA 0.159000 ;
    PORT
      LAYER met3 ;
        RECT 1196.000 68.040 1200.000 68.640 ;
    END
  END order_sstream_i[1]
  PIN order_sstream_i[2]
    DIRECTION INPUT ;
    USE SIGNAL ;
    ANTENNAGATEAREA 0.213000 ;
    PORT
      LAYER met3 ;
        RECT 1196.000 95.240 1200.000 95.840 ;
    END
  END order_sstream_i[2]
  PIN order_sstream_i[3]
    DIRECTION INPUT ;
    USE SIGNAL ;
    PORT
      LAYER met3 ;
        RECT 1196.000 122.440 1200.000 123.040 ;
    END
  END order_sstream_i[3]
  PIN order_sstream_o
    DIRECTION OUTPUT TRISTATE ;
    USE SIGNAL ;
    ANTENNADIFFAREA 0.795200 ;
    PORT
      LAYER met3 ;
        RECT 1196.000 13.640 1200.000 14.240 ;
    END
  END order_sstream_o
  PIN outbox_sstream_i[0]
    DIRECTION INPUT ;
    USE SIGNAL ;
    ANTENNAGATEAREA 0.495000 ;
    PORT
      LAYER met2 ;
        RECT 25.850 0.000 26.130 4.000 ;
    END
  END outbox_sstream_i[0]
  PIN outbox_sstream_i[100]
    DIRECTION INPUT ;
    USE SIGNAL ;
    ANTENNAGATEAREA 0.247500 ;
    PORT
      LAYER met2 ;
        RECT 1162.970 0.000 1163.250 4.000 ;
    END
  END outbox_sstream_i[100]
  PIN outbox_sstream_i[101]
    DIRECTION INPUT ;
    USE SIGNAL ;
    PORT
      LAYER met2 ;
        RECT 1174.010 0.000 1174.290 4.000 ;
    END
  END outbox_sstream_i[101]
  PIN outbox_sstream_i[10]
    DIRECTION INPUT ;
    USE SIGNAL ;
    ANTENNAGATEAREA 0.742500 ;
    PORT
      LAYER met2 ;
        RECT 169.370 0.000 169.650 4.000 ;
    END
  END outbox_sstream_i[10]
  PIN outbox_sstream_i[11]
    DIRECTION INPUT ;
    USE SIGNAL ;
    ANTENNAGATEAREA 0.742500 ;
    PORT
      LAYER met2 ;
        RECT 180.410 0.000 180.690 4.000 ;
    END
  END outbox_sstream_i[11]
  PIN outbox_sstream_i[12]
    DIRECTION INPUT ;
    USE SIGNAL ;
    ANTENNAGATEAREA 0.495000 ;
    PORT
      LAYER met2 ;
        RECT 191.450 0.000 191.730 4.000 ;
    END
  END outbox_sstream_i[12]
  PIN outbox_sstream_i[13]
    DIRECTION INPUT ;
    USE SIGNAL ;
    ANTENNAGATEAREA 0.742500 ;
    PORT
      LAYER met2 ;
        RECT 202.490 0.000 202.770 4.000 ;
    END
  END outbox_sstream_i[13]
  PIN outbox_sstream_i[14]
    DIRECTION INPUT ;
    USE SIGNAL ;
    ANTENNAGATEAREA 0.742500 ;
    PORT
      LAYER met2 ;
        RECT 213.530 0.000 213.810 4.000 ;
    END
  END outbox_sstream_i[14]
  PIN outbox_sstream_i[15]
    DIRECTION INPUT ;
    USE SIGNAL ;
    ANTENNAGATEAREA 0.742500 ;
    PORT
      LAYER met2 ;
        RECT 224.570 0.000 224.850 4.000 ;
    END
  END outbox_sstream_i[15]
  PIN outbox_sstream_i[16]
    DIRECTION INPUT ;
    USE SIGNAL ;
    ANTENNAGATEAREA 0.742500 ;
    PORT
      LAYER met2 ;
        RECT 235.610 0.000 235.890 4.000 ;
    END
  END outbox_sstream_i[16]
  PIN outbox_sstream_i[17]
    DIRECTION INPUT ;
    USE SIGNAL ;
    ANTENNAGATEAREA 0.742500 ;
    PORT
      LAYER met2 ;
        RECT 246.650 0.000 246.930 4.000 ;
    END
  END outbox_sstream_i[17]
  PIN outbox_sstream_i[18]
    DIRECTION INPUT ;
    USE SIGNAL ;
    ANTENNAGATEAREA 0.742500 ;
    PORT
      LAYER met2 ;
        RECT 257.690 0.000 257.970 4.000 ;
    END
  END outbox_sstream_i[18]
  PIN outbox_sstream_i[19]
    DIRECTION INPUT ;
    USE SIGNAL ;
    ANTENNAGATEAREA 0.495000 ;
    PORT
      LAYER met2 ;
        RECT 268.730 0.000 269.010 4.000 ;
    END
  END outbox_sstream_i[19]
  PIN outbox_sstream_i[1]
    DIRECTION INPUT ;
    USE SIGNAL ;
    ANTENNAGATEAREA 0.742500 ;
    PORT
      LAYER met2 ;
        RECT 47.930 0.000 48.210 4.000 ;
    END
  END outbox_sstream_i[1]
  PIN outbox_sstream_i[20]
    DIRECTION INPUT ;
    USE SIGNAL ;
    ANTENNAGATEAREA 0.742500 ;
    PORT
      LAYER met2 ;
        RECT 279.770 0.000 280.050 4.000 ;
    END
  END outbox_sstream_i[20]
  PIN outbox_sstream_i[21]
    DIRECTION INPUT ;
    USE SIGNAL ;
    ANTENNAGATEAREA 0.495000 ;
    PORT
      LAYER met2 ;
        RECT 290.810 0.000 291.090 4.000 ;
    END
  END outbox_sstream_i[21]
  PIN outbox_sstream_i[22]
    DIRECTION INPUT ;
    USE SIGNAL ;
    ANTENNAGATEAREA 0.426000 ;
    PORT
      LAYER met2 ;
        RECT 301.850 0.000 302.130 4.000 ;
    END
  END outbox_sstream_i[22]
  PIN outbox_sstream_i[23]
    DIRECTION INPUT ;
    USE SIGNAL ;
    ANTENNAGATEAREA 0.495000 ;
    PORT
      LAYER met2 ;
        RECT 312.890 0.000 313.170 4.000 ;
    END
  END outbox_sstream_i[23]
  PIN outbox_sstream_i[24]
    DIRECTION INPUT ;
    USE SIGNAL ;
    ANTENNAGATEAREA 0.426000 ;
    PORT
      LAYER met2 ;
        RECT 323.930 0.000 324.210 4.000 ;
    END
  END outbox_sstream_i[24]
  PIN outbox_sstream_i[25]
    DIRECTION INPUT ;
    USE SIGNAL ;
    ANTENNAGATEAREA 0.426000 ;
    PORT
      LAYER met2 ;
        RECT 334.970 0.000 335.250 4.000 ;
    END
  END outbox_sstream_i[25]
  PIN outbox_sstream_i[26]
    DIRECTION INPUT ;
    USE SIGNAL ;
    ANTENNAGATEAREA 0.426000 ;
    PORT
      LAYER met2 ;
        RECT 346.010 0.000 346.290 4.000 ;
    END
  END outbox_sstream_i[26]
  PIN outbox_sstream_i[27]
    DIRECTION INPUT ;
    USE SIGNAL ;
    ANTENNAGATEAREA 0.426000 ;
    PORT
      LAYER met2 ;
        RECT 357.050 0.000 357.330 4.000 ;
    END
  END outbox_sstream_i[27]
  PIN outbox_sstream_i[28]
    DIRECTION INPUT ;
    USE SIGNAL ;
    ANTENNAGATEAREA 0.495000 ;
    PORT
      LAYER met2 ;
        RECT 368.090 0.000 368.370 4.000 ;
    END
  END outbox_sstream_i[28]
  PIN outbox_sstream_i[29]
    DIRECTION INPUT ;
    USE SIGNAL ;
    ANTENNAGATEAREA 0.495000 ;
    PORT
      LAYER met2 ;
        RECT 379.130 0.000 379.410 4.000 ;
    END
  END outbox_sstream_i[29]
  PIN outbox_sstream_i[2]
    DIRECTION INPUT ;
    USE SIGNAL ;
    ANTENNAGATEAREA 0.742500 ;
    PORT
      LAYER met2 ;
        RECT 70.010 0.000 70.290 4.000 ;
    END
  END outbox_sstream_i[2]
  PIN outbox_sstream_i[30]
    DIRECTION INPUT ;
    USE SIGNAL ;
    ANTENNAGATEAREA 0.247500 ;
    PORT
      LAYER met2 ;
        RECT 390.170 0.000 390.450 4.000 ;
    END
  END outbox_sstream_i[30]
  PIN outbox_sstream_i[31]
    DIRECTION INPUT ;
    USE SIGNAL ;
    ANTENNAGATEAREA 0.247500 ;
    PORT
      LAYER met2 ;
        RECT 401.210 0.000 401.490 4.000 ;
    END
  END outbox_sstream_i[31]
  PIN outbox_sstream_i[32]
    DIRECTION INPUT ;
    USE SIGNAL ;
    ANTENNAGATEAREA 0.213000 ;
    PORT
      LAYER met2 ;
        RECT 412.250 0.000 412.530 4.000 ;
    END
  END outbox_sstream_i[32]
  PIN outbox_sstream_i[33]
    DIRECTION INPUT ;
    USE SIGNAL ;
    PORT
      LAYER met2 ;
        RECT 423.290 0.000 423.570 4.000 ;
    END
  END outbox_sstream_i[33]
  PIN outbox_sstream_i[34]
    DIRECTION INPUT ;
    USE SIGNAL ;
    ANTENNAGATEAREA 0.495000 ;
    PORT
      LAYER met2 ;
        RECT 434.330 0.000 434.610 4.000 ;
    END
  END outbox_sstream_i[34]
  PIN outbox_sstream_i[35]
    DIRECTION INPUT ;
    USE SIGNAL ;
    ANTENNAGATEAREA 0.742500 ;
    PORT
      LAYER met2 ;
        RECT 445.370 0.000 445.650 4.000 ;
    END
  END outbox_sstream_i[35]
  PIN outbox_sstream_i[36]
    DIRECTION INPUT ;
    USE SIGNAL ;
    ANTENNAGATEAREA 0.495000 ;
    PORT
      LAYER met2 ;
        RECT 456.410 0.000 456.690 4.000 ;
    END
  END outbox_sstream_i[36]
  PIN outbox_sstream_i[37]
    DIRECTION INPUT ;
    USE SIGNAL ;
    ANTENNAGATEAREA 0.495000 ;
    PORT
      LAYER met2 ;
        RECT 467.450 0.000 467.730 4.000 ;
    END
  END outbox_sstream_i[37]
  PIN outbox_sstream_i[38]
    DIRECTION INPUT ;
    USE SIGNAL ;
    ANTENNAGATEAREA 0.742500 ;
    PORT
      LAYER met2 ;
        RECT 478.490 0.000 478.770 4.000 ;
    END
  END outbox_sstream_i[38]
  PIN outbox_sstream_i[39]
    DIRECTION INPUT ;
    USE SIGNAL ;
    ANTENNAGATEAREA 0.495000 ;
    PORT
      LAYER met2 ;
        RECT 489.530 0.000 489.810 4.000 ;
    END
  END outbox_sstream_i[39]
  PIN outbox_sstream_i[3]
    DIRECTION INPUT ;
    USE SIGNAL ;
    ANTENNAGATEAREA 0.742500 ;
    PORT
      LAYER met2 ;
        RECT 92.090 0.000 92.370 4.000 ;
    END
  END outbox_sstream_i[3]
  PIN outbox_sstream_i[40]
    DIRECTION INPUT ;
    USE SIGNAL ;
    ANTENNAGATEAREA 0.742500 ;
    PORT
      LAYER met2 ;
        RECT 500.570 0.000 500.850 4.000 ;
    END
  END outbox_sstream_i[40]
  PIN outbox_sstream_i[41]
    DIRECTION INPUT ;
    USE SIGNAL ;
    ANTENNAGATEAREA 0.742500 ;
    PORT
      LAYER met2 ;
        RECT 511.610 0.000 511.890 4.000 ;
    END
  END outbox_sstream_i[41]
  PIN outbox_sstream_i[42]
    DIRECTION INPUT ;
    USE SIGNAL ;
    ANTENNAGATEAREA 0.742500 ;
    PORT
      LAYER met2 ;
        RECT 522.650 0.000 522.930 4.000 ;
    END
  END outbox_sstream_i[42]
  PIN outbox_sstream_i[43]
    DIRECTION INPUT ;
    USE SIGNAL ;
    ANTENNAGATEAREA 0.742500 ;
    PORT
      LAYER met2 ;
        RECT 533.690 0.000 533.970 4.000 ;
    END
  END outbox_sstream_i[43]
  PIN outbox_sstream_i[44]
    DIRECTION INPUT ;
    USE SIGNAL ;
    ANTENNAGATEAREA 0.742500 ;
    PORT
      LAYER met2 ;
        RECT 544.730 0.000 545.010 4.000 ;
    END
  END outbox_sstream_i[44]
  PIN outbox_sstream_i[45]
    DIRECTION INPUT ;
    USE SIGNAL ;
    ANTENNAGATEAREA 0.742500 ;
    PORT
      LAYER met2 ;
        RECT 555.770 0.000 556.050 4.000 ;
    END
  END outbox_sstream_i[45]
  PIN outbox_sstream_i[46]
    DIRECTION INPUT ;
    USE SIGNAL ;
    ANTENNAGATEAREA 0.495000 ;
    PORT
      LAYER met2 ;
        RECT 566.810 0.000 567.090 4.000 ;
    END
  END outbox_sstream_i[46]
  PIN outbox_sstream_i[47]
    DIRECTION INPUT ;
    USE SIGNAL ;
    ANTENNAGATEAREA 0.495000 ;
    PORT
      LAYER met2 ;
        RECT 577.850 0.000 578.130 4.000 ;
    END
  END outbox_sstream_i[47]
  PIN outbox_sstream_i[48]
    DIRECTION INPUT ;
    USE SIGNAL ;
    ANTENNAGATEAREA 0.495000 ;
    PORT
      LAYER met2 ;
        RECT 588.890 0.000 589.170 4.000 ;
    END
  END outbox_sstream_i[48]
  PIN outbox_sstream_i[49]
    DIRECTION INPUT ;
    USE SIGNAL ;
    ANTENNAGATEAREA 0.742500 ;
    PORT
      LAYER met2 ;
        RECT 599.930 0.000 600.210 4.000 ;
    END
  END outbox_sstream_i[49]
  PIN outbox_sstream_i[4]
    DIRECTION INPUT ;
    USE SIGNAL ;
    ANTENNAGATEAREA 0.742500 ;
    PORT
      LAYER met2 ;
        RECT 103.130 0.000 103.410 4.000 ;
    END
  END outbox_sstream_i[4]
  PIN outbox_sstream_i[50]
    DIRECTION INPUT ;
    USE SIGNAL ;
    ANTENNAGATEAREA 0.742500 ;
    PORT
      LAYER met2 ;
        RECT 610.970 0.000 611.250 4.000 ;
    END
  END outbox_sstream_i[50]
  PIN outbox_sstream_i[51]
    DIRECTION INPUT ;
    USE SIGNAL ;
    ANTENNAGATEAREA 0.742500 ;
    PORT
      LAYER met2 ;
        RECT 622.010 0.000 622.290 4.000 ;
    END
  END outbox_sstream_i[51]
  PIN outbox_sstream_i[52]
    DIRECTION INPUT ;
    USE SIGNAL ;
    ANTENNAGATEAREA 0.742500 ;
    PORT
      LAYER met2 ;
        RECT 633.050 0.000 633.330 4.000 ;
    END
  END outbox_sstream_i[52]
  PIN outbox_sstream_i[53]
    DIRECTION INPUT ;
    USE SIGNAL ;
    ANTENNAGATEAREA 0.742500 ;
    PORT
      LAYER met2 ;
        RECT 644.090 0.000 644.370 4.000 ;
    END
  END outbox_sstream_i[53]
  PIN outbox_sstream_i[54]
    DIRECTION INPUT ;
    USE SIGNAL ;
    ANTENNAGATEAREA 0.742500 ;
    PORT
      LAYER met2 ;
        RECT 655.130 0.000 655.410 4.000 ;
    END
  END outbox_sstream_i[54]
  PIN outbox_sstream_i[55]
    DIRECTION INPUT ;
    USE SIGNAL ;
    ANTENNAGATEAREA 0.742500 ;
    PORT
      LAYER met2 ;
        RECT 666.170 0.000 666.450 4.000 ;
    END
  END outbox_sstream_i[55]
  PIN outbox_sstream_i[56]
    DIRECTION INPUT ;
    USE SIGNAL ;
    ANTENNAGATEAREA 0.495000 ;
    PORT
      LAYER met2 ;
        RECT 677.210 0.000 677.490 4.000 ;
    END
  END outbox_sstream_i[56]
  PIN outbox_sstream_i[57]
    DIRECTION INPUT ;
    USE SIGNAL ;
    ANTENNAGATEAREA 0.426000 ;
    PORT
      LAYER met2 ;
        RECT 688.250 0.000 688.530 4.000 ;
    END
  END outbox_sstream_i[57]
  PIN outbox_sstream_i[58]
    DIRECTION INPUT ;
    USE SIGNAL ;
    ANTENNAGATEAREA 0.426000 ;
    PORT
      LAYER met2 ;
        RECT 699.290 0.000 699.570 4.000 ;
    END
  END outbox_sstream_i[58]
  PIN outbox_sstream_i[59]
    DIRECTION INPUT ;
    USE SIGNAL ;
    ANTENNAGATEAREA 0.426000 ;
    PORT
      LAYER met2 ;
        RECT 710.330 0.000 710.610 4.000 ;
    END
  END outbox_sstream_i[59]
  PIN outbox_sstream_i[5]
    DIRECTION INPUT ;
    USE SIGNAL ;
    ANTENNAGATEAREA 0.742500 ;
    PORT
      LAYER met2 ;
        RECT 114.170 0.000 114.450 4.000 ;
    END
  END outbox_sstream_i[5]
  PIN outbox_sstream_i[60]
    DIRECTION INPUT ;
    USE SIGNAL ;
    ANTENNAGATEAREA 0.247500 ;
    PORT
      LAYER met2 ;
        RECT 721.370 0.000 721.650 4.000 ;
    END
  END outbox_sstream_i[60]
  PIN outbox_sstream_i[61]
    DIRECTION INPUT ;
    USE SIGNAL ;
    ANTENNAGATEAREA 0.247500 ;
    PORT
      LAYER met2 ;
        RECT 732.410 0.000 732.690 4.000 ;
    END
  END outbox_sstream_i[61]
  PIN outbox_sstream_i[62]
    DIRECTION INPUT ;
    USE SIGNAL ;
    ANTENNAGATEAREA 0.213000 ;
    PORT
      LAYER met2 ;
        RECT 743.450 0.000 743.730 4.000 ;
    END
  END outbox_sstream_i[62]
  PIN outbox_sstream_i[63]
    DIRECTION INPUT ;
    USE SIGNAL ;
    ANTENNAGATEAREA 0.426000 ;
    PORT
      LAYER met2 ;
        RECT 754.490 0.000 754.770 4.000 ;
    END
  END outbox_sstream_i[63]
  PIN outbox_sstream_i[64]
    DIRECTION INPUT ;
    USE SIGNAL ;
    ANTENNAGATEAREA 0.426000 ;
    PORT
      LAYER met2 ;
        RECT 765.530 0.000 765.810 4.000 ;
    END
  END outbox_sstream_i[64]
  PIN outbox_sstream_i[65]
    DIRECTION INPUT ;
    USE SIGNAL ;
    ANTENNAGATEAREA 0.426000 ;
    PORT
      LAYER met2 ;
        RECT 776.570 0.000 776.850 4.000 ;
    END
  END outbox_sstream_i[65]
  PIN outbox_sstream_i[66]
    DIRECTION INPUT ;
    USE SIGNAL ;
    ANTENNAGATEAREA 0.159000 ;
    PORT
      LAYER met2 ;
        RECT 787.610 0.000 787.890 4.000 ;
    END
  END outbox_sstream_i[66]
  PIN outbox_sstream_i[67]
    DIRECTION INPUT ;
    USE SIGNAL ;
    PORT
      LAYER met2 ;
        RECT 798.650 0.000 798.930 4.000 ;
    END
  END outbox_sstream_i[67]
  PIN outbox_sstream_i[68]
    DIRECTION INPUT ;
    USE SIGNAL ;
    ANTENNAGATEAREA 0.742500 ;
    PORT
      LAYER met2 ;
        RECT 809.690 0.000 809.970 4.000 ;
    END
  END outbox_sstream_i[68]
  PIN outbox_sstream_i[69]
    DIRECTION INPUT ;
    USE SIGNAL ;
    ANTENNAGATEAREA 0.742500 ;
    PORT
      LAYER met2 ;
        RECT 820.730 0.000 821.010 4.000 ;
    END
  END outbox_sstream_i[69]
  PIN outbox_sstream_i[6]
    DIRECTION INPUT ;
    USE SIGNAL ;
    ANTENNAGATEAREA 0.742500 ;
    PORT
      LAYER met2 ;
        RECT 125.210 0.000 125.490 4.000 ;
    END
  END outbox_sstream_i[6]
  PIN outbox_sstream_i[70]
    DIRECTION INPUT ;
    USE SIGNAL ;
    ANTENNAGATEAREA 0.742500 ;
    PORT
      LAYER met2 ;
        RECT 831.770 0.000 832.050 4.000 ;
    END
  END outbox_sstream_i[70]
  PIN outbox_sstream_i[71]
    DIRECTION INPUT ;
    USE SIGNAL ;
    ANTENNAGATEAREA 0.742500 ;
    PORT
      LAYER met2 ;
        RECT 842.810 0.000 843.090 4.000 ;
    END
  END outbox_sstream_i[71]
  PIN outbox_sstream_i[72]
    DIRECTION INPUT ;
    USE SIGNAL ;
    ANTENNAGATEAREA 0.742500 ;
    PORT
      LAYER met2 ;
        RECT 853.850 0.000 854.130 4.000 ;
    END
  END outbox_sstream_i[72]
  PIN outbox_sstream_i[73]
    DIRECTION INPUT ;
    USE SIGNAL ;
    ANTENNAGATEAREA 0.742500 ;
    PORT
      LAYER met2 ;
        RECT 864.890 0.000 865.170 4.000 ;
    END
  END outbox_sstream_i[73]
  PIN outbox_sstream_i[74]
    DIRECTION INPUT ;
    USE SIGNAL ;
    ANTENNAGATEAREA 0.742500 ;
    PORT
      LAYER met2 ;
        RECT 875.930 0.000 876.210 4.000 ;
    END
  END outbox_sstream_i[74]
  PIN outbox_sstream_i[75]
    DIRECTION INPUT ;
    USE SIGNAL ;
    ANTENNAGATEAREA 0.742500 ;
    PORT
      LAYER met2 ;
        RECT 886.970 0.000 887.250 4.000 ;
    END
  END outbox_sstream_i[75]
  PIN outbox_sstream_i[76]
    DIRECTION INPUT ;
    USE SIGNAL ;
    ANTENNAGATEAREA 0.742500 ;
    PORT
      LAYER met2 ;
        RECT 898.010 0.000 898.290 4.000 ;
    END
  END outbox_sstream_i[76]
  PIN outbox_sstream_i[77]
    DIRECTION INPUT ;
    USE SIGNAL ;
    ANTENNAGATEAREA 0.742500 ;
    PORT
      LAYER met2 ;
        RECT 909.050 0.000 909.330 4.000 ;
    END
  END outbox_sstream_i[77]
  PIN outbox_sstream_i[78]
    DIRECTION INPUT ;
    USE SIGNAL ;
    ANTENNAGATEAREA 0.742500 ;
    PORT
      LAYER met2 ;
        RECT 920.090 0.000 920.370 4.000 ;
    END
  END outbox_sstream_i[78]
  PIN outbox_sstream_i[79]
    DIRECTION INPUT ;
    USE SIGNAL ;
    ANTENNAGATEAREA 0.742500 ;
    PORT
      LAYER met2 ;
        RECT 931.130 0.000 931.410 4.000 ;
    END
  END outbox_sstream_i[79]
  PIN outbox_sstream_i[7]
    DIRECTION INPUT ;
    USE SIGNAL ;
    ANTENNAGATEAREA 0.742500 ;
    PORT
      LAYER met2 ;
        RECT 136.250 0.000 136.530 4.000 ;
    END
  END outbox_sstream_i[7]
  PIN outbox_sstream_i[80]
    DIRECTION INPUT ;
    USE SIGNAL ;
    ANTENNAGATEAREA 0.742500 ;
    PORT
      LAYER met2 ;
        RECT 942.170 0.000 942.450 4.000 ;
    END
  END outbox_sstream_i[80]
  PIN outbox_sstream_i[81]
    DIRECTION INPUT ;
    USE SIGNAL ;
    ANTENNAGATEAREA 0.742500 ;
    PORT
      LAYER met2 ;
        RECT 953.210 0.000 953.490 4.000 ;
    END
  END outbox_sstream_i[81]
  PIN outbox_sstream_i[82]
    DIRECTION INPUT ;
    USE SIGNAL ;
    ANTENNAGATEAREA 0.742500 ;
    PORT
      LAYER met2 ;
        RECT 964.250 0.000 964.530 4.000 ;
    END
  END outbox_sstream_i[82]
  PIN outbox_sstream_i[83]
    DIRECTION INPUT ;
    USE SIGNAL ;
    ANTENNAGATEAREA 0.742500 ;
    PORT
      LAYER met2 ;
        RECT 975.290 0.000 975.570 4.000 ;
    END
  END outbox_sstream_i[83]
  PIN outbox_sstream_i[84]
    DIRECTION INPUT ;
    USE SIGNAL ;
    ANTENNAGATEAREA 0.742500 ;
    PORT
      LAYER met2 ;
        RECT 986.330 0.000 986.610 4.000 ;
    END
  END outbox_sstream_i[84]
  PIN outbox_sstream_i[85]
    DIRECTION INPUT ;
    USE SIGNAL ;
    ANTENNAGATEAREA 0.852000 ;
    PORT
      LAYER met2 ;
        RECT 997.370 0.000 997.650 4.000 ;
    END
  END outbox_sstream_i[85]
  PIN outbox_sstream_i[86]
    DIRECTION INPUT ;
    USE SIGNAL ;
    ANTENNAGATEAREA 0.742500 ;
    PORT
      LAYER met2 ;
        RECT 1008.410 0.000 1008.690 4.000 ;
    END
  END outbox_sstream_i[86]
  PIN outbox_sstream_i[87]
    DIRECTION INPUT ;
    USE SIGNAL ;
    ANTENNAGATEAREA 0.742500 ;
    PORT
      LAYER met2 ;
        RECT 1019.450 0.000 1019.730 4.000 ;
    END
  END outbox_sstream_i[87]
  PIN outbox_sstream_i[88]
    DIRECTION INPUT ;
    USE SIGNAL ;
    ANTENNAGATEAREA 0.742500 ;
    PORT
      LAYER met2 ;
        RECT 1030.490 0.000 1030.770 4.000 ;
    END
  END outbox_sstream_i[88]
  PIN outbox_sstream_i[89]
    DIRECTION INPUT ;
    USE SIGNAL ;
    ANTENNAGATEAREA 0.742500 ;
    PORT
      LAYER met2 ;
        RECT 1041.530 0.000 1041.810 4.000 ;
    END
  END outbox_sstream_i[89]
  PIN outbox_sstream_i[8]
    DIRECTION INPUT ;
    USE SIGNAL ;
    ANTENNAGATEAREA 0.742500 ;
    PORT
      LAYER met2 ;
        RECT 147.290 0.000 147.570 4.000 ;
    END
  END outbox_sstream_i[8]
  PIN outbox_sstream_i[90]
    DIRECTION INPUT ;
    USE SIGNAL ;
    ANTENNAGATEAREA 0.742500 ;
    PORT
      LAYER met2 ;
        RECT 1052.570 0.000 1052.850 4.000 ;
    END
  END outbox_sstream_i[90]
  PIN outbox_sstream_i[91]
    DIRECTION INPUT ;
    USE SIGNAL ;
    ANTENNAGATEAREA 0.495000 ;
    PORT
      LAYER met2 ;
        RECT 1063.610 0.000 1063.890 4.000 ;
    END
  END outbox_sstream_i[91]
  PIN outbox_sstream_i[92]
    DIRECTION INPUT ;
    USE SIGNAL ;
    ANTENNAGATEAREA 0.495000 ;
    PORT
      LAYER met2 ;
        RECT 1074.650 0.000 1074.930 4.000 ;
    END
  END outbox_sstream_i[92]
  PIN outbox_sstream_i[93]
    DIRECTION INPUT ;
    USE SIGNAL ;
    ANTENNAGATEAREA 0.495000 ;
    PORT
      LAYER met2 ;
        RECT 1085.690 0.000 1085.970 4.000 ;
    END
  END outbox_sstream_i[93]
  PIN outbox_sstream_i[94]
    DIRECTION INPUT ;
    USE SIGNAL ;
    ANTENNAGATEAREA 0.426000 ;
    PORT
      LAYER met2 ;
        RECT 1096.730 0.000 1097.010 4.000 ;
    END
  END outbox_sstream_i[94]
  PIN outbox_sstream_i[95]
    DIRECTION INPUT ;
    USE SIGNAL ;
    ANTENNAGATEAREA 0.426000 ;
    PORT
      LAYER met2 ;
        RECT 1107.770 0.000 1108.050 4.000 ;
    END
  END outbox_sstream_i[95]
  PIN outbox_sstream_i[96]
    DIRECTION INPUT ;
    USE SIGNAL ;
    ANTENNAGATEAREA 0.426000 ;
    PORT
      LAYER met2 ;
        RECT 1118.810 0.000 1119.090 4.000 ;
    END
  END outbox_sstream_i[96]
  PIN outbox_sstream_i[97]
    DIRECTION INPUT ;
    USE SIGNAL ;
    ANTENNAGATEAREA 0.495000 ;
    PORT
      LAYER met2 ;
        RECT 1129.850 0.000 1130.130 4.000 ;
    END
  END outbox_sstream_i[97]
  PIN outbox_sstream_i[98]
    DIRECTION INPUT ;
    USE SIGNAL ;
    ANTENNAGATEAREA 0.495000 ;
    PORT
      LAYER met2 ;
        RECT 1140.890 0.000 1141.170 4.000 ;
    END
  END outbox_sstream_i[98]
  PIN outbox_sstream_i[99]
    DIRECTION INPUT ;
    USE SIGNAL ;
    ANTENNAGATEAREA 0.495000 ;
    PORT
      LAYER met2 ;
        RECT 1151.930 0.000 1152.210 4.000 ;
    END
  END outbox_sstream_i[99]
  PIN outbox_sstream_i[9]
    DIRECTION INPUT ;
    USE SIGNAL ;
    ANTENNAGATEAREA 0.742500 ;
    PORT
      LAYER met2 ;
        RECT 158.330 0.000 158.610 4.000 ;
    END
  END outbox_sstream_i[9]
  PIN outbox_sstream_o[0]
    DIRECTION OUTPUT TRISTATE ;
    USE SIGNAL ;
    ANTENNADIFFAREA 0.795200 ;
    PORT
      LAYER met2 ;
        RECT 36.890 0.000 37.170 4.000 ;
    END
  END outbox_sstream_o[0]
  PIN outbox_sstream_o[1]
    DIRECTION OUTPUT TRISTATE ;
    USE SIGNAL ;
    ANTENNADIFFAREA 0.795200 ;
    PORT
      LAYER met2 ;
        RECT 58.970 0.000 59.250 4.000 ;
    END
  END outbox_sstream_o[1]
  PIN outbox_sstream_o[2]
    DIRECTION OUTPUT TRISTATE ;
    USE SIGNAL ;
    ANTENNADIFFAREA 0.795200 ;
    PORT
      LAYER met2 ;
        RECT 81.050 0.000 81.330 4.000 ;
    END
  END outbox_sstream_o[2]
  PIN vccd1
    DIRECTION INOUT ;
    USE POWER ;
    PORT
      LAYER met4 ;
        RECT 21.040 10.640 22.640 288.560 ;
    END
    PORT
      LAYER met4 ;
        RECT 174.640 10.640 176.240 288.560 ;
    END
    PORT
      LAYER met4 ;
        RECT 328.240 10.640 329.840 288.560 ;
    END
    PORT
      LAYER met4 ;
        RECT 481.840 10.640 483.440 288.560 ;
    END
    PORT
      LAYER met4 ;
        RECT 635.440 10.640 637.040 288.560 ;
    END
    PORT
      LAYER met4 ;
        RECT 789.040 10.640 790.640 288.560 ;
    END
    PORT
      LAYER met4 ;
        RECT 942.640 10.640 944.240 288.560 ;
    END
    PORT
      LAYER met4 ;
        RECT 1096.240 10.640 1097.840 288.560 ;
    END
  END vccd1
  PIN vob_clear_i
    DIRECTION INPUT ;
    USE SIGNAL ;
    ANTENNAGATEAREA 0.213000 ;
    PORT
      LAYER met3 ;
        RECT 1196.000 204.040 1200.000 204.640 ;
    END
  END vob_clear_i
  PIN vob_empty_o
    DIRECTION OUTPUT TRISTATE ;
    USE SIGNAL ;
    ANTENNADIFFAREA 0.445500 ;
    PORT
      LAYER met3 ;
        RECT 1196.000 176.840 1200.000 177.440 ;
    END
  END vob_empty_o
  PIN vob_full_o
    DIRECTION OUTPUT TRISTATE ;
    USE SIGNAL ;
    ANTENNADIFFAREA 0.795200 ;
    PORT
      LAYER met3 ;
        RECT 1196.000 149.640 1200.000 150.240 ;
    END
  END vob_full_o
  PIN vrc_busy_o
    DIRECTION OUTPUT TRISTATE ;
    USE SIGNAL ;
    ANTENNADIFFAREA 0.445500 ;
    PORT
      LAYER met3 ;
        RECT 1196.000 231.240 1200.000 231.840 ;
    END
  END vrc_busy_o
  PIN vssd1
    DIRECTION INOUT ;
    USE GROUND ;
    PORT
      LAYER met4 ;
        RECT 97.840 10.640 99.440 288.560 ;
    END
    PORT
      LAYER met4 ;
        RECT 251.440 10.640 253.040 288.560 ;
    END
    PORT
      LAYER met4 ;
        RECT 405.040 10.640 406.640 288.560 ;
    END
    PORT
      LAYER met4 ;
        RECT 558.640 10.640 560.240 288.560 ;
    END
    PORT
      LAYER met4 ;
        RECT 712.240 10.640 713.840 288.560 ;
    END
    PORT
      LAYER met4 ;
        RECT 865.840 10.640 867.440 288.560 ;
    END
    PORT
      LAYER met4 ;
        RECT 1019.440 10.640 1021.040 288.560 ;
    END
    PORT
      LAYER met4 ;
        RECT 1173.040 10.640 1174.640 288.560 ;
    END
  END vssd1
  OBS
      LAYER nwell ;
        RECT 5.330 284.185 1194.350 287.015 ;
        RECT 5.330 278.745 1194.350 281.575 ;
        RECT 5.330 273.305 1194.350 276.135 ;
        RECT 5.330 267.865 1194.350 270.695 ;
        RECT 5.330 262.425 1194.350 265.255 ;
        RECT 5.330 256.985 1194.350 259.815 ;
        RECT 5.330 251.545 1194.350 254.375 ;
        RECT 5.330 246.105 1194.350 248.935 ;
        RECT 5.330 240.665 1194.350 243.495 ;
        RECT 5.330 235.225 1194.350 238.055 ;
        RECT 5.330 229.785 1194.350 232.615 ;
        RECT 5.330 224.345 1194.350 227.175 ;
        RECT 5.330 218.905 1194.350 221.735 ;
        RECT 5.330 213.465 1194.350 216.295 ;
        RECT 5.330 208.025 1194.350 210.855 ;
        RECT 5.330 202.585 1194.350 205.415 ;
        RECT 5.330 197.145 1194.350 199.975 ;
        RECT 5.330 191.705 1194.350 194.535 ;
        RECT 5.330 186.265 1194.350 189.095 ;
        RECT 5.330 180.825 1194.350 183.655 ;
        RECT 5.330 175.385 1194.350 178.215 ;
        RECT 5.330 169.945 1194.350 172.775 ;
        RECT 5.330 164.505 1194.350 167.335 ;
        RECT 5.330 159.065 1194.350 161.895 ;
        RECT 5.330 153.625 1194.350 156.455 ;
        RECT 5.330 148.185 1194.350 151.015 ;
        RECT 5.330 142.745 1194.350 145.575 ;
        RECT 5.330 137.305 1194.350 140.135 ;
        RECT 5.330 131.865 1194.350 134.695 ;
        RECT 5.330 126.425 1194.350 129.255 ;
        RECT 5.330 120.985 1194.350 123.815 ;
        RECT 5.330 115.545 1194.350 118.375 ;
        RECT 5.330 110.105 1194.350 112.935 ;
        RECT 5.330 104.665 1194.350 107.495 ;
        RECT 5.330 99.225 1194.350 102.055 ;
        RECT 5.330 93.785 1194.350 96.615 ;
        RECT 5.330 88.345 1194.350 91.175 ;
        RECT 5.330 82.905 1194.350 85.735 ;
        RECT 5.330 77.465 1194.350 80.295 ;
        RECT 5.330 72.025 1194.350 74.855 ;
        RECT 5.330 66.585 1194.350 69.415 ;
        RECT 5.330 61.145 1194.350 63.975 ;
        RECT 5.330 55.705 1194.350 58.535 ;
        RECT 5.330 50.265 1194.350 53.095 ;
        RECT 5.330 44.825 1194.350 47.655 ;
        RECT 5.330 39.385 1194.350 42.215 ;
        RECT 5.330 33.945 1194.350 36.775 ;
        RECT 5.330 28.505 1194.350 31.335 ;
        RECT 5.330 23.065 1194.350 25.895 ;
        RECT 5.330 17.625 1194.350 20.455 ;
        RECT 5.330 12.185 1194.350 15.015 ;
      LAYER li1 ;
        RECT 5.520 10.795 1194.160 288.405 ;
      LAYER met1 ;
        RECT 5.520 7.180 1194.160 299.840 ;
      LAYER met2 ;
        RECT 7.920 295.720 68.810 299.870 ;
        RECT 69.650 295.720 69.730 299.870 ;
        RECT 70.570 295.720 70.650 299.870 ;
        RECT 71.490 295.720 71.570 299.870 ;
        RECT 72.410 295.720 72.490 299.870 ;
        RECT 73.330 295.720 73.410 299.870 ;
        RECT 74.250 295.720 74.330 299.870 ;
        RECT 75.170 295.720 75.250 299.870 ;
        RECT 76.090 295.720 76.170 299.870 ;
        RECT 77.010 295.720 77.090 299.870 ;
        RECT 77.930 295.720 78.010 299.870 ;
        RECT 78.850 295.720 78.930 299.870 ;
        RECT 79.770 295.720 79.850 299.870 ;
        RECT 80.690 295.720 80.770 299.870 ;
        RECT 81.610 295.720 81.690 299.870 ;
        RECT 82.530 295.720 82.610 299.870 ;
        RECT 83.450 295.720 83.530 299.870 ;
        RECT 84.370 295.720 84.450 299.870 ;
        RECT 85.290 295.720 85.370 299.870 ;
        RECT 86.210 295.720 86.290 299.870 ;
        RECT 87.130 295.720 87.210 299.870 ;
        RECT 88.050 295.720 88.130 299.870 ;
        RECT 88.970 295.720 89.050 299.870 ;
        RECT 89.890 295.720 89.970 299.870 ;
        RECT 90.810 295.720 90.890 299.870 ;
        RECT 91.730 295.720 91.810 299.870 ;
        RECT 92.650 295.720 92.730 299.870 ;
        RECT 93.570 295.720 93.650 299.870 ;
        RECT 94.490 295.720 94.570 299.870 ;
        RECT 95.410 295.720 95.490 299.870 ;
        RECT 96.330 295.720 96.410 299.870 ;
        RECT 97.250 295.720 97.330 299.870 ;
        RECT 98.170 295.720 98.250 299.870 ;
        RECT 99.090 295.720 99.170 299.870 ;
        RECT 100.010 295.720 100.090 299.870 ;
        RECT 100.930 295.720 101.010 299.870 ;
        RECT 101.850 295.720 101.930 299.870 ;
        RECT 102.770 295.720 102.850 299.870 ;
        RECT 103.690 295.720 103.770 299.870 ;
        RECT 104.610 295.720 104.690 299.870 ;
        RECT 105.530 295.720 105.610 299.870 ;
        RECT 106.450 295.720 106.530 299.870 ;
        RECT 107.370 295.720 107.450 299.870 ;
        RECT 108.290 295.720 108.370 299.870 ;
        RECT 109.210 295.720 109.290 299.870 ;
        RECT 110.130 295.720 110.210 299.870 ;
        RECT 111.050 295.720 111.130 299.870 ;
        RECT 111.970 295.720 112.050 299.870 ;
        RECT 112.890 295.720 112.970 299.870 ;
        RECT 113.810 295.720 113.890 299.870 ;
        RECT 114.730 295.720 114.810 299.870 ;
        RECT 115.650 295.720 115.730 299.870 ;
        RECT 116.570 295.720 116.650 299.870 ;
        RECT 117.490 295.720 117.570 299.870 ;
        RECT 118.410 295.720 118.490 299.870 ;
        RECT 119.330 295.720 119.410 299.870 ;
        RECT 120.250 295.720 120.330 299.870 ;
        RECT 121.170 295.720 121.250 299.870 ;
        RECT 122.090 295.720 122.170 299.870 ;
        RECT 123.010 295.720 123.090 299.870 ;
        RECT 123.930 295.720 124.010 299.870 ;
        RECT 124.850 295.720 124.930 299.870 ;
        RECT 125.770 295.720 125.850 299.870 ;
        RECT 126.690 295.720 126.770 299.870 ;
        RECT 127.610 295.720 127.690 299.870 ;
        RECT 128.530 295.720 128.610 299.870 ;
        RECT 129.450 295.720 129.530 299.870 ;
        RECT 130.370 295.720 130.450 299.870 ;
        RECT 131.290 295.720 131.370 299.870 ;
        RECT 132.210 295.720 132.290 299.870 ;
        RECT 133.130 295.720 133.210 299.870 ;
        RECT 134.050 295.720 134.130 299.870 ;
        RECT 134.970 295.720 135.050 299.870 ;
        RECT 135.890 295.720 135.970 299.870 ;
        RECT 136.810 295.720 136.890 299.870 ;
        RECT 137.730 295.720 137.810 299.870 ;
        RECT 138.650 295.720 138.730 299.870 ;
        RECT 139.570 295.720 139.650 299.870 ;
        RECT 140.490 295.720 140.570 299.870 ;
        RECT 141.410 295.720 141.490 299.870 ;
        RECT 142.330 295.720 142.410 299.870 ;
        RECT 143.250 295.720 143.330 299.870 ;
        RECT 144.170 295.720 144.250 299.870 ;
        RECT 145.090 295.720 145.170 299.870 ;
        RECT 146.010 295.720 146.090 299.870 ;
        RECT 146.930 295.720 147.010 299.870 ;
        RECT 147.850 295.720 147.930 299.870 ;
        RECT 148.770 295.720 148.850 299.870 ;
        RECT 149.690 295.720 149.770 299.870 ;
        RECT 150.610 295.720 150.690 299.870 ;
        RECT 151.530 295.720 151.610 299.870 ;
        RECT 152.450 295.720 152.530 299.870 ;
        RECT 153.370 295.720 153.450 299.870 ;
        RECT 154.290 295.720 154.370 299.870 ;
        RECT 155.210 295.720 155.290 299.870 ;
        RECT 156.130 295.720 156.210 299.870 ;
        RECT 157.050 295.720 157.130 299.870 ;
        RECT 157.970 295.720 158.050 299.870 ;
        RECT 158.890 295.720 158.970 299.870 ;
        RECT 159.810 295.720 159.890 299.870 ;
        RECT 160.730 295.720 160.810 299.870 ;
        RECT 161.650 295.720 161.730 299.870 ;
        RECT 162.570 295.720 162.650 299.870 ;
        RECT 163.490 295.720 163.570 299.870 ;
        RECT 164.410 295.720 164.490 299.870 ;
        RECT 165.330 295.720 165.410 299.870 ;
        RECT 166.250 295.720 166.330 299.870 ;
        RECT 167.170 295.720 167.250 299.870 ;
        RECT 168.090 295.720 168.170 299.870 ;
        RECT 169.010 295.720 169.090 299.870 ;
        RECT 169.930 295.720 170.010 299.870 ;
        RECT 170.850 295.720 170.930 299.870 ;
        RECT 171.770 295.720 171.850 299.870 ;
        RECT 172.690 295.720 172.770 299.870 ;
        RECT 173.610 295.720 173.690 299.870 ;
        RECT 174.530 295.720 174.610 299.870 ;
        RECT 175.450 295.720 175.530 299.870 ;
        RECT 176.370 295.720 176.450 299.870 ;
        RECT 177.290 295.720 177.370 299.870 ;
        RECT 178.210 295.720 178.290 299.870 ;
        RECT 179.130 295.720 179.210 299.870 ;
        RECT 180.050 295.720 180.130 299.870 ;
        RECT 180.970 295.720 181.050 299.870 ;
        RECT 181.890 295.720 181.970 299.870 ;
        RECT 182.810 295.720 182.890 299.870 ;
        RECT 183.730 295.720 183.810 299.870 ;
        RECT 184.650 295.720 184.730 299.870 ;
        RECT 185.570 295.720 185.650 299.870 ;
        RECT 186.490 295.720 186.570 299.870 ;
        RECT 187.410 295.720 187.490 299.870 ;
        RECT 188.330 295.720 188.410 299.870 ;
        RECT 189.250 295.720 189.330 299.870 ;
        RECT 190.170 295.720 190.250 299.870 ;
        RECT 191.090 295.720 191.170 299.870 ;
        RECT 192.010 295.720 192.090 299.870 ;
        RECT 192.930 295.720 193.010 299.870 ;
        RECT 193.850 295.720 193.930 299.870 ;
        RECT 194.770 295.720 194.850 299.870 ;
        RECT 195.690 295.720 195.770 299.870 ;
        RECT 196.610 295.720 196.690 299.870 ;
        RECT 197.530 295.720 197.610 299.870 ;
        RECT 198.450 295.720 198.530 299.870 ;
        RECT 199.370 295.720 199.450 299.870 ;
        RECT 200.290 295.720 200.370 299.870 ;
        RECT 201.210 295.720 201.290 299.870 ;
        RECT 202.130 295.720 202.210 299.870 ;
        RECT 203.050 295.720 203.130 299.870 ;
        RECT 203.970 295.720 204.050 299.870 ;
        RECT 204.890 295.720 204.970 299.870 ;
        RECT 205.810 295.720 205.890 299.870 ;
        RECT 206.730 295.720 206.810 299.870 ;
        RECT 207.650 295.720 207.730 299.870 ;
        RECT 208.570 295.720 208.650 299.870 ;
        RECT 209.490 295.720 209.570 299.870 ;
        RECT 210.410 295.720 210.490 299.870 ;
        RECT 211.330 295.720 211.410 299.870 ;
        RECT 212.250 295.720 212.330 299.870 ;
        RECT 213.170 295.720 213.250 299.870 ;
        RECT 214.090 295.720 214.170 299.870 ;
        RECT 215.010 295.720 215.090 299.870 ;
        RECT 215.930 295.720 216.010 299.870 ;
        RECT 216.850 295.720 216.930 299.870 ;
        RECT 217.770 295.720 217.850 299.870 ;
        RECT 218.690 295.720 218.770 299.870 ;
        RECT 219.610 295.720 219.690 299.870 ;
        RECT 220.530 295.720 220.610 299.870 ;
        RECT 221.450 295.720 221.530 299.870 ;
        RECT 222.370 295.720 222.450 299.870 ;
        RECT 223.290 295.720 223.370 299.870 ;
        RECT 224.210 295.720 224.290 299.870 ;
        RECT 225.130 295.720 225.210 299.870 ;
        RECT 226.050 295.720 226.130 299.870 ;
        RECT 226.970 295.720 227.050 299.870 ;
        RECT 227.890 295.720 227.970 299.870 ;
        RECT 228.810 295.720 228.890 299.870 ;
        RECT 229.730 295.720 229.810 299.870 ;
        RECT 230.650 295.720 230.730 299.870 ;
        RECT 231.570 295.720 231.650 299.870 ;
        RECT 232.490 295.720 232.570 299.870 ;
        RECT 233.410 295.720 233.490 299.870 ;
        RECT 234.330 295.720 234.410 299.870 ;
        RECT 235.250 295.720 235.330 299.870 ;
        RECT 236.170 295.720 236.250 299.870 ;
        RECT 237.090 295.720 237.170 299.870 ;
        RECT 238.010 295.720 238.090 299.870 ;
        RECT 238.930 295.720 239.010 299.870 ;
        RECT 239.850 295.720 239.930 299.870 ;
        RECT 240.770 295.720 240.850 299.870 ;
        RECT 241.690 295.720 241.770 299.870 ;
        RECT 242.610 295.720 242.690 299.870 ;
        RECT 243.530 295.720 243.610 299.870 ;
        RECT 244.450 295.720 244.530 299.870 ;
        RECT 245.370 295.720 245.450 299.870 ;
        RECT 246.290 295.720 246.370 299.870 ;
        RECT 247.210 295.720 247.290 299.870 ;
        RECT 248.130 295.720 248.210 299.870 ;
        RECT 249.050 295.720 249.130 299.870 ;
        RECT 249.970 295.720 250.050 299.870 ;
        RECT 250.890 295.720 250.970 299.870 ;
        RECT 251.810 295.720 251.890 299.870 ;
        RECT 252.730 295.720 252.810 299.870 ;
        RECT 253.650 295.720 253.730 299.870 ;
        RECT 254.570 295.720 254.650 299.870 ;
        RECT 255.490 295.720 255.570 299.870 ;
        RECT 256.410 295.720 256.490 299.870 ;
        RECT 257.330 295.720 257.410 299.870 ;
        RECT 258.250 295.720 258.330 299.870 ;
        RECT 259.170 295.720 259.250 299.870 ;
        RECT 260.090 295.720 260.170 299.870 ;
        RECT 261.010 295.720 261.090 299.870 ;
        RECT 261.930 295.720 262.010 299.870 ;
        RECT 262.850 295.720 262.930 299.870 ;
        RECT 263.770 295.720 263.850 299.870 ;
        RECT 264.690 295.720 264.770 299.870 ;
        RECT 265.610 295.720 265.690 299.870 ;
        RECT 266.530 295.720 266.610 299.870 ;
        RECT 267.450 295.720 267.530 299.870 ;
        RECT 268.370 295.720 268.450 299.870 ;
        RECT 269.290 295.720 269.370 299.870 ;
        RECT 270.210 295.720 270.290 299.870 ;
        RECT 271.130 295.720 271.210 299.870 ;
        RECT 272.050 295.720 272.130 299.870 ;
        RECT 272.970 295.720 273.050 299.870 ;
        RECT 273.890 295.720 273.970 299.870 ;
        RECT 274.810 295.720 274.890 299.870 ;
        RECT 275.730 295.720 275.810 299.870 ;
        RECT 276.650 295.720 276.730 299.870 ;
        RECT 277.570 295.720 277.650 299.870 ;
        RECT 278.490 295.720 278.570 299.870 ;
        RECT 279.410 295.720 279.490 299.870 ;
        RECT 280.330 295.720 280.410 299.870 ;
        RECT 281.250 295.720 281.330 299.870 ;
        RECT 282.170 295.720 282.250 299.870 ;
        RECT 283.090 295.720 283.170 299.870 ;
        RECT 284.010 295.720 284.090 299.870 ;
        RECT 284.930 295.720 285.010 299.870 ;
        RECT 285.850 295.720 285.930 299.870 ;
        RECT 286.770 295.720 286.850 299.870 ;
        RECT 287.690 295.720 287.770 299.870 ;
        RECT 288.610 295.720 288.690 299.870 ;
        RECT 289.530 295.720 289.610 299.870 ;
        RECT 290.450 295.720 290.530 299.870 ;
        RECT 291.370 295.720 291.450 299.870 ;
        RECT 292.290 295.720 292.370 299.870 ;
        RECT 293.210 295.720 293.290 299.870 ;
        RECT 294.130 295.720 294.210 299.870 ;
        RECT 295.050 295.720 295.130 299.870 ;
        RECT 295.970 295.720 296.050 299.870 ;
        RECT 296.890 295.720 296.970 299.870 ;
        RECT 297.810 295.720 297.890 299.870 ;
        RECT 298.730 295.720 298.810 299.870 ;
        RECT 299.650 295.720 299.730 299.870 ;
        RECT 300.570 295.720 300.650 299.870 ;
        RECT 301.490 295.720 301.570 299.870 ;
        RECT 302.410 295.720 302.490 299.870 ;
        RECT 303.330 295.720 303.410 299.870 ;
        RECT 304.250 295.720 304.330 299.870 ;
        RECT 305.170 295.720 305.250 299.870 ;
        RECT 306.090 295.720 306.170 299.870 ;
        RECT 307.010 295.720 307.090 299.870 ;
        RECT 307.930 295.720 308.010 299.870 ;
        RECT 308.850 295.720 308.930 299.870 ;
        RECT 309.770 295.720 309.850 299.870 ;
        RECT 310.690 295.720 310.770 299.870 ;
        RECT 311.610 295.720 311.690 299.870 ;
        RECT 312.530 295.720 312.610 299.870 ;
        RECT 313.450 295.720 313.530 299.870 ;
        RECT 314.370 295.720 314.450 299.870 ;
        RECT 315.290 295.720 315.370 299.870 ;
        RECT 316.210 295.720 316.290 299.870 ;
        RECT 317.130 295.720 317.210 299.870 ;
        RECT 318.050 295.720 318.130 299.870 ;
        RECT 318.970 295.720 319.050 299.870 ;
        RECT 319.890 295.720 319.970 299.870 ;
        RECT 320.810 295.720 320.890 299.870 ;
        RECT 321.730 295.720 321.810 299.870 ;
        RECT 322.650 295.720 322.730 299.870 ;
        RECT 323.570 295.720 323.650 299.870 ;
        RECT 324.490 295.720 324.570 299.870 ;
        RECT 325.410 295.720 325.490 299.870 ;
        RECT 326.330 295.720 326.410 299.870 ;
        RECT 327.250 295.720 327.330 299.870 ;
        RECT 328.170 295.720 328.250 299.870 ;
        RECT 329.090 295.720 329.170 299.870 ;
        RECT 330.010 295.720 330.090 299.870 ;
        RECT 330.930 295.720 331.010 299.870 ;
        RECT 331.850 295.720 331.930 299.870 ;
        RECT 332.770 295.720 332.850 299.870 ;
        RECT 333.690 295.720 333.770 299.870 ;
        RECT 334.610 295.720 334.690 299.870 ;
        RECT 335.530 295.720 335.610 299.870 ;
        RECT 336.450 295.720 336.530 299.870 ;
        RECT 337.370 295.720 337.450 299.870 ;
        RECT 338.290 295.720 338.370 299.870 ;
        RECT 339.210 295.720 339.290 299.870 ;
        RECT 340.130 295.720 340.210 299.870 ;
        RECT 341.050 295.720 341.130 299.870 ;
        RECT 341.970 295.720 342.050 299.870 ;
        RECT 342.890 295.720 342.970 299.870 ;
        RECT 343.810 295.720 343.890 299.870 ;
        RECT 344.730 295.720 344.810 299.870 ;
        RECT 345.650 295.720 345.730 299.870 ;
        RECT 346.570 295.720 346.650 299.870 ;
        RECT 347.490 295.720 347.570 299.870 ;
        RECT 348.410 295.720 348.490 299.870 ;
        RECT 349.330 295.720 349.410 299.870 ;
        RECT 350.250 295.720 350.330 299.870 ;
        RECT 351.170 295.720 351.250 299.870 ;
        RECT 352.090 295.720 352.170 299.870 ;
        RECT 353.010 295.720 353.090 299.870 ;
        RECT 353.930 295.720 354.010 299.870 ;
        RECT 354.850 295.720 354.930 299.870 ;
        RECT 355.770 295.720 355.850 299.870 ;
        RECT 356.690 295.720 356.770 299.870 ;
        RECT 357.610 295.720 357.690 299.870 ;
        RECT 358.530 295.720 358.610 299.870 ;
        RECT 359.450 295.720 359.530 299.870 ;
        RECT 360.370 295.720 360.450 299.870 ;
        RECT 361.290 295.720 361.370 299.870 ;
        RECT 362.210 295.720 362.290 299.870 ;
        RECT 363.130 295.720 363.210 299.870 ;
        RECT 364.050 295.720 364.130 299.870 ;
        RECT 364.970 295.720 365.050 299.870 ;
        RECT 365.890 295.720 365.970 299.870 ;
        RECT 366.810 295.720 366.890 299.870 ;
        RECT 367.730 295.720 367.810 299.870 ;
        RECT 368.650 295.720 368.730 299.870 ;
        RECT 369.570 295.720 369.650 299.870 ;
        RECT 370.490 295.720 370.570 299.870 ;
        RECT 371.410 295.720 371.490 299.870 ;
        RECT 372.330 295.720 372.410 299.870 ;
        RECT 373.250 295.720 373.330 299.870 ;
        RECT 374.170 295.720 374.250 299.870 ;
        RECT 375.090 295.720 375.170 299.870 ;
        RECT 376.010 295.720 376.090 299.870 ;
        RECT 376.930 295.720 377.010 299.870 ;
        RECT 377.850 295.720 377.930 299.870 ;
        RECT 378.770 295.720 378.850 299.870 ;
        RECT 379.690 295.720 379.770 299.870 ;
        RECT 380.610 295.720 380.690 299.870 ;
        RECT 381.530 295.720 381.610 299.870 ;
        RECT 382.450 295.720 382.530 299.870 ;
        RECT 383.370 295.720 383.450 299.870 ;
        RECT 384.290 295.720 384.370 299.870 ;
        RECT 385.210 295.720 385.290 299.870 ;
        RECT 386.130 295.720 386.210 299.870 ;
        RECT 387.050 295.720 387.130 299.870 ;
        RECT 387.970 295.720 388.050 299.870 ;
        RECT 388.890 295.720 388.970 299.870 ;
        RECT 389.810 295.720 389.890 299.870 ;
        RECT 390.730 295.720 390.810 299.870 ;
        RECT 391.650 295.720 391.730 299.870 ;
        RECT 392.570 295.720 392.650 299.870 ;
        RECT 393.490 295.720 393.570 299.870 ;
        RECT 394.410 295.720 394.490 299.870 ;
        RECT 395.330 295.720 395.410 299.870 ;
        RECT 396.250 295.720 396.330 299.870 ;
        RECT 397.170 295.720 397.250 299.870 ;
        RECT 398.090 295.720 398.170 299.870 ;
        RECT 399.010 295.720 399.090 299.870 ;
        RECT 399.930 295.720 400.010 299.870 ;
        RECT 400.850 295.720 400.930 299.870 ;
        RECT 401.770 295.720 401.850 299.870 ;
        RECT 402.690 295.720 402.770 299.870 ;
        RECT 403.610 295.720 403.690 299.870 ;
        RECT 404.530 295.720 404.610 299.870 ;
        RECT 405.450 295.720 405.530 299.870 ;
        RECT 406.370 295.720 406.450 299.870 ;
        RECT 407.290 295.720 407.370 299.870 ;
        RECT 408.210 295.720 408.290 299.870 ;
        RECT 409.130 295.720 409.210 299.870 ;
        RECT 410.050 295.720 410.130 299.870 ;
        RECT 410.970 295.720 411.050 299.870 ;
        RECT 411.890 295.720 411.970 299.870 ;
        RECT 412.810 295.720 412.890 299.870 ;
        RECT 413.730 295.720 413.810 299.870 ;
        RECT 414.650 295.720 414.730 299.870 ;
        RECT 415.570 295.720 415.650 299.870 ;
        RECT 416.490 295.720 416.570 299.870 ;
        RECT 417.410 295.720 417.490 299.870 ;
        RECT 418.330 295.720 418.410 299.870 ;
        RECT 419.250 295.720 419.330 299.870 ;
        RECT 420.170 295.720 420.250 299.870 ;
        RECT 421.090 295.720 421.170 299.870 ;
        RECT 422.010 295.720 422.090 299.870 ;
        RECT 422.930 295.720 423.010 299.870 ;
        RECT 423.850 295.720 423.930 299.870 ;
        RECT 424.770 295.720 424.850 299.870 ;
        RECT 425.690 295.720 425.770 299.870 ;
        RECT 426.610 295.720 426.690 299.870 ;
        RECT 427.530 295.720 427.610 299.870 ;
        RECT 428.450 295.720 428.530 299.870 ;
        RECT 429.370 295.720 429.450 299.870 ;
        RECT 430.290 295.720 430.370 299.870 ;
        RECT 431.210 295.720 431.290 299.870 ;
        RECT 432.130 295.720 432.210 299.870 ;
        RECT 433.050 295.720 433.130 299.870 ;
        RECT 433.970 295.720 434.050 299.870 ;
        RECT 434.890 295.720 434.970 299.870 ;
        RECT 435.810 295.720 435.890 299.870 ;
        RECT 436.730 295.720 436.810 299.870 ;
        RECT 437.650 295.720 437.730 299.870 ;
        RECT 438.570 295.720 438.650 299.870 ;
        RECT 439.490 295.720 439.570 299.870 ;
        RECT 440.410 295.720 440.490 299.870 ;
        RECT 441.330 295.720 441.410 299.870 ;
        RECT 442.250 295.720 442.330 299.870 ;
        RECT 443.170 295.720 443.250 299.870 ;
        RECT 444.090 295.720 444.170 299.870 ;
        RECT 445.010 295.720 445.090 299.870 ;
        RECT 445.930 295.720 446.010 299.870 ;
        RECT 446.850 295.720 446.930 299.870 ;
        RECT 447.770 295.720 447.850 299.870 ;
        RECT 448.690 295.720 448.770 299.870 ;
        RECT 449.610 295.720 449.690 299.870 ;
        RECT 450.530 295.720 450.610 299.870 ;
        RECT 451.450 295.720 451.530 299.870 ;
        RECT 452.370 295.720 452.450 299.870 ;
        RECT 453.290 295.720 453.370 299.870 ;
        RECT 454.210 295.720 454.290 299.870 ;
        RECT 455.130 295.720 455.210 299.870 ;
        RECT 456.050 295.720 456.130 299.870 ;
        RECT 456.970 295.720 457.050 299.870 ;
        RECT 457.890 295.720 457.970 299.870 ;
        RECT 458.810 295.720 458.890 299.870 ;
        RECT 459.730 295.720 459.810 299.870 ;
        RECT 460.650 295.720 460.730 299.870 ;
        RECT 461.570 295.720 461.650 299.870 ;
        RECT 462.490 295.720 462.570 299.870 ;
        RECT 463.410 295.720 463.490 299.870 ;
        RECT 464.330 295.720 464.410 299.870 ;
        RECT 465.250 295.720 465.330 299.870 ;
        RECT 466.170 295.720 466.250 299.870 ;
        RECT 467.090 295.720 467.170 299.870 ;
        RECT 468.010 295.720 468.090 299.870 ;
        RECT 468.930 295.720 469.010 299.870 ;
        RECT 469.850 295.720 469.930 299.870 ;
        RECT 470.770 295.720 470.850 299.870 ;
        RECT 471.690 295.720 471.770 299.870 ;
        RECT 472.610 295.720 472.690 299.870 ;
        RECT 473.530 295.720 473.610 299.870 ;
        RECT 474.450 295.720 474.530 299.870 ;
        RECT 475.370 295.720 475.450 299.870 ;
        RECT 476.290 295.720 476.370 299.870 ;
        RECT 477.210 295.720 477.290 299.870 ;
        RECT 478.130 295.720 478.210 299.870 ;
        RECT 479.050 295.720 479.130 299.870 ;
        RECT 479.970 295.720 480.050 299.870 ;
        RECT 480.890 295.720 480.970 299.870 ;
        RECT 481.810 295.720 481.890 299.870 ;
        RECT 482.730 295.720 482.810 299.870 ;
        RECT 483.650 295.720 483.730 299.870 ;
        RECT 484.570 295.720 484.650 299.870 ;
        RECT 485.490 295.720 485.570 299.870 ;
        RECT 486.410 295.720 486.490 299.870 ;
        RECT 487.330 295.720 487.410 299.870 ;
        RECT 488.250 295.720 488.330 299.870 ;
        RECT 489.170 295.720 489.250 299.870 ;
        RECT 490.090 295.720 490.170 299.870 ;
        RECT 491.010 295.720 491.090 299.870 ;
        RECT 491.930 295.720 492.010 299.870 ;
        RECT 492.850 295.720 492.930 299.870 ;
        RECT 493.770 295.720 493.850 299.870 ;
        RECT 494.690 295.720 494.770 299.870 ;
        RECT 495.610 295.720 495.690 299.870 ;
        RECT 496.530 295.720 496.610 299.870 ;
        RECT 497.450 295.720 497.530 299.870 ;
        RECT 498.370 295.720 498.450 299.870 ;
        RECT 499.290 295.720 499.370 299.870 ;
        RECT 500.210 295.720 500.290 299.870 ;
        RECT 501.130 295.720 501.210 299.870 ;
        RECT 502.050 295.720 502.130 299.870 ;
        RECT 502.970 295.720 503.050 299.870 ;
        RECT 503.890 295.720 503.970 299.870 ;
        RECT 504.810 295.720 504.890 299.870 ;
        RECT 505.730 295.720 505.810 299.870 ;
        RECT 506.650 295.720 506.730 299.870 ;
        RECT 507.570 295.720 507.650 299.870 ;
        RECT 508.490 295.720 508.570 299.870 ;
        RECT 509.410 295.720 509.490 299.870 ;
        RECT 510.330 295.720 510.410 299.870 ;
        RECT 511.250 295.720 511.330 299.870 ;
        RECT 512.170 295.720 512.250 299.870 ;
        RECT 513.090 295.720 513.170 299.870 ;
        RECT 514.010 295.720 514.090 299.870 ;
        RECT 514.930 295.720 515.010 299.870 ;
        RECT 515.850 295.720 515.930 299.870 ;
        RECT 516.770 295.720 516.850 299.870 ;
        RECT 517.690 295.720 517.770 299.870 ;
        RECT 518.610 295.720 518.690 299.870 ;
        RECT 519.530 295.720 519.610 299.870 ;
        RECT 520.450 295.720 520.530 299.870 ;
        RECT 521.370 295.720 521.450 299.870 ;
        RECT 522.290 295.720 522.370 299.870 ;
        RECT 523.210 295.720 523.290 299.870 ;
        RECT 524.130 295.720 524.210 299.870 ;
        RECT 525.050 295.720 525.130 299.870 ;
        RECT 525.970 295.720 526.050 299.870 ;
        RECT 526.890 295.720 526.970 299.870 ;
        RECT 527.810 295.720 527.890 299.870 ;
        RECT 528.730 295.720 528.810 299.870 ;
        RECT 529.650 295.720 529.730 299.870 ;
        RECT 530.570 295.720 530.650 299.870 ;
        RECT 531.490 295.720 531.570 299.870 ;
        RECT 532.410 295.720 532.490 299.870 ;
        RECT 533.330 295.720 533.410 299.870 ;
        RECT 534.250 295.720 534.330 299.870 ;
        RECT 535.170 295.720 535.250 299.870 ;
        RECT 536.090 295.720 536.170 299.870 ;
        RECT 537.010 295.720 537.090 299.870 ;
        RECT 537.930 295.720 538.010 299.870 ;
        RECT 538.850 295.720 538.930 299.870 ;
        RECT 539.770 295.720 539.850 299.870 ;
        RECT 540.690 295.720 540.770 299.870 ;
        RECT 541.610 295.720 541.690 299.870 ;
        RECT 542.530 295.720 542.610 299.870 ;
        RECT 543.450 295.720 543.530 299.870 ;
        RECT 544.370 295.720 544.450 299.870 ;
        RECT 545.290 295.720 545.370 299.870 ;
        RECT 546.210 295.720 546.290 299.870 ;
        RECT 547.130 295.720 547.210 299.870 ;
        RECT 548.050 295.720 548.130 299.870 ;
        RECT 548.970 295.720 549.050 299.870 ;
        RECT 549.890 295.720 549.970 299.870 ;
        RECT 550.810 295.720 550.890 299.870 ;
        RECT 551.730 295.720 551.810 299.870 ;
        RECT 552.650 295.720 552.730 299.870 ;
        RECT 553.570 295.720 553.650 299.870 ;
        RECT 554.490 295.720 554.570 299.870 ;
        RECT 555.410 295.720 555.490 299.870 ;
        RECT 556.330 295.720 556.410 299.870 ;
        RECT 557.250 295.720 557.330 299.870 ;
        RECT 558.170 295.720 558.250 299.870 ;
        RECT 559.090 295.720 559.170 299.870 ;
        RECT 560.010 295.720 560.090 299.870 ;
        RECT 560.930 295.720 561.010 299.870 ;
        RECT 561.850 295.720 561.930 299.870 ;
        RECT 562.770 295.720 562.850 299.870 ;
        RECT 563.690 295.720 563.770 299.870 ;
        RECT 564.610 295.720 564.690 299.870 ;
        RECT 565.530 295.720 565.610 299.870 ;
        RECT 566.450 295.720 566.530 299.870 ;
        RECT 567.370 295.720 567.450 299.870 ;
        RECT 568.290 295.720 568.370 299.870 ;
        RECT 569.210 295.720 569.290 299.870 ;
        RECT 570.130 295.720 570.210 299.870 ;
        RECT 571.050 295.720 571.130 299.870 ;
        RECT 571.970 295.720 572.050 299.870 ;
        RECT 572.890 295.720 572.970 299.870 ;
        RECT 573.810 295.720 573.890 299.870 ;
        RECT 574.730 295.720 574.810 299.870 ;
        RECT 575.650 295.720 575.730 299.870 ;
        RECT 576.570 295.720 576.650 299.870 ;
        RECT 577.490 295.720 577.570 299.870 ;
        RECT 578.410 295.720 578.490 299.870 ;
        RECT 579.330 295.720 579.410 299.870 ;
        RECT 580.250 295.720 580.330 299.870 ;
        RECT 581.170 295.720 581.250 299.870 ;
        RECT 582.090 295.720 582.170 299.870 ;
        RECT 583.010 295.720 583.090 299.870 ;
        RECT 583.930 295.720 584.010 299.870 ;
        RECT 584.850 295.720 584.930 299.870 ;
        RECT 585.770 295.720 585.850 299.870 ;
        RECT 586.690 295.720 586.770 299.870 ;
        RECT 587.610 295.720 587.690 299.870 ;
        RECT 588.530 295.720 588.610 299.870 ;
        RECT 589.450 295.720 589.530 299.870 ;
        RECT 590.370 295.720 590.450 299.870 ;
        RECT 591.290 295.720 591.370 299.870 ;
        RECT 592.210 295.720 592.290 299.870 ;
        RECT 593.130 295.720 593.210 299.870 ;
        RECT 594.050 295.720 594.130 299.870 ;
        RECT 594.970 295.720 595.050 299.870 ;
        RECT 595.890 295.720 595.970 299.870 ;
        RECT 596.810 295.720 596.890 299.870 ;
        RECT 597.730 295.720 597.810 299.870 ;
        RECT 598.650 295.720 598.730 299.870 ;
        RECT 599.570 295.720 599.650 299.870 ;
        RECT 600.490 295.720 600.570 299.870 ;
        RECT 601.410 295.720 601.490 299.870 ;
        RECT 602.330 295.720 602.410 299.870 ;
        RECT 603.250 295.720 603.330 299.870 ;
        RECT 604.170 295.720 604.250 299.870 ;
        RECT 605.090 295.720 605.170 299.870 ;
        RECT 606.010 295.720 606.090 299.870 ;
        RECT 606.930 295.720 607.010 299.870 ;
        RECT 607.850 295.720 607.930 299.870 ;
        RECT 608.770 295.720 608.850 299.870 ;
        RECT 609.690 295.720 609.770 299.870 ;
        RECT 610.610 295.720 610.690 299.870 ;
        RECT 611.530 295.720 611.610 299.870 ;
        RECT 612.450 295.720 612.530 299.870 ;
        RECT 613.370 295.720 613.450 299.870 ;
        RECT 614.290 295.720 614.370 299.870 ;
        RECT 615.210 295.720 615.290 299.870 ;
        RECT 616.130 295.720 616.210 299.870 ;
        RECT 617.050 295.720 617.130 299.870 ;
        RECT 617.970 295.720 618.050 299.870 ;
        RECT 618.890 295.720 618.970 299.870 ;
        RECT 619.810 295.720 619.890 299.870 ;
        RECT 620.730 295.720 620.810 299.870 ;
        RECT 621.650 295.720 621.730 299.870 ;
        RECT 622.570 295.720 622.650 299.870 ;
        RECT 623.490 295.720 623.570 299.870 ;
        RECT 624.410 295.720 624.490 299.870 ;
        RECT 625.330 295.720 625.410 299.870 ;
        RECT 626.250 295.720 626.330 299.870 ;
        RECT 627.170 295.720 627.250 299.870 ;
        RECT 628.090 295.720 628.170 299.870 ;
        RECT 629.010 295.720 629.090 299.870 ;
        RECT 629.930 295.720 630.010 299.870 ;
        RECT 630.850 295.720 630.930 299.870 ;
        RECT 631.770 295.720 631.850 299.870 ;
        RECT 632.690 295.720 632.770 299.870 ;
        RECT 633.610 295.720 633.690 299.870 ;
        RECT 634.530 295.720 634.610 299.870 ;
        RECT 635.450 295.720 635.530 299.870 ;
        RECT 636.370 295.720 636.450 299.870 ;
        RECT 637.290 295.720 637.370 299.870 ;
        RECT 638.210 295.720 638.290 299.870 ;
        RECT 639.130 295.720 639.210 299.870 ;
        RECT 640.050 295.720 640.130 299.870 ;
        RECT 640.970 295.720 641.050 299.870 ;
        RECT 641.890 295.720 641.970 299.870 ;
        RECT 642.810 295.720 642.890 299.870 ;
        RECT 643.730 295.720 643.810 299.870 ;
        RECT 644.650 295.720 644.730 299.870 ;
        RECT 645.570 295.720 645.650 299.870 ;
        RECT 646.490 295.720 646.570 299.870 ;
        RECT 647.410 295.720 647.490 299.870 ;
        RECT 648.330 295.720 648.410 299.870 ;
        RECT 649.250 295.720 649.330 299.870 ;
        RECT 650.170 295.720 650.250 299.870 ;
        RECT 651.090 295.720 651.170 299.870 ;
        RECT 652.010 295.720 652.090 299.870 ;
        RECT 652.930 295.720 653.010 299.870 ;
        RECT 653.850 295.720 653.930 299.870 ;
        RECT 654.770 295.720 654.850 299.870 ;
        RECT 655.690 295.720 655.770 299.870 ;
        RECT 656.610 295.720 656.690 299.870 ;
        RECT 657.530 295.720 657.610 299.870 ;
        RECT 658.450 295.720 658.530 299.870 ;
        RECT 659.370 295.720 659.450 299.870 ;
        RECT 660.290 295.720 660.370 299.870 ;
        RECT 661.210 295.720 661.290 299.870 ;
        RECT 662.130 295.720 662.210 299.870 ;
        RECT 663.050 295.720 663.130 299.870 ;
        RECT 663.970 295.720 664.050 299.870 ;
        RECT 664.890 295.720 664.970 299.870 ;
        RECT 665.810 295.720 665.890 299.870 ;
        RECT 666.730 295.720 666.810 299.870 ;
        RECT 667.650 295.720 667.730 299.870 ;
        RECT 668.570 295.720 668.650 299.870 ;
        RECT 669.490 295.720 669.570 299.870 ;
        RECT 670.410 295.720 670.490 299.870 ;
        RECT 671.330 295.720 671.410 299.870 ;
        RECT 672.250 295.720 672.330 299.870 ;
        RECT 673.170 295.720 673.250 299.870 ;
        RECT 674.090 295.720 674.170 299.870 ;
        RECT 675.010 295.720 675.090 299.870 ;
        RECT 675.930 295.720 676.010 299.870 ;
        RECT 676.850 295.720 676.930 299.870 ;
        RECT 677.770 295.720 677.850 299.870 ;
        RECT 678.690 295.720 678.770 299.870 ;
        RECT 679.610 295.720 679.690 299.870 ;
        RECT 680.530 295.720 680.610 299.870 ;
        RECT 681.450 295.720 681.530 299.870 ;
        RECT 682.370 295.720 682.450 299.870 ;
        RECT 683.290 295.720 683.370 299.870 ;
        RECT 684.210 295.720 684.290 299.870 ;
        RECT 685.130 295.720 685.210 299.870 ;
        RECT 686.050 295.720 686.130 299.870 ;
        RECT 686.970 295.720 687.050 299.870 ;
        RECT 687.890 295.720 687.970 299.870 ;
        RECT 688.810 295.720 688.890 299.870 ;
        RECT 689.730 295.720 689.810 299.870 ;
        RECT 690.650 295.720 690.730 299.870 ;
        RECT 691.570 295.720 691.650 299.870 ;
        RECT 692.490 295.720 692.570 299.870 ;
        RECT 693.410 295.720 693.490 299.870 ;
        RECT 694.330 295.720 694.410 299.870 ;
        RECT 695.250 295.720 695.330 299.870 ;
        RECT 696.170 295.720 696.250 299.870 ;
        RECT 697.090 295.720 697.170 299.870 ;
        RECT 698.010 295.720 698.090 299.870 ;
        RECT 698.930 295.720 699.010 299.870 ;
        RECT 699.850 295.720 699.930 299.870 ;
        RECT 700.770 295.720 700.850 299.870 ;
        RECT 701.690 295.720 701.770 299.870 ;
        RECT 702.610 295.720 702.690 299.870 ;
        RECT 703.530 295.720 703.610 299.870 ;
        RECT 704.450 295.720 704.530 299.870 ;
        RECT 705.370 295.720 705.450 299.870 ;
        RECT 706.290 295.720 706.370 299.870 ;
        RECT 707.210 295.720 707.290 299.870 ;
        RECT 708.130 295.720 708.210 299.870 ;
        RECT 709.050 295.720 709.130 299.870 ;
        RECT 709.970 295.720 710.050 299.870 ;
        RECT 710.890 295.720 710.970 299.870 ;
        RECT 711.810 295.720 711.890 299.870 ;
        RECT 712.730 295.720 712.810 299.870 ;
        RECT 713.650 295.720 713.730 299.870 ;
        RECT 714.570 295.720 714.650 299.870 ;
        RECT 715.490 295.720 715.570 299.870 ;
        RECT 716.410 295.720 716.490 299.870 ;
        RECT 717.330 295.720 717.410 299.870 ;
        RECT 718.250 295.720 718.330 299.870 ;
        RECT 719.170 295.720 719.250 299.870 ;
        RECT 720.090 295.720 720.170 299.870 ;
        RECT 721.010 295.720 721.090 299.870 ;
        RECT 721.930 295.720 722.010 299.870 ;
        RECT 722.850 295.720 722.930 299.870 ;
        RECT 723.770 295.720 723.850 299.870 ;
        RECT 724.690 295.720 724.770 299.870 ;
        RECT 725.610 295.720 725.690 299.870 ;
        RECT 726.530 295.720 726.610 299.870 ;
        RECT 727.450 295.720 727.530 299.870 ;
        RECT 728.370 295.720 728.450 299.870 ;
        RECT 729.290 295.720 729.370 299.870 ;
        RECT 730.210 295.720 730.290 299.870 ;
        RECT 731.130 295.720 731.210 299.870 ;
        RECT 732.050 295.720 732.130 299.870 ;
        RECT 732.970 295.720 733.050 299.870 ;
        RECT 733.890 295.720 733.970 299.870 ;
        RECT 734.810 295.720 734.890 299.870 ;
        RECT 735.730 295.720 735.810 299.870 ;
        RECT 736.650 295.720 736.730 299.870 ;
        RECT 737.570 295.720 737.650 299.870 ;
        RECT 738.490 295.720 738.570 299.870 ;
        RECT 739.410 295.720 739.490 299.870 ;
        RECT 740.330 295.720 740.410 299.870 ;
        RECT 741.250 295.720 741.330 299.870 ;
        RECT 742.170 295.720 742.250 299.870 ;
        RECT 743.090 295.720 743.170 299.870 ;
        RECT 744.010 295.720 744.090 299.870 ;
        RECT 744.930 295.720 745.010 299.870 ;
        RECT 745.850 295.720 745.930 299.870 ;
        RECT 746.770 295.720 746.850 299.870 ;
        RECT 747.690 295.720 747.770 299.870 ;
        RECT 748.610 295.720 748.690 299.870 ;
        RECT 749.530 295.720 749.610 299.870 ;
        RECT 750.450 295.720 750.530 299.870 ;
        RECT 751.370 295.720 751.450 299.870 ;
        RECT 752.290 295.720 752.370 299.870 ;
        RECT 753.210 295.720 753.290 299.870 ;
        RECT 754.130 295.720 754.210 299.870 ;
        RECT 755.050 295.720 755.130 299.870 ;
        RECT 755.970 295.720 756.050 299.870 ;
        RECT 756.890 295.720 756.970 299.870 ;
        RECT 757.810 295.720 757.890 299.870 ;
        RECT 758.730 295.720 758.810 299.870 ;
        RECT 759.650 295.720 759.730 299.870 ;
        RECT 760.570 295.720 760.650 299.870 ;
        RECT 761.490 295.720 761.570 299.870 ;
        RECT 762.410 295.720 762.490 299.870 ;
        RECT 763.330 295.720 763.410 299.870 ;
        RECT 764.250 295.720 764.330 299.870 ;
        RECT 765.170 295.720 765.250 299.870 ;
        RECT 766.090 295.720 766.170 299.870 ;
        RECT 767.010 295.720 767.090 299.870 ;
        RECT 767.930 295.720 768.010 299.870 ;
        RECT 768.850 295.720 768.930 299.870 ;
        RECT 769.770 295.720 769.850 299.870 ;
        RECT 770.690 295.720 770.770 299.870 ;
        RECT 771.610 295.720 771.690 299.870 ;
        RECT 772.530 295.720 772.610 299.870 ;
        RECT 773.450 295.720 773.530 299.870 ;
        RECT 774.370 295.720 774.450 299.870 ;
        RECT 775.290 295.720 775.370 299.870 ;
        RECT 776.210 295.720 776.290 299.870 ;
        RECT 777.130 295.720 777.210 299.870 ;
        RECT 778.050 295.720 778.130 299.870 ;
        RECT 778.970 295.720 779.050 299.870 ;
        RECT 779.890 295.720 779.970 299.870 ;
        RECT 780.810 295.720 780.890 299.870 ;
        RECT 781.730 295.720 781.810 299.870 ;
        RECT 782.650 295.720 782.730 299.870 ;
        RECT 783.570 295.720 783.650 299.870 ;
        RECT 784.490 295.720 784.570 299.870 ;
        RECT 785.410 295.720 785.490 299.870 ;
        RECT 786.330 295.720 786.410 299.870 ;
        RECT 787.250 295.720 787.330 299.870 ;
        RECT 788.170 295.720 788.250 299.870 ;
        RECT 789.090 295.720 789.170 299.870 ;
        RECT 790.010 295.720 790.090 299.870 ;
        RECT 790.930 295.720 791.010 299.870 ;
        RECT 791.850 295.720 791.930 299.870 ;
        RECT 792.770 295.720 792.850 299.870 ;
        RECT 793.690 295.720 793.770 299.870 ;
        RECT 794.610 295.720 794.690 299.870 ;
        RECT 795.530 295.720 795.610 299.870 ;
        RECT 796.450 295.720 796.530 299.870 ;
        RECT 797.370 295.720 797.450 299.870 ;
        RECT 798.290 295.720 798.370 299.870 ;
        RECT 799.210 295.720 799.290 299.870 ;
        RECT 800.130 295.720 800.210 299.870 ;
        RECT 801.050 295.720 801.130 299.870 ;
        RECT 801.970 295.720 802.050 299.870 ;
        RECT 802.890 295.720 802.970 299.870 ;
        RECT 803.810 295.720 803.890 299.870 ;
        RECT 804.730 295.720 804.810 299.870 ;
        RECT 805.650 295.720 805.730 299.870 ;
        RECT 806.570 295.720 806.650 299.870 ;
        RECT 807.490 295.720 807.570 299.870 ;
        RECT 808.410 295.720 808.490 299.870 ;
        RECT 809.330 295.720 809.410 299.870 ;
        RECT 810.250 295.720 810.330 299.870 ;
        RECT 811.170 295.720 811.250 299.870 ;
        RECT 812.090 295.720 812.170 299.870 ;
        RECT 813.010 295.720 813.090 299.870 ;
        RECT 813.930 295.720 814.010 299.870 ;
        RECT 814.850 295.720 814.930 299.870 ;
        RECT 815.770 295.720 815.850 299.870 ;
        RECT 816.690 295.720 816.770 299.870 ;
        RECT 817.610 295.720 817.690 299.870 ;
        RECT 818.530 295.720 818.610 299.870 ;
        RECT 819.450 295.720 819.530 299.870 ;
        RECT 820.370 295.720 820.450 299.870 ;
        RECT 821.290 295.720 821.370 299.870 ;
        RECT 822.210 295.720 822.290 299.870 ;
        RECT 823.130 295.720 823.210 299.870 ;
        RECT 824.050 295.720 824.130 299.870 ;
        RECT 824.970 295.720 825.050 299.870 ;
        RECT 825.890 295.720 825.970 299.870 ;
        RECT 826.810 295.720 826.890 299.870 ;
        RECT 827.730 295.720 827.810 299.870 ;
        RECT 828.650 295.720 828.730 299.870 ;
        RECT 829.570 295.720 829.650 299.870 ;
        RECT 830.490 295.720 830.570 299.870 ;
        RECT 831.410 295.720 831.490 299.870 ;
        RECT 832.330 295.720 832.410 299.870 ;
        RECT 833.250 295.720 833.330 299.870 ;
        RECT 834.170 295.720 834.250 299.870 ;
        RECT 835.090 295.720 835.170 299.870 ;
        RECT 836.010 295.720 836.090 299.870 ;
        RECT 836.930 295.720 837.010 299.870 ;
        RECT 837.850 295.720 837.930 299.870 ;
        RECT 838.770 295.720 838.850 299.870 ;
        RECT 839.690 295.720 839.770 299.870 ;
        RECT 840.610 295.720 840.690 299.870 ;
        RECT 841.530 295.720 841.610 299.870 ;
        RECT 842.450 295.720 842.530 299.870 ;
        RECT 843.370 295.720 843.450 299.870 ;
        RECT 844.290 295.720 844.370 299.870 ;
        RECT 845.210 295.720 845.290 299.870 ;
        RECT 846.130 295.720 846.210 299.870 ;
        RECT 847.050 295.720 847.130 299.870 ;
        RECT 847.970 295.720 848.050 299.870 ;
        RECT 848.890 295.720 848.970 299.870 ;
        RECT 849.810 295.720 849.890 299.870 ;
        RECT 850.730 295.720 850.810 299.870 ;
        RECT 851.650 295.720 851.730 299.870 ;
        RECT 852.570 295.720 852.650 299.870 ;
        RECT 853.490 295.720 853.570 299.870 ;
        RECT 854.410 295.720 854.490 299.870 ;
        RECT 855.330 295.720 855.410 299.870 ;
        RECT 856.250 295.720 856.330 299.870 ;
        RECT 857.170 295.720 857.250 299.870 ;
        RECT 858.090 295.720 858.170 299.870 ;
        RECT 859.010 295.720 859.090 299.870 ;
        RECT 859.930 295.720 860.010 299.870 ;
        RECT 860.850 295.720 860.930 299.870 ;
        RECT 861.770 295.720 861.850 299.870 ;
        RECT 862.690 295.720 862.770 299.870 ;
        RECT 863.610 295.720 863.690 299.870 ;
        RECT 864.530 295.720 864.610 299.870 ;
        RECT 865.450 295.720 865.530 299.870 ;
        RECT 866.370 295.720 866.450 299.870 ;
        RECT 867.290 295.720 867.370 299.870 ;
        RECT 868.210 295.720 868.290 299.870 ;
        RECT 869.130 295.720 869.210 299.870 ;
        RECT 870.050 295.720 870.130 299.870 ;
        RECT 870.970 295.720 871.050 299.870 ;
        RECT 871.890 295.720 871.970 299.870 ;
        RECT 872.810 295.720 872.890 299.870 ;
        RECT 873.730 295.720 873.810 299.870 ;
        RECT 874.650 295.720 874.730 299.870 ;
        RECT 875.570 295.720 875.650 299.870 ;
        RECT 876.490 295.720 876.570 299.870 ;
        RECT 877.410 295.720 877.490 299.870 ;
        RECT 878.330 295.720 878.410 299.870 ;
        RECT 879.250 295.720 879.330 299.870 ;
        RECT 880.170 295.720 880.250 299.870 ;
        RECT 881.090 295.720 881.170 299.870 ;
        RECT 882.010 295.720 882.090 299.870 ;
        RECT 882.930 295.720 883.010 299.870 ;
        RECT 883.850 295.720 883.930 299.870 ;
        RECT 884.770 295.720 884.850 299.870 ;
        RECT 885.690 295.720 885.770 299.870 ;
        RECT 886.610 295.720 886.690 299.870 ;
        RECT 887.530 295.720 887.610 299.870 ;
        RECT 888.450 295.720 888.530 299.870 ;
        RECT 889.370 295.720 889.450 299.870 ;
        RECT 890.290 295.720 890.370 299.870 ;
        RECT 891.210 295.720 891.290 299.870 ;
        RECT 892.130 295.720 892.210 299.870 ;
        RECT 893.050 295.720 893.130 299.870 ;
        RECT 893.970 295.720 894.050 299.870 ;
        RECT 894.890 295.720 894.970 299.870 ;
        RECT 895.810 295.720 895.890 299.870 ;
        RECT 896.730 295.720 896.810 299.870 ;
        RECT 897.650 295.720 897.730 299.870 ;
        RECT 898.570 295.720 898.650 299.870 ;
        RECT 899.490 295.720 899.570 299.870 ;
        RECT 900.410 295.720 900.490 299.870 ;
        RECT 901.330 295.720 901.410 299.870 ;
        RECT 902.250 295.720 902.330 299.870 ;
        RECT 903.170 295.720 903.250 299.870 ;
        RECT 904.090 295.720 904.170 299.870 ;
        RECT 905.010 295.720 905.090 299.870 ;
        RECT 905.930 295.720 906.010 299.870 ;
        RECT 906.850 295.720 906.930 299.870 ;
        RECT 907.770 295.720 907.850 299.870 ;
        RECT 908.690 295.720 908.770 299.870 ;
        RECT 909.610 295.720 909.690 299.870 ;
        RECT 910.530 295.720 910.610 299.870 ;
        RECT 911.450 295.720 911.530 299.870 ;
        RECT 912.370 295.720 912.450 299.870 ;
        RECT 913.290 295.720 913.370 299.870 ;
        RECT 914.210 295.720 914.290 299.870 ;
        RECT 915.130 295.720 915.210 299.870 ;
        RECT 916.050 295.720 916.130 299.870 ;
        RECT 916.970 295.720 917.050 299.870 ;
        RECT 917.890 295.720 917.970 299.870 ;
        RECT 918.810 295.720 918.890 299.870 ;
        RECT 919.730 295.720 919.810 299.870 ;
        RECT 920.650 295.720 920.730 299.870 ;
        RECT 921.570 295.720 921.650 299.870 ;
        RECT 922.490 295.720 922.570 299.870 ;
        RECT 923.410 295.720 923.490 299.870 ;
        RECT 924.330 295.720 924.410 299.870 ;
        RECT 925.250 295.720 925.330 299.870 ;
        RECT 926.170 295.720 926.250 299.870 ;
        RECT 927.090 295.720 927.170 299.870 ;
        RECT 928.010 295.720 928.090 299.870 ;
        RECT 928.930 295.720 929.010 299.870 ;
        RECT 929.850 295.720 929.930 299.870 ;
        RECT 930.770 295.720 930.850 299.870 ;
        RECT 931.690 295.720 931.770 299.870 ;
        RECT 932.610 295.720 932.690 299.870 ;
        RECT 933.530 295.720 933.610 299.870 ;
        RECT 934.450 295.720 934.530 299.870 ;
        RECT 935.370 295.720 935.450 299.870 ;
        RECT 936.290 295.720 936.370 299.870 ;
        RECT 937.210 295.720 937.290 299.870 ;
        RECT 938.130 295.720 938.210 299.870 ;
        RECT 939.050 295.720 939.130 299.870 ;
        RECT 939.970 295.720 940.050 299.870 ;
        RECT 940.890 295.720 940.970 299.870 ;
        RECT 941.810 295.720 941.890 299.870 ;
        RECT 942.730 295.720 942.810 299.870 ;
        RECT 943.650 295.720 943.730 299.870 ;
        RECT 944.570 295.720 944.650 299.870 ;
        RECT 945.490 295.720 945.570 299.870 ;
        RECT 946.410 295.720 946.490 299.870 ;
        RECT 947.330 295.720 947.410 299.870 ;
        RECT 948.250 295.720 948.330 299.870 ;
        RECT 949.170 295.720 949.250 299.870 ;
        RECT 950.090 295.720 950.170 299.870 ;
        RECT 951.010 295.720 951.090 299.870 ;
        RECT 951.930 295.720 952.010 299.870 ;
        RECT 952.850 295.720 952.930 299.870 ;
        RECT 953.770 295.720 953.850 299.870 ;
        RECT 954.690 295.720 954.770 299.870 ;
        RECT 955.610 295.720 955.690 299.870 ;
        RECT 956.530 295.720 956.610 299.870 ;
        RECT 957.450 295.720 957.530 299.870 ;
        RECT 958.370 295.720 958.450 299.870 ;
        RECT 959.290 295.720 959.370 299.870 ;
        RECT 960.210 295.720 960.290 299.870 ;
        RECT 961.130 295.720 961.210 299.870 ;
        RECT 962.050 295.720 962.130 299.870 ;
        RECT 962.970 295.720 963.050 299.870 ;
        RECT 963.890 295.720 963.970 299.870 ;
        RECT 964.810 295.720 964.890 299.870 ;
        RECT 965.730 295.720 965.810 299.870 ;
        RECT 966.650 295.720 966.730 299.870 ;
        RECT 967.570 295.720 967.650 299.870 ;
        RECT 968.490 295.720 968.570 299.870 ;
        RECT 969.410 295.720 969.490 299.870 ;
        RECT 970.330 295.720 970.410 299.870 ;
        RECT 971.250 295.720 971.330 299.870 ;
        RECT 972.170 295.720 972.250 299.870 ;
        RECT 973.090 295.720 973.170 299.870 ;
        RECT 974.010 295.720 974.090 299.870 ;
        RECT 974.930 295.720 975.010 299.870 ;
        RECT 975.850 295.720 975.930 299.870 ;
        RECT 976.770 295.720 976.850 299.870 ;
        RECT 977.690 295.720 977.770 299.870 ;
        RECT 978.610 295.720 978.690 299.870 ;
        RECT 979.530 295.720 979.610 299.870 ;
        RECT 980.450 295.720 980.530 299.870 ;
        RECT 981.370 295.720 981.450 299.870 ;
        RECT 982.290 295.720 982.370 299.870 ;
        RECT 983.210 295.720 983.290 299.870 ;
        RECT 984.130 295.720 984.210 299.870 ;
        RECT 985.050 295.720 985.130 299.870 ;
        RECT 985.970 295.720 986.050 299.870 ;
        RECT 986.890 295.720 986.970 299.870 ;
        RECT 987.810 295.720 987.890 299.870 ;
        RECT 988.730 295.720 988.810 299.870 ;
        RECT 989.650 295.720 989.730 299.870 ;
        RECT 990.570 295.720 990.650 299.870 ;
        RECT 991.490 295.720 991.570 299.870 ;
        RECT 992.410 295.720 992.490 299.870 ;
        RECT 993.330 295.720 993.410 299.870 ;
        RECT 994.250 295.720 994.330 299.870 ;
        RECT 995.170 295.720 995.250 299.870 ;
        RECT 996.090 295.720 996.170 299.870 ;
        RECT 997.010 295.720 997.090 299.870 ;
        RECT 997.930 295.720 998.010 299.870 ;
        RECT 998.850 295.720 998.930 299.870 ;
        RECT 999.770 295.720 999.850 299.870 ;
        RECT 1000.690 295.720 1000.770 299.870 ;
        RECT 1001.610 295.720 1001.690 299.870 ;
        RECT 1002.530 295.720 1002.610 299.870 ;
        RECT 1003.450 295.720 1003.530 299.870 ;
        RECT 1004.370 295.720 1004.450 299.870 ;
        RECT 1005.290 295.720 1005.370 299.870 ;
        RECT 1006.210 295.720 1006.290 299.870 ;
        RECT 1007.130 295.720 1007.210 299.870 ;
        RECT 1008.050 295.720 1008.130 299.870 ;
        RECT 1008.970 295.720 1009.050 299.870 ;
        RECT 1009.890 295.720 1009.970 299.870 ;
        RECT 1010.810 295.720 1010.890 299.870 ;
        RECT 1011.730 295.720 1011.810 299.870 ;
        RECT 1012.650 295.720 1012.730 299.870 ;
        RECT 1013.570 295.720 1013.650 299.870 ;
        RECT 1014.490 295.720 1014.570 299.870 ;
        RECT 1015.410 295.720 1015.490 299.870 ;
        RECT 1016.330 295.720 1016.410 299.870 ;
        RECT 1017.250 295.720 1017.330 299.870 ;
        RECT 1018.170 295.720 1018.250 299.870 ;
        RECT 1019.090 295.720 1019.170 299.870 ;
        RECT 1020.010 295.720 1020.090 299.870 ;
        RECT 1020.930 295.720 1021.010 299.870 ;
        RECT 1021.850 295.720 1021.930 299.870 ;
        RECT 1022.770 295.720 1022.850 299.870 ;
        RECT 1023.690 295.720 1023.770 299.870 ;
        RECT 1024.610 295.720 1024.690 299.870 ;
        RECT 1025.530 295.720 1025.610 299.870 ;
        RECT 1026.450 295.720 1026.530 299.870 ;
        RECT 1027.370 295.720 1027.450 299.870 ;
        RECT 1028.290 295.720 1028.370 299.870 ;
        RECT 1029.210 295.720 1029.290 299.870 ;
        RECT 1030.130 295.720 1030.210 299.870 ;
        RECT 1031.050 295.720 1031.130 299.870 ;
        RECT 1031.970 295.720 1032.050 299.870 ;
        RECT 1032.890 295.720 1032.970 299.870 ;
        RECT 1033.810 295.720 1033.890 299.870 ;
        RECT 1034.730 295.720 1034.810 299.870 ;
        RECT 1035.650 295.720 1035.730 299.870 ;
        RECT 1036.570 295.720 1036.650 299.870 ;
        RECT 1037.490 295.720 1037.570 299.870 ;
        RECT 1038.410 295.720 1038.490 299.870 ;
        RECT 1039.330 295.720 1039.410 299.870 ;
        RECT 1040.250 295.720 1040.330 299.870 ;
        RECT 1041.170 295.720 1041.250 299.870 ;
        RECT 1042.090 295.720 1042.170 299.870 ;
        RECT 1043.010 295.720 1043.090 299.870 ;
        RECT 1043.930 295.720 1044.010 299.870 ;
        RECT 1044.850 295.720 1044.930 299.870 ;
        RECT 1045.770 295.720 1045.850 299.870 ;
        RECT 1046.690 295.720 1046.770 299.870 ;
        RECT 1047.610 295.720 1047.690 299.870 ;
        RECT 1048.530 295.720 1048.610 299.870 ;
        RECT 1049.450 295.720 1049.530 299.870 ;
        RECT 1050.370 295.720 1050.450 299.870 ;
        RECT 1051.290 295.720 1051.370 299.870 ;
        RECT 1052.210 295.720 1052.290 299.870 ;
        RECT 1053.130 295.720 1053.210 299.870 ;
        RECT 1054.050 295.720 1054.130 299.870 ;
        RECT 1054.970 295.720 1055.050 299.870 ;
        RECT 1055.890 295.720 1055.970 299.870 ;
        RECT 1056.810 295.720 1056.890 299.870 ;
        RECT 1057.730 295.720 1057.810 299.870 ;
        RECT 1058.650 295.720 1058.730 299.870 ;
        RECT 1059.570 295.720 1059.650 299.870 ;
        RECT 1060.490 295.720 1060.570 299.870 ;
        RECT 1061.410 295.720 1061.490 299.870 ;
        RECT 1062.330 295.720 1062.410 299.870 ;
        RECT 1063.250 295.720 1063.330 299.870 ;
        RECT 1064.170 295.720 1064.250 299.870 ;
        RECT 1065.090 295.720 1065.170 299.870 ;
        RECT 1066.010 295.720 1066.090 299.870 ;
        RECT 1066.930 295.720 1067.010 299.870 ;
        RECT 1067.850 295.720 1067.930 299.870 ;
        RECT 1068.770 295.720 1068.850 299.870 ;
        RECT 1069.690 295.720 1069.770 299.870 ;
        RECT 1070.610 295.720 1070.690 299.870 ;
        RECT 1071.530 295.720 1071.610 299.870 ;
        RECT 1072.450 295.720 1072.530 299.870 ;
        RECT 1073.370 295.720 1073.450 299.870 ;
        RECT 1074.290 295.720 1074.370 299.870 ;
        RECT 1075.210 295.720 1075.290 299.870 ;
        RECT 1076.130 295.720 1076.210 299.870 ;
        RECT 1077.050 295.720 1077.130 299.870 ;
        RECT 1077.970 295.720 1078.050 299.870 ;
        RECT 1078.890 295.720 1078.970 299.870 ;
        RECT 1079.810 295.720 1079.890 299.870 ;
        RECT 1080.730 295.720 1080.810 299.870 ;
        RECT 1081.650 295.720 1081.730 299.870 ;
        RECT 1082.570 295.720 1082.650 299.870 ;
        RECT 1083.490 295.720 1083.570 299.870 ;
        RECT 1084.410 295.720 1084.490 299.870 ;
        RECT 1085.330 295.720 1085.410 299.870 ;
        RECT 1086.250 295.720 1086.330 299.870 ;
        RECT 1087.170 295.720 1087.250 299.870 ;
        RECT 1088.090 295.720 1088.170 299.870 ;
        RECT 1089.010 295.720 1089.090 299.870 ;
        RECT 1089.930 295.720 1090.010 299.870 ;
        RECT 1090.850 295.720 1090.930 299.870 ;
        RECT 1091.770 295.720 1091.850 299.870 ;
        RECT 1092.690 295.720 1092.770 299.870 ;
        RECT 1093.610 295.720 1093.690 299.870 ;
        RECT 1094.530 295.720 1094.610 299.870 ;
        RECT 1095.450 295.720 1095.530 299.870 ;
        RECT 1096.370 295.720 1096.450 299.870 ;
        RECT 1097.290 295.720 1097.370 299.870 ;
        RECT 1098.210 295.720 1098.290 299.870 ;
        RECT 1099.130 295.720 1099.210 299.870 ;
        RECT 1100.050 295.720 1100.130 299.870 ;
        RECT 1100.970 295.720 1101.050 299.870 ;
        RECT 1101.890 295.720 1101.970 299.870 ;
        RECT 1102.810 295.720 1102.890 299.870 ;
        RECT 1103.730 295.720 1103.810 299.870 ;
        RECT 1104.650 295.720 1104.730 299.870 ;
        RECT 1105.570 295.720 1105.650 299.870 ;
        RECT 1106.490 295.720 1106.570 299.870 ;
        RECT 1107.410 295.720 1107.490 299.870 ;
        RECT 1108.330 295.720 1108.410 299.870 ;
        RECT 1109.250 295.720 1109.330 299.870 ;
        RECT 1110.170 295.720 1110.250 299.870 ;
        RECT 1111.090 295.720 1111.170 299.870 ;
        RECT 1112.010 295.720 1112.090 299.870 ;
        RECT 1112.930 295.720 1113.010 299.870 ;
        RECT 1113.850 295.720 1113.930 299.870 ;
        RECT 1114.770 295.720 1114.850 299.870 ;
        RECT 1115.690 295.720 1115.770 299.870 ;
        RECT 1116.610 295.720 1116.690 299.870 ;
        RECT 1117.530 295.720 1117.610 299.870 ;
        RECT 1118.450 295.720 1118.530 299.870 ;
        RECT 1119.370 295.720 1119.450 299.870 ;
        RECT 1120.290 295.720 1120.370 299.870 ;
        RECT 1121.210 295.720 1121.290 299.870 ;
        RECT 1122.130 295.720 1122.210 299.870 ;
        RECT 1123.050 295.720 1123.130 299.870 ;
        RECT 1123.970 295.720 1124.050 299.870 ;
        RECT 1124.890 295.720 1124.970 299.870 ;
        RECT 1125.810 295.720 1125.890 299.870 ;
        RECT 1126.730 295.720 1126.810 299.870 ;
        RECT 1127.650 295.720 1127.730 299.870 ;
        RECT 1128.570 295.720 1128.650 299.870 ;
        RECT 1129.490 295.720 1129.570 299.870 ;
        RECT 1130.410 295.720 1130.490 299.870 ;
        RECT 1131.330 295.720 1194.070 299.870 ;
        RECT 7.920 4.280 1194.070 295.720 ;
        RECT 7.920 3.670 25.570 4.280 ;
        RECT 26.410 3.670 36.610 4.280 ;
        RECT 37.450 3.670 47.650 4.280 ;
        RECT 48.490 3.670 58.690 4.280 ;
        RECT 59.530 3.670 69.730 4.280 ;
        RECT 70.570 3.670 80.770 4.280 ;
        RECT 81.610 3.670 91.810 4.280 ;
        RECT 92.650 3.670 102.850 4.280 ;
        RECT 103.690 3.670 113.890 4.280 ;
        RECT 114.730 3.670 124.930 4.280 ;
        RECT 125.770 3.670 135.970 4.280 ;
        RECT 136.810 3.670 147.010 4.280 ;
        RECT 147.850 3.670 158.050 4.280 ;
        RECT 158.890 3.670 169.090 4.280 ;
        RECT 169.930 3.670 180.130 4.280 ;
        RECT 180.970 3.670 191.170 4.280 ;
        RECT 192.010 3.670 202.210 4.280 ;
        RECT 203.050 3.670 213.250 4.280 ;
        RECT 214.090 3.670 224.290 4.280 ;
        RECT 225.130 3.670 235.330 4.280 ;
        RECT 236.170 3.670 246.370 4.280 ;
        RECT 247.210 3.670 257.410 4.280 ;
        RECT 258.250 3.670 268.450 4.280 ;
        RECT 269.290 3.670 279.490 4.280 ;
        RECT 280.330 3.670 290.530 4.280 ;
        RECT 291.370 3.670 301.570 4.280 ;
        RECT 302.410 3.670 312.610 4.280 ;
        RECT 313.450 3.670 323.650 4.280 ;
        RECT 324.490 3.670 334.690 4.280 ;
        RECT 335.530 3.670 345.730 4.280 ;
        RECT 346.570 3.670 356.770 4.280 ;
        RECT 357.610 3.670 367.810 4.280 ;
        RECT 368.650 3.670 378.850 4.280 ;
        RECT 379.690 3.670 389.890 4.280 ;
        RECT 390.730 3.670 400.930 4.280 ;
        RECT 401.770 3.670 411.970 4.280 ;
        RECT 412.810 3.670 423.010 4.280 ;
        RECT 423.850 3.670 434.050 4.280 ;
        RECT 434.890 3.670 445.090 4.280 ;
        RECT 445.930 3.670 456.130 4.280 ;
        RECT 456.970 3.670 467.170 4.280 ;
        RECT 468.010 3.670 478.210 4.280 ;
        RECT 479.050 3.670 489.250 4.280 ;
        RECT 490.090 3.670 500.290 4.280 ;
        RECT 501.130 3.670 511.330 4.280 ;
        RECT 512.170 3.670 522.370 4.280 ;
        RECT 523.210 3.670 533.410 4.280 ;
        RECT 534.250 3.670 544.450 4.280 ;
        RECT 545.290 3.670 555.490 4.280 ;
        RECT 556.330 3.670 566.530 4.280 ;
        RECT 567.370 3.670 577.570 4.280 ;
        RECT 578.410 3.670 588.610 4.280 ;
        RECT 589.450 3.670 599.650 4.280 ;
        RECT 600.490 3.670 610.690 4.280 ;
        RECT 611.530 3.670 621.730 4.280 ;
        RECT 622.570 3.670 632.770 4.280 ;
        RECT 633.610 3.670 643.810 4.280 ;
        RECT 644.650 3.670 654.850 4.280 ;
        RECT 655.690 3.670 665.890 4.280 ;
        RECT 666.730 3.670 676.930 4.280 ;
        RECT 677.770 3.670 687.970 4.280 ;
        RECT 688.810 3.670 699.010 4.280 ;
        RECT 699.850 3.670 710.050 4.280 ;
        RECT 710.890 3.670 721.090 4.280 ;
        RECT 721.930 3.670 732.130 4.280 ;
        RECT 732.970 3.670 743.170 4.280 ;
        RECT 744.010 3.670 754.210 4.280 ;
        RECT 755.050 3.670 765.250 4.280 ;
        RECT 766.090 3.670 776.290 4.280 ;
        RECT 777.130 3.670 787.330 4.280 ;
        RECT 788.170 3.670 798.370 4.280 ;
        RECT 799.210 3.670 809.410 4.280 ;
        RECT 810.250 3.670 820.450 4.280 ;
        RECT 821.290 3.670 831.490 4.280 ;
        RECT 832.330 3.670 842.530 4.280 ;
        RECT 843.370 3.670 853.570 4.280 ;
        RECT 854.410 3.670 864.610 4.280 ;
        RECT 865.450 3.670 875.650 4.280 ;
        RECT 876.490 3.670 886.690 4.280 ;
        RECT 887.530 3.670 897.730 4.280 ;
        RECT 898.570 3.670 908.770 4.280 ;
        RECT 909.610 3.670 919.810 4.280 ;
        RECT 920.650 3.670 930.850 4.280 ;
        RECT 931.690 3.670 941.890 4.280 ;
        RECT 942.730 3.670 952.930 4.280 ;
        RECT 953.770 3.670 963.970 4.280 ;
        RECT 964.810 3.670 975.010 4.280 ;
        RECT 975.850 3.670 986.050 4.280 ;
        RECT 986.890 3.670 997.090 4.280 ;
        RECT 997.930 3.670 1008.130 4.280 ;
        RECT 1008.970 3.670 1019.170 4.280 ;
        RECT 1020.010 3.670 1030.210 4.280 ;
        RECT 1031.050 3.670 1041.250 4.280 ;
        RECT 1042.090 3.670 1052.290 4.280 ;
        RECT 1053.130 3.670 1063.330 4.280 ;
        RECT 1064.170 3.670 1074.370 4.280 ;
        RECT 1075.210 3.670 1085.410 4.280 ;
        RECT 1086.250 3.670 1096.450 4.280 ;
        RECT 1097.290 3.670 1107.490 4.280 ;
        RECT 1108.330 3.670 1118.530 4.280 ;
        RECT 1119.370 3.670 1129.570 4.280 ;
        RECT 1130.410 3.670 1140.610 4.280 ;
        RECT 1141.450 3.670 1151.650 4.280 ;
        RECT 1152.490 3.670 1162.690 4.280 ;
        RECT 1163.530 3.670 1173.730 4.280 ;
        RECT 1174.570 3.670 1194.070 4.280 ;
      LAYER met3 ;
        RECT 20.305 286.640 1196.000 299.705 ;
        RECT 20.305 285.240 1195.600 286.640 ;
        RECT 20.305 259.440 1196.000 285.240 ;
        RECT 20.305 258.040 1195.600 259.440 ;
        RECT 20.305 232.240 1196.000 258.040 ;
        RECT 20.305 230.840 1195.600 232.240 ;
        RECT 20.305 205.040 1196.000 230.840 ;
        RECT 20.305 203.640 1195.600 205.040 ;
        RECT 20.305 177.840 1196.000 203.640 ;
        RECT 20.305 176.440 1195.600 177.840 ;
        RECT 20.305 150.640 1196.000 176.440 ;
        RECT 20.305 149.240 1195.600 150.640 ;
        RECT 20.305 123.440 1196.000 149.240 ;
        RECT 20.305 122.040 1195.600 123.440 ;
        RECT 20.305 96.240 1196.000 122.040 ;
        RECT 20.305 94.840 1195.600 96.240 ;
        RECT 20.305 69.040 1196.000 94.840 ;
        RECT 20.305 67.640 1195.600 69.040 ;
        RECT 20.305 41.840 1196.000 67.640 ;
        RECT 20.305 40.440 1195.600 41.840 ;
        RECT 20.305 14.640 1196.000 40.440 ;
        RECT 20.305 13.240 1195.600 14.640 ;
        RECT 20.305 10.715 1196.000 13.240 ;
      LAYER met4 ;
        RECT 80.335 288.960 1131.305 299.705 ;
        RECT 80.335 16.495 97.440 288.960 ;
        RECT 99.840 16.495 174.240 288.960 ;
        RECT 176.640 16.495 251.040 288.960 ;
        RECT 253.440 16.495 327.840 288.960 ;
        RECT 330.240 16.495 404.640 288.960 ;
        RECT 407.040 16.495 481.440 288.960 ;
        RECT 483.840 16.495 558.240 288.960 ;
        RECT 560.640 16.495 635.040 288.960 ;
        RECT 637.440 16.495 711.840 288.960 ;
        RECT 714.240 16.495 788.640 288.960 ;
        RECT 791.040 16.495 865.440 288.960 ;
        RECT 867.840 16.495 942.240 288.960 ;
        RECT 944.640 16.495 1019.040 288.960 ;
        RECT 1021.440 16.495 1095.840 288.960 ;
        RECT 1098.240 16.495 1131.305 288.960 ;
  END
END pre_rasterizer_m
END LIBRARY

